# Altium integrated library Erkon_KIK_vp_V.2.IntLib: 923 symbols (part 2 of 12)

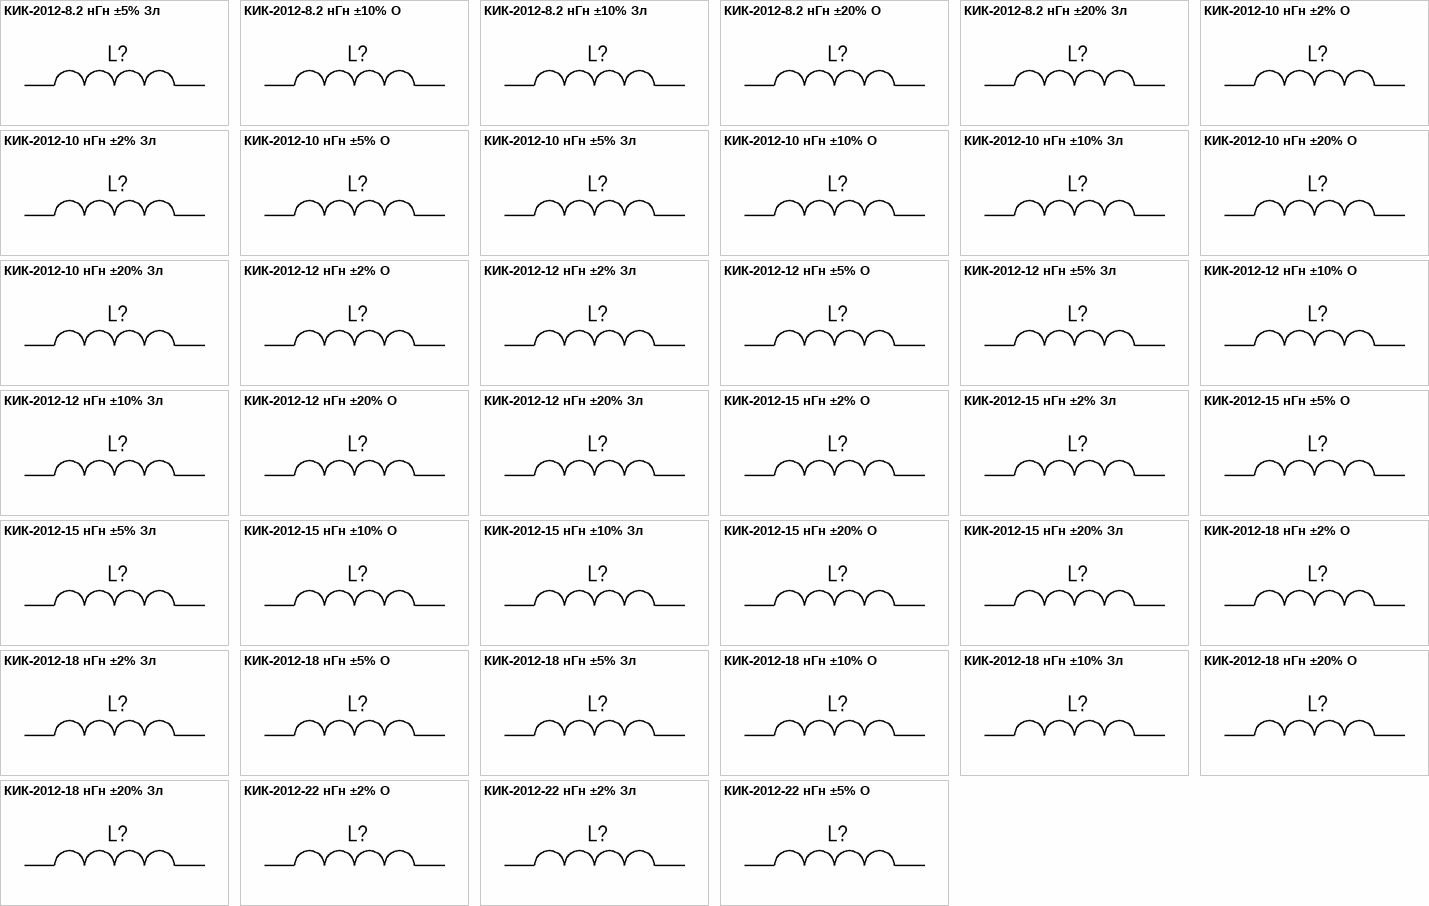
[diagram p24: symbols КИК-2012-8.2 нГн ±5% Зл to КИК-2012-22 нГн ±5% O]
## КИК-2012-22 нГн ±5% O
designator L?, comment 22 нГн ±5%  (value not drawn)
Катушка индуктивности с керамическим сердечником и  финишным покрытием контактных площадок оловом; Номиналиная индуктивность: 22 нГн; Добротность, не менее: 50; Резонансная частота, не менее: 2.60 ГГц; Сопротивление обмотки постоянноми току, не более: 0.22 Ом; Допустимый ток обмотки: 500 мА; Диапазон рабочих температур: от -60 до +125 ℃; Упаковка: Катушка и лента; Типоразмер: 2012 (0805); Технология монтажа: SMT; Изготовитель: АО "НПО "ЭРКОН"
footprint КИК-2012-O (Катушка индуктивности с керамическим сердечником типоразмер 2012(0805))
pins: 1, 2


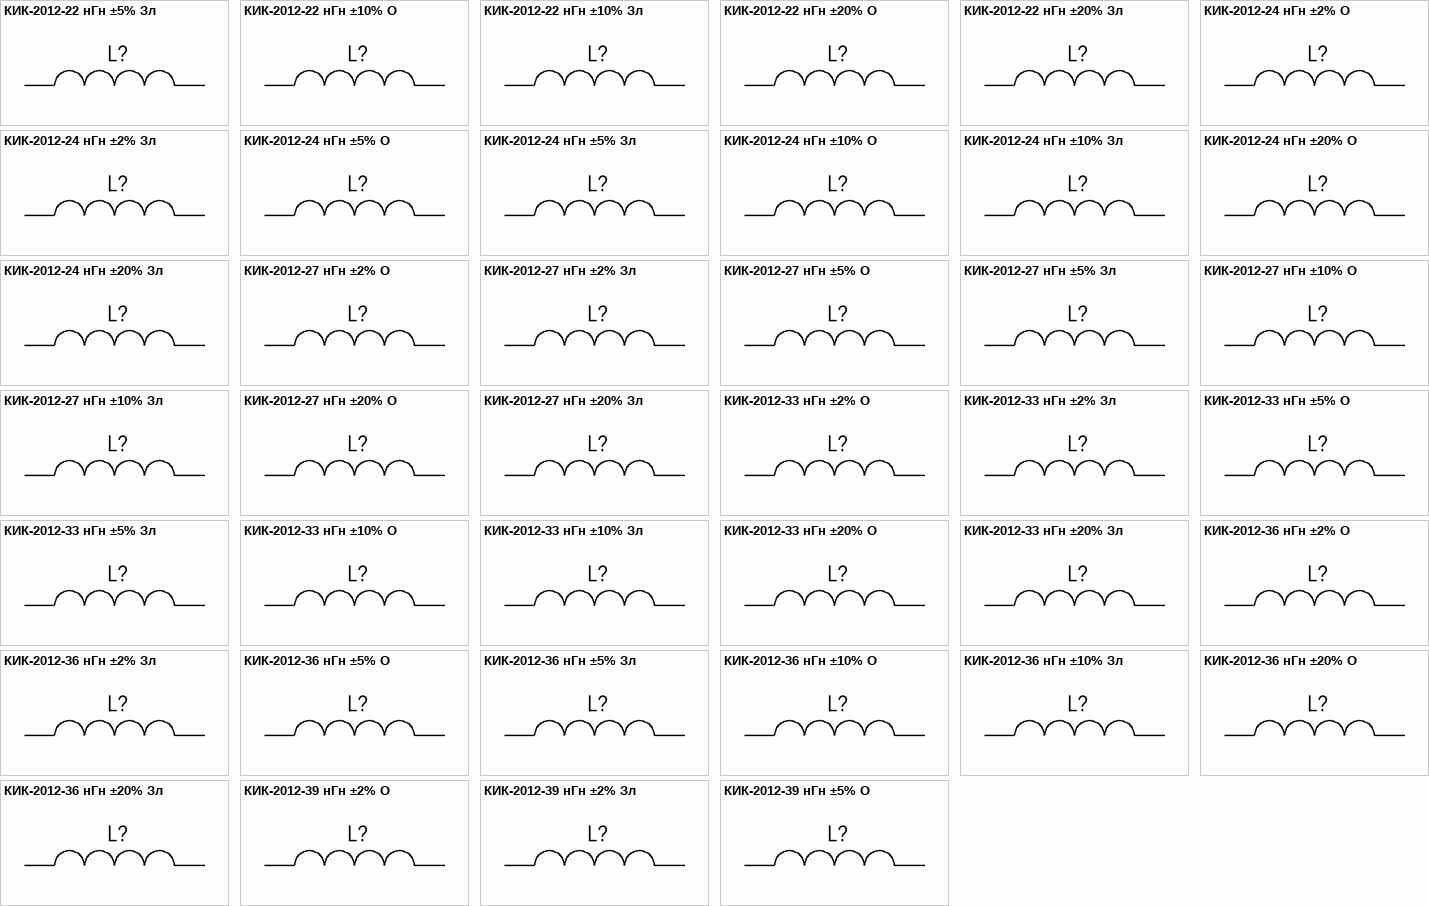
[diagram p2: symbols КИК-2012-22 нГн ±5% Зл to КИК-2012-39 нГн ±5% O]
## КИК-2012-22 нГн ±5% Зл
designator L?, comment 22 нГн ±5%  (value not drawn)
Катушка индуктивности с керамическим сердечником и золотым покрытием контактных площадок; Номиналиная индуктивность: 22 нГн; Добротность, не менее: 50; Резонансная частота, не менее: 2.60 ГГц; Сопротивление обмотки постоянноми току, не более: 0.22 Ом; Допустимый ток обмотки: 500 мА; Диапазон рабочих температур: от -60 до +125 ℃; Упаковка: Катушка и лента; Типоразмер: 2012 (0805); Технология монтажа: SMT; Изготовитель: АО "НПО "ЭРКОН"
footprint КИК-2012-Зл (Катушка индуктивности с керамическим сердечникомтипоразмер 2012(0805))
pins: 1, 2

## КИК-2012-22 нГн ±10% O
designator L?, comment 22 нГн ±10%  (value not drawn)
Катушка индуктивности с керамическим сердечником и  финишным покрытием контактных площадок оловом; Номиналиная индуктивность: 22 нГн; Добротность, не менее: 50; Резонансная частота, не менее: 2.60 ГГц; Сопротивление обмотки постоянноми току, не более: 0.22 Ом; Допустимый ток обмотки: 500 мА; Диапазон рабочих температур: от -60 до +125 ℃; Упаковка: Катушка и лента; Типоразмер: 2012 (0805); Технология монтажа: SMT; Изготовитель: АО "НПО "ЭРКОН"
footprint КИК-2012-O (Катушка индуктивности с керамическим сердечником типоразмер 2012(0805))
pins: 1, 2

## КИК-2012-22 нГн ±10% Зл
designator L?, comment 22 нГн ±10%  (value not drawn)
Катушка индуктивности с керамическим сердечником и золотым покрытием контактных площадок; Номиналиная индуктивность: 22 нГн; Добротность, не менее: 50; Резонансная частота, не менее: 2.60 ГГц; Сопротивление обмотки постоянноми току, не более: 0.22 Ом; Допустимый ток обмотки: 500 мА; Диапазон рабочих температур: от -60 до +125 ℃; Упаковка: Катушка и лента; Типоразмер: 2012 (0805); Технология монтажа: SMT; Изготовитель: АО "НПО "ЭРКОН"
footprint КИК-2012-Зл (Катушка индуктивности с керамическим сердечникомтипоразмер 2012(0805))
pins: 1, 2

## КИК-2012-22 нГн ±20% O
designator L?, comment 22 нГн ±20%  (value not drawn)
Катушка индуктивности с керамическим сердечником и  финишным покрытием контактных площадок оловом; Номиналиная индуктивность: 22 нГн; Добротность, не менее: 50; Резонансная частота, не менее: 2.60 ГГц; Сопротивление обмотки постоянноми току, не более: 0.22 Ом; Допустимый ток обмотки: 500 мА; Диапазон рабочих температур: от -60 до +125 ℃; Упаковка: Катушка и лента; Типоразмер: 2012 (0805); Технология монтажа: SMT; Изготовитель: АО "НПО "ЭРКОН"
footprint КИК-2012-O (Катушка индуктивности с керамическим сердечником типоразмер 2012(0805))
pins: 1, 2

## КИК-2012-22 нГн ±20% Зл
designator L?, comment 22 нГн ±20%  (value not drawn)
Катушка индуктивности с керамическим сердечником и золотым покрытием контактных площадок; Номиналиная индуктивность: 22 нГн; Добротность, не менее: 50; Резонансная частота, не менее: 2.60 ГГц; Сопротивление обмотки постоянноми току, не более: 0.22 Ом; Допустимый ток обмотки: 500 мА; Диапазон рабочих температур: от -60 до +125 ℃; Упаковка: Катушка и лента; Типоразмер: 2012 (0805); Технология монтажа: SMT; Изготовитель: АО "НПО "ЭРКОН"
footprint КИК-2012-Зл (Катушка индуктивности с керамическим сердечникомтипоразмер 2012(0805))
pins: 1, 2

## КИК-2012-24 нГн ±2% O
designator L?, comment 24 нГн ±2%  (value not drawn)
Катушка индуктивности с керамическим сердечником и  финишным покрытием контактных площадок оловом; Номиналиная индуктивность: 24 нГн; Добротность, не менее: 50; Резонансная частота, не менее: 2.40 ГГц; Сопротивление обмотки постоянноми току, не более: 0.22 Ом; Допустимый ток обмотки: 500 мА; Диапазон рабочих температур: от -60 до +125 ℃; Упаковка: Катушка и лента; Типоразмер: 2012 (0805); Технология монтажа: SMT; Изготовитель: АО "НПО "ЭРКОН"
footprint КИК-2012-O (Катушка индуктивности с керамическим сердечником типоразмер 2012(0805))
pins: 1, 2

## КИК-2012-24 нГн ±2% Зл
designator L?, comment 24 нГн ±2%  (value not drawn)
Катушка индуктивности с керамическим сердечником и золотым покрытием контактных площадок; Номиналиная индуктивность: 24 нГн; Добротность, не менее: 50; Резонансная частота, не менее: 2.40 ГГц; Сопротивление обмотки постоянноми току, не более: 0.22 Ом; Допустимый ток обмотки: 500 мА; Диапазон рабочих температур: от -60 до +125 ℃; Упаковка: Катушка и лента; Типоразмер: 2012 (0805); Технология монтажа: SMT; Изготовитель: АО "НПО "ЭРКОН"
footprint КИК-2012-Зл (Катушка индуктивности с керамическим сердечникомтипоразмер 2012(0805))
pins: 1, 2

## КИК-2012-24 нГн ±5% O
designator L?, comment 24 нГн ±5%  (value not drawn)
Катушка индуктивности с керамическим сердечником и  финишным покрытием контактных площадок оловом; Номиналиная индуктивность: 24 нГн; Добротность, не менее: 50; Резонансная частота, не менее: 2.40 ГГц; Сопротивление обмотки постоянноми току, не более: 0.22 Ом; Допустимый ток обмотки: 500 мА; Диапазон рабочих температур: от -60 до +125 ℃; Упаковка: Катушка и лента; Типоразмер: 2012 (0805); Технология монтажа: SMT; Изготовитель: АО "НПО "ЭРКОН"
footprint КИК-2012-O (Катушка индуктивности с керамическим сердечником типоразмер 2012(0805))
pins: 1, 2

## КИК-2012-24 нГн ±5% Зл
designator L?, comment 24 нГн ±5%  (value not drawn)
Катушка индуктивности с керамическим сердечником и золотым покрытием контактных площадок; Номиналиная индуктивность: 24 нГн; Добротность, не менее: 50; Резонансная частота, не менее: 2.40 ГГц; Сопротивление обмотки постоянноми току, не более: 0.22 Ом; Допустимый ток обмотки: 500 мА; Диапазон рабочих температур: от -60 до +125 ℃; Упаковка: Катушка и лента; Типоразмер: 2012 (0805); Технология монтажа: SMT; Изготовитель: АО "НПО "ЭРКОН"
footprint КИК-2012-Зл (Катушка индуктивности с керамическим сердечникомтипоразмер 2012(0805))
pins: 1, 2

## КИК-2012-24 нГн ±10% O
designator L?, comment 24 нГн ±10%  (value not drawn)
Катушка индуктивности с керамическим сердечником и  финишным покрытием контактных площадок оловом; Номиналиная индуктивность: 24 нГн; Добротность, не менее: 50; Резонансная частота, не менее: 2.40 ГГц; Сопротивление обмотки постоянноми току, не более: 0.22 Ом; Допустимый ток обмотки: 500 мА; Диапазон рабочих температур: от -60 до +125 ℃; Упаковка: Катушка и лента; Типоразмер: 2012 (0805); Технология монтажа: SMT; Изготовитель: АО "НПО "ЭРКОН"
footprint КИК-2012-O (Катушка индуктивности с керамическим сердечником типоразмер 2012(0805))
pins: 1, 2

## КИК-2012-24 нГн ±10% Зл
designator L?, comment 24 нГн ±10%  (value not drawn)
Катушка индуктивности с керамическим сердечником и золотым покрытием контактных площадок; Номиналиная индуктивность: 24 нГн; Добротность, не менее: 50; Резонансная частота, не менее: 2.40 ГГц; Сопротивление обмотки постоянноми току, не более: 0.22 Ом; Допустимый ток обмотки: 500 мА; Диапазон рабочих температур: от -60 до +125 ℃; Упаковка: Катушка и лента; Типоразмер: 2012 (0805); Технология монтажа: SMT; Изготовитель: АО "НПО "ЭРКОН"
footprint КИК-2012-Зл (Катушка индуктивности с керамическим сердечникомтипоразмер 2012(0805))
pins: 1, 2

## КИК-2012-24 нГн ±20% O
designator L?, comment 24 нГн ±20%  (value not drawn)
Катушка индуктивности с керамическим сердечником и  финишным покрытием контактных площадок оловом; Номиналиная индуктивность: 24 нГн; Добротность, не менее: 50; Резонансная частота, не менее: 2.40 ГГц; Сопротивление обмотки постоянноми току, не более: 0.22 Ом; Допустимый ток обмотки: 500 мА; Диапазон рабочих температур: от -60 до +125 ℃; Упаковка: Катушка и лента; Типоразмер: 2012 (0805); Технология монтажа: SMT; Изготовитель: АО "НПО "ЭРКОН"
footprint КИК-2012-O (Катушка индуктивности с керамическим сердечником типоразмер 2012(0805))
pins: 1, 2

## КИК-2012-24 нГн ±20% Зл
designator L?, comment 24 нГн ±20%  (value not drawn)
Катушка индуктивности с керамическим сердечником и золотым покрытием контактных площадок; Номиналиная индуктивность: 24 нГн; Добротность, не менее: 50; Резонансная частота, не менее: 2.40 ГГц; Сопротивление обмотки постоянноми току, не более: 0.22 Ом; Допустимый ток обмотки: 500 мА; Диапазон рабочих температур: от -60 до +125 ℃; Упаковка: Катушка и лента; Типоразмер: 2012 (0805); Технология монтажа: SMT; Изготовитель: АО "НПО "ЭРКОН"
footprint КИК-2012-Зл (Катушка индуктивности с керамическим сердечникомтипоразмер 2012(0805))
pins: 1, 2

## КИК-2012-27 нГн ±2% O
designator L?, comment 27 нГн ±2%  (value not drawn)
Катушка индуктивности с керамическим сердечником и  финишным покрытием контактных площадок оловом; Номиналиная индуктивность: 27 нГн; Добротность, не менее: 50; Резонансная частота, не менее: 2.58 ГГц; Сопротивление обмотки постоянноми току, не более: 0.25 Ом; Допустимый ток обмотки: 500 мА; Диапазон рабочих температур: от -60 до +125 ℃; Упаковка: Катушка и лента; Типоразмер: 2012 (0805); Технология монтажа: SMT; Изготовитель: АО "НПО "ЭРКОН"
footprint КИК-2012-O (Катушка индуктивности с керамическим сердечником типоразмер 2012(0805))
pins: 1, 2

## КИК-2012-27 нГн ±2% Зл
designator L?, comment 27 нГн ±2%  (value not drawn)
Катушка индуктивности с керамическим сердечником и золотым покрытием контактных площадок; Номиналиная индуктивность: 27 нГн; Добротность, не менее: 50; Резонансная частота, не менее: 2.58 ГГц; Сопротивление обмотки постоянноми току, не более: 0.25 Ом; Допустимый ток обмотки: 500 мА; Диапазон рабочих температур: от -60 до +125 ℃; Упаковка: Катушка и лента; Типоразмер: 2012 (0805); Технология монтажа: SMT; Изготовитель: АО "НПО "ЭРКОН"
footprint КИК-2012-Зл (Катушка индуктивности с керамическим сердечникомтипоразмер 2012(0805))
pins: 1, 2

## КИК-2012-27 нГн ±5% O
designator L?, comment 27 нГн ±5%  (value not drawn)
Катушка индуктивности с керамическим сердечником и  финишным покрытием контактных площадок оловом; Номиналиная индуктивность: 27 нГн; Добротность, не менее: 50; Резонансная частота, не менее: 2.58 ГГц; Сопротивление обмотки постоянноми току, не более: 0.25 Ом; Допустимый ток обмотки: 500 мА; Диапазон рабочих температур: от -60 до +125 ℃; Упаковка: Катушка и лента; Типоразмер: 2012 (0805); Технология монтажа: SMT; Изготовитель: АО "НПО "ЭРКОН"
footprint КИК-2012-O (Катушка индуктивности с керамическим сердечником типоразмер 2012(0805))
pins: 1, 2

## КИК-2012-27 нГн ±5% Зл
designator L?, comment 27 нГн ±5%  (value not drawn)
Катушка индуктивности с керамическим сердечником и золотым покрытием контактных площадок; Номиналиная индуктивность: 27 нГн; Добротность, не менее: 50; Резонансная частота, не менее: 2.58 ГГц; Сопротивление обмотки постоянноми току, не более: 0.25 Ом; Допустимый ток обмотки: 500 мА; Диапазон рабочих температур: от -60 до +125 ℃; Упаковка: Катушка и лента; Типоразмер: 2012 (0805); Технология монтажа: SMT; Изготовитель: АО "НПО "ЭРКОН"
footprint КИК-2012-Зл (Катушка индуктивности с керамическим сердечникомтипоразмер 2012(0805))
pins: 1, 2

## КИК-2012-27 нГн ±10% O
designator L?, comment 27 нГн ±10%  (value not drawn)
Катушка индуктивности с керамическим сердечником и  финишным покрытием контактных площадок оловом; Номиналиная индуктивность: 27 нГн; Добротность, не менее: 50; Резонансная частота, не менее: 2.58 ГГц; Сопротивление обмотки постоянноми току, не более: 0.25 Ом; Допустимый ток обмотки: 500 мА; Диапазон рабочих температур: от -60 до +125 ℃; Упаковка: Катушка и лента; Типоразмер: 2012 (0805); Технология монтажа: SMT; Изготовитель: АО "НПО "ЭРКОН"
footprint КИК-2012-O (Катушка индуктивности с керамическим сердечником типоразмер 2012(0805))
pins: 1, 2

## КИК-2012-27 нГн ±10% Зл
designator L?, comment 27 нГн ±10%  (value not drawn)
Катушка индуктивности с керамическим сердечником и золотым покрытием контактных площадок; Номиналиная индуктивность: 27 нГн; Добротность, не менее: 50; Резонансная частота, не менее: 2.58 ГГц; Сопротивление обмотки постоянноми току, не более: 0.25 Ом; Допустимый ток обмотки: 500 мА; Диапазон рабочих температур: от -60 до +125 ℃; Упаковка: Катушка и лента; Типоразмер: 2012 (0805); Технология монтажа: SMT; Изготовитель: АО "НПО "ЭРКОН"
footprint КИК-2012-Зл (Катушка индуктивности с керамическим сердечникомтипоразмер 2012(0805))
pins: 1, 2

## КИК-2012-27 нГн ±20% O
designator L?, comment 27 нГн ±20%  (value not drawn)
Катушка индуктивности с керамическим сердечником и  финишным покрытием контактных площадок оловом; Номиналиная индуктивность: 27 нГн; Добротность, не менее: 50; Резонансная частота, не менее: 2.58 ГГц; Сопротивление обмотки постоянноми току, не более: 0.25 Ом; Допустимый ток обмотки: 500 мА; Диапазон рабочих температур: от -60 до +125 ℃; Упаковка: Катушка и лента; Типоразмер: 2012 (0805); Технология монтажа: SMT; Изготовитель: АО "НПО "ЭРКОН"
footprint КИК-2012-O (Катушка индуктивности с керамическим сердечником типоразмер 2012(0805))
pins: 1, 2

## КИК-2012-27 нГн ±20% Зл
designator L?, comment 27 нГн ±20%  (value not drawn)
Катушка индуктивности с керамическим сердечником и золотым покрытием контактных площадок; Номиналиная индуктивность: 27 нГн; Добротность, не менее: 50; Резонансная частота, не менее: 2.58 ГГц; Сопротивление обмотки постоянноми току, не более: 0.25 Ом; Допустимый ток обмотки: 500 мА; Диапазон рабочих температур: от -60 до +125 ℃; Упаковка: Катушка и лента; Типоразмер: 2012 (0805); Технология монтажа: SMT; Изготовитель: АО "НПО "ЭРКОН"
footprint КИК-2012-Зл (Катушка индуктивности с керамическим сердечникомтипоразмер 2012(0805))
pins: 1, 2

## КИК-2012-33 нГн ±2% O
designator L?, comment 33 нГн ±2%  (value not drawn)
Катушка индуктивности с керамическим сердечником и  финишным покрытием контактных площадок оловом; Номиналиная индуктивность: 33 нГн; Добротность, не менее: 50; Резонансная частота, не менее: 2.15 ГГц; Сопротивление обмотки постоянноми току, не более: 0.27 Ом; Допустимый ток обмотки: 500 мА; Диапазон рабочих температур: от -60 до +125 ℃; Упаковка: Катушка и лента; Типоразмер: 2012 (0805); Технология монтажа: SMT; Изготовитель: АО "НПО "ЭРКОН"
footprint КИК-2012-O (Катушка индуктивности с керамическим сердечником типоразмер 2012(0805))
pins: 1, 2

## КИК-2012-33 нГн ±2% Зл
designator L?, comment 33 нГн ±2%  (value not drawn)
Катушка индуктивности с керамическим сердечником и золотым покрытием контактных площадок; Номиналиная индуктивность: 33 нГн; Допускаемое отклонение индуктивности: ±5%; Добротность, не менее: 50; Резонансная частота, не менее: 2.15 ГГц; Сопротивление обмотки постоянноми току, не более: 0.27 Ом; Допустимый ток обмотки: 500 мА; Диапазон рабочих температур: от -60 до +125 ℃; Упаковка: Катушка и лента; Типоразмер: 2012 (0805); Технология монтажа: SMT; Изготовитель: АО "НПО "ЭРКОН"
footprint КИК-2012-Зл (Катушка индуктивности с керамическим сердечникомтипоразмер 2012(0805))
pins: 1, 2

## КИК-2012-33 нГн ±5% O
designator L?, comment 33 нГн ±5%  (value not drawn)
Катушка индуктивности с керамическим сердечником и  финишным покрытием контактных площадок оловом; Номиналиная индуктивность: 33 нГн; Добротность, не менее: 50; Резонансная частота, не менее: 2.15 ГГц; Сопротивление обмотки постоянноми току, не более: 0.27 Ом; Допустимый ток обмотки: 500 мА; Диапазон рабочих температур: от -60 до +125 ℃; Упаковка: Катушка и лента; Типоразмер: 2012 (0805); Технология монтажа: SMT; Изготовитель: АО "НПО "ЭРКОН"
footprint КИК-2012-O (Катушка индуктивности с керамическим сердечником типоразмер 2012(0805))
pins: 1, 2

## КИК-2012-33 нГн ±5% Зл
designator L?, comment 33 нГн ±5%  (value not drawn)
Катушка индуктивности с керамическим сердечником и золотым покрытием контактных площадок; Номиналиная индуктивность: 33 нГн; Добротность, не менее: 50; Резонансная частота, не менее: 2.15 ГГц; Сопротивление обмотки постоянноми току, не более: 0.27 Ом; Допустимый ток обмотки: 500 мА; Диапазон рабочих температур: от -60 до +125 ℃; Упаковка: Катушка и лента; Типоразмер: 2012 (0805); Технология монтажа: SMT; Изготовитель: АО "НПО "ЭРКОН"
footprint КИК-2012-Зл (Катушка индуктивности с керамическим сердечникомтипоразмер 2012(0805))
pins: 1, 2

## КИК-2012-33 нГн ±10% O
designator L?, comment 33 нГн ±10%  (value not drawn)
Катушка индуктивности с керамическим сердечником и  финишным покрытием контактных площадок оловом; Номиналиная индуктивность: 33 нГн; Добротность, не менее: 50; Резонансная частота, не менее: 2.15 ГГц; Сопротивление обмотки постоянноми току, не более: 0.27 Ом; Допустимый ток обмотки: 500 мА; Диапазон рабочих температур: от -60 до +125 ℃; Упаковка: Катушка и лента; Типоразмер: 2012 (0805); Технология монтажа: SMT; Изготовитель: АО "НПО "ЭРКОН"
footprint КИК-2012-O (Катушка индуктивности с керамическим сердечником типоразмер 2012(0805))
pins: 1, 2

## КИК-2012-33 нГн ±10% Зл
designator L?, comment 33 нГн ±10%  (value not drawn)
Катушка индуктивности с керамическим сердечником и золотым покрытием контактных площадок; Номиналиная индуктивность: 33 нГн; Добротность, не менее: 50; Резонансная частота, не менее: 2.15 ГГц; Сопротивление обмотки постоянноми току, не более: 0.27 Ом; Допустимый ток обмотки: 500 мА; Диапазон рабочих температур: от -60 до +125 ℃; Упаковка: Катушка и лента; Типоразмер: 2012 (0805); Технология монтажа: SMT; Изготовитель: АО "НПО "ЭРКОН"
footprint КИК-2012-Зл (Катушка индуктивности с керамическим сердечникомтипоразмер 2012(0805))
pins: 1, 2

## КИК-2012-33 нГн ±20% O
designator L?, comment 33 нГн ±20%  (value not drawn)
Катушка индуктивности с керамическим сердечником и  финишным покрытием контактных площадок оловом; Номиналиная индуктивность: 33 нГн; Добротность, не менее: 50; Резонансная частота, не менее: 2.15 ГГц; Сопротивление обмотки постоянноми току, не более: 0.27 Ом; Допустимый ток обмотки: 500 мА; Диапазон рабочих температур: от -60 до +125 ℃; Упаковка: Катушка и лента; Типоразмер: 2012 (0805); Технология монтажа: SMT; Изготовитель: АО "НПО "ЭРКОН"
footprint КИК-2012-O (Катушка индуктивности с керамическим сердечником типоразмер 2012(0805))
pins: 1, 2

## КИК-2012-33 нГн ±20% Зл
designator L?, comment 33 нГн ±20%  (value not drawn)
Катушка индуктивности с керамическим сердечником и золотым покрытием контактных площадок; Номиналиная индуктивность: 33 нГн; Добротность, не менее: 50; Резонансная частота, не менее: 2.15 ГГц; Сопротивление обмотки постоянноми току, не более: 0.27 Ом; Допустимый ток обмотки: 500 мА; Диапазон рабочих температур: от -60 до +125 ℃; Упаковка: Катушка и лента; Типоразмер: 2012 (0805); Технология монтажа: SMT; Изготовитель: АО "НПО "ЭРКОН"
footprint КИК-2012-Зл (Катушка индуктивности с керамическим сердечникомтипоразмер 2012(0805))
pins: 1, 2

## КИК-2012-36 нГн ±2% O
designator L?, comment 36 нГн ±2%  (value not drawn)
Катушка индуктивности с керамическим сердечником и  финишным покрытием контактных площадок оловом; Номиналиная индуктивность: 36 нГн; Добротность, не менее: 50; Резонансная частота, не менее: 1.90 ГГц; Сопротивление обмотки постоянноми току, не более: 0.27 Ом; Допустимый ток обмотки: 500 мА; Диапазон рабочих температур: от -60 до +125 ℃; Упаковка: Катушка и лента; Типоразмер: 2012 (0805); Технология монтажа: SMT; Изготовитель: АО "НПО "ЭРКОН"
footprint КИК-2012-O (Катушка индуктивности с керамическим сердечником типоразмер 2012(0805))
pins: 1, 2

## КИК-2012-36 нГн ±2% Зл
designator L?, comment 36 нГн ±2%  (value not drawn)
Катушка индуктивности с керамическим сердечником и золотым покрытием контактных площадок; Номиналиная индуктивность: 36 нГн; Добротность, не менее: 50; Резонансная частота, не менее: 1.90 ГГц; Сопротивление обмотки постоянноми току, не более: 0.27 Ом; Допустимый ток обмотки: 500 мА; Диапазон рабочих температур: от -60 до +125 ℃; Упаковка: Катушка и лента; Типоразмер: 2012 (0805); Технология монтажа: SMT; Изготовитель: АО "НПО "ЭРКОН"
footprint КИК-2012-Зл (Катушка индуктивности с керамическим сердечникомтипоразмер 2012(0805))
pins: 1, 2

## КИК-2012-36 нГн ±5% O
designator L?, comment 36 нГн ±5%  (value not drawn)
Катушка индуктивности с керамическим сердечником и  финишным покрытием контактных площадок оловом; Номиналиная индуктивность: 36 нГн; Добротность, не менее: 50; Резонансная частота, не менее: 1.90 ГГц; Сопротивление обмотки постоянноми току, не более: 0.27 Ом; Допустимый ток обмотки: 500 мА; Диапазон рабочих температур: от -60 до +125 ℃; Упаковка: Катушка и лента; Типоразмер: 2012 (0805); Технология монтажа: SMT; Изготовитель: АО "НПО "ЭРКОН"
footprint КИК-2012-O (Катушка индуктивности с керамическим сердечником типоразмер 2012(0805))
pins: 1, 2

## КИК-2012-36 нГн ±5% Зл
designator L?, comment 36 нГн ±5%  (value not drawn)
Катушка индуктивности с керамическим сердечником и золотым покрытием контактных площадок; Номиналиная индуктивность: 36 нГн; Добротность, не менее: 50; Резонансная частота, не менее: 1.90 ГГц; Сопротивление обмотки постоянноми току, не более: 0.27 Ом; Допустимый ток обмотки: 500 мА; Диапазон рабочих температур: от -60 до +125 ℃; Упаковка: Катушка и лента; Типоразмер: 2012 (0805); Технология монтажа: SMT; Изготовитель: АО "НПО "ЭРКОН"
footprint КИК-2012-Зл (Катушка индуктивности с керамическим сердечникомтипоразмер 2012(0805))
pins: 1, 2

## КИК-2012-36 нГн ±10% O
designator L?, comment 36 нГн ±10%  (value not drawn)
Катушка индуктивности с керамическим сердечником и  финишным покрытием контактных площадок оловом; Номиналиная индуктивность: 36 нГн; Добротность, не менее: 50; Резонансная частота, не менее: 1.90 ГГц; Сопротивление обмотки постоянноми току, не более: 0.27 Ом; Допустимый ток обмотки: 500 мА; Диапазон рабочих температур: от -60 до +125 ℃; Упаковка: Катушка и лента; Типоразмер: 2012 (0805); Технология монтажа: SMT; Изготовитель: АО "НПО "ЭРКОН"
footprint КИК-2012-O (Катушка индуктивности с керамическим сердечником типоразмер 2012(0805))
pins: 1, 2

## КИК-2012-36 нГн ±10% Зл
designator L?, comment 36 нГн ±10%  (value not drawn)
Катушка индуктивности с керамическим сердечником и золотым покрытием контактных площадок; Номиналиная индуктивность: 36 нГн; Добротность, не менее: 50; Резонансная частота, не менее: 1.90 ГГц; Сопротивление обмотки постоянноми току, не более: 0.27 Ом; Допустимый ток обмотки: 500 мА; Диапазон рабочих температур: от -60 до +125 ℃; Упаковка: Катушка и лента; Типоразмер: 2012 (0805); Технология монтажа: SMT; Изготовитель: АО "НПО "ЭРКОН"
footprint КИК-2012-Зл (Катушка индуктивности с керамическим сердечникомтипоразмер 2012(0805))
pins: 1, 2

## КИК-2012-36 нГн ±20% O
designator L?, comment 36 нГн ±20%  (value not drawn)
Катушка индуктивности с керамическим сердечником и  финишным покрытием контактных площадок оловом; Номиналиная индуктивность: 36 нГн; Добротность, не менее: 50; Резонансная частота, не менее: 1.90 ГГц; Сопротивление обмотки постоянноми току, не более: 0.27 Ом; Допустимый ток обмотки: 500 мА; Диапазон рабочих температур: от -60 до +125 ℃; Упаковка: Катушка и лента; Типоразмер: 2012 (0805); Технология монтажа: SMT; Изготовитель: АО "НПО "ЭРКОН"
footprint КИК-2012-O (Катушка индуктивности с керамическим сердечником типоразмер 2012(0805))
pins: 1, 2

## КИК-2012-36 нГн ±20% Зл
designator L?, comment 36 нГн ±20%  (value not drawn)
Катушка индуктивности с керамическим сердечником и золотым покрытием контактных площадок; Номиналиная индуктивность: 36 нГн; Добротность, не менее: 50; Резонансная частота, не менее: 1.90 ГГц; Сопротивление обмотки постоянноми току, не более: 0.27 Ом; Допустимый ток обмотки: 500 мА; Диапазон рабочих температур: от -60 до +125 ℃; Упаковка: Катушка и лента; Типоразмер: 2012 (0805); Технология монтажа: SMT; Изготовитель: АО "НПО "ЭРКОН"
footprint КИК-2012-Зл (Катушка индуктивности с керамическим сердечникомтипоразмер 2012(0805))
pins: 1, 2

## КИК-2012-39 нГн ±2% O
designator L?, comment 39 нГн ±2%  (value not drawn)
Катушка индуктивности с керамическим сердечником и  финишным покрытием контактных площадок оловом; Номиналиная индуктивность: 39 нГн; Добротность, не менее: 60; Резонансная частота, не менее: 2.0 ГГц; Сопротивление обмотки постоянноми току, не более: 0.29 Ом; Допустимый ток обмотки: 500 мА; Диапазон рабочих температур: от -60 до +125 ℃; Упаковка: Катушка и лента; Типоразмер: 2012 (0805); Технология монтажа: SMT; Изготовитель: АО "НПО "ЭРКОН"
footprint КИК-2012-O (Катушка индуктивности с керамическим сердечником типоразмер 2012(0805))
pins: 1, 2

## КИК-2012-39 нГн ±2% Зл
designator L?, comment 39 нГн ±2%  (value not drawn)
Катушка индуктивности с керамическим сердечником и золотым покрытием контактных площадок; Номиналиная индуктивность: 39 нГн; Добротность, не менее: 60; Резонансная частота, не менее: 2.0 ГГц; Сопротивление обмотки постоянноми току, не более: 0.29 Ом; Допустимый ток обмотки: 500 мА; Диапазон рабочих температур: от -60 до +125 ℃; Упаковка: Катушка и лента; Типоразмер: 2012 (0805); Технология монтажа: SMT; Изготовитель: АО "НПО "ЭРКОН"
footprint КИК-2012-Зл (Катушка индуктивности с керамическим сердечникомтипоразмер 2012(0805))
pins: 1, 2

## КИК-2012-39 нГн ±5% O
designator L?, comment 39 нГн ±5%  (value not drawn)
Катушка индуктивности с керамическим сердечником и  финишным покрытием контактных площадок оловом; Номиналиная индуктивность: 39 нГн; Добротность, не менее: 60; Резонансная частота, не менее: 2.0 ГГц; Сопротивление обмотки постоянноми току, не более: 0.29 Ом; Допустимый ток обмотки: 500 мА; Диапазон рабочих температур: от -60 до +125 ℃; Упаковка: Катушка и лента; Типоразмер: 2012 (0805); Технология монтажа: SMT; Изготовитель: АО "НПО "ЭРКОН"
footprint КИК-2012-O (Катушка индуктивности с керамическим сердечником типоразмер 2012(0805))
pins: 1, 2


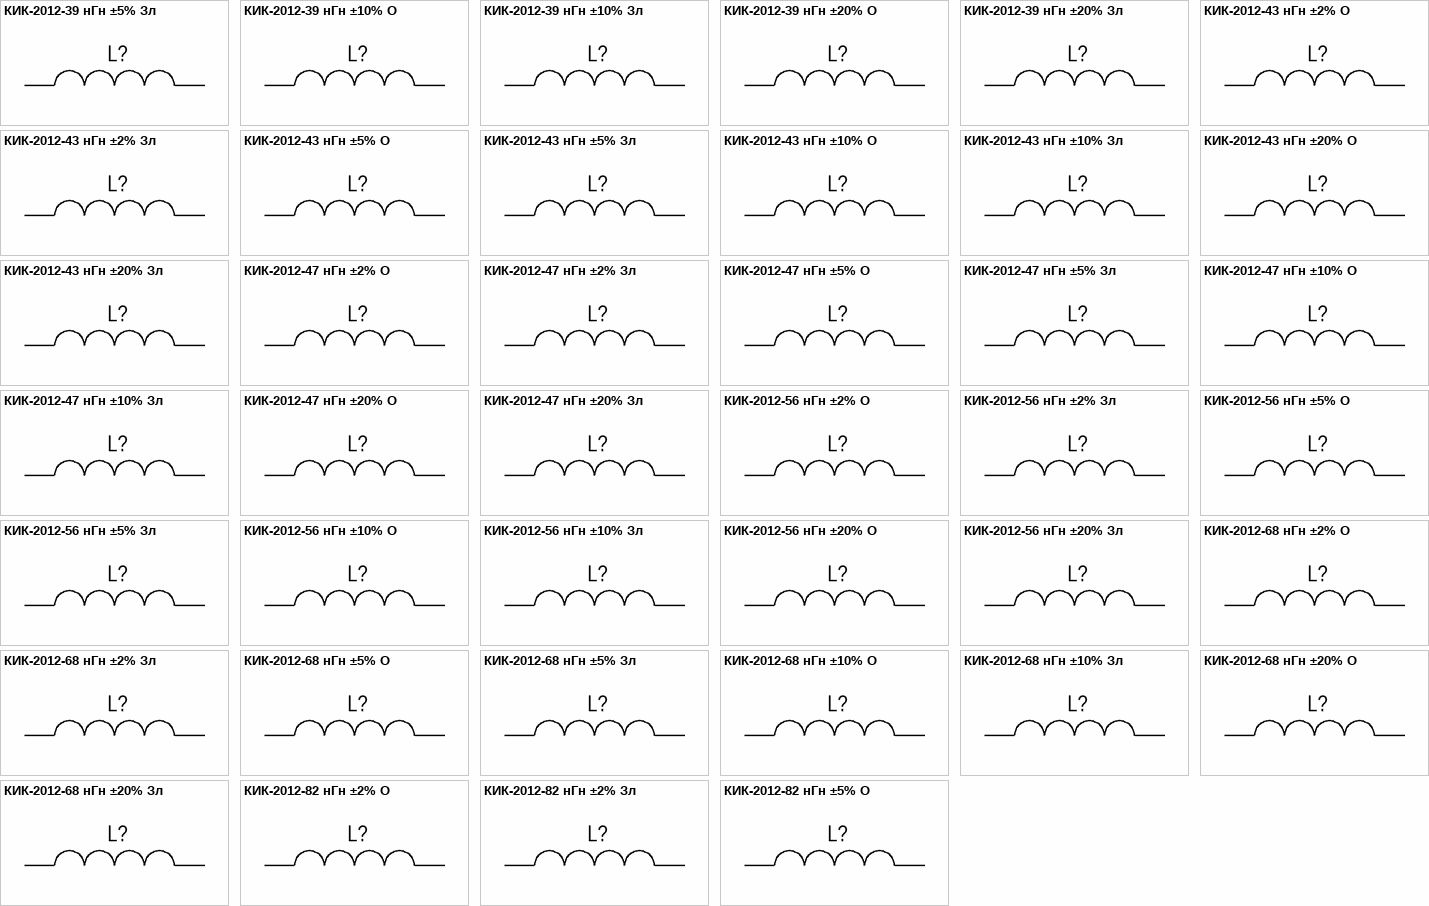
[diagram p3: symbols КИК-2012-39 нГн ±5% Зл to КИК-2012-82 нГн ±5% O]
## КИК-2012-39 нГн ±5% Зл
designator L?, comment 39 нГн ±5%  (value not drawn)
Катушка индуктивности с керамическим сердечником и золотым покрытием контактных площадок; Номиналиная индуктивность: 39 нГн; Добротность, не менее: 60; Резонансная частота, не менее: 2.0 ГГц; Сопротивление обмотки постоянноми току, не более: 0.29 Ом; Допустимый ток обмотки: 500 мА; Диапазон рабочих температур: от -60 до +125 ℃; Упаковка: Катушка и лента; Типоразмер: 2012 (0805); Технология монтажа: SMT; Изготовитель: АО "НПО "ЭРКОН"
footprint КИК-2012-Зл (Катушка индуктивности с керамическим сердечникомтипоразмер 2012(0805))
pins: 1, 2

## КИК-2012-39 нГн ±10% O
designator L?, comment 39 нГн ±10%  (value not drawn)
Катушка индуктивности с керамическим сердечником и  финишным покрытием контактных площадок оловом; Номиналиная индуктивность: 39 нГн; Добротность, не менее: 60; Резонансная частота, не менее: 2.0 ГГц; Сопротивление обмотки постоянноми току, не более: 0.29 Ом; Допустимый ток обмотки: 500 мА; Диапазон рабочих температур: от -60 до +125 ℃; Упаковка: Катушка и лента; Типоразмер: 2012 (0805); Технология монтажа: SMT; Изготовитель: АО "НПО "ЭРКОН"
footprint КИК-2012-O (Катушка индуктивности с керамическим сердечником типоразмер 2012(0805))
pins: 1, 2

## КИК-2012-39 нГн ±10% Зл
designator L?, comment 39 нГн ±10%  (value not drawn)
Катушка индуктивности с керамическим сердечником и золотым покрытием контактных площадок; Номиналиная индуктивность: 39 нГн; Добротность, не менее: 60; Резонансная частота, не менее: 2.0 ГГц; Сопротивление обмотки постоянноми току, не более: 0.29 Ом; Допустимый ток обмотки: 500 мА; Диапазон рабочих температур: от -60 до +125 ℃; Упаковка: Катушка и лента; Типоразмер: 2012 (0805); Технология монтажа: SMT; Изготовитель: АО "НПО "ЭРКОН"
footprint КИК-2012-Зл (Катушка индуктивности с керамическим сердечникомтипоразмер 2012(0805))
pins: 1, 2

## КИК-2012-39 нГн ±20% O
designator L?, comment 39 нГн ±20%  (value not drawn)
Катушка индуктивности с керамическим сердечником и  финишным покрытием контактных площадок оловом; Номиналиная индуктивность: 39 нГн; Добротность, не менее: 60; Резонансная частота, не менее: 2.0 ГГц; Сопротивление обмотки постоянноми току, не более: 0.29 Ом; Допустимый ток обмотки: 500 мА; Диапазон рабочих температур: от -60 до +125 ℃; Упаковка: Катушка и лента; Типоразмер: 2012 (0805); Технология монтажа: SMT; Изготовитель: АО "НПО "ЭРКОН"
footprint КИК-2012-O (Катушка индуктивности с керамическим сердечником типоразмер 2012(0805))
pins: 1, 2

## КИК-2012-39 нГн ±20% Зл
designator L?, comment 39 нГн ±20%  (value not drawn)
Катушка индуктивности с керамическим сердечником и золотым покрытием контактных площадок; Номиналиная индуктивность: 39 нГн; Добротность, не менее: 60; Резонансная частота, не менее: 2.0 ГГц; Сопротивление обмотки постоянноми току, не более: 0.29 Ом; Допустимый ток обмотки: 500 мА; Диапазон рабочих температур: от -60 до +125 ℃; Упаковка: Катушка и лента; Типоразмер: 2012 (0805); Технология монтажа: SMT; Изготовитель: АО "НПО "ЭРКОН"
footprint КИК-2012-Зл (Катушка индуктивности с керамическим сердечникомтипоразмер 2012(0805))
pins: 1, 2

## КИК-2012-43 нГн ±2% O
designator L?, comment 43 нГн ±2%  (value not drawn)
Катушка индуктивности с керамическим сердечником и  финишным покрытием контактных площадок оловом; Номиналиная индуктивность: 43 нГн; Добротность, не менее: 60; Резонансная частота, не менее: 1.8 ГГц; Сопротивление обмотки постоянноми току, не более: 0.34 Ом; Допустимый ток обмотки: 500 мА; Диапазон рабочих температур: от -60 до +125 ℃; Упаковка: Катушка и лента; Типоразмер: 2012 (0805); Технология монтажа: SMT; Изготовитель: АО "НПО "ЭРКОН"
footprint КИК-2012-O (Катушка индуктивности с керамическим сердечником типоразмер 2012(0805))
pins: 1, 2

## КИК-2012-43 нГн ±2% Зл
designator L?, comment 43 нГн ±2%  (value not drawn)
Катушка индуктивности с керамическим сердечником и золотым покрытием контактных площадок; Номиналиная индуктивность: 43 нГн; Добротность, не менее: 60; Резонансная частота, не менее: 1.8 ГГц; Сопротивление обмотки постоянноми току, не более: 0.34 Ом; Допустимый ток обмотки: 500 мА; Диапазон рабочих температур: от -60 до +125 ℃; Упаковка: Катушка и лента; Типоразмер: 2012 (0805); Технология монтажа: SMT; Изготовитель: АО "НПО "ЭРКОН"
footprint КИК-2012-Зл (Катушка индуктивности с керамическим сердечникомтипоразмер 2012(0805))
pins: 1, 2

## КИК-2012-43 нГн ±5% O
designator L?, comment 43 нГн ±5%  (value not drawn)
Катушка индуктивности с керамическим сердечником и  финишным покрытием контактных площадок оловом; Номиналиная индуктивность: 43 нГн; Добротность, не менее: 60; Резонансная частота, не менее: 1.8 ГГц; Сопротивление обмотки постоянноми току, не более: 0.34 Ом; Допустимый ток обмотки: 500 мА; Диапазон рабочих температур: от -60 до +125 ℃; Упаковка: Катушка и лента; Типоразмер: 2012 (0805); Технология монтажа: SMT; Изготовитель: АО "НПО "ЭРКОН"
footprint КИК-2012-O (Катушка индуктивности с керамическим сердечником типоразмер 2012(0805))
pins: 1, 2

## КИК-2012-43 нГн ±5% Зл
designator L?, comment 43 нГн ±5%  (value not drawn)
Катушка индуктивности с керамическим сердечником и золотым покрытием контактных площадок; Номиналиная индуктивность: 43 нГн; Добротность, не менее: 60; Резонансная частота, не менее: 1.8 ГГц; Сопротивление обмотки постоянноми току, не более: 0.34 Ом; Допустимый ток обмотки: 500 мА; Диапазон рабочих температур: от -60 до +125 ℃; Упаковка: Катушка и лента; Типоразмер: 2012 (0805); Технология монтажа: SMT; Изготовитель: АО "НПО "ЭРКОН"
footprint КИК-2012-Зл (Катушка индуктивности с керамическим сердечникомтипоразмер 2012(0805))
pins: 1, 2

## КИК-2012-43 нГн ±10% O
designator L?, comment 43 нГн ±10%  (value not drawn)
Катушка индуктивности с керамическим сердечником и  финишным покрытием контактных площадок оловом; Номиналиная индуктивность: 43 нГн; Добротность, не менее: 60; Резонансная частота, не менее: 1.8 ГГц; Сопротивление обмотки постоянноми току, не более: 0.34 Ом; Допустимый ток обмотки: 500 мА; Диапазон рабочих температур: от -60 до +125 ℃; Упаковка: Катушка и лента; Типоразмер: 2012 (0805); Технология монтажа: SMT; Изготовитель: АО "НПО "ЭРКОН"
footprint КИК-2012-O (Катушка индуктивности с керамическим сердечником типоразмер 2012(0805))
pins: 1, 2

## КИК-2012-43 нГн ±10% Зл
designator L?, comment 43 нГн ±10%  (value not drawn)
Катушка индуктивности с керамическим сердечником и золотым покрытием контактных площадок; Номиналиная индуктивность: 43 нГн; Добротность, не менее: 60; Резонансная частота, не менее: 1.8 ГГц; Сопротивление обмотки постоянноми току, не более: 0.34 Ом; Допустимый ток обмотки: 500 мА; Диапазон рабочих температур: от -60 до +125 ℃; Упаковка: Катушка и лента; Типоразмер: 2012 (0805); Технология монтажа: SMT; Изготовитель: АО "НПО "ЭРКОН"
footprint КИК-2012-Зл (Катушка индуктивности с керамическим сердечникомтипоразмер 2012(0805))
pins: 1, 2

## КИК-2012-43 нГн ±20% O
designator L?, comment 43 нГн ±20%  (value not drawn)
Катушка индуктивности с керамическим сердечником и  финишным покрытием контактных площадок оловом; Номиналиная индуктивность: 43 нГн; Добротность, не менее: 60; Резонансная частота, не менее: 1.8 ГГц; Сопротивление обмотки постоянноми току, не более: 0.34 Ом; Допустимый ток обмотки: 500 мА; Диапазон рабочих температур: от -60 до +125 ℃; Упаковка: Катушка и лента; Типоразмер: 2012 (0805); Технология монтажа: SMT; Изготовитель: АО "НПО "ЭРКОН"
footprint КИК-2012-O (Катушка индуктивности с керамическим сердечником типоразмер 2012(0805))
pins: 1, 2

## КИК-2012-43 нГн ±20% Зл
designator L?, comment 43 нГн ±20%  (value not drawn)
Катушка индуктивности с керамическим сердечником и золотым покрытием контактных площадок; Номиналиная индуктивность: 43 нГн; Добротность, не менее: 60; Резонансная частота, не менее: 1.8 ГГц; Сопротивление обмотки постоянноми току, не более: 0.34 Ом; Допустимый ток обмотки: 500 мА; Диапазон рабочих температур: от -60 до +125 ℃; Упаковка: Катушка и лента; Типоразмер: 2012 (0805); Технология монтажа: SMT; Изготовитель: АО "НПО "ЭРКОН"
footprint КИК-2012-Зл (Катушка индуктивности с керамическим сердечникомтипоразмер 2012(0805))
pins: 1, 2

## КИК-2012-47 нГн ±2% O
designator L?, comment 47 нГн ±2%  (value not drawn)
Катушка индуктивности с керамическим сердечником и  финишным покрытием контактных площадок оловом; Номиналиная индуктивность: 47 нГн; Допускаемое отклонение индуктивности: ±5%; Добротность, не менее: 60; Резонансная частота, не менее: 1.7 ГГц; Сопротивление обмотки постоянноми току, не более: 0.31 Ом; Допустимый ток обмотки: 500 мА; Диапазон рабочих температур: от -60 до +125 ℃; Упаковка: Катушка и лента; Типоразмер: 2012 (0805); Технология монтажа: SMT; Изготовитель: АО "НПО "ЭРКОН"
footprint КИК-2012-O (Катушка индуктивности с керамическим сердечником типоразмер 2012(0805))
pins: 1, 2

## КИК-2012-47 нГн ±2% Зл
designator L?, comment 47 нГн ±2%  (value not drawn)
Катушка индуктивности с керамическим сердечником и золотым покрытием контактных площадок; Номиналиная индуктивность: 47 нГн; Добротность, не менее: 60; Резонансная частота, не менее: 1.7 ГГц; Сопротивление обмотки постоянноми току, не более: 0.31 Ом; Допустимый ток обмотки: 500 мА; Диапазон рабочих температур: от -60 до +125 ℃; Упаковка: Катушка и лента; Типоразмер: 2012 (0805); Технология монтажа: SMT; Изготовитель: АО "НПО "ЭРКОН"
footprint КИК-2012-Зл (Катушка индуктивности с керамическим сердечникомтипоразмер 2012(0805))
pins: 1, 2

## КИК-2012-47 нГн ±5% O
designator L?, comment 47 нГн ±5%  (value not drawn)
Катушка индуктивности с керамическим сердечником и  финишным покрытием контактных площадок оловом; Номиналиная индуктивность: 47 нГн; Добротность, не менее: 60; Резонансная частота, не менее: 1.7 ГГц; Сопротивление обмотки постоянноми току, не более: 0.31 Ом; Допустимый ток обмотки: 500 мА; Диапазон рабочих температур: от -60 до +125 ℃; Упаковка: Катушка и лента; Типоразмер: 2012 (0805); Технология монтажа: SMT; Изготовитель: АО "НПО "ЭРКОН"
footprint КИК-2012-O (Катушка индуктивности с керамическим сердечником типоразмер 2012(0805))
pins: 1, 2

## КИК-2012-47 нГн ±5% Зл
designator L?, comment 47 нГн ±5%  (value not drawn)
Катушка индуктивности с керамическим сердечником и золотым покрытием контактных площадок; Номиналиная индуктивность: 47 нГн; Добротность, не менее: 60; Резонансная частота, не менее: 1.7 ГГц; Сопротивление обмотки постоянноми току, не более: 0.31 Ом; Допустимый ток обмотки: 500 мА; Диапазон рабочих температур: от -60 до +125 ℃; Упаковка: Катушка и лента; Типоразмер: 2012 (0805); Технология монтажа: SMT; Изготовитель: АО "НПО "ЭРКОН"
footprint КИК-2012-Зл (Катушка индуктивности с керамическим сердечникомтипоразмер 2012(0805))
pins: 1, 2

## КИК-2012-47 нГн ±10% O
designator L?, comment 47 нГн ±10%  (value not drawn)
Катушка индуктивности с керамическим сердечником и  финишным покрытием контактных площадок оловом; Номиналиная индуктивность: 47 нГн; Добротность, не менее: 60; Резонансная частота, не менее: 1.7 ГГц; Сопротивление обмотки постоянноми току, не более: 0.31 Ом; Допустимый ток обмотки: 500 мА; Диапазон рабочих температур: от -60 до +125 ℃; Упаковка: Катушка и лента; Типоразмер: 2012 (0805); Технология монтажа: SMT; Изготовитель: АО "НПО "ЭРКОН"
footprint КИК-2012-O (Катушка индуктивности с керамическим сердечником типоразмер 2012(0805))
pins: 1, 2

## КИК-2012-47 нГн ±10% Зл
designator L?, comment 47 нГн ±10%  (value not drawn)
Катушка индуктивности с керамическим сердечником и золотым покрытием контактных площадок; Номиналиная индуктивность: 47 нГн; Добротность, не менее: 60; Резонансная частота, не менее: 1.7 ГГц; Сопротивление обмотки постоянноми току, не более: 0.31 Ом; Допустимый ток обмотки: 500 мА; Диапазон рабочих температур: от -60 до +125 ℃; Упаковка: Катушка и лента; Типоразмер: 2012 (0805); Технология монтажа: SMT; Изготовитель: АО "НПО "ЭРКОН"
footprint КИК-2012-Зл (Катушка индуктивности с керамическим сердечникомтипоразмер 2012(0805))
pins: 1, 2

## КИК-2012-47 нГн ±20% O
designator L?, comment 47 нГн ±20%  (value not drawn)
Катушка индуктивности с керамическим сердечником и  финишным покрытием контактных площадок оловом; Номиналиная индуктивность: 47 нГн; Добротность, не менее: 60; Резонансная частота, не менее: 1.7 ГГц; Сопротивление обмотки постоянноми току, не более: 0.31 Ом; Допустимый ток обмотки: 500 мА; Диапазон рабочих температур: от -60 до +125 ℃; Упаковка: Катушка и лента; Типоразмер: 2012 (0805); Технология монтажа: SMT; Изготовитель: АО "НПО "ЭРКОН"
footprint КИК-2012-O (Катушка индуктивности с керамическим сердечником типоразмер 2012(0805))
pins: 1, 2

## КИК-2012-47 нГн ±20% Зл
designator L?, comment 47 нГн ±20%  (value not drawn)
Катушка индуктивности с керамическим сердечником и золотым покрытием контактных площадок; Номиналиная индуктивность: 47 нГн; Добротность, не менее: 60; Резонансная частота, не менее: 1.7 ГГц; Сопротивление обмотки постоянноми току, не более: 0.31 Ом; Допустимый ток обмотки: 500 мА; Диапазон рабочих температур: от -60 до +125 ℃; Упаковка: Катушка и лента; Типоразмер: 2012 (0805); Технология монтажа: SMT; Изготовитель: АО "НПО "ЭРКОН"
footprint КИК-2012-Зл (Катушка индуктивности с керамическим сердечникомтипоразмер 2012(0805))
pins: 1, 2

## КИК-2012-56 нГн ±2% O
designator L?, comment 47 нГн ±2%  (value not drawn)
Катушка индуктивности с керамическим сердечником и  финишным покрытием контактных площадок оловом; Номиналиная индуктивность: 56 нГн; Добротность, не менее: 60; Резонансная частота, не менее: 1.6 ГГц; Сопротивление обмотки постоянноми току, не более: 0.34 Ом; Допустимый ток обмотки: 500 мА; Диапазон рабочих температур: от -60 до +125 ℃; Упаковка: Катушка и лента; Типоразмер: 2012 (0805); Технология монтажа: SMT; Изготовитель: АО "НПО "ЭРКОН"
footprint КИК-2012-O (Катушка индуктивности с керамическим сердечником типоразмер 2012(0805))
pins: 1, 2

## КИК-2012-56 нГн ±2% Зл
designator L?, comment 56 нГн ±2%  (value not drawn)
Катушка индуктивности с керамическим сердечником и золотым покрытием контактных площадок; Номиналиная индуктивность: 56 нГн; Добротность, не менее: 60; Резонансная частота, не менее: 1.6 ГГц; Сопротивление обмотки постоянноми току, не более: 0.34 Ом; Допустимый ток обмотки: 500 мА; Диапазон рабочих температур: от -60 до +125 ℃; Упаковка: Катушка и лента; Типоразмер: 2012 (0805); Технология монтажа: SMT; Изготовитель: АО "НПО "ЭРКОН"
footprint КИК-2012-Зл (Катушка индуктивности с керамическим сердечникомтипоразмер 2012(0805))
pins: 1, 2

## КИК-2012-56 нГн ±5% O
designator L?, comment 47 нГн ±5%  (value not drawn)
Катушка индуктивности с керамическим сердечником и  финишным покрытием контактных площадок оловом; Номиналиная индуктивность: 56 нГн; Добротность, не менее: 60; Резонансная частота, не менее: 1.6 ГГц; Сопротивление обмотки постоянноми току, не более: 0.34 Ом; Допустимый ток обмотки: 500 мА; Диапазон рабочих температур: от -60 до +125 ℃; Упаковка: Катушка и лента; Типоразмер: 2012 (0805); Технология монтажа: SMT; Изготовитель: АО "НПО "ЭРКОН"
footprint КИК-2012-O (Катушка индуктивности с керамическим сердечником типоразмер 2012(0805))
pins: 1, 2

## КИК-2012-56 нГн ±5% Зл
designator L?, comment 56 нГн ±5%  (value not drawn)
Катушка индуктивности с керамическим сердечником и золотым покрытием контактных площадок; Номиналиная индуктивность: 56 нГн; Добротность, не менее: 60; Резонансная частота, не менее: 1.6 ГГц; Сопротивление обмотки постоянноми току, не более: 0.34 Ом; Допустимый ток обмотки: 500 мА; Диапазон рабочих температур: от -60 до +125 ℃; Упаковка: Катушка и лента; Типоразмер: 2012 (0805); Технология монтажа: SMT; Изготовитель: АО "НПО "ЭРКОН"
footprint КИК-2012-Зл (Катушка индуктивности с керамическим сердечникомтипоразмер 2012(0805))
pins: 1, 2

## КИК-2012-56 нГн ±10% O
designator L?, comment 56 нГн ±10%  (value not drawn)
Катушка индуктивности с керамическим сердечником и  финишным покрытием контактных площадок оловом; Номиналиная индуктивность: 56 нГн; Добротность, не менее: 60; Резонансная частота, не менее: 1.6 ГГц; Сопротивление обмотки постоянноми току, не более: 0.34 Ом; Допустимый ток обмотки: 500 мА; Диапазон рабочих температур: от -60 до +125 ℃; Упаковка: Катушка и лента; Типоразмер: 2012 (0805); Технология монтажа: SMT; Изготовитель: АО "НПО "ЭРКОН"
footprint КИК-2012-O (Катушка индуктивности с керамическим сердечником типоразмер 2012(0805))
pins: 1, 2

## КИК-2012-56 нГн ±10% Зл
designator L?, comment 56 нГн ±10%  (value not drawn)
Катушка индуктивности с керамическим сердечником и золотым покрытием контактных площадок; Номиналиная индуктивность: 56 нГн; Добротность, не менее: 60; Резонансная частота, не менее: 1.6 ГГц; Сопротивление обмотки постоянноми току, не более: 0.34 Ом; Допустимый ток обмотки: 500 мА; Диапазон рабочих температур: от -60 до +125 ℃; Упаковка: Катушка и лента; Типоразмер: 2012 (0805); Технология монтажа: SMT; Изготовитель: АО "НПО "ЭРКОН"
footprint КИК-2012-Зл (Катушка индуктивности с керамическим сердечникомтипоразмер 2012(0805))
pins: 1, 2

## КИК-2012-56 нГн ±20% O
designator L?, comment 56 нГн ±20%  (value not drawn)
Катушка индуктивности с керамическим сердечником и  финишным покрытием контактных площадок оловом; Номиналиная индуктивность: 56 нГн; Добротность, не менее: 60; Резонансная частота, не менее: 1.6 ГГц; Сопротивление обмотки постоянноми току, не более: 0.34 Ом; Допустимый ток обмотки: 500 мА; Диапазон рабочих температур: от -60 до +125 ℃; Упаковка: Катушка и лента; Типоразмер: 2012 (0805); Технология монтажа: SMT; Изготовитель: АО "НПО "ЭРКОН"
footprint КИК-2012-O (Катушка индуктивности с керамическим сердечником типоразмер 2012(0805))
pins: 1, 2

## КИК-2012-56 нГн ±20% Зл
designator L?, comment 56 нГн ±20%  (value not drawn)
Катушка индуктивности с керамическим сердечником и золотым покрытием контактных площадок; Номиналиная индуктивность: 56 нГн; Добротность, не менее: 60; Резонансная частота, не менее: 1.6 ГГц; Сопротивление обмотки постоянноми току, не более: 0.34 Ом; Допустимый ток обмотки: 500 мА; Диапазон рабочих температур: от -60 до +125 ℃; Упаковка: Катушка и лента; Типоразмер: 2012 (0805); Технология монтажа: SMT; Изготовитель: АО "НПО "ЭРКОН"
footprint КИК-2012-Зл (Катушка индуктивности с керамическим сердечникомтипоразмер 2012(0805))
pins: 1, 2

## КИК-2012-68 нГн ±2% O
designator L?, comment 68 нГн ±2%  (value not drawn)
Катушка индуктивности с керамическим сердечником и  финишным покрытием контактных площадок оловом; Номиналиная индуктивность: 68 нГн; Добротность, не менее: 60; Резонансная частота, не менее: 1.5 ГГц; Сопротивление обмотки постоянноми току, не более: 0.38 Ом; Допустимый ток обмотки: 500 мА; Диапазон рабочих температур: от -60 до +125 ℃; Упаковка: Катушка и лента; Типоразмер: 2012 (0805); Технология монтажа: SMT; Изготовитель: АО "НПО "ЭРКОН"
footprint КИК-2012-O (Катушка индуктивности с керамическим сердечником типоразмер 2012(0805))
pins: 1, 2

## КИК-2012-68 нГн ±2% Зл
designator L?, comment 68 нГн ±2%  (value not drawn)
Катушка индуктивности с керамическим сердечником и золотым покрытием контактных площадок; Номиналиная индуктивность: 68 нГн; Добротность, не менее: 60; Резонансная частота, не менее: 1.5 ГГц; Сопротивление обмотки постоянноми току, не более: 0.38 Ом; Допустимый ток обмотки: 500 мА; Диапазон рабочих температур: от -60 до +125 ℃; Упаковка: Катушка и лента; Типоразмер: 2012 (0805); Технология монтажа: SMT; Изготовитель: АО "НПО "ЭРКОН"
footprint КИК-2012-Зл (Катушка индуктивности с керамическим сердечникомтипоразмер 2012(0805))
pins: 1, 2

## КИК-2012-68 нГн ±5% O
designator L?, comment 68 нГн ±5%  (value not drawn)
Катушка индуктивности с керамическим сердечником и  финишным покрытием контактных площадок оловом; Номиналиная индуктивность: 68 нГн; Добротность, не менее: 60; Резонансная частота, не менее: 1.5 ГГц; Сопротивление обмотки постоянноми току, не более: 0.38 Ом; Допустимый ток обмотки: 500 мА; Диапазон рабочих температур: от -60 до +125 ℃; Упаковка: Катушка и лента; Типоразмер: 2012 (0805); Технология монтажа: SMT; Изготовитель: АО "НПО "ЭРКОН"
footprint КИК-2012-O (Катушка индуктивности с керамическим сердечником типоразмер 2012(0805))
pins: 1, 2

## КИК-2012-68 нГн ±5% Зл
designator L?, comment 68 нГн ±5%  (value not drawn)
Катушка индуктивности с керамическим сердечником и золотым покрытием контактных площадок; Номиналиная индуктивность: 68 нГн; Добротность, не менее: 60; Резонансная частота, не менее: 1.5 ГГц; Сопротивление обмотки постоянноми току, не более: 0.38 Ом; Допустимый ток обмотки: 500 мА; Диапазон рабочих температур: от -60 до +125 ℃; Упаковка: Катушка и лента; Типоразмер: 2012 (0805); Технология монтажа: SMT; Изготовитель: АО "НПО "ЭРКОН"
footprint КИК-2012-Зл (Катушка индуктивности с керамическим сердечникомтипоразмер 2012(0805))
pins: 1, 2

## КИК-2012-68 нГн ±10% O
designator L?, comment 68 нГн ±10%  (value not drawn)
Катушка индуктивности с керамическим сердечником и  финишным покрытием контактных площадок оловом; Номиналиная индуктивность: 68 нГн; Добротность, не менее: 60; Резонансная частота, не менее: 1.5 ГГц; Сопротивление обмотки постоянноми току, не более: 0.38 Ом; Допустимый ток обмотки: 500 мА; Диапазон рабочих температур: от -60 до +125 ℃; Упаковка: Катушка и лента; Типоразмер: 2012 (0805); Технология монтажа: SMT; Изготовитель: АО "НПО "ЭРКОН"
footprint КИК-2012-O (Катушка индуктивности с керамическим сердечником типоразмер 2012(0805))
pins: 1, 2

## КИК-2012-68 нГн ±10% Зл
designator L?, comment 68 нГн ±10%  (value not drawn)
Катушка индуктивности с керамическим сердечником и золотым покрытием контактных площадок; Номиналиная индуктивность: 68 нГн; Добротность, не менее: 60; Резонансная частота, не менее: 1.5 ГГц; Сопротивление обмотки постоянноми току, не более: 0.38 Ом; Допустимый ток обмотки: 500 мА; Диапазон рабочих температур: от -60 до +125 ℃; Упаковка: Катушка и лента; Типоразмер: 2012 (0805); Технология монтажа: SMT; Изготовитель: АО "НПО "ЭРКОН"
footprint КИК-2012-Зл (Катушка индуктивности с керамическим сердечникомтипоразмер 2012(0805))
pins: 1, 2

## КИК-2012-68 нГн ±20% O
designator L?, comment 68 нГн ±20%  (value not drawn)
Катушка индуктивности с керамическим сердечником и  финишным покрытием контактных площадок оловом; Номиналиная индуктивность: 68 нГн; Добротность, не менее: 60; Резонансная частота, не менее: 1.5 ГГц; Сопротивление обмотки постоянноми току, не более: 0.38 Ом; Допустимый ток обмотки: 500 мА; Диапазон рабочих температур: от -60 до +125 ℃; Упаковка: Катушка и лента; Типоразмер: 2012 (0805); Технология монтажа: SMT; Изготовитель: АО "НПО "ЭРКОН"
footprint КИК-2012-O (Катушка индуктивности с керамическим сердечником типоразмер 2012(0805))
pins: 1, 2

## КИК-2012-68 нГн ±20% Зл
designator L?, comment 68 нГн ±20%  (value not drawn)
Катушка индуктивности с керамическим сердечником и золотым покрытием контактных площадок; Номиналиная индуктивность: 68 нГн; Добротность, не менее: 60; Резонансная частота, не менее: 1.5 ГГц; Сопротивление обмотки постоянноми току, не более: 0.38 Ом; Допустимый ток обмотки: 500 мА; Диапазон рабочих температур: от -60 до +125 ℃; Упаковка: Катушка и лента; Типоразмер: 2012 (0805); Технология монтажа: SMT; Изготовитель: АО "НПО "ЭРКОН"
footprint КИК-2012-Зл (Катушка индуктивности с керамическим сердечникомтипоразмер 2012(0805))
pins: 1, 2

## КИК-2012-82 нГн ±2% O
designator L?, comment 82 нГн ±2%  (value not drawn)
Катушка индуктивности с керамическим сердечником и  финишным покрытием контактных площадок оловом; Номиналиная индуктивность: 82 нГн; Добротность, не менее: 60; Резонансная частота, не менее: 1.33 ГГц; Сопротивление обмотки постоянноми току, не более: 0.42 Ом; Допустимый ток обмотки: 400 мА; Диапазон рабочих температур: от -60 до +125 ℃; Упаковка: Катушка и лента; Типоразмер: 2012 (0805); Технология монтажа: SMT; Изготовитель: АО "НПО "ЭРКОН"
footprint КИК-2012-O (Катушка индуктивности с керамическим сердечником типоразмер 2012(0805))
pins: 1, 2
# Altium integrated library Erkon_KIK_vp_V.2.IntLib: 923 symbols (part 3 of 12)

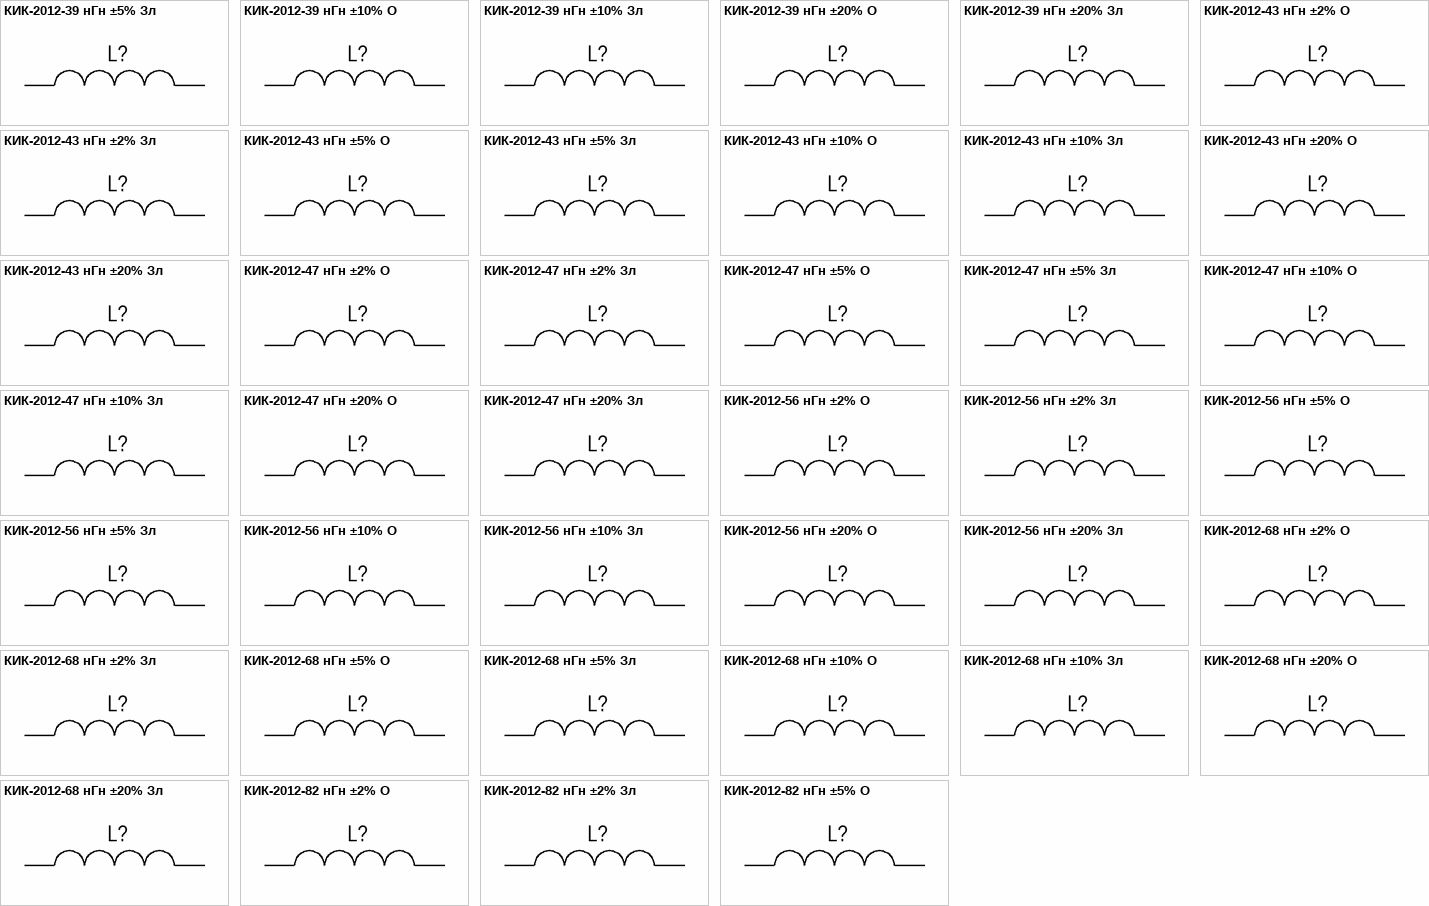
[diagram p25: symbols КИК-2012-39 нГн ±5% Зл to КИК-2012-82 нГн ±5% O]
## КИК-2012-82 нГн ±2% Зл
designator L?, comment 82 нГн ±2%  (value not drawn)
Катушка индуктивности с керамическим сердечником и золотым покрытием контактных площадок; Номиналиная индуктивность: 82 нГн; Добротность, не менее: 60; Резонансная частота, не менее: 1.33 ГГц; Сопротивление обмотки постоянноми току, не более: 0.42 Ом; Допустимый ток обмотки: 400 мА; Диапазон рабочих температур: от -60 до +125 ℃; Упаковка: Катушка и лента; Типоразмер: 2012 (0805); Технология монтажа: SMT; Изготовитель: АО "НПО "ЭРКОН"
footprint КИК-2012-Зл (Катушка индуктивности с керамическим сердечникомтипоразмер 2012(0805))
pins: 1, 2

## КИК-2012-82 нГн ±5% O
designator L?, comment 82 нГн ±5%  (value not drawn)
Катушка индуктивности с керамическим сердечником и  финишным покрытием контактных площадок оловом; Номиналиная индуктивность: 82 нГн; Добротность, не менее: 60; Резонансная частота, не менее: 1.33 ГГц; Сопротивление обмотки постоянноми току, не более: 0.42 Ом; Допустимый ток обмотки: 400 мА; Диапазон рабочих температур: от -60 до +125 ℃; Упаковка: Катушка и лента; Типоразмер: 2012 (0805); Технология монтажа: SMT; Изготовитель: АО "НПО "ЭРКОН"
footprint КИК-2012-O (Катушка индуктивности с керамическим сердечником типоразмер 2012(0805))
pins: 1, 2


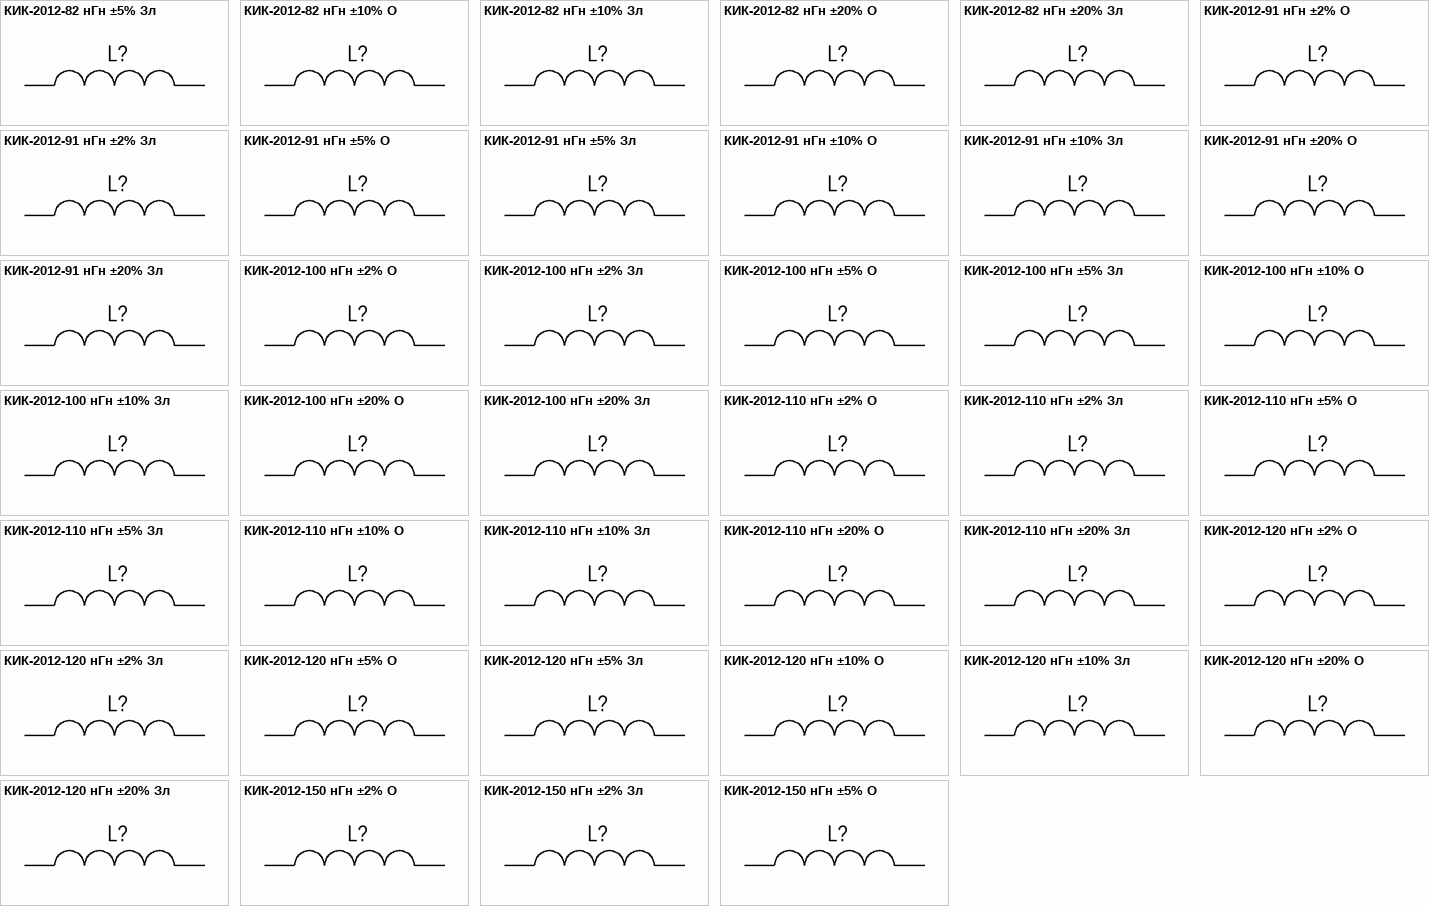
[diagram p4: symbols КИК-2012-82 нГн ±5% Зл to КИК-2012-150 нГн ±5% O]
## КИК-2012-82 нГн ±5% Зл
designator L?, comment 82 нГн ±5%  (value not drawn)
Катушка индуктивности с керамическим сердечником и золотым покрытием контактных площадок; Номиналиная индуктивность: 82 нГн; Добротность, не менее: 60; Резонансная частота, не менее: 1.33 ГГц; Сопротивление обмотки постоянноми току, не более: 0.42 Ом; Допустимый ток обмотки: 400 мА; Диапазон рабочих температур: от -60 до +125 ℃; Упаковка: Катушка и лента; Типоразмер: 2012 (0805); Технология монтажа: SMT; Изготовитель: АО "НПО "ЭРКОН"
footprint КИК-2012-Зл (Катушка индуктивности с керамическим сердечникомтипоразмер 2012(0805))
pins: 1, 2

## КИК-2012-82 нГн ±10% O
designator L?, comment 82 нГн ±10%  (value not drawn)
Катушка индуктивности с керамическим сердечником и  финишным покрытием контактных площадок оловом; Номиналиная индуктивность: 82 нГн; Добротность, не менее: 60; Резонансная частота, не менее: 1.33 ГГц; Сопротивление обмотки постоянноми току, не более: 0.42 Ом; Допустимый ток обмотки: 400 мА; Диапазон рабочих температур: от -60 до +125 ℃; Упаковка: Катушка и лента; Типоразмер: 2012 (0805); Технология монтажа: SMT; Изготовитель: АО "НПО "ЭРКОН"
footprint КИК-2012-O (Катушка индуктивности с керамическим сердечником типоразмер 2012(0805))
pins: 1, 2

## КИК-2012-82 нГн ±10% Зл
designator L?, comment 82 нГн ±10%  (value not drawn)
Катушка индуктивности с керамическим сердечником и золотым покрытием контактных площадок; Номиналиная индуктивность: 82 нГн; Добротность, не менее: 60; Резонансная частота, не менее: 1.33 ГГц; Сопротивление обмотки постоянноми току, не более: 0.42 Ом; Допустимый ток обмотки: 400 мА; Диапазон рабочих температур: от -60 до +125 ℃; Упаковка: Катушка и лента; Типоразмер: 2012 (0805); Технология монтажа: SMT; Изготовитель: АО "НПО "ЭРКОН"
footprint КИК-2012-Зл (Катушка индуктивности с керамическим сердечникомтипоразмер 2012(0805))
pins: 1, 2

## КИК-2012-82 нГн ±20% O
designator L?, comment 82 нГн ±20%  (value not drawn)
Катушка индуктивности с керамическим сердечником и  финишным покрытием контактных площадок оловом; Номиналиная индуктивность: 82 нГн; Добротность, не менее: 60; Резонансная частота, не менее: 1.33 ГГц; Сопротивление обмотки постоянноми току, не более: 0.42 Ом; Допустимый ток обмотки: 400 мА; Диапазон рабочих температур: от -60 до +125 ℃; Упаковка: Катушка и лента; Типоразмер: 2012 (0805); Технология монтажа: SMT; Изготовитель: АО "НПО "ЭРКОН"
footprint КИК-2012-O (Катушка индуктивности с керамическим сердечником типоразмер 2012(0805))
pins: 1, 2

## КИК-2012-82 нГн ±20% Зл
designator L?, comment 82 нГн ±20%  (value not drawn)
Катушка индуктивности с керамическим сердечником и золотым покрытием контактных площадок; Номиналиная индуктивность: 82 нГн; Добротность, не менее: 60; Резонансная частота, не менее: 1.33 ГГц; Сопротивление обмотки постоянноми току, не более: 0.42 Ом; Допустимый ток обмотки: 400 мА; Диапазон рабочих температур: от -60 до +125 ℃; Упаковка: Катушка и лента; Типоразмер: 2012 (0805); Технология монтажа: SMT; Изготовитель: АО "НПО "ЭРКОН"
footprint КИК-2012-Зл (Катушка индуктивности с керамическим сердечникомтипоразмер 2012(0805))
pins: 1, 2

## КИК-2012-91 нГн ±2% O
designator L?, comment 91 нГн ±2%  (value not drawn)
Катушка индуктивности с керамическим сердечником и  финишным покрытием контактных площадок оловом; Номиналиная индуктивность: 91нГн; Добротность, не менее: 60; Резонансная частота, не менее: 1.33 ГГц; Сопротивление обмотки постоянноми току, не более: 0.48 Ом; Допустимый ток обмотки: 400 мА; Диапазон рабочих температур: от -60 до +125 ℃; Упаковка: Катушка и лента; Типоразмер: 2012 (0805); Технология монтажа: SMT; Изготовитель: АО "НПО "ЭРКОН"
footprint КИК-2012-O (Катушка индуктивности с керамическим сердечником типоразмер 2012(0805))
pins: 1, 2

## КИК-2012-91 нГн ±2% Зл
designator L?, comment 91 нГн ±2%  (value not drawn)
Катушка индуктивности с керамическим сердечником и золотым покрытием контактных площадок; Номиналиная индуктивность: 91нГн; Добротность, не менее: 60; Резонансная частота, не менее: 1.33 ГГц; Сопротивление обмотки постоянноми току, не более: 0.48 Ом; Допустимый ток обмотки: 400 мА; Диапазон рабочих температур: от -60 до +125 ℃; Упаковка: Катушка и лента; Типоразмер: 2012 (0805); Технология монтажа: SMT; Изготовитель: АО "НПО "ЭРКОН"
footprint КИК-2012-Зл (Катушка индуктивности с керамическим сердечникомтипоразмер 2012(0805))
pins: 1, 2

## КИК-2012-91 нГн ±5% O
designator L?, comment 91 нГн ±5%  (value not drawn)
Катушка индуктивности с керамическим сердечником и  финишным покрытием контактных площадок оловом; Номиналиная индуктивность: 91нГн; Добротность, не менее: 60; Резонансная частота, не менее: 1.33 ГГц; Сопротивление обмотки постоянноми току, не более: 0.48 Ом; Допустимый ток обмотки: 400 мА; Диапазон рабочих температур: от -60 до +125 ℃; Упаковка: Катушка и лента; Типоразмер: 2012 (0805); Технология монтажа: SMT; Изготовитель: АО "НПО "ЭРКОН"
footprint КИК-2012-O (Катушка индуктивности с керамическим сердечником типоразмер 2012(0805))
pins: 1, 2

## КИК-2012-91 нГн ±5% Зл
designator L?, comment 91 нГн ±5%  (value not drawn)
Катушка индуктивности с керамическим сердечником и золотым покрытием контактных площадок; Номиналиная индуктивность: 91нГн; Добротность, не менее: 60; Резонансная частота, не менее: 1.33 ГГц; Сопротивление обмотки постоянноми току, не более: 0.48 Ом; Допустимый ток обмотки: 400 мА; Диапазон рабочих температур: от -60 до +125 ℃; Упаковка: Катушка и лента; Типоразмер: 2012 (0805); Технология монтажа: SMT; Изготовитель: АО "НПО "ЭРКОН"
footprint КИК-2012-Зл (Катушка индуктивности с керамическим сердечникомтипоразмер 2012(0805))
pins: 1, 2

## КИК-2012-91 нГн ±10% O
designator L?, comment 91 нГн ±10%  (value not drawn)
Катушка индуктивности с керамическим сердечником и  финишным покрытием контактных площадок оловом; Номиналиная индуктивность: 91 нГн; Добротность, не менее: 60; Резонансная частота, не менее: 1.33 ГГц; Сопротивление обмотки постоянноми току, не более: 0.48 Ом; Допустимый ток обмотки: 400 мА; Диапазон рабочих температур: от -60 до +125 ℃; Упаковка: Катушка и лента; Типоразмер: 2012 (0805); Технология монтажа: SMT; Изготовитель: АО "НПО "ЭРКОН"
footprint КИК-2012-O (Катушка индуктивности с керамическим сердечником типоразмер 2012(0805))
pins: 1, 2

## КИК-2012-91 нГн ±10% Зл
designator L?, comment 91 нГн ±10%  (value not drawn)
Катушка индуктивности с керамическим сердечником и золотым покрытием контактных площадок; Номиналиная индуктивность: 91нГн; Добротность, не менее: 60; Резонансная частота, не менее: 1.33 ГГц; Сопротивление обмотки постоянноми току, не более: 0.48 Ом; Допустимый ток обмотки: 400 мА; Диапазон рабочих температур: от -60 до +125 ℃; Упаковка: Катушка и лента; Типоразмер: 2012 (0805); Технология монтажа: SMT; Изготовитель: АО "НПО "ЭРКОН"
footprint КИК-2012-Зл (Катушка индуктивности с керамическим сердечникомтипоразмер 2012(0805))
pins: 1, 2

## КИК-2012-91 нГн ±20% O
designator L?, comment 91 нГн ±20%  (value not drawn)
Катушка индуктивности с керамическим сердечником и  финишным покрытием контактных площадок оловом; Номиналиная индуктивность: 91 нГн; Добротность, не менее: 60; Резонансная частота, не менее: 1.33 ГГц; Сопротивление обмотки постоянноми току, не более: 0.48 Ом; Допустимый ток обмотки: 400 мА; Диапазон рабочих температур: от -60 до +125 ℃; Упаковка: Катушка и лента; Типоразмер: 2012 (0805); Технология монтажа: SMT; Изготовитель: АО "НПО "ЭРКОН"
footprint КИК-2012-O (Катушка индуктивности с керамическим сердечником типоразмер 2012(0805))
pins: 1, 2

## КИК-2012-91 нГн ±20% Зл
designator L?, comment 91 нГн ±20%  (value not drawn)
Катушка индуктивности с керамическим сердечником и золотым покрытием контактных площадок; Номиналиная индуктивность: 91нГн; Добротность, не менее: 60; Резонансная частота, не менее: 1.33 ГГц; Сопротивление обмотки постоянноми току, не более: 0.48 Ом; Допустимый ток обмотки: 400 мА; Диапазон рабочих температур: от -60 до +125 ℃; Упаковка: Катушка и лента; Типоразмер: 2012 (0805); Технология монтажа: SMT; Изготовитель: АО "НПО "ЭРКОН"
footprint КИК-2012-Зл (Катушка индуктивности с керамическим сердечникомтипоразмер 2012(0805))
pins: 1, 2

## КИК-2012-100 нГн ±2% O
designator L?, comment 100 нГн ±2%  (value not drawn)
Катушка индуктивности с керамическим сердечником и  финишным покрытием контактных площадок оловом; Номиналиная индуктивность: 100 нГн; Добротность, не менее: 60; Резонансная частота, не менее: 1.25 ГГц; Сопротивление обмотки постоянноми току, не более: 0.46 Ом; Допустимый ток обмотки: 400 мА; Диапазон рабочих температур: от -60 до +125 ℃; Упаковка: Катушка и лента; Типоразмер: 2012 (0805); Технология монтажа: SMT; Изготовитель: АО "НПО "ЭРКОН"
footprint КИК-2012-O (Катушка индуктивности с керамическим сердечником типоразмер 2012(0805))
pins: 1, 2

## КИК-2012-100 нГн ±2% Зл
designator L?, comment 100 нГн ±2%  (value not drawn)
Катушка индуктивности с керамическим сердечником и золотым покрытием контактных площадок; Номиналиная индуктивность: 100 нГн; Добротность, не менее: 60; Резонансная частота, не менее: 1.25 ГГц; Сопротивление обмотки постоянноми току, не более: 0.46 Ом; Допустимый ток обмотки: 400 мА; Диапазон рабочих температур: от -60 до +125 ℃; Упаковка: Катушка и лента; Типоразмер: 2012 (0805); Технология монтажа: SMT; Изготовитель: АО "НПО "ЭРКОН"
footprint КИК-2012-Зл (Катушка индуктивности с керамическим сердечникомтипоразмер 2012(0805))
pins: 1, 2

## КИК-2012-100 нГн ±5% O
designator L?, comment 100 нГн ±5%  (value not drawn)
Катушка индуктивности с керамическим сердечником и  финишным покрытием контактных площадок оловом; Номиналиная индуктивность: 100 нГн; Добротность, не менее: 60; Резонансная частота, не менее: 1.25 ГГц; Сопротивление обмотки постоянноми току, не более: 0.46 Ом; Допустимый ток обмотки: 400 мА; Диапазон рабочих температур: от -60 до +125 ℃; Упаковка: Катушка и лента; Типоразмер: 2012 (0805); Технология монтажа: SMT; Изготовитель: АО "НПО "ЭРКОН"
footprint КИК-2012-O (Катушка индуктивности с керамическим сердечником типоразмер 2012(0805))
pins: 1, 2

## КИК-2012-100 нГн ±5% Зл
designator L?, comment 100 нГн ±5%  (value not drawn)
Катушка индуктивности с керамическим сердечником и золотым покрытием контактных площадок; Номиналиная индуктивность: 100 нГн; Добротность, не менее: 60; Резонансная частота, не менее: 1.25 ГГц; Сопротивление обмотки постоянноми току, не более: 0.46 Ом; Допустимый ток обмотки: 400 мА; Диапазон рабочих температур: от -60 до +125 ℃; Упаковка: Катушка и лента; Типоразмер: 2012 (0805); Технология монтажа: SMT; Изготовитель: АО "НПО "ЭРКОН"
footprint КИК-2012-Зл (Катушка индуктивности с керамическим сердечникомтипоразмер 2012(0805))
pins: 1, 2

## КИК-2012-100 нГн ±10% O
designator L?, comment 100 нГн ±10%  (value not drawn)
Катушка индуктивности с керамическим сердечником и  финишным покрытием контактных площадок оловом; Номиналиная индуктивность: 100 нГн; Добротность, не менее: 60; Резонансная частота, не менее: 1.25 ГГц; Сопротивление обмотки постоянноми току, не более: 0.46 Ом; Допустимый ток обмотки: 400 мА; Диапазон рабочих температур: от -60 до +125 ℃; Упаковка: Катушка и лента; Типоразмер: 2012 (0805); Технология монтажа: SMT; Изготовитель: АО "НПО "ЭРКОН"
footprint КИК-2012-O (Катушка индуктивности с керамическим сердечником типоразмер 2012(0805))
pins: 1, 2

## КИК-2012-100 нГн ±10% Зл
designator L?, comment 100 нГн ±10%  (value not drawn)
Катушка индуктивности с керамическим сердечником и золотым покрытием контактных площадок; Номиналиная индуктивность: 100 нГн; Добротность, не менее: 60; Резонансная частота, не менее: 1.25 ГГц; Сопротивление обмотки постоянноми току, не более: 0.46 Ом; Допустимый ток обмотки: 400 мА; Диапазон рабочих температур: от -60 до +125 ℃; Упаковка: Катушка и лента; Типоразмер: 2012 (0805); Технология монтажа: SMT; Изготовитель: АО "НПО "ЭРКОН"
footprint КИК-2012-Зл (Катушка индуктивности с керамическим сердечникомтипоразмер 2012(0805))
pins: 1, 2

## КИК-2012-100 нГн ±20% O
designator L?, comment 100 нГн ±20%  (value not drawn)
Катушка индуктивности с керамическим сердечником и  финишным покрытием контактных площадок оловом; Номиналиная индуктивность: 100 нГн; Добротность, не менее: 60; Резонансная частота, не менее: 1.25 ГГц; Сопротивление обмотки постоянноми току, не более: 0.46 Ом; Допустимый ток обмотки: 400 мА; Диапазон рабочих температур: от -60 до +125 ℃; Упаковка: Катушка и лента; Типоразмер: 2012 (0805); Технология монтажа: SMT; Изготовитель: АО "НПО "ЭРКОН"
footprint КИК-2012-O (Катушка индуктивности с керамическим сердечником типоразмер 2012(0805))
pins: 1, 2

## КИК-2012-100 нГн ±20% Зл
designator L?, comment 100 нГн ±20%  (value not drawn)
Катушка индуктивности с керамическим сердечником и золотым покрытием контактных площадок; Номиналиная индуктивность: 100 нГн; Добротность, не менее: 60; Резонансная частота, не менее: 1.25 ГГц; Сопротивление обмотки постоянноми току, не более: 0.46 Ом; Допустимый ток обмотки: 400 мА; Диапазон рабочих температур: от -60 до +125 ℃; Упаковка: Катушка и лента; Типоразмер: 2012 (0805); Технология монтажа: SMT; Изготовитель: АО "НПО "ЭРКОН"
footprint КИК-2012-Зл (Катушка индуктивности с керамическим сердечникомтипоразмер 2012(0805))
pins: 1, 2

## КИК-2012-110 нГн ±2% O
designator L?, comment 110 нГн ±2%  (value not drawn)
Катушка индуктивности с керамическим сердечником и  финишным покрытием контактных площадок оловом; Номиналиная индуктивность: 110 нГн; Добротность, не менее: 50; Резонансная частота, не менее: 1.10ГГц; Сопротивление обмотки постоянноми току, не более: 0.48 Ом; Допустимый ток обмотки: 400 мА; Диапазон рабочих температур: от -60 до +125 ℃; Упаковка: Катушка и лента; Типоразмер: 2012 (0805); Технология монтажа: SMT; Изготовитель: АО "НПО "ЭРКОН"
footprint КИК-2012-O (Катушка индуктивности с керамическим сердечником типоразмер 2012(0805))
pins: 1, 2

## КИК-2012-110 нГн ±2% Зл
designator L?, comment 110 нГн ±2%  (value not drawn)
Катушка индуктивности с керамическим сердечником и золотым покрытием контактных площадок; Номиналиная индуктивность: 110 нГн; Добротность, не менее: 50; Резонансная частота, не менее: 1.10ГГц; Сопротивление обмотки постоянноми току, не более: 0.48 Ом; Допустимый ток обмотки: 400 мА; Диапазон рабочих температур: от -60 до +125 ℃; Упаковка: Катушка и лента; Типоразмер: 2012 (0805); Технология монтажа: SMT; Изготовитель: АО "НПО "ЭРКОН"
footprint КИК-2012-Зл (Катушка индуктивности с керамическим сердечникомтипоразмер 2012(0805))
pins: 1, 2

## КИК-2012-110 нГн ±5% O
designator L?, comment 110 нГн ±5%  (value not drawn)
Катушка индуктивности с керамическим сердечником и  финишным покрытием контактных площадок оловом; Номиналиная индуктивность: 110 нГн; Добротность, не менее: 50; Резонансная частота, не менее: 1.10ГГц; Сопротивление обмотки постоянноми току, не более: 0.48 Ом; Допустимый ток обмотки: 400 мА; Диапазон рабочих температур: от -60 до +125 ℃; Упаковка: Катушка и лента; Типоразмер: 2012 (0805); Технология монтажа: SMT; Изготовитель: АО "НПО "ЭРКОН"
footprint КИК-2012-O (Катушка индуктивности с керамическим сердечником типоразмер 2012(0805))
pins: 1, 2

## КИК-2012-110 нГн ±5% Зл
designator L?, comment 110 нГн ±5%  (value not drawn)
Катушка индуктивности с керамическим сердечником и золотым покрытием контактных площадок; Номиналиная индуктивность: 110 нГн; Добротность, не менее: 50; Резонансная частота, не менее: 1.10ГГц; Сопротивление обмотки постоянноми току, не более: 0.48 Ом; Допустимый ток обмотки: 400 мА; Диапазон рабочих температур: от -60 до +125 ℃; Упаковка: Катушка и лента; Типоразмер: 2012 (0805); Технология монтажа: SMT; Изготовитель: АО "НПО "ЭРКОН"
footprint КИК-2012-Зл (Катушка индуктивности с керамическим сердечникомтипоразмер 2012(0805))
pins: 1, 2

## КИК-2012-110 нГн ±10% O
designator L?, comment 110 нГн ±10%  (value not drawn)
Катушка индуктивности с керамическим сердечником и  финишным покрытием контактных площадок оловом; Номиналиная индуктивность: 110 нГн; Добротность, не менее: 50; Резонансная частота, не менее: 1.10ГГц; Сопротивление обмотки постоянноми току, не более: 0.48 Ом; Допустимый ток обмотки: 400 мА; Диапазон рабочих температур: от -60 до +125 ℃; Упаковка: Катушка и лента; Типоразмер: 2012 (0805); Технология монтажа: SMT; Изготовитель: АО "НПО "ЭРКОН"
footprint КИК-2012-O (Катушка индуктивности с керамическим сердечником типоразмер 2012(0805))
pins: 1, 2

## КИК-2012-110 нГн ±10% Зл
designator L?, comment 110 нГн ±10%  (value not drawn)
Катушка индуктивности с керамическим сердечником и золотым покрытием контактных площадок; Номиналиная индуктивность: 110 нГн; Добротность, не менее: 50; Резонансная частота, не менее: 1.10ГГц; Сопротивление обмотки постоянноми току, не более: 0.48 Ом; Допустимый ток обмотки: 400 мА; Диапазон рабочих температур: от -60 до +125 ℃; Упаковка: Катушка и лента; Типоразмер: 2012 (0805); Технология монтажа: SMT; Изготовитель: АО "НПО "ЭРКОН"
footprint КИК-2012-Зл (Катушка индуктивности с керамическим сердечникомтипоразмер 2012(0805))
pins: 1, 2

## КИК-2012-110 нГн ±20% O
designator L?, comment 110 нГн ±20%  (value not drawn)
Катушка индуктивности с керамическим сердечником и  финишным покрытием контактных площадок оловом; Номиналиная индуктивность: 110 нГн; Добротность, не менее: 50; Резонансная частота, не менее: 1.10ГГц; Сопротивление обмотки постоянноми току, не более: 0.48 Ом; Допустимый ток обмотки: 400 мА; Диапазон рабочих температур: от -60 до +125 ℃; Упаковка: Катушка и лента; Типоразмер: 2012 (0805); Технология монтажа: SMT; Изготовитель: АО "НПО "ЭРКОН"
footprint КИК-2012-O (Катушка индуктивности с керамическим сердечником типоразмер 2012(0805))
pins: 1, 2

## КИК-2012-110 нГн ±20% Зл
designator L?, comment 110 нГн ±20%  (value not drawn)
Катушка индуктивности с керамическим сердечником и золотым покрытием контактных площадок; Номиналиная индуктивность: 110 нГн; Добротность, не менее: 50; Резонансная частота, не менее: 1.10ГГц; Сопротивление обмотки постоянноми току, не более: 0.48 Ом; Допустимый ток обмотки: 400 мА; Диапазон рабочих температур: от -60 до +125 ℃; Упаковка: Катушка и лента; Типоразмер: 2012 (0805); Технология монтажа: SMT; Изготовитель: АО "НПО "ЭРКОН"
footprint КИК-2012-Зл (Катушка индуктивности с керамическим сердечникомтипоразмер 2012(0805))
pins: 1, 2

## КИК-2012-120 нГн ±2% O
designator L?, comment 120 нГн ±2%  (value not drawn)
Катушка индуктивности с керамическим сердечником и  финишным покрытием контактных площадок оловом; Номиналиная индуктивность: 120 нГн; Добротность, не менее: 50; Резонансная частота, не менее: 1.10 ГГц; Сопротивление обмотки постоянноми току, не более: 0.51 Ом; Допустимый ток обмотки: 400 мА; Диапазон рабочих температур: от -60 до +125 ℃; Упаковка: Катушка и лента; Типоразмер: 2012 (0805); Технология монтажа: SMT; Изготовитель: АО "НПО "ЭРКОН"
footprint КИК-2012-O (Катушка индуктивности с керамическим сердечником типоразмер 2012(0805))
pins: 1, 2

## КИК-2012-120 нГн ±2% Зл
designator L?, comment 120 нГн ±2%  (value not drawn)
Катушка индуктивности с керамическим сердечником и золотым покрытием контактных площадок; Номиналиная индуктивность: 120 нГн; Добротность, не менее: 50; Резонансная частота, не менее: 1.10 ГГц; Сопротивление обмотки постоянноми току, не более: 0.51 Ом; Допустимый ток обмотки: 400 мА; Диапазон рабочих температур: от -60 до +125 ℃; Упаковка: Катушка и лента; Типоразмер: 2012 (0805); Технология монтажа: SMT; Изготовитель: АО "НПО "ЭРКОН"
footprint КИК-2012-Зл (Катушка индуктивности с керамическим сердечникомтипоразмер 2012(0805))
pins: 1, 2

## КИК-2012-120 нГн ±5% O
designator L?, comment 120 нГн ±5%  (value not drawn)
Катушка индуктивности с керамическим сердечником и  финишным покрытием контактных площадок оловом; Номиналиная индуктивность: 120 нГн; Добротность, не менее: 50; Резонансная частота, не менее: 1.10 ГГц; Сопротивление обмотки постоянноми току, не более: 0.51 Ом; Допустимый ток обмотки: 400 мА; Диапазон рабочих температур: от -60 до +125 ℃; Упаковка: Катушка и лента; Типоразмер: 2012 (0805); Технология монтажа: SMT; Изготовитель: АО "НПО "ЭРКОН"
footprint КИК-2012-O (Катушка индуктивности с керамическим сердечником типоразмер 2012(0805))
pins: 1, 2

## КИК-2012-120 нГн ±5% Зл
designator L?, comment 120 нГн ±5%  (value not drawn)
Катушка индуктивности с керамическим сердечником и золотым покрытием контактных площадок; Номиналиная индуктивность: 120 нГн; Добротность, не менее: 50; Резонансная частота, не менее: 1.10 ГГц; Сопротивление обмотки постоянноми току, не более: 0.51 Ом; Допустимый ток обмотки: 400 мА; Диапазон рабочих температур: от -60 до +125 ℃; Упаковка: Катушка и лента; Типоразмер: 2012 (0805); Технология монтажа: SMT; Изготовитель: АО "НПО "ЭРКОН"
footprint КИК-2012-Зл (Катушка индуктивности с керамическим сердечникомтипоразмер 2012(0805))
pins: 1, 2

## КИК-2012-120 нГн ±10% O
designator L?, comment 120 нГн ±10%  (value not drawn)
Катушка индуктивности с керамическим сердечником и  финишным покрытием контактных площадок оловом; Номиналиная индуктивность: 120 нГн; Добротность, не менее: 50; Резонансная частота, не менее: 1.10 ГГц; Сопротивление обмотки постоянноми току, не более: 0.51 Ом; Допустимый ток обмотки: 400 мА; Диапазон рабочих температур: от -60 до +125 ℃; Упаковка: Катушка и лента; Типоразмер: 2012 (0805); Технология монтажа: SMT; Изготовитель: АО "НПО "ЭРКОН"
footprint КИК-2012-O (Катушка индуктивности с керамическим сердечником типоразмер 2012(0805))
pins: 1, 2

## КИК-2012-120 нГн ±10% Зл
designator L?, comment 120 нГн ±10%  (value not drawn)
Катушка индуктивности с керамическим сердечником и золотым покрытием контактных площадок; Номиналиная индуктивность: 120 нГн; Добротность, не менее: 50; Резонансная частота, не менее: 1.10 ГГц; Сопротивление обмотки постоянноми току, не более: 0.51 Ом; Допустимый ток обмотки: 400 мА; Диапазон рабочих температур: от -60 до +125 ℃; Упаковка: Катушка и лента; Типоразмер: 2012 (0805); Технология монтажа: SMT; Изготовитель: АО "НПО "ЭРКОН"
footprint КИК-2012-Зл (Катушка индуктивности с керамическим сердечникомтипоразмер 2012(0805))
pins: 1, 2

## КИК-2012-120 нГн ±20% O
designator L?, comment 120 нГн ±20%  (value not drawn)
Катушка индуктивности с керамическим сердечником и  финишным покрытием контактных площадок оловом; Номиналиная индуктивность: 120 нГн; Добротность, не менее: 50; Резонансная частота, не менее: 1.10 ГГц; Сопротивление обмотки постоянноми току, не более: 0.51 Ом; Допустимый ток обмотки: 400 мА; Диапазон рабочих температур: от -60 до +125 ℃; Упаковка: Катушка и лента; Типоразмер: 2012 (0805); Технология монтажа: SMT; Изготовитель: АО "НПО "ЭРКОН"
footprint КИК-2012-O (Катушка индуктивности с керамическим сердечником типоразмер 2012(0805))
pins: 1, 2

## КИК-2012-120 нГн ±20% Зл
designator L?, comment 120 нГн ±20%  (value not drawn)
Катушка индуктивности с керамическим сердечником и золотым покрытием контактных площадок; Номиналиная индуктивность: 120 нГн; Добротность, не менее: 50; Резонансная частота, не менее: 1.10 ГГц; Сопротивление обмотки постоянноми току, не более: 0.51 Ом; Допустимый ток обмотки: 400 мА; Диапазон рабочих температур: от -60 до +125 ℃; Упаковка: Катушка и лента; Типоразмер: 2012 (0805); Технология монтажа: SMT; Изготовитель: АО "НПО "ЭРКОН"
footprint КИК-2012-Зл (Катушка индуктивности с керамическим сердечникомтипоразмер 2012(0805))
pins: 1, 2

## КИК-2012-150 нГн ±2% O
designator L?, comment 150 нГн ±2%  (value not drawn)
Катушка индуктивности с керамическим сердечником и  финишным покрытием контактных площадок оловом; Номиналиная индуктивность: 150 нГн; Добротность, не менее: 50; Резонансная частота, не менее: 0.92 ГГц; Сопротивление обмотки постоянноми току, не более: 0.56 Ом; Допустимый ток обмотки: 400 мА; Диапазон рабочих температур: от -60 до +125 ℃; Упаковка: Катушка и лента; Типоразмер: 2012 (0805); Технология монтажа: SMT; Изготовитель: АО "НПО "ЭРКОН"
footprint КИК-2012-O (Катушка индуктивности с керамическим сердечником типоразмер 2012(0805))
pins: 1, 2

## КИК-2012-150 нГн ±2% Зл
designator L?, comment 150 нГн ±2%  (value not drawn)
Катушка индуктивности с керамическим сердечником и золотым покрытием контактных площадок; Номиналиная индуктивность: 150 нГн; Добротность, не менее: 50; Резонансная частота, не менее: 0.92 ГГц; Сопротивление обмотки постоянноми току, не более: 0.56 Ом; Допустимый ток обмотки: 400 мА; Диапазон рабочих температур: от -60 до +125 ℃; Упаковка: Катушка и лента; Типоразмер: 2012 (0805); Технология монтажа: SMT; Изготовитель: АО "НПО "ЭРКОН"
footprint КИК-2012-Зл (Катушка индуктивности с керамическим сердечникомтипоразмер 2012(0805))
pins: 1, 2

## КИК-2012-150 нГн ±5% O
designator L?, comment 150 нГн ±5%  (value not drawn)
Катушка индуктивности с керамическим сердечником и  финишным покрытием контактных площадок оловом; Номиналиная индуктивность: 150 нГн; Добротность, не менее: 50; Резонансная частота, не менее: 0.92 ГГц; Сопротивление обмотки постоянноми току, не более: 0.56 Ом; Допустимый ток обмотки: 400 мА; Диапазон рабочих температур: от -60 до +125 ℃; Упаковка: Катушка и лента; Типоразмер: 2012 (0805); Технология монтажа: SMT; Изготовитель: АО "НПО "ЭРКОН"
footprint КИК-2012-O (Катушка индуктивности с керамическим сердечником типоразмер 2012(0805))
pins: 1, 2


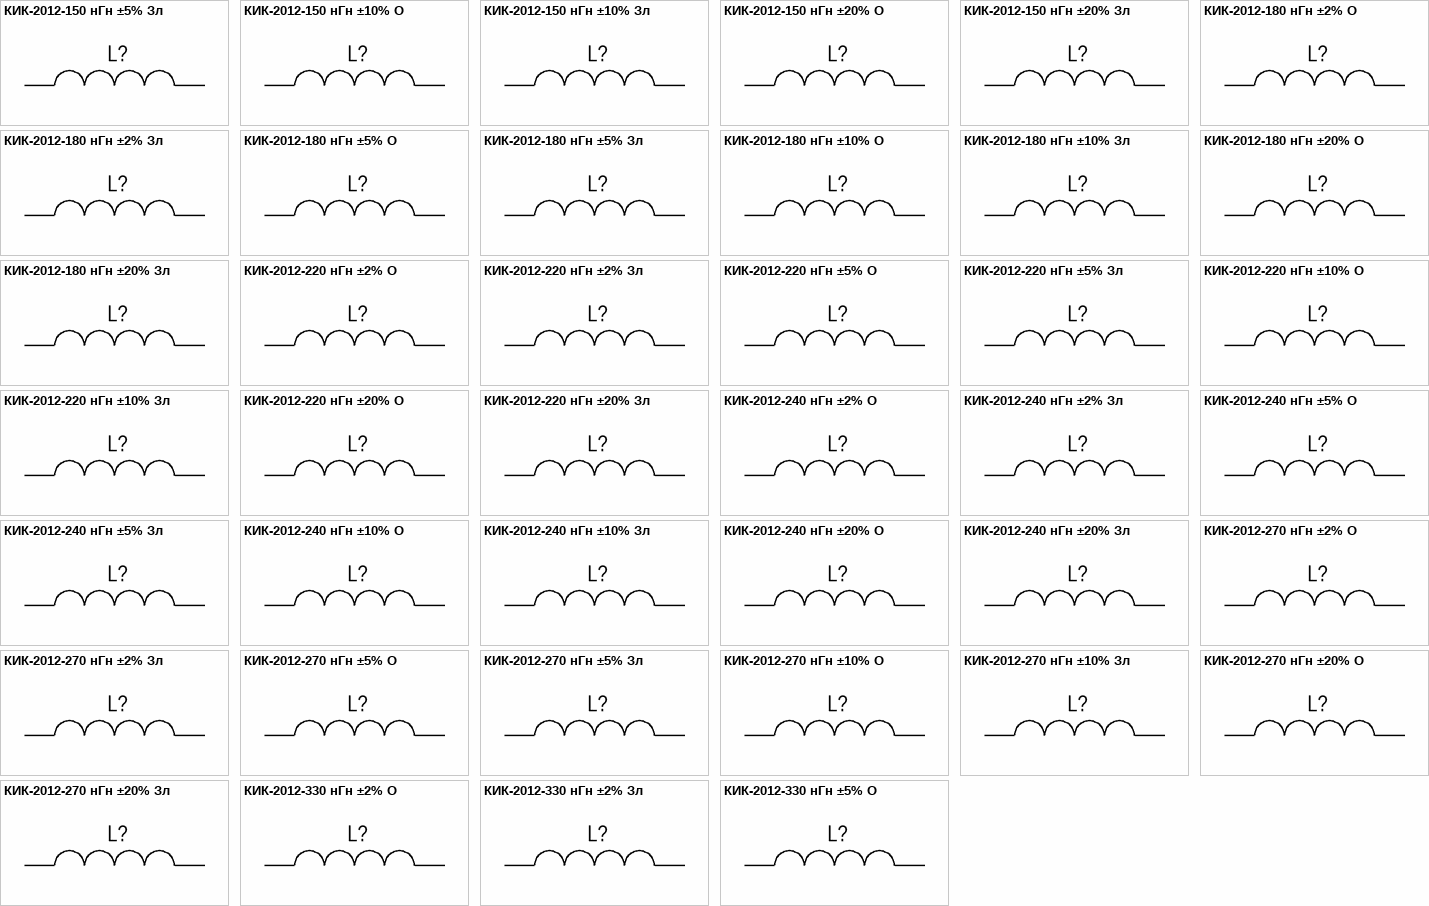
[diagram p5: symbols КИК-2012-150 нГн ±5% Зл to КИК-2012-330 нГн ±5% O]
## КИК-2012-150 нГн ±5% Зл
designator L?, comment 150 нГн ±5%  (value not drawn)
Катушка индуктивности с керамическим сердечником и золотым покрытием контактных площадок; Номиналиная индуктивность: 150 нГн; Добротность, не менее: 50; Резонансная частота, не менее: 0.92 ГГц; Сопротивление обмотки постоянноми току, не более: 0.56 Ом; Допустимый ток обмотки: 400 мА; Диапазон рабочих температур: от -60 до +125 ℃; Упаковка: Катушка и лента; Типоразмер: 2012 (0805); Технология монтажа: SMT; Изготовитель: АО "НПО "ЭРКОН"
footprint КИК-2012-Зл (Катушка индуктивности с керамическим сердечникомтипоразмер 2012(0805))
pins: 1, 2

## КИК-2012-150 нГн ±10% O
designator L?, comment 150 нГн ±10%  (value not drawn)
Катушка индуктивности с керамическим сердечником и  финишным покрытием контактных площадок оловом; Номиналиная индуктивность: 150 нГн; Добротность, не менее: 50; Резонансная частота, не менее: 0.92 ГГц; Сопротивление обмотки постоянноми току, не более: 0.56 Ом; Допустимый ток обмотки: 400 мА; Диапазон рабочих температур: от -60 до +125 ℃; Упаковка: Катушка и лента; Типоразмер: 2012 (0805); Технология монтажа: SMT; Изготовитель: АО "НПО "ЭРКОН"
footprint КИК-2012-O (Катушка индуктивности с керамическим сердечником типоразмер 2012(0805))
pins: 1, 2

## КИК-2012-150 нГн ±10% Зл
designator L?, comment 150 нГн ±10%  (value not drawn)
Катушка индуктивности с керамическим сердечником и золотым покрытием контактных площадок; Номиналиная индуктивность: 150 нГн; Добротность, не менее: 50; Резонансная частота, не менее: 0.92 ГГц; Сопротивление обмотки постоянноми току, не более: 0.56 Ом; Допустимый ток обмотки: 400 мА; Диапазон рабочих температур: от -60 до +125 ℃; Упаковка: Катушка и лента; Типоразмер: 2012 (0805); Технология монтажа: SMT; Изготовитель: АО "НПО "ЭРКОН"
footprint КИК-2012-Зл (Катушка индуктивности с керамическим сердечникомтипоразмер 2012(0805))
pins: 1, 2

## КИК-2012-150 нГн ±20% O
designator L?, comment 150 нГн ±20%  (value not drawn)
Катушка индуктивности с керамическим сердечником и  финишным покрытием контактных площадок оловом; Номиналиная индуктивность: 150 нГн; Добротность, не менее: 50; Резонансная частота, не менее: 0.92 ГГц; Сопротивление обмотки постоянноми току, не более: 0.56 Ом; Допустимый ток обмотки: 400 мА; Диапазон рабочих температур: от -60 до +125 ℃; Упаковка: Катушка и лента; Типоразмер: 2012 (0805); Технология монтажа: SMT; Изготовитель: АО "НПО "ЭРКОН"
footprint КИК-2012-O (Катушка индуктивности с керамическим сердечником типоразмер 2012(0805))
pins: 1, 2

## КИК-2012-150 нГн ±20% Зл
designator L?, comment 150 нГн ±20%  (value not drawn)
Катушка индуктивности с керамическим сердечником и золотым покрытием контактных площадок; Номиналиная индуктивность: 150 нГн; Добротность, не менее: 50; Резонансная частота, не менее: 0.92 ГГц; Сопротивление обмотки постоянноми току, не более: 0.56 Ом; Допустимый ток обмотки: 400 мА; Диапазон рабочих температур: от -60 до +125 ℃; Упаковка: Катушка и лента; Типоразмер: 2012 (0805); Технология монтажа: SMT; Изготовитель: АО "НПО "ЭРКОН"
footprint КИК-2012-Зл (Катушка индуктивности с керамическим сердечникомтипоразмер 2012(0805))
pins: 1, 2

## КИК-2012-180 нГн ±2% O
designator L?, comment 180 нГн ±2%  (value not drawn)
Катушка индуктивности с керамическим сердечником и  финишным покрытием контактных площадок оловом; Номиналиная индуктивность: 180 нГн; Добротность, не менее: 50; Резонансная частота, не менее: 0.92 ГГц; Сопротивление обмотки постоянноми току, не более: 0.64 Ом; Допустимый ток обмотки: 400 мА; Диапазон рабочих температур: от -60 до +125 ℃; Упаковка: Катушка и лента; Типоразмер: 2012 (0805); Технология монтажа: SMT; Изготовитель: АО "НПО "ЭРКОН"
footprint КИК-2012-O (Катушка индуктивности с керамическим сердечником типоразмер 2012(0805))
pins: 1, 2

## КИК-2012-180 нГн ±2% Зл
designator L?, comment 180 нГн ±2%  (value not drawn)
Катушка индуктивности с керамическим сердечником и золотым покрытием контактных площадок; Номиналиная индуктивность: 180 нГн; Добротность, не менее: 50; Резонансная частота, не менее: 0.92 ГГц; Сопротивление обмотки постоянноми току, не более: 0.64 Ом; Допустимый ток обмотки: 400 мА; Диапазон рабочих температур: от -60 до +125 ℃; Упаковка: Катушка и лента; Типоразмер: 2012 (0805); Технология монтажа: SMT; Изготовитель: АО "НПО "ЭРКОН"
footprint КИК-2012-Зл (Катушка индуктивности с керамическим сердечникомтипоразмер 2012(0805))
pins: 1, 2

## КИК-2012-180 нГн ±5% O
designator L?, comment 180 нГн ±5%  (value not drawn)
Катушка индуктивности с керамическим сердечником и  финишным покрытием контактных площадок оловом; Номиналиная индуктивность: 180 нГн; Добротность, не менее: 50; Резонансная частота, не менее: 0.92 ГГц; Сопротивление обмотки постоянноми току, не более: 0.64 Ом; Допустимый ток обмотки: 400 мА; Диапазон рабочих температур: от -60 до +125 ℃; Упаковка: Катушка и лента; Типоразмер: 2012 (0805); Технология монтажа: SMT; Изготовитель: АО "НПО "ЭРКОН"
footprint КИК-2012-O (Катушка индуктивности с керамическим сердечником типоразмер 2012(0805))
pins: 1, 2

## КИК-2012-180 нГн ±5% Зл
designator L?, comment 180 нГн ±5%  (value not drawn)
Катушка индуктивности с керамическим сердечником и золотым покрытием контактных площадок; Номиналиная индуктивность: 180 нГн; Добротность, не менее: 50; Резонансная частота, не менее: 0.92 ГГц; Сопротивление обмотки постоянноми току, не более: 0.64 Ом; Допустимый ток обмотки: 400 мА; Диапазон рабочих температур: от -60 до +125 ℃; Упаковка: Катушка и лента; Типоразмер: 2012 (0805); Технология монтажа: SMT; Изготовитель: АО "НПО "ЭРКОН"
footprint КИК-2012-Зл (Катушка индуктивности с керамическим сердечникомтипоразмер 2012(0805))
pins: 1, 2

## КИК-2012-180 нГн ±10% O
designator L?, comment 180 нГн ±10%  (value not drawn)
Катушка индуктивности с керамическим сердечником и  финишным покрытием контактных площадок оловом; Номиналиная индуктивность: 180 нГн; Добротность, не менее: 50; Резонансная частота, не менее: 0.92 ГГц; Сопротивление обмотки постоянноми току, не более: 0.64 Ом; Допустимый ток обмотки: 400 мА; Диапазон рабочих температур: от -60 до +125 ℃; Упаковка: Катушка и лента; Типоразмер: 2012 (0805); Технология монтажа: SMT; Изготовитель: АО "НПО "ЭРКОН"
footprint КИК-2012-O (Катушка индуктивности с керамическим сердечником типоразмер 2012(0805))
pins: 1, 2

## КИК-2012-180 нГн ±10% Зл
designator L?, comment 180 нГн ±10%  (value not drawn)
Катушка индуктивности с керамическим сердечником и золотым покрытием контактных площадок; Номиналиная индуктивность: 180 нГн; Добротность, не менее: 50; Резонансная частота, не менее: 0.92 ГГц; Сопротивление обмотки постоянноми току, не более: 0.64 Ом; Допустимый ток обмотки: 400 мА; Диапазон рабочих температур: от -60 до +125 ℃; Упаковка: Катушка и лента; Типоразмер: 2012 (0805); Технология монтажа: SMT; Изготовитель: АО "НПО "ЭРКОН"
footprint КИК-2012-Зл (Катушка индуктивности с керамическим сердечникомтипоразмер 2012(0805))
pins: 1, 2

## КИК-2012-180 нГн ±20% O
designator L?, comment 180 нГн ±20%  (value not drawn)
Катушка индуктивности с керамическим сердечником и  финишным покрытием контактных площадок оловом; Номиналиная индуктивность: 180 нГн; Добротность, не менее: 50; Резонансная частота, не менее: 0.92 ГГц; Сопротивление обмотки постоянноми току, не более: 0.64 Ом; Допустимый ток обмотки: 400 мА; Диапазон рабочих температур: от -60 до +125 ℃; Упаковка: Катушка и лента; Типоразмер: 2012 (0805); Технология монтажа: SMT; Изготовитель: АО "НПО "ЭРКОН"
footprint КИК-2012-O (Катушка индуктивности с керамическим сердечником типоразмер 2012(0805))
pins: 1, 2

## КИК-2012-180 нГн ±20% Зл
designator L?, comment 180 нГн ±20%  (value not drawn)
Катушка индуктивности с керамическим сердечником и золотым покрытием контактных площадок; Номиналиная индуктивность: 180 нГн; Добротность, не менее: 50; Резонансная частота, не менее: 0.92 ГГц; Сопротивление обмотки постоянноми току, не более: 0.64 Ом; Допустимый ток обмотки: 400 мА; Диапазон рабочих температур: от -60 до +125 ℃; Упаковка: Катушка и лента; Типоразмер: 2012 (0805); Технология монтажа: SMT; Изготовитель: АО "НПО "ЭРКОН"
footprint КИК-2012-Зл (Катушка индуктивности с керамическим сердечникомтипоразмер 2012(0805))
pins: 1, 2

## КИК-2012-220 нГн ±2% O
designator L?, comment 220 нГн ±2%  (value not drawn)
Катушка индуктивности с керамическим сердечником и  финишным покрытием контактных площадок оловом; Номиналиная индуктивность: 220 нГн; Добротность, не менее: 50; Резонансная частота, не менее: 0.82 ГГц; Сопротивление обмотки постоянноми току, не более: 0.70 Ом; Допустимый ток обмотки: 400 мА; Диапазон рабочих температур: от -60 до +125 ℃; Упаковка: Катушка и лента; Типоразмер: 2012 (0805); Технология монтажа: SMT; Изготовитель: АО "НПО "ЭРКОН"
footprint КИК-2012-O (Катушка индуктивности с керамическим сердечником типоразмер 2012(0805))
pins: 1, 2

## КИК-2012-220 нГн ±2% Зл
designator L?, comment 220 нГн ±2%  (value not drawn)
Катушка индуктивности с керамическим сердечником и золотым покрытием контактных площадок; Номиналиная индуктивность: 220 нГн; Добротность, не менее: 50; Резонансная частота, не менее: 0.82 ГГц; Сопротивление обмотки постоянноми току, не более: 0.70 Ом; Допустимый ток обмотки: 400 мА; Диапазон рабочих температур: от -60 до +125 ℃; Упаковка: Катушка и лента; Типоразмер: 2012 (0805); Технология монтажа: SMT; Изготовитель: АО "НПО "ЭРКОН"
footprint КИК-2012-Зл (Катушка индуктивности с керамическим сердечникомтипоразмер 2012(0805))
pins: 1, 2

## КИК-2012-220 нГн ±5% O
designator L?, comment 220 нГн ±5%  (value not drawn)
Катушка индуктивности с керамическим сердечником и  финишным покрытием контактных площадок оловом; Номиналиная индуктивность: 220 нГн; Добротность, не менее: 50; Резонансная частота, не менее: 0.82 ГГц; Сопротивление обмотки постоянноми току, не более: 0.70 Ом; Допустимый ток обмотки: 400 мА; Диапазон рабочих температур: от -60 до +125 ℃; Упаковка: Катушка и лента; Типоразмер: 2012 (0805); Технология монтажа: SMT; Изготовитель: АО "НПО "ЭРКОН"
footprint КИК-2012-O (Катушка индуктивности с керамическим сердечником типоразмер 2012(0805))
pins: 1, 2

## КИК-2012-220 нГн ±5% Зл
designator L?, comment 220 нГн ±5%  (value not drawn)
Катушка индуктивности с керамическим сердечником и золотым покрытием контактных площадок; Номиналиная индуктивность: 220 нГн; Добротность, не менее: 50; Резонансная частота, не менее: 0.82 ГГц; Сопротивление обмотки постоянноми току, не более: 0.70 Ом; Допустимый ток обмотки: 400 мА; Диапазон рабочих температур: от -60 до +125 ℃; Упаковка: Катушка и лента; Типоразмер: 2012 (0805); Технология монтажа: SMT; Изготовитель: АО "НПО "ЭРКОН"
footprint КИК-2012-Зл (Катушка индуктивности с керамическим сердечникомтипоразмер 2012(0805))
pins: 1, 2

## КИК-2012-220 нГн ±10% O
designator L?, comment 220 нГн ±10%  (value not drawn)
Катушка индуктивности с керамическим сердечником и  финишным покрытием контактных площадок оловом; Номиналиная индуктивность: 220 нГн; Добротность, не менее: 50; Резонансная частота, не менее: 0.82 ГГц; Сопротивление обмотки постоянноми току, не более: 0.70 Ом; Допустимый ток обмотки: 400 мА; Диапазон рабочих температур: от -60 до +125 ℃; Упаковка: Катушка и лента; Типоразмер: 2012 (0805); Технология монтажа: SMT; Изготовитель: АО "НПО "ЭРКОН"
footprint КИК-2012-O (Катушка индуктивности с керамическим сердечником типоразмер 2012(0805))
pins: 1, 2

## КИК-2012-220 нГн ±10% Зл
designator L?, comment 220 нГн ±10%  (value not drawn)
Катушка индуктивности с керамическим сердечником и золотым покрытием контактных площадок; Номиналиная индуктивность: 220 нГн; Добротность, не менее: 50; Резонансная частота, не менее: 0.82 ГГц; Сопротивление обмотки постоянноми току, не более: 0.70 Ом; Допустимый ток обмотки: 400 мА; Диапазон рабочих температур: от -60 до +125 ℃; Упаковка: Катушка и лента; Типоразмер: 2012 (0805); Технология монтажа: SMT; Изготовитель: АО "НПО "ЭРКОН"
footprint КИК-2012-Зл (Катушка индуктивности с керамическим сердечникомтипоразмер 2012(0805))
pins: 1, 2

## КИК-2012-220 нГн ±20% O
designator L?, comment 220 нГн ±20%  (value not drawn)
Катушка индуктивности с керамическим сердечником и  финишным покрытием контактных площадок оловом; Номиналиная индуктивность: 220 нГн; Добротность, не менее: 50; Резонансная частота, не менее: 0.82 ГГц; Сопротивление обмотки постоянноми току, не более: 0.70 Ом; Допустимый ток обмотки: 400 мА; Диапазон рабочих температур: от -60 до +125 ℃; Упаковка: Катушка и лента; Типоразмер: 2012 (0805); Технология монтажа: SMT; Изготовитель: АО "НПО "ЭРКОН"
footprint КИК-2012-O (Катушка индуктивности с керамическим сердечником типоразмер 2012(0805))
pins: 1, 2

## КИК-2012-220 нГн ±20% Зл
designator L?, comment 220 нГн ±20%  (value not drawn)
Катушка индуктивности с керамическим сердечником и золотым покрытием контактных площадок; Номиналиная индуктивность: 220 нГн; Добротность, не менее: 50; Резонансная частота, не менее: 0.82 ГГц; Сопротивление обмотки постоянноми току, не более: 0.70 Ом; Допустимый ток обмотки: 400 мА; Диапазон рабочих температур: от -60 до +125 ℃; Упаковка: Катушка и лента; Типоразмер: 2012 (0805); Технология монтажа: SMT; Изготовитель: АО "НПО "ЭРКОН"
footprint КИК-2012-Зл (Катушка индуктивности с керамическим сердечникомтипоразмер 2012(0805))
pins: 1, 2

## КИК-2012-240 нГн ±2% O
designator L?, comment 240 нГн ±2%  (value not drawn)
Катушка индуктивности с керамическим сердечником и  финишным покрытием контактных площадок оловом; Номиналиная индуктивность: 240 нГн; Добротность, не менее: 45; Резонансная частота, не менее: 0.77 ГГц; Сопротивление обмотки постоянноми току, не более: 1.0 Ом; Допустимый ток обмотки: 350 мА; Диапазон рабочих температур: от -60 до +125 ℃; Упаковка: Катушка и лента; Типоразмер: 2012 (0805); Технология монтажа: SMT; Изготовитель: АО "НПО "ЭРКОН"
footprint КИК-2012-O (Катушка индуктивности с керамическим сердечником типоразмер 2012(0805))
pins: 1, 2

## КИК-2012-240 нГн ±2% Зл
designator L?, comment 240 нГн ±2%  (value not drawn)
Катушка индуктивности с керамическим сердечником и золотым покрытием контактных площадок; Номиналиная индуктивность: 240 нГн; Добротность, не менее: 45; Резонансная частота, не менее: 0.77 ГГц; Сопротивление обмотки постоянноми току, не более: 1.0 Ом; Допустимый ток обмотки: 350 мА; Диапазон рабочих температур: от -60 до +125 ℃; Упаковка: Катушка и лента; Типоразмер: 2012 (0805); Технология монтажа: SMT; Изготовитель: АО "НПО "ЭРКОН"
footprint КИК-2012-Зл (Катушка индуктивности с керамическим сердечникомтипоразмер 2012(0805))
pins: 1, 2

## КИК-2012-240 нГн ±5% O
designator L?, comment 240 нГн ±5%  (value not drawn)
Катушка индуктивности с керамическим сердечником и  финишным покрытием контактных площадок оловом; Номиналиная индуктивность: 240 нГн; Добротность, не менее: 45; Резонансная частота, не менее: 0.77 ГГц; Сопротивление обмотки постоянноми току, не более: 1.0 Ом; Допустимый ток обмотки: 350 мА; Диапазон рабочих температур: от -60 до +125 ℃; Упаковка: Катушка и лента; Типоразмер: 2012 (0805); Технология монтажа: SMT; Изготовитель: АО "НПО "ЭРКОН"
footprint КИК-2012-O (Катушка индуктивности с керамическим сердечником типоразмер 2012(0805))
pins: 1, 2

## КИК-2012-240 нГн ±5% Зл
designator L?, comment 240 нГн ±5%  (value not drawn)
Катушка индуктивности с керамическим сердечником и золотым покрытием контактных площадок; Номиналиная индуктивность: 240 нГн; Добротность, не менее: 45; Резонансная частота, не менее: 0.77 ГГц; Сопротивление обмотки постоянноми току, не более: 1.0 Ом; Допустимый ток обмотки: 350 мА; Диапазон рабочих температур: от -60 до +125 ℃; Упаковка: Катушка и лента; Типоразмер: 2012 (0805); Технология монтажа: SMT; Изготовитель: АО "НПО "ЭРКОН"
footprint КИК-2012-Зл (Катушка индуктивности с керамическим сердечникомтипоразмер 2012(0805))
pins: 1, 2

## КИК-2012-240 нГн ±10% O
designator L?, comment 240 нГн ±10%  (value not drawn)
Катушка индуктивности с керамическим сердечником и  финишным покрытием контактных площадок оловом; Номиналиная индуктивность: 240 нГн; Добротность, не менее: 45; Резонансная частота, не менее: 0.77 ГГц; Сопротивление обмотки постоянноми току, не более: 1.0 Ом; Допустимый ток обмотки: 350 мА; Диапазон рабочих температур: от -60 до +125 ℃; Упаковка: Катушка и лента; Типоразмер: 2012 (0805); Технология монтажа: SMT; Изготовитель: АО "НПО "ЭРКОН"
footprint КИК-2012-O (Катушка индуктивности с керамическим сердечником типоразмер 2012(0805))
pins: 1, 2

## КИК-2012-240 нГн ±10% Зл
designator L?, comment 240 нГн ±10%  (value not drawn)
Катушка индуктивности с керамическим сердечником и золотым покрытием контактных площадок; Номиналиная индуктивность: 240 нГн; Добротность, не менее: 45; Резонансная частота, не менее: 0.77 ГГц; Сопротивление обмотки постоянноми току, не более: 1.0 Ом; Допустимый ток обмотки: 350 мА; Диапазон рабочих температур: от -60 до +125 ℃; Упаковка: Катушка и лента; Типоразмер: 2012 (0805); Технология монтажа: SMT; Изготовитель: АО "НПО "ЭРКОН"
footprint КИК-2012-Зл (Катушка индуктивности с керамическим сердечникомтипоразмер 2012(0805))
pins: 1, 2

## КИК-2012-240 нГн ±20% O
designator L?, comment 240 нГн ±20%  (value not drawn)
Катушка индуктивности с керамическим сердечником и  финишным покрытием контактных площадок оловом; Номиналиная индуктивность: 240 нГн; Добротность, не менее: 45; Резонансная частота, не менее: 0.77 ГГц; Сопротивление обмотки постоянноми току, не более: 1.0 Ом; Допустимый ток обмотки: 350 мА; Диапазон рабочих температур: от -60 до +125 ℃; Упаковка: Катушка и лента; Типоразмер: 2012 (0805); Технология монтажа: SMT; Изготовитель: АО "НПО "ЭРКОН"
footprint КИК-2012-O (Катушка индуктивности с керамическим сердечником типоразмер 2012(0805))
pins: 1, 2

## КИК-2012-240 нГн ±20% Зл
designator L?, comment 240 нГн ±20%  (value not drawn)
Катушка индуктивности с керамическим сердечником и золотым покрытием контактных площадок; Номиналиная индуктивность: 240 нГн; Добротность, не менее: 45; Резонансная частота, не менее: 0.77 ГГц; Сопротивление обмотки постоянноми току, не более: 1.0 Ом; Допустимый ток обмотки: 350 мА; Диапазон рабочих температур: от -60 до +125 ℃; Упаковка: Катушка и лента; Типоразмер: 2012 (0805); Технология монтажа: SMT; Изготовитель: АО "НПО "ЭРКОН"
footprint КИК-2012-Зл (Катушка индуктивности с керамическим сердечникомтипоразмер 2012(0805))
pins: 1, 2

## КИК-2012-270 нГн ±2% O
designator L?, comment 270 нГн ±2%  (value not drawn)
Катушка индуктивности с керамическим сердечником и  финишным покрытием контактных площадок оловом; Номиналиная индуктивность: 270 нГн; Добротность, не менее: 45; Резонансная частота, не менее: 0.73 ГГц; Сопротивление обмотки постоянноми току, не более: 1.0 Ом; Допустимый ток обмотки: 350 мА; Диапазон рабочих температур: от -60 до +125 ℃; Упаковка: Катушка и лента; Типоразмер: 2012 (0805); Технология монтажа: SMT; Изготовитель: АО "НПО "ЭРКОН"
footprint КИК-2012-O (Катушка индуктивности с керамическим сердечником типоразмер 2012(0805))
pins: 1, 2

## КИК-2012-270 нГн ±2% Зл
designator L?, comment 270 нГн ±2%  (value not drawn)
Катушка индуктивности с керамическим сердечником и золотым покрытием контактных площадок; Номиналиная индуктивность: 270 нГн; Добротность, не менее: 45; Резонансная частота, не менее: 0.73 ГГц; Сопротивление обмотки постоянноми току, не более: 1.0 Ом; Допустимый ток обмотки: 350 мА; Диапазон рабочих температур: от -60 до +125 ℃; Упаковка: Катушка и лента; Типоразмер: 2012 (0805); Технология монтажа: SMT; Изготовитель: АО "НПО "ЭРКОН"
footprint КИК-2012-Зл (Катушка индуктивности с керамическим сердечникомтипоразмер 2012(0805))
pins: 1, 2

## КИК-2012-270 нГн ±5% O
designator L?, comment 270 нГн ±5%  (value not drawn)
Катушка индуктивности с керамическим сердечником и  финишным покрытием контактных площадок оловом; Номиналиная индуктивность: 270 нГн; Добротность, не менее: 45; Резонансная частота, не менее: 0.73 ГГц; Сопротивление обмотки постоянноми току, не более: 1.0 Ом; Допустимый ток обмотки: 350 мА; Диапазон рабочих температур: от -60 до +125 ℃; Упаковка: Катушка и лента; Типоразмер: 2012 (0805); Технология монтажа: SMT; Изготовитель: АО "НПО "ЭРКОН"
footprint КИК-2012-O (Катушка индуктивности с керамическим сердечником типоразмер 2012(0805))
pins: 1, 2

## КИК-2012-270 нГн ±5% Зл
designator L?, comment 270 нГн ±5%  (value not drawn)
Катушка индуктивности с керамическим сердечником и золотым покрытием контактных площадок; Номиналиная индуктивность: 270 нГн; Добротность, не менее: 45; Резонансная частота, не менее: 0.73 ГГц; Сопротивление обмотки постоянноми току, не более: 1.0 Ом; Допустимый ток обмотки: 350 мА; Диапазон рабочих температур: от -60 до +125 ℃; Упаковка: Катушка и лента; Типоразмер: 2012 (0805); Технология монтажа: SMT; Изготовитель: АО "НПО "ЭРКОН"
footprint КИК-2012-Зл (Катушка индуктивности с керамическим сердечникомтипоразмер 2012(0805))
pins: 1, 2

## КИК-2012-270 нГн ±10% O
designator L?, comment 270 нГн ±10%  (value not drawn)
Катушка индуктивности с керамическим сердечником и  финишным покрытием контактных площадок оловом; Номиналиная индуктивность: 270 нГн; Добротность, не менее: 45; Резонансная частота, не менее: 0.73 ГГц; Сопротивление обмотки постоянноми току, не более: 1.0 Ом; Допустимый ток обмотки: 350 мА; Диапазон рабочих температур: от -60 до +125 ℃; Упаковка: Катушка и лента; Типоразмер: 2012 (0805); Технология монтажа: SMT; Изготовитель: АО "НПО "ЭРКОН"
footprint КИК-2012-O (Катушка индуктивности с керамическим сердечником типоразмер 2012(0805))
pins: 1, 2

## КИК-2012-270 нГн ±10% Зл
designator L?, comment 270 нГн ±10%  (value not drawn)
Катушка индуктивности с керамическим сердечником и золотым покрытием контактных площадок; Номиналиная индуктивность: 270 нГн; Добротность, не менее: 45; Резонансная частота, не менее: 0.73 ГГц; Сопротивление обмотки постоянноми току, не более: 1.0 Ом; Допустимый ток обмотки: 350 мА; Диапазон рабочих температур: от -60 до +125 ℃; Упаковка: Катушка и лента; Типоразмер: 2012 (0805); Технология монтажа: SMT; Изготовитель: АО "НПО "ЭРКОН"
footprint КИК-2012-Зл (Катушка индуктивности с керамическим сердечникомтипоразмер 2012(0805))
pins: 1, 2

## КИК-2012-270 нГн ±20% O
designator L?, comment 270 нГн ±10%  (value not drawn)
Катушка индуктивности с керамическим сердечником и  финишным покрытием контактных площадок оловом; Номиналиная индуктивность: 270 нГн; Допускаемое отклонение индуктивности: ±20%; Добротность, не менее: 45; Резонансная частота, не менее: 0.73 ГГц; Сопротивление обмотки постоянноми току, не более: 1.0 Ом; Допустимый ток обмотки: 350 мА; Диапазон рабочих температур: от -60 до +125 ℃; Упаковка: Катушка и лента; Типоразмер: 2012 (0805); Технология монтажа: SMT; Изготовитель: АО "НПО "ЭРКОН"
footprint КИК-2012-O (Катушка индуктивности с керамическим сердечником типоразмер 2012(0805))
pins: 1, 2

## КИК-2012-270 нГн ±20% Зл
designator L?, comment 270 нГн ±20%  (value not drawn)
Катушка индуктивности с керамическим сердечником и золотым покрытием контактных площадок; Номиналиная индуктивность: 270 нГн; Добротность, не менее: 45; Резонансная частота, не менее: 0.73 ГГц; Сопротивление обмотки постоянноми току, не более: 1.0 Ом; Допустимый ток обмотки: 350 мА; Диапазон рабочих температур: от -60 до +125 ℃; Упаковка: Катушка и лента; Типоразмер: 2012 (0805); Технология монтажа: SMT; Изготовитель: АО "НПО "ЭРКОН"
footprint КИК-2012-Зл (Катушка индуктивности с керамическим сердечникомтипоразмер 2012(0805))
pins: 1, 2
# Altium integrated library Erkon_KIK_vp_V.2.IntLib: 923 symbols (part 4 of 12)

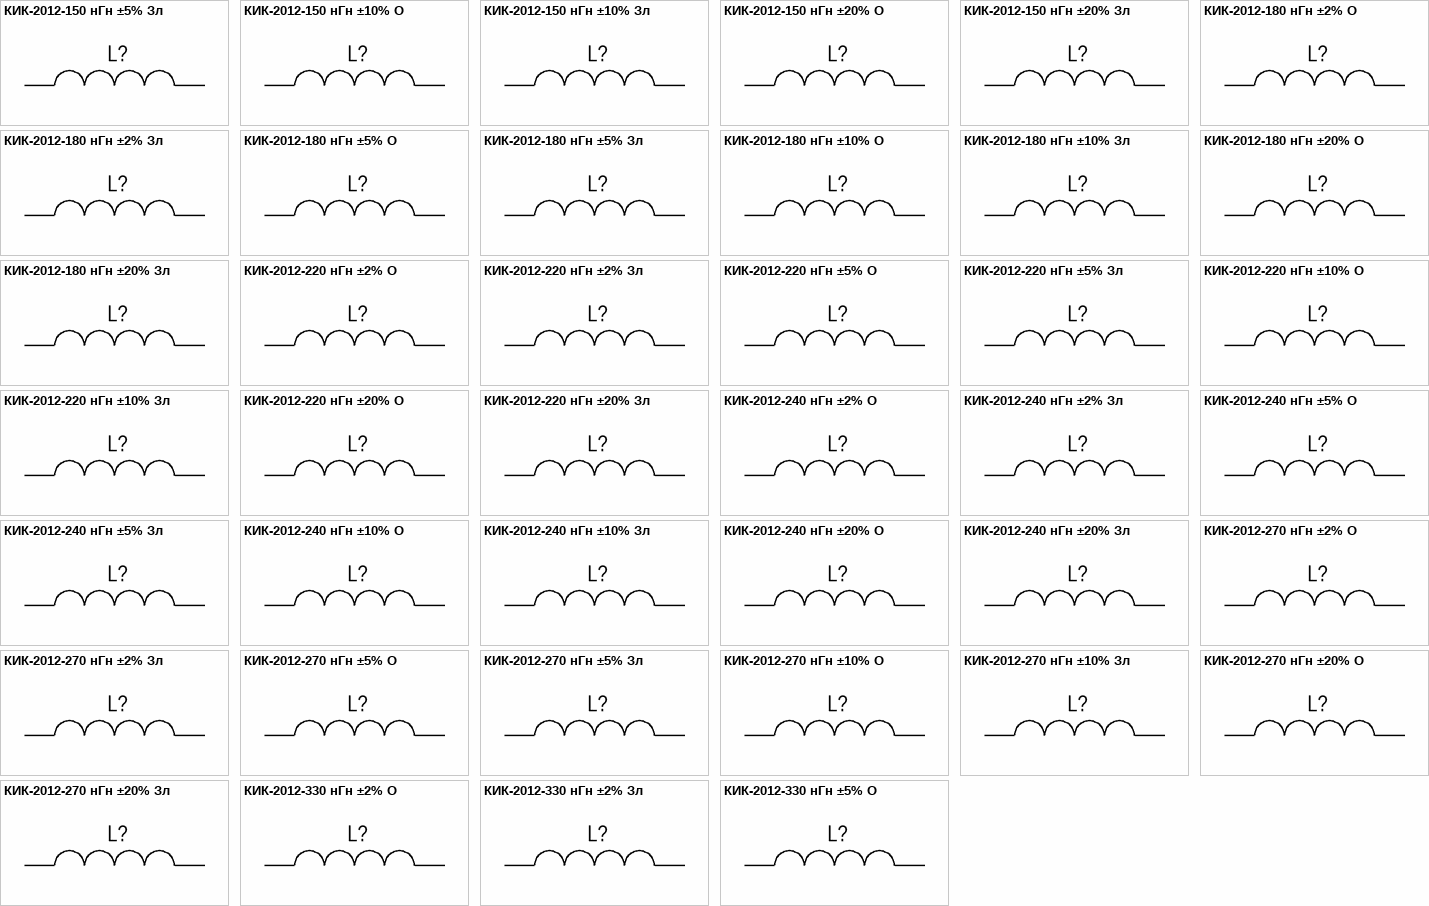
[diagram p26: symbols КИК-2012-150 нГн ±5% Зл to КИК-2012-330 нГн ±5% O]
## КИК-2012-330 нГн ±2% O
designator L?, comment 330 нГн ±2%  (value not drawn)
Катушка индуктивности с керамическим сердечником и  финишным покрытием контактных площадок оловом; Номиналиная индуктивность: 330 нГн; Добротность, не менее: 45; Резонансная частота, не менее: 0.65 ГГц; Сопротивление обмотки постоянноми току, не более: 1.4 Ом; Допустимый ток обмотки: 310 мА; Диапазон рабочих температур: от -60 до +125 ℃; Упаковка: Катушка и лента; Типоразмер: 2012 (0805); Технология монтажа: SMT; Изготовитель: АО "НПО "ЭРКОН"
footprint КИК-2012-O (Катушка индуктивности с керамическим сердечником типоразмер 2012(0805))
pins: 1, 2

## КИК-2012-330 нГн ±2% Зл
designator L?, comment 330 нГн ±2%  (value not drawn)
Катушка индуктивности с керамическим сердечником и золотым покрытием контактных площадок; Номиналиная индуктивность: 330 нГн; Добротность, не менее: 45; Резонансная частота, не менее: 0.65 ГГц; Сопротивление обмотки постоянноми току, не более: 1.4 Ом; Допустимый ток обмотки: 310 мА; Диапазон рабочих температур: от -60 до +125 ℃; Упаковка: Катушка и лента; Типоразмер: 2012 (0805); Технология монтажа: SMT; Изготовитель: АО "НПО "ЭРКОН"
footprint КИК-2012-Зл (Катушка индуктивности с керамическим сердечникомтипоразмер 2012(0805))
pins: 1, 2

## КИК-2012-330 нГн ±5% O
designator L?, comment 330 нГн ±5%  (value not drawn)
Катушка индуктивности с керамическим сердечником и  финишным покрытием контактных площадок оловом; Номиналиная индуктивность: 330 нГн; Добротность, не менее: 45; Резонансная частота, не менее: 0.65 ГГц; Сопротивление обмотки постоянноми току, не более: 1.4 Ом; Допустимый ток обмотки: 310 мА; Диапазон рабочих температур: от -60 до +125 ℃; Упаковка: Катушка и лента; Типоразмер: 2012 (0805); Технология монтажа: SMT; Изготовитель: АО "НПО "ЭРКОН"
footprint КИК-2012-O (Катушка индуктивности с керамическим сердечником типоразмер 2012(0805))
pins: 1, 2


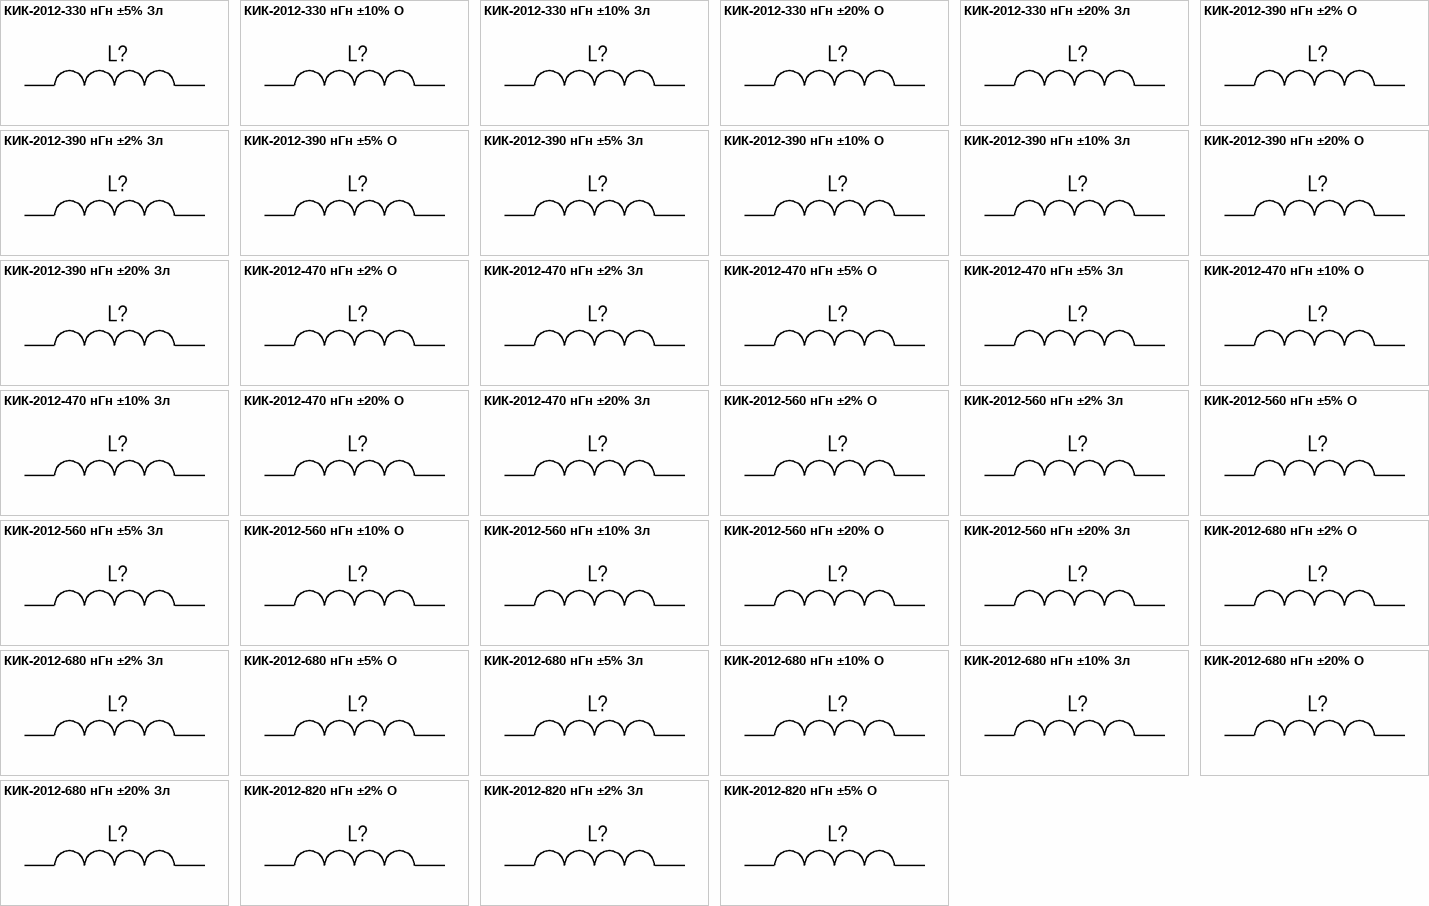
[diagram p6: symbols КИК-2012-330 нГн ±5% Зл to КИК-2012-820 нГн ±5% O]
## КИК-2012-330 нГн ±5% Зл
designator L?, comment 330 нГн ±5%  (value not drawn)
Катушка индуктивности с керамическим сердечником и золотым покрытием контактных площадок; Номиналиная индуктивность: 330 нГн; Добротность, не менее: 45; Резонансная частота, не менее: 0.65 ГГц; Сопротивление обмотки постоянноми току, не более: 1.4 Ом; Допустимый ток обмотки: 310 мА; Диапазон рабочих температур: от -60 до +125 ℃; Упаковка: Катушка и лента; Типоразмер: 2012 (0805); Технология монтажа: SMT; Изготовитель: АО "НПО "ЭРКОН"
footprint КИК-2012-Зл (Катушка индуктивности с керамическим сердечникомтипоразмер 2012(0805))
pins: 1, 2

## КИК-2012-330 нГн ±10% O
designator L?, comment 330 нГн ±10%  (value not drawn)
Катушка индуктивности с керамическим сердечником и  финишным покрытием контактных площадок оловом; Номиналиная индуктивность: 330 нГн; Добротность, не менее: 45; Резонансная частота, не менее: 0.65 ГГц; Сопротивление обмотки постоянноми току, не более: 1.4 Ом; Допустимый ток обмотки: 310 мА; Диапазон рабочих температур: от -60 до +125 ℃; Упаковка: Катушка и лента; Типоразмер: 2012 (0805); Технология монтажа: SMT; Изготовитель: АО "НПО "ЭРКОН"
footprint КИК-2012-O (Катушка индуктивности с керамическим сердечником типоразмер 2012(0805))
pins: 1, 2

## КИК-2012-330 нГн ±10% Зл
designator L?, comment 330 нГн ±10%  (value not drawn)
Катушка индуктивности с керамическим сердечником и золотым покрытием контактных площадок; Номиналиная индуктивность: 330 нГн; Добротность, не менее: 45; Резонансная частота, не менее: 0.65 ГГц; Сопротивление обмотки постоянноми току, не более: 1.4 Ом; Допустимый ток обмотки: 310 мА; Диапазон рабочих температур: от -60 до +125 ℃; Упаковка: Катушка и лента; Типоразмер: 2012 (0805); Технология монтажа: SMT; Изготовитель: АО "НПО "ЭРКОН"
footprint КИК-2012-Зл (Катушка индуктивности с керамическим сердечникомтипоразмер 2012(0805))
pins: 1, 2

## КИК-2012-330 нГн ±20% O
designator L?, comment 330 нГн ±20%  (value not drawn)
Катушка индуктивности с керамическим сердечником и  финишным покрытием контактных площадок оловом; Номиналиная индуктивность: 330 нГн; Добротность, не менее: 45; Резонансная частота, не менее: 0.65 ГГц; Сопротивление обмотки постоянноми току, не более: 1.4 Ом; Допустимый ток обмотки: 310 мА; Диапазон рабочих температур: от -60 до +125 ℃; Упаковка: Катушка и лента; Типоразмер: 2012 (0805); Технология монтажа: SMT; Изготовитель: АО "НПО "ЭРКОН"
footprint КИК-2012-O (Катушка индуктивности с керамическим сердечником типоразмер 2012(0805))
pins: 1, 2

## КИК-2012-330 нГн ±20% Зл
designator L?, comment 330 нГн ±20%  (value not drawn)
Катушка индуктивности с керамическим сердечником и золотым покрытием контактных площадок; Номиналиная индуктивность: 330 нГн; Добротность, не менее: 45; Резонансная частота, не менее: 0.65 ГГц; Сопротивление обмотки постоянноми току, не более: 1.4 Ом; Допустимый ток обмотки: 310 мА; Диапазон рабочих температур: от -60 до +125 ℃; Упаковка: Катушка и лента; Типоразмер: 2012 (0805); Технология монтажа: SMT; Изготовитель: АО "НПО "ЭРКОН"
footprint КИК-2012-Зл (Катушка индуктивности с керамическим сердечникомтипоразмер 2012(0805))
pins: 1, 2

## КИК-2012-390 нГн ±2% O
designator L?, comment 390 нГн ±2%  (value not drawn)
Катушка индуктивности с керамическим сердечником и  финишным покрытием контактных площадок оловом; Номиналиная индуктивность: 390 нГн; Добротность, не менее: 45; Резонансная частота, не менее: 0.60 ГГц; Сопротивление обмотки постоянноми току, не более: 1.5 Ом; Допустимый ток обмотки: 290 мА; Диапазон рабочих температур: от -60 до +125 ℃; Упаковка: Катушка и лента; Типоразмер: 2012 (0805); Технология монтажа: SMT; Изготовитель: АО "НПО "ЭРКОН"
footprint КИК-2012-O (Катушка индуктивности с керамическим сердечником типоразмер 2012(0805))
pins: 1, 2

## КИК-2012-390 нГн ±2% Зл
designator L?, comment 390 нГн ±2%  (value not drawn)
Катушка индуктивности с керамическим сердечником и золотым покрытием контактных площадок; Номиналиная индуктивность: 390 нГн; Добротность, не менее: 45; Резонансная частота, не менее: 0.60 ГГц; Сопротивление обмотки постоянноми току, не более: 1.5 Ом; Допустимый ток обмотки: 290 мА; Диапазон рабочих температур: от -60 до +125 ℃; Упаковка: Катушка и лента; Типоразмер: 2012 (0805); Технология монтажа: SMT; Изготовитель: АО "НПО "ЭРКОН"
footprint КИК-2012-Зл (Катушка индуктивности с керамическим сердечникомтипоразмер 2012(0805))
pins: 1, 2

## КИК-2012-390 нГн ±5% O
designator L?, comment 390 нГн ±5%  (value not drawn)
Катушка индуктивности с керамическим сердечником и  финишным покрытием контактных площадок оловом; Номиналиная индуктивность: 390 нГн; Добротность, не менее: 45; Резонансная частота, не менее: 0.60 ГГц; Сопротивление обмотки постоянноми току, не более: 1.5 Ом; Допустимый ток обмотки: 290 мА; Диапазон рабочих температур: от -60 до +125 ℃; Упаковка: Катушка и лента; Типоразмер: 2012 (0805); Технология монтажа: SMT; Изготовитель: АО "НПО "ЭРКОН"
footprint КИК-2012-O (Катушка индуктивности с керамическим сердечником типоразмер 2012(0805))
pins: 1, 2

## КИК-2012-390 нГн ±5% Зл
designator L?, comment 390 нГн ±5%  (value not drawn)
Катушка индуктивности с керамическим сердечником и золотым покрытием контактных площадок; Номиналиная индуктивность: 390 нГн; Добротность, не менее: 45; Резонансная частота, не менее: 0.60 ГГц; Сопротивление обмотки постоянноми току, не более: 1.5 Ом; Допустимый ток обмотки: 290 мА; Диапазон рабочих температур: от -60 до +125 ℃; Упаковка: Катушка и лента; Типоразмер: 2012 (0805); Технология монтажа: SMT; Изготовитель: АО "НПО "ЭРКОН"
footprint КИК-2012-Зл (Катушка индуктивности с керамическим сердечникомтипоразмер 2012(0805))
pins: 1, 2

## КИК-2012-390 нГн ±10% O
designator L?, comment 390 нГн ±10%  (value not drawn)
Катушка индуктивности с керамическим сердечником и  финишным покрытием контактных площадок оловом; Номиналиная индуктивность: 390 нГн; Добротность, не менее: 45; Резонансная частота, не менее: 0.60 ГГц; Сопротивление обмотки постоянноми току, не более: 1.5 Ом; Допустимый ток обмотки: 290 мА; Диапазон рабочих температур: от -60 до +125 ℃; Упаковка: Катушка и лента; Типоразмер: 2012 (0805); Технология монтажа: SMT; Изготовитель: АО "НПО "ЭРКОН"
footprint КИК-2012-O (Катушка индуктивности с керамическим сердечником типоразмер 2012(0805))
pins: 1, 2

## КИК-2012-390 нГн ±10% Зл
designator L?, comment 390 нГн ±10%  (value not drawn)
Катушка индуктивности с керамическим сердечником и золотым покрытием контактных площадок; Номиналиная индуктивность: 390 нГн; Добротность, не менее: 45; Резонансная частота, не менее: 0.60 ГГц; Сопротивление обмотки постоянноми току, не более: 1.5 Ом; Допустимый ток обмотки: 290 мА; Диапазон рабочих температур: от -60 до +125 ℃; Упаковка: Катушка и лента; Типоразмер: 2012 (0805); Технология монтажа: SMT; Изготовитель: АО "НПО "ЭРКОН"
footprint КИК-2012-Зл (Катушка индуктивности с керамическим сердечникомтипоразмер 2012(0805))
pins: 1, 2

## КИК-2012-390 нГн ±20% O
designator L?, comment 390 нГн ±20%  (value not drawn)
Катушка индуктивности с керамическим сердечником и  финишным покрытием контактных площадок оловом; Номиналиная индуктивность: 390 нГн; Добротность, не менее: 45; Резонансная частота, не менее: 0.60 ГГц; Сопротивление обмотки постоянноми току, не более: 1.5 Ом; Допустимый ток обмотки: 290 мА; Диапазон рабочих температур: от -60 до +125 ℃; Упаковка: Катушка и лента; Типоразмер: 2012 (0805); Технология монтажа: SMT; Изготовитель: АО "НПО "ЭРКОН"
footprint КИК-2012-O (Катушка индуктивности с керамическим сердечником типоразмер 2012(0805))
pins: 1, 2

## КИК-2012-390 нГн ±20% Зл
designator L?, comment 390 нГн ±20%  (value not drawn)
Катушка индуктивности с керамическим сердечником и золотым покрытием контактных площадок; Номиналиная индуктивность: 390 нГн; Добротность, не менее: 45; Резонансная частота, не менее: 0.60 ГГц; Сопротивление обмотки постоянноми току, не более: 1.5 Ом; Допустимый ток обмотки: 290 мА; Диапазон рабочих температур: от -60 до +125 ℃; Упаковка: Катушка и лента; Типоразмер: 2012 (0805); Технология монтажа: SMT; Изготовитель: АО "НПО "ЭРКОН"
footprint КИК-2012-Зл (Катушка индуктивности с керамическим сердечникомтипоразмер 2012(0805))
pins: 1, 2

## КИК-2012-470 нГн ±2% O
designator L?, comment 470 нГн ±2%  (value not drawn)
Катушка индуктивности с керамическим сердечником и  финишным покрытием контактных площадок оловом; Номиналиная индуктивность: 470 нГн; Добротность, не менее: 33; Резонансная частота, не менее: 0.375 ГГц; Сопротивление обмотки постоянноми току, не более: 1.76 Ом; Допустимый ток обмотки: 250 мА; Диапазон рабочих температур: от -60 до +125 ℃; Упаковка: Катушка и лента; Типоразмер: 2012 (0805); Технология монтажа: SMT; Изготовитель: АО "НПО "ЭРКОН"
footprint КИК-2012-O (Катушка индуктивности с керамическим сердечником типоразмер 2012(0805))
pins: 1, 2

## КИК-2012-470 нГн ±2% Зл
designator L?, comment 470 нГн ±2%  (value not drawn)
Катушка индуктивности с керамическим сердечником и золотым покрытием контактных площадок; Номиналиная индуктивность: 470 нГн; Добротность, не менее: 33; Резонансная частота, не менее: 0.375 ГГц; Сопротивление обмотки постоянноми току, не более: 1.76 Ом; Допустимый ток обмотки: 250 мА; Диапазон рабочих температур: от -60 до +125 ℃; Упаковка: Катушка и лента; Типоразмер: 2012 (0805); Технология монтажа: SMT; Изготовитель: АО "НПО "ЭРКОН"
footprint КИК-2012-Зл (Катушка индуктивности с керамическим сердечникомтипоразмер 2012(0805))
pins: 1, 2

## КИК-2012-470 нГн ±5% O
designator L?, comment 470 нГн ±5%  (value not drawn)
Катушка индуктивности с керамическим сердечником и  финишным покрытием контактных площадок оловом; Номиналиная индуктивность: 470 нГн; Добротность, не менее: 33; Резонансная частота, не менее: 0.375 ГГц; Сопротивление обмотки постоянноми току, не более: 1.76 Ом; Допустимый ток обмотки: 250 мА; Диапазон рабочих температур: от -60 до +125 ℃; Упаковка: Катушка и лента; Типоразмер: 2012 (0805); Технология монтажа: SMT; Изготовитель: АО "НПО "ЭРКОН"
footprint КИК-2012-O (Катушка индуктивности с керамическим сердечником типоразмер 2012(0805))
pins: 1, 2

## КИК-2012-470 нГн ±5% Зл
designator L?, comment 470 нГн ±5%  (value not drawn)
Катушка индуктивности с керамическим сердечником и золотым покрытием контактных площадок; Номиналиная индуктивность: 470 нГн; Добротность, не менее: 33; Резонансная частота, не менее: 0.375 ГГц; Сопротивление обмотки постоянноми току, не более: 1.76 Ом; Допустимый ток обмотки: 250 мА; Диапазон рабочих температур: от -60 до +125 ℃; Упаковка: Катушка и лента; Типоразмер: 2012 (0805); Технология монтажа: SMT; Изготовитель: АО "НПО "ЭРКОН"
footprint КИК-2012-Зл (Катушка индуктивности с керамическим сердечникомтипоразмер 2012(0805))
pins: 1, 2

## КИК-2012-470 нГн ±10% O
designator L?, comment 470 нГн ±10%  (value not drawn)
Катушка индуктивности с керамическим сердечником и  финишным покрытием контактных площадок оловом; Номиналиная индуктивность: 470 нГн; Добротность, не менее: 33; Резонансная частота, не менее: 0.375 ГГц; Сопротивление обмотки постоянноми току, не более: 1.76 Ом; Допустимый ток обмотки: 250 мА; Диапазон рабочих температур: от -60 до +125 ℃; Упаковка: Катушка и лента; Типоразмер: 2012 (0805); Технология монтажа: SMT; Изготовитель: АО "НПО "ЭРКОН"
footprint КИК-2012-O (Катушка индуктивности с керамическим сердечником типоразмер 2012(0805))
pins: 1, 2

## КИК-2012-470 нГн ±10% Зл
designator L?, comment 470 нГн ±10%  (value not drawn)
Катушка индуктивности с керамическим сердечником и золотым покрытием контактных площадок; Номиналиная индуктивность: 470 нГн; Добротность, не менее: 33; Резонансная частота, не менее: 0.375 ГГц; Сопротивление обмотки постоянноми току, не более: 1.76 Ом; Допустимый ток обмотки: 250 мА; Диапазон рабочих температур: от -60 до +125 ℃; Упаковка: Катушка и лента; Типоразмер: 2012 (0805); Технология монтажа: SMT; Изготовитель: АО "НПО "ЭРКОН"
footprint КИК-2012-Зл (Катушка индуктивности с керамическим сердечникомтипоразмер 2012(0805))
pins: 1, 2

## КИК-2012-470 нГн ±20% O
designator L?, comment 470 нГн ±20%  (value not drawn)
Катушка индуктивности с керамическим сердечником и  финишным покрытием контактных площадок оловом; Номиналиная индуктивность: 470 нГн; Добротность, не менее: 33; Резонансная частота, не менее: 0.375 ГГц; Сопротивление обмотки постоянноми току, не более: 1.76 Ом; Допустимый ток обмотки: 250 мА; Диапазон рабочих температур: от -60 до +125 ℃; Упаковка: Катушка и лента; Типоразмер: 2012 (0805); Технология монтажа: SMT; Изготовитель: АО "НПО "ЭРКОН"
footprint КИК-2012-O (Катушка индуктивности с керамическим сердечником типоразмер 2012(0805))
pins: 1, 2

## КИК-2012-470 нГн ±20% Зл
designator L?, comment 470 нГн ±20%  (value not drawn)
Катушка индуктивности с керамическим сердечником и золотым покрытием контактных площадок; Номиналиная индуктивность: 470 нГн; Добротность, не менее: 33; Резонансная частота, не менее: 0.375 ГГц; Сопротивление обмотки постоянноми току, не более: 1.76 Ом; Допустимый ток обмотки: 250 мА; Диапазон рабочих температур: от -60 до +125 ℃; Упаковка: Катушка и лента; Типоразмер: 2012 (0805); Технология монтажа: SMT; Изготовитель: АО "НПО "ЭРКОН"
footprint КИК-2012-Зл (Катушка индуктивности с керамическим сердечникомтипоразмер 2012(0805))
pins: 1, 2

## КИК-2012-560 нГн ±2% O
designator L?, comment 560 нГн ±2%  (value not drawn)
Катушка индуктивности с керамическим сердечником и  финишным покрытием контактных площадок оловом; Номиналиная индуктивность: 560 нГн; Добротность, не менее: 23; Резонансная частота, не менее: 0.330 ГГц; Сопротивление обмотки постоянноми току, не более: 1.9 Ом; Допустимый ток обмотки: 230 мА; Диапазон рабочих температур: от -60 до +125 ℃; Упаковка: Катушка и лента; Типоразмер: 2012 (0805); Технология монтажа: SMT; Изготовитель: АО "НПО "ЭРКОН"
footprint КИК-2012-O (Катушка индуктивности с керамическим сердечником типоразмер 2012(0805))
pins: 1, 2

## КИК-2012-560 нГн ±2% Зл
designator L?, comment 560 нГн ±5%  (value not drawn)
Катушка индуктивности с керамическим сердечником и золотым покрытием контактных площадок; Номиналиная индуктивность: 560 нГн; Допускаемое отклонение индуктивности: ±2%; Добротность, не менее: 23; Резонансная частота, не менее: 0.330 ГГц; Сопротивление обмотки постоянноми току, не более: 1.9 Ом; Допустимый ток обмотки: 230 мА; Диапазон рабочих температур: от -60 до +125 ℃; Упаковка: Катушка и лента; Типоразмер: 2012 (0805); Технология монтажа: SMT; Изготовитель: АО "НПО "ЭРКОН"
footprint КИК-2012-Зл (Катушка индуктивности с керамическим сердечникомтипоразмер 2012(0805))
pins: 1, 2

## КИК-2012-560 нГн ±5% O
designator L?, comment 560 нГн ±5%  (value not drawn)
Катушка индуктивности с керамическим сердечником и  финишным покрытием контактных площадок оловом; Номиналиная индуктивность: 560 нГн; Добротность, не менее: 23; Резонансная частота, не менее: 0.330 ГГц; Сопротивление обмотки постоянноми току, не более: 1.9 Ом; Допустимый ток обмотки: 230 мА; Диапазон рабочих температур: от -60 до +125 ℃; Упаковка: Катушка и лента; Типоразмер: 2012 (0805); Технология монтажа: SMT; Изготовитель: АО "НПО "ЭРКОН"
footprint КИК-2012-O (Катушка индуктивности с керамическим сердечником типоразмер 2012(0805))
pins: 1, 2

## КИК-2012-560 нГн ±5% Зл
designator L?, comment 560 нГн ±5%  (value not drawn)
Катушка индуктивности с керамическим сердечником и золотым покрытием контактных площадок; Номиналиная индуктивность: 560 нГн; Добротность, не менее: 23; Резонансная частота, не менее: 0.330 ГГц; Сопротивление обмотки постоянноми току, не более: 1.9 Ом; Допустимый ток обмотки: 230 мА; Диапазон рабочих температур: от -60 до +125 ℃; Упаковка: Катушка и лента; Типоразмер: 2012 (0805); Технология монтажа: SMT; Изготовитель: АО "НПО "ЭРКОН"
footprint КИК-2012-Зл (Катушка индуктивности с керамическим сердечникомтипоразмер 2012(0805))
pins: 1, 2

## КИК-2012-560 нГн ±10% O
designator L?, comment 560 нГн ±10%  (value not drawn)
Катушка индуктивности с керамическим сердечником и  финишным покрытием контактных площадок оловом; Номиналиная индуктивность: 560 нГн; Добротность, не менее: 23; Резонансная частота, не менее: 0.330 ГГц; Сопротивление обмотки постоянноми току, не более: 1.9 Ом; Допустимый ток обмотки: 230 мА; Диапазон рабочих температур: от -60 до +125 ℃; Упаковка: Катушка и лента; Типоразмер: 2012 (0805); Технология монтажа: SMT; Изготовитель: АО "НПО "ЭРКОН"
footprint КИК-2012-O (Катушка индуктивности с керамическим сердечником типоразмер 2012(0805))
pins: 1, 2

## КИК-2012-560 нГн ±10% Зл
designator L?, comment 560 нГн ±10%  (value not drawn)
Катушка индуктивности с керамическим сердечником и золотым покрытием контактных площадок; Номиналиная индуктивность: 560 нГн; Добротность, не менее: 23; Резонансная частота, не менее: 0.330 ГГц; Сопротивление обмотки постоянноми току, не более: 1.9 Ом; Допустимый ток обмотки: 230 мА; Диапазон рабочих температур: от -60 до +125 ℃; Упаковка: Катушка и лента; Типоразмер: 2012 (0805); Технология монтажа: SMT; Изготовитель: АО "НПО "ЭРКОН"
footprint КИК-2012-Зл (Катушка индуктивности с керамическим сердечникомтипоразмер 2012(0805))
pins: 1, 2

## КИК-2012-560 нГн ±20% O
designator L?, comment 560 нГн ±20%  (value not drawn)
Катушка индуктивности с керамическим сердечником и  финишным покрытием контактных площадок оловом; Номиналиная индуктивность: 560 нГн; Добротность, не менее: 23; Резонансная частота, не менее: 0.330 ГГц; Сопротивление обмотки постоянноми току, не более: 1.9 Ом; Допустимый ток обмотки: 230 мА; Диапазон рабочих температур: от -60 до +125 ℃; Упаковка: Катушка и лента; Типоразмер: 2012 (0805); Технология монтажа: SMT; Изготовитель: АО "НПО "ЭРКОН"
footprint КИК-2012-O (Катушка индуктивности с керамическим сердечником типоразмер 2012(0805))
pins: 1, 2

## КИК-2012-560 нГн ±20% Зл
designator L?, comment 560 нГн ±20%  (value not drawn)
Катушка индуктивности с керамическим сердечником и золотым покрытием контактных площадок; Номиналиная индуктивность: 560 нГн; Добротность, не менее: 23; Резонансная частота, не менее: 0.330 ГГц; Сопротивление обмотки постоянноми току, не более: 1.9 Ом; Допустимый ток обмотки: 230 мА; Диапазон рабочих температур: от -60 до +125 ℃; Упаковка: Катушка и лента; Типоразмер: 2012 (0805); Технология монтажа: SMT; Изготовитель: АО "НПО "ЭРКОН"
footprint КИК-2012-Зл (Катушка индуктивности с керамическим сердечникомтипоразмер 2012(0805))
pins: 1, 2

## КИК-2012-680 нГн ±2% O
designator L?, comment 680 нГн ±2%  (value not drawn)
Катушка индуктивности с керамическим сердечником и  финишным покрытием контактных площадок оловом; Номиналиная индуктивность: 680 нГн; Добротность, не менее: 23; Резонансная частота, не менее: 0.31 ГГц; Сопротивление обмотки постоянноми току, не более: 2.2 Ом; Допустимый ток обмотки: 190 мА; Диапазон рабочих температур: от -60 до +125 ℃; Упаковка: Катушка и лента; Типоразмер: 2012 (0805); Технология монтажа: SMT; Изготовитель: АО "НПО "ЭРКОН"
footprint КИК-2012-O (Катушка индуктивности с керамическим сердечником типоразмер 2012(0805))
pins: 1, 2

## КИК-2012-680 нГн ±2% Зл
designator L?, comment 680 нГн ±2%  (value not drawn)
Катушка индуктивности с керамическим сердечником и золотым покрытием контактных площадок; Номиналиная индуктивность: 680 нГн; Добротность, не менее: 23; Резонансная частота, не менее: 0.31 ГГц; Сопротивление обмотки постоянноми току, не более: 2.2 Ом; Допустимый ток обмотки: 190 мА; Диапазон рабочих температур: от -60 до +125 ℃; Упаковка: Катушка и лента; Типоразмер: 2012 (0805); Технология монтажа: SMT; Изготовитель: АО "НПО "ЭРКОН"
footprint КИК-2012-Зл (Катушка индуктивности с керамическим сердечникомтипоразмер 2012(0805))
pins: 1, 2

## КИК-2012-680 нГн ±5% O
designator L?, comment 680 нГн ±5%  (value not drawn)
Катушка индуктивности с керамическим сердечником и  финишным покрытием контактных площадок оловом; Номиналиная индуктивность: 680 нГн; Добротность, не менее: 23; Резонансная частота, не менее: 0.31 ГГц; Сопротивление обмотки постоянноми току, не более: 2.2 Ом; Допустимый ток обмотки: 190 мА; Диапазон рабочих температур: от -60 до +125 ℃; Упаковка: Катушка и лента; Типоразмер: 2012 (0805); Технология монтажа: SMT; Изготовитель: АО "НПО "ЭРКОН"
footprint КИК-2012-O (Катушка индуктивности с керамическим сердечником типоразмер 2012(0805))
pins: 1, 2

## КИК-2012-680 нГн ±5% Зл
designator L?, comment 680 нГн ±5%  (value not drawn)
Катушка индуктивности с керамическим сердечником и золотым покрытием контактных площадок; Номиналиная индуктивность: 680 нГн; Добротность, не менее: 23; Резонансная частота, не менее: 0.31 ГГц; Сопротивление обмотки постоянноми току, не более: 2.2 Ом; Допустимый ток обмотки: 190 мА; Диапазон рабочих температур: от -60 до +125 ℃; Упаковка: Катушка и лента; Типоразмер: 2012 (0805); Технология монтажа: SMT; Изготовитель: АО "НПО "ЭРКОН"
footprint КИК-2012-Зл (Катушка индуктивности с керамическим сердечникомтипоразмер 2012(0805))
pins: 1, 2

## КИК-2012-680 нГн ±10% O
designator L?, comment 680 нГн ±10%  (value not drawn)
Катушка индуктивности с керамическим сердечником и  финишным покрытием контактных площадок оловом; Номиналиная индуктивность: 680 нГн; Добротность, не менее: 23; Резонансная частота, не менее: 0.31 ГГц; Сопротивление обмотки постоянноми току, не более: 2.2 Ом; Допустимый ток обмотки: 190 мА; Диапазон рабочих температур: от -60 до +125 ℃; Упаковка: Катушка и лента; Типоразмер: 2012 (0805); Технология монтажа: SMT; Изготовитель: АО "НПО "ЭРКОН"
footprint КИК-2012-O (Катушка индуктивности с керамическим сердечником типоразмер 2012(0805))
pins: 1, 2

## КИК-2012-680 нГн ±10% Зл
designator L?, comment 680 нГн ±10%  (value not drawn)
Катушка индуктивности с керамическим сердечником и золотым покрытием контактных площадок; Номиналиная индуктивность: 680 нГн; Добротность, не менее: 23; Резонансная частота, не менее: 0.31 ГГц; Сопротивление обмотки постоянноми току, не более: 2.2 Ом; Допустимый ток обмотки: 190 мА; Диапазон рабочих температур: от -60 до +125 ℃; Упаковка: Катушка и лента; Типоразмер: 2012 (0805); Технология монтажа: SMT; Изготовитель: АО "НПО "ЭРКОН"
footprint КИК-2012-Зл (Катушка индуктивности с керамическим сердечникомтипоразмер 2012(0805))
pins: 1, 2

## КИК-2012-680 нГн ±20% O
designator L?, comment 680 нГн ±20%  (value not drawn)
Катушка индуктивности с керамическим сердечником и  финишным покрытием контактных площадок оловом; Номиналиная индуктивность: 680 нГн; Добротность, не менее: 23; Резонансная частота, не менее: 0.31 ГГц; Сопротивление обмотки постоянноми току, не более: 2.2 Ом; Допустимый ток обмотки: 190 мА; Диапазон рабочих температур: от -60 до +125 ℃; Упаковка: Катушка и лента; Типоразмер: 2012 (0805); Технология монтажа: SMT; Изготовитель: АО "НПО "ЭРКОН"
footprint КИК-2012-O (Катушка индуктивности с керамическим сердечником типоразмер 2012(0805))
pins: 1, 2

## КИК-2012-680 нГн ±20% Зл
designator L?, comment 680 нГн ±20%  (value not drawn)
Катушка индуктивности с керамическим сердечником и золотым покрытием контактных площадок; Номиналиная индуктивность: 680 нГн; Добротность, не менее: 23; Резонансная частота, не менее: 0.31 ГГц; Сопротивление обмотки постоянноми току, не более: 2.2 Ом; Допустимый ток обмотки: 190 мА; Диапазон рабочих температур: от -60 до +125 ℃; Упаковка: Катушка и лента; Типоразмер: 2012 (0805); Технология монтажа: SMT; Изготовитель: АО "НПО "ЭРКОН"
footprint КИК-2012-Зл (Катушка индуктивности с керамическим сердечникомтипоразмер 2012(0805))
pins: 1, 2

## КИК-2012-820 нГн ±2% O
designator L?, comment 820 нГн ±2%  (value not drawn)
Катушка индуктивности с керамическим сердечником и  финишным покрытием контактных площадок оловом; Номиналиная индуктивность: 820 нГн; Добротность, не менее: 23; Резонансная частота, не менее: 0.31 ГГц; Сопротивление обмотки постоянноми току, не более: 2.35Ом; Допустимый ток обмотки: 180 мА; Диапазон рабочих температур: от -60 до +125 ℃; Упаковка: Катушка и лента; Типоразмер: 2012 (0805); Технология монтажа: SMT; Изготовитель: АО "НПО "ЭРКОН"
footprint КИК-2012-O (Катушка индуктивности с керамическим сердечником типоразмер 2012(0805))
pins: 1, 2

## КИК-2012-820 нГн ±2% Зл
designator L?, comment 820 нГн ±2%  (value not drawn)
Катушка индуктивности с керамическим сердечником и золотым покрытием контактных площадок; Номиналиная индуктивность: 820 нГн; Добротность, не менее: 23; Резонансная частота, не менее: 0.31 ГГц; Сопротивление обмотки постоянноми току, не более: 2.35Ом; Допустимый ток обмотки: 180 мА; Диапазон рабочих температур: от -60 до +125 ℃; Упаковка: Катушка и лента; Типоразмер: 2012 (0805); Технология монтажа: SMT; Изготовитель: АО "НПО "ЭРКОН"
footprint КИК-2012-Зл (Катушка индуктивности с керамическим сердечникомтипоразмер 2012(0805))
pins: 1, 2

## КИК-2012-820 нГн ±5% O
designator L?, comment 820 нГн ±5%  (value not drawn)
Катушка индуктивности с керамическим сердечником и  финишным покрытием контактных площадок оловом; Номиналиная индуктивность: 820 нГн; Добротность, не менее: 23; Резонансная частота, не менее: 0.31 ГГц; Сопротивление обмотки постоянноми току, не более: 2.35Ом; Допустимый ток обмотки: 180 мА; Диапазон рабочих температур: от -60 до +125 ℃; Упаковка: Катушка и лента; Типоразмер: 2012 (0805); Технология монтажа: SMT; Изготовитель: АО "НПО "ЭРКОН"
footprint КИК-2012-O (Катушка индуктивности с керамическим сердечником типоразмер 2012(0805))
pins: 1, 2


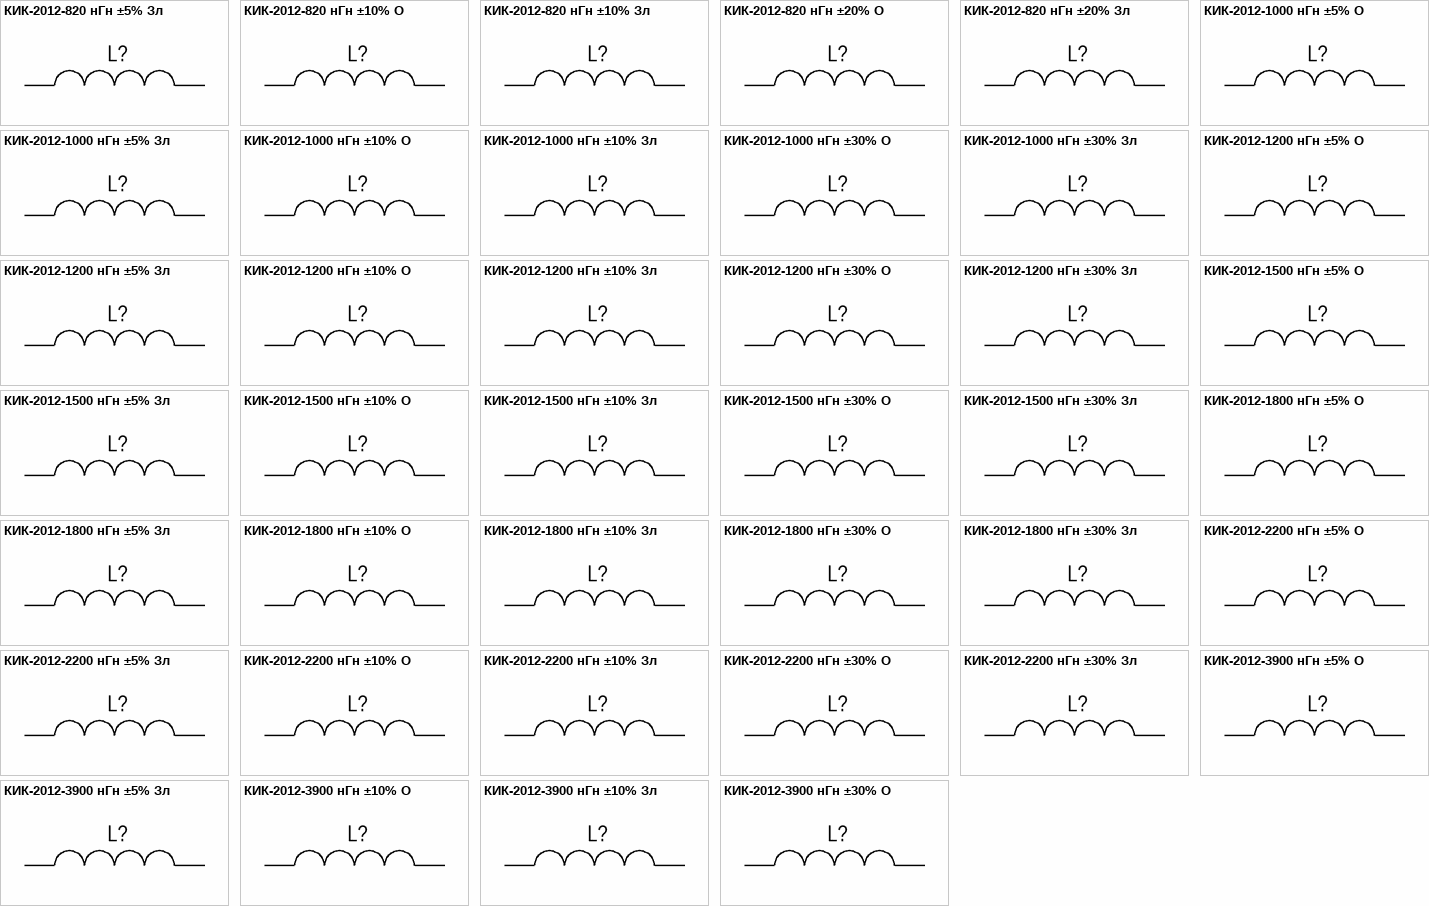
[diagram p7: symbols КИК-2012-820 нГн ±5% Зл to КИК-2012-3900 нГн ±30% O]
## КИК-2012-820 нГн ±5% Зл
designator L?, comment 820 нГн ±5%  (value not drawn)
Катушка индуктивности с керамическим сердечником и золотым покрытием контактных площадок; Номиналиная индуктивность: 820 нГн; Добротность, не менее: 23; Резонансная частота, не менее: 0.31 ГГц; Сопротивление обмотки постоянноми току, не более: 2.35Ом; Допустимый ток обмотки: 180 мА; Диапазон рабочих температур: от -60 до +125 ℃; Упаковка: Катушка и лента; Типоразмер: 2012 (0805); Технология монтажа: SMT; Изготовитель: АО "НПО "ЭРКОН"
footprint КИК-2012-Зл (Катушка индуктивности с керамическим сердечникомтипоразмер 2012(0805))
pins: 1, 2

## КИК-2012-820 нГн ±10% O
designator L?, comment 820 нГн ±10%  (value not drawn)
Катушка индуктивности с керамическим сердечником и  финишным покрытием контактных площадок оловом; Номиналиная индуктивность: 820 нГн; Добротность, не менее: 23; Резонансная частота, не менее: 0.31 ГГц; Сопротивление обмотки постоянноми току, не более: 2.35Ом; Допустимый ток обмотки: 180 мА; Диапазон рабочих температур: от -60 до +125 ℃; Упаковка: Катушка и лента; Типоразмер: 2012 (0805); Технология монтажа: SMT; Изготовитель: АО "НПО "ЭРКОН"
footprint КИК-2012-O (Катушка индуктивности с керамическим сердечником типоразмер 2012(0805))
pins: 1, 2

## КИК-2012-820 нГн ±10% Зл
designator L?, comment 820 нГн ±10%  (value not drawn)
Катушка индуктивности с керамическим сердечником и золотым покрытием контактных площадок; Номиналиная индуктивность: 820 нГн; Добротность, не менее: 23; Резонансная частота, не менее: 0.31 ГГц; Сопротивление обмотки постоянноми току, не более: 2.35Ом; Допустимый ток обмотки: 180 мА; Диапазон рабочих температур: от -60 до +125 ℃; Упаковка: Катушка и лента; Типоразмер: 2012 (0805); Технология монтажа: SMT; Изготовитель: АО "НПО "ЭРКОН"
footprint КИК-2012-Зл (Катушка индуктивности с керамическим сердечникомтипоразмер 2012(0805))
pins: 1, 2

## КИК-2012-820 нГн ±20% O
designator L?, comment 820 нГн ±20%  (value not drawn)
Катушка индуктивности с керамическим сердечником и  финишным покрытием контактных площадок оловом; Номиналиная индуктивность: 820 нГн; Добротность, не менее: 23; Резонансная частота, не менее: 0.31 ГГц; Сопротивление обмотки постоянноми току, не более: 2.35Ом; Допустимый ток обмотки: 180 мА; Диапазон рабочих температур: от -60 до +125 ℃; Упаковка: Катушка и лента; Типоразмер: 2012 (0805); Технология монтажа: SMT; Изготовитель: АО "НПО "ЭРКОН"
footprint КИК-2012-O (Катушка индуктивности с керамическим сердечником типоразмер 2012(0805))
pins: 1, 2

## КИК-2012-820 нГн ±20% Зл
designator L?, comment 820 нГн ±20%  (value not drawn)
Катушка индуктивности с керамическим сердечником и золотым покрытием контактных площадок; Номиналиная индуктивность: 820 нГн; Добротность, не менее: 23; Резонансная частота, не менее: 0.31 ГГц; Сопротивление обмотки постоянноми току, не более: 2.35Ом; Допустимый ток обмотки: 180 мА; Диапазон рабочих температур: от -60 до +125 ℃; Упаковка: Катушка и лента; Типоразмер: 2012 (0805); Технология монтажа: SMT; Изготовитель: АО "НПО "ЭРКОН"
footprint КИК-2012-Зл (Катушка индуктивности с керамическим сердечникомтипоразмер 2012(0805))
pins: 1, 2

## КИК-2012-1000 нГн ±5% O
designator L?, comment 1000 нГн ±5%  (value not drawn)
Катушка индуктивности с керамическим сердечником и  финишным покрытием контактных площадок оловом; Добротность, не менее: 25; Резонансная частота, не менее: 0.330 ГГц; Сопротивление обмотки постоянноми току, не более: 2.5 Ом; Допустимый ток обмотки: 150 мА; Диапазон рабочих температур: от -60 до +125 ℃; Упаковка: Катушка и лента; Типоразмер: 2012 (0805); Технология монтажа: SMT; Изготовитель: АО "НПО "ЭРКОН"
footprint КИК-2012-O (Катушка индуктивности с керамическим сердечником типоразмер 2012(0805))
pins: 1, 2

## КИК-2012-1000 нГн ±5% Зл
designator L?, comment 1000 нГн ±5%  (value not drawn)
Катушка индуктивности с керамическим сердечником и золотым покрытием контактных площадок; Добротность, не менее: 25; Резонансная частота, не менее: 0.330 ГГц; Сопротивление обмотки постоянноми току, не более: 2.5 Ом; Допустимый ток обмотки: 150 мА; Диапазон рабочих температур: от -60 до +125 ℃; Упаковка: Катушка и лента; Типоразмер: 2012 (0805); Технология монтажа: SMT; Изготовитель: АО "НПО "ЭРКОН"
footprint КИК-2012-Зл (Катушка индуктивности с керамическим сердечникомтипоразмер 2012(0805))
pins: 1, 2

## КИК-2012-1000 нГн ±10% O
designator L?, comment 1000 нГн ±10%  (value not drawn)
Катушка индуктивности с керамическим сердечником и  финишным покрытием контактных площадок оловом; Добротность, не менее: 25; Резонансная частота, не менее: 0.330 ГГц; Сопротивление обмотки постоянноми току, не более: 2.5 Ом; Допустимый ток обмотки: 150 мА; Диапазон рабочих температур: от -60 до +125 ℃; Упаковка: Катушка и лента; Типоразмер: 2012 (0805); Технология монтажа: SMT; Изготовитель: АО "НПО "ЭРКОН"
footprint КИК-2012-O (Катушка индуктивности с керамическим сердечником типоразмер 2012(0805))
pins: 1, 2

## КИК-2012-1000 нГн ±10% Зл
designator L?, comment 1000 нГн ±10%  (value not drawn)
Катушка индуктивности с керамическим сердечником и золотым покрытием контактных площадок; Добротность, не менее: 25; Резонансная частота, не менее: 0.330 ГГц; Сопротивление обмотки постоянноми току, не более: 2.5 Ом; Допустимый ток обмотки: 150 мА; Диапазон рабочих температур: от -60 до +125 ℃; Упаковка: Катушка и лента; Типоразмер: 2012 (0805); Технология монтажа: SMT; Изготовитель: АО "НПО "ЭРКОН"
footprint КИК-2012-Зл (Катушка индуктивности с керамическим сердечникомтипоразмер 2012(0805))
pins: 1, 2

## КИК-2012-1000 нГн ±30% O
designator L?, comment 1000 нГн ±30%  (value not drawn)
Катушка индуктивности с керамическим сердечником и  финишным покрытием контактных площадок оловом; Добротность, не менее: 25; Резонансная частота, не менее: 0.330 ГГц; Сопротивление обмотки постоянноми току, не более: 2.5 Ом; Допустимый ток обмотки: 150 мА; Диапазон рабочих температур: от -60 до +125 ℃; Упаковка: Катушка и лента; Типоразмер: 2012 (0805); Технология монтажа: SMT; Изготовитель: АО "НПО "ЭРКОН"
footprint КИК-2012-O (Катушка индуктивности с керамическим сердечником типоразмер 2012(0805))
pins: 1, 2

## КИК-2012-1000 нГн ±30% Зл
designator L?, comment 1000 нГн ±30%  (value not drawn)
Катушка индуктивности с керамическим сердечником и золотым покрытием контактных площадок; Добротность, не менее: 25; Резонансная частота, не менее: 0.330 ГГц; Сопротивление обмотки постоянноми току, не более: 2.5 Ом; Допустимый ток обмотки: 150 мА; Диапазон рабочих температур: от -60 до +125 ℃; Упаковка: Катушка и лента; Типоразмер: 2012 (0805); Технология монтажа: SMT; Изготовитель: АО "НПО "ЭРКОН"
footprint КИК-2012-Зл (Катушка индуктивности с керамическим сердечникомтипоразмер 2012(0805))
pins: 1, 2

## КИК-2012-1200 нГн ±5% O
designator L?, comment 1200 нГн ±5%  (value not drawn)
Катушка индуктивности с керамическим сердечником и  финишным покрытием контактных площадок оловом; Добротность, не менее: 17; Резонансная частота, не менее: 0.200 ГГц; Сопротивление обмотки постоянноми току, не более: 2.38 Ом; Допустимый ток обмотки: 150 мА; Диапазон рабочих температур: от -60 до +125 ℃; Упаковка: Катушка и лента; Типоразмер: 2012 (0805); Технология монтажа: SMT; Изготовитель: АО "НПО "ЭРКОН"
footprint КИК-2012-O (Катушка индуктивности с керамическим сердечником типоразмер 2012(0805))
pins: 1, 2

## КИК-2012-1200 нГн ±5% Зл
designator L?, comment 1200 нГн ±5%  (value not drawn)
Катушка индуктивности с керамическим сердечником и золотым покрытием контактных площадок; Добротность, не менее: 17; Резонансная частота, не менее: 0.200 ГГц; Сопротивление обмотки постоянноми току, не более: 2.38 Ом; Допустимый ток обмотки: 150 мА; Диапазон рабочих температур: от -60 до +125 ℃; Упаковка: Катушка и лента; Типоразмер: 2012 (0805); Технология монтажа: SMT; Изготовитель: АО "НПО "ЭРКОН"
footprint КИК-2012-Зл (Катушка индуктивности с керамическим сердечникомтипоразмер 2012(0805))
pins: 1, 2

## КИК-2012-1200 нГн ±10% O
designator L?, comment 1200 нГн ±5%  (value not drawn)
Катушка индуктивности с керамическим сердечником и  финишным покрытием контактных площадок оловом; Допускаемое отклонение индуктивности: ±10%; Добротность, не менее: 17; Резонансная частота, не менее: 0.200 ГГц; Сопротивление обмотки постоянноми току, не более: 2.38 Ом; Допустимый ток обмотки: 150 мА; Диапазон рабочих температур: от -60 до +125 ℃; Упаковка: Катушка и лента; Типоразмер: 2012 (0805); Технология монтажа: SMT; Изготовитель: АО "НПО "ЭРКОН"
footprint КИК-2012-O (Катушка индуктивности с керамическим сердечником типоразмер 2012(0805))
pins: 1, 2

## КИК-2012-1200 нГн ±10% Зл
designator L?, comment 1200 нГн ±10%  (value not drawn)
Катушка индуктивности с керамическим сердечником и золотым покрытием контактных площадок; Добротность, не менее: 17; Резонансная частота, не менее: 0.200 ГГц; Сопротивление обмотки постоянноми току, не более: 2.38 Ом; Допустимый ток обмотки: 150 мА; Диапазон рабочих температур: от -60 до +125 ℃; Упаковка: Катушка и лента; Типоразмер: 2012 (0805); Технология монтажа: SMT; Изготовитель: АО "НПО "ЭРКОН"
footprint КИК-2012-Зл (Катушка индуктивности с керамическим сердечникомтипоразмер 2012(0805))
pins: 1, 2

## КИК-2012-1200 нГн ±30% O
designator L?, comment 1200 нГн ±30%  (value not drawn)
Катушка индуктивности с керамическим сердечником и  финишным покрытием контактных площадок оловом; Добротность, не менее: 17; Резонансная частота, не менее: 0.200 ГГц; Сопротивление обмотки постоянноми току, не более: 2.38 Ом; Допустимый ток обмотки: 150 мА; Диапазон рабочих температур: от -60 до +125 ℃; Упаковка: Катушка и лента; Типоразмер: 2012 (0805); Технология монтажа: SMT; Изготовитель: АО "НПО "ЭРКОН"
footprint КИК-2012-O (Катушка индуктивности с керамическим сердечником типоразмер 2012(0805))
pins: 1, 2

## КИК-2012-1200 нГн ±30% Зл
designator L?, comment 1200 нГн ±30%  (value not drawn)
Катушка индуктивности с керамическим сердечником и золотым покрытием контактных площадок; Добротность, не менее: 17; Резонансная частота, не менее: 0.200 ГГц; Сопротивление обмотки постоянноми току, не более: 2.38 Ом; Допустимый ток обмотки: 150 мА; Диапазон рабочих температур: от -60 до +125 ℃; Упаковка: Катушка и лента; Типоразмер: 2012 (0805); Технология монтажа: SMT; Изготовитель: АО "НПО "ЭРКОН"
footprint КИК-2012-Зл (Катушка индуктивности с керамическим сердечникомтипоразмер 2012(0805))
pins: 1, 2

## КИК-2012-1500 нГн ±5% O
designator L?, comment 1500 нГн ±5%  (value not drawn)
Катушка индуктивности с керамическим сердечником и  финишным покрытием контактных площадок оловом; Добротность, не менее: 17; Резонансная частота, не менее: 0.180 ГГц; Сопротивление обмотки постоянноми току, не более: 2.9 Ом; Допустимый ток обмотки: 130 мА; Диапазон рабочих температур: от -60 до +125 ℃; Упаковка: Катушка и лента; Типоразмер: 2012 (0805); Технология монтажа: SMT; Изготовитель: АО "НПО "ЭРКОН"
footprint КИК-2012-O (Катушка индуктивности с керамическим сердечником типоразмер 2012(0805))
pins: 1, 2

## КИК-2012-1500 нГн ±5% Зл
designator L?, comment 1500 нГн ±5%  (value not drawn)
Катушка индуктивности с керамическим сердечником и золотым покрытием контактных площадок; Добротность, не менее: 17; Резонансная частота, не менее: 0.180 ГГц; Сопротивление обмотки постоянноми току, не более: 2.9 Ом; Допустимый ток обмотки: 130 мА; Диапазон рабочих температур: от -60 до +125 ℃; Упаковка: Катушка и лента; Типоразмер: 2012 (0805); Технология монтажа: SMT; Изготовитель: АО "НПО "ЭРКОН"
footprint КИК-2012-Зл (Катушка индуктивности с керамическим сердечникомтипоразмер 2012(0805))
pins: 1, 2

## КИК-2012-1500 нГн ±10% O
designator L?, comment 1500 нГн ±10%  (value not drawn)
Катушка индуктивности с керамическим сердечником и  финишным покрытием контактных площадок оловом; Добротность, не менее: 17; Резонансная частота, не менее: 0.180 ГГц; Сопротивление обмотки постоянноми току, не более: 2.9 Ом; Допустимый ток обмотки: 130 мА; Диапазон рабочих температур: от -60 до +125 ℃; Упаковка: Катушка и лента; Типоразмер: 2012 (0805); Технология монтажа: SMT; Изготовитель: АО "НПО "ЭРКОН"
footprint КИК-2012-O (Катушка индуктивности с керамическим сердечником типоразмер 2012(0805))
pins: 1, 2

## КИК-2012-1500 нГн ±10% Зл
designator L?, comment 1500 нГн ±10%  (value not drawn)
Катушка индуктивности с керамическим сердечником и золотым покрытием контактных площадок; Добротность, не менее: 17; Резонансная частота, не менее: 0.180 ГГц; Сопротивление обмотки постоянноми току, не более: 2.9 Ом; Допустимый ток обмотки: 130 мА; Диапазон рабочих температур: от -60 до +125 ℃; Упаковка: Катушка и лента; Типоразмер: 2012 (0805); Технология монтажа: SMT; Изготовитель: АО "НПО "ЭРКОН"
footprint КИК-2012-Зл (Катушка индуктивности с керамическим сердечникомтипоразмер 2012(0805))
pins: 1, 2

## КИК-2012-1500 нГн ±30% O
designator L?, comment 1500 нГн ±30%  (value not drawn)
Катушка индуктивности с керамическим сердечником и  финишным покрытием контактных площадок оловом; Добротность, не менее: 17; Резонансная частота, не менее: 0.180 ГГц; Сопротивление обмотки постоянноми току, не более: 2.9 Ом; Допустимый ток обмотки: 130 мА; Диапазон рабочих температур: от -60 до +125 ℃; Упаковка: Катушка и лента; Типоразмер: 2012 (0805); Технология монтажа: SMT; Изготовитель: АО "НПО "ЭРКОН"
footprint КИК-2012-O (Катушка индуктивности с керамическим сердечником типоразмер 2012(0805))
pins: 1, 2

## КИК-2012-1500 нГн ±30% Зл
designator L?, comment 1500 нГн ±30%  (value not drawn)
Катушка индуктивности с керамическим сердечником и золотым покрытием контактных площадок; Добротность, не менее: 17; Резонансная частота, не менее: 0.180 ГГц; Сопротивление обмотки постоянноми току, не более: 2.9 Ом; Допустимый ток обмотки: 130 мА; Диапазон рабочих температур: от -60 до +125 ℃; Упаковка: Катушка и лента; Типоразмер: 2012 (0805); Технология монтажа: SMT; Изготовитель: АО "НПО "ЭРКОН"
footprint КИК-2012-Зл (Катушка индуктивности с керамическим сердечникомтипоразмер 2012(0805))
pins: 1, 2

## КИК-2012-1800 нГн ±5% O
designator L?, comment 1800 нГн ±5%  (value not drawn)
Катушка индуктивности с керамическим сердечником и  финишным покрытием контактных площадок оловом; Добротность, не менее: 17; Резонансная частота, не менее: 0.120 ГГц; Сопротивление обмотки постоянноми току, не более: 3 Ом; Допустимый ток обмотки: 120 мА; Диапазон рабочих температур: от -60 до +125 ℃; Упаковка: Катушка и лента; Типоразмер: 2012 (0805); Технология монтажа: SMT; Изготовитель: АО "НПО "ЭРКОН"
footprint КИК-2012-O (Катушка индуктивности с керамическим сердечником типоразмер 2012(0805))
pins: 1, 2

## КИК-2012-1800 нГн ±5% Зл
designator L?, comment 1800 нГн ±5%  (value not drawn)
Катушка индуктивности с керамическим сердечником и золотым покрытием контактных площадок; Добротность, не менее: 17; Резонансная частота, не менее: 0.120 ГГц; Сопротивление обмотки постоянноми току, не более: 3 Ом; Допустимый ток обмотки: 120 мА; Диапазон рабочих температур: от -60 до +125 ℃; Упаковка: Катушка и лента; Типоразмер: 2012 (0805); Технология монтажа: SMT; Изготовитель: АО "НПО "ЭРКОН"
footprint КИК-2012-Зл (Катушка индуктивности с керамическим сердечникомтипоразмер 2012(0805))
pins: 1, 2

## КИК-2012-1800 нГн ±10% O
designator L?, comment 1800 нГн ±10%  (value not drawn)
Катушка индуктивности с керамическим сердечником и  финишным покрытием контактных площадок оловом; Добротность, не менее: 17; Резонансная частота, не менее: 0.120 ГГц; Сопротивление обмотки постоянноми току, не более: 3 Ом; Допустимый ток обмотки: 120 мА; Диапазон рабочих температур: от -60 до +125 ℃; Упаковка: Катушка и лента; Типоразмер: 2012 (0805); Технология монтажа: SMT; Изготовитель: АО "НПО "ЭРКОН"
footprint КИК-2012-O (Катушка индуктивности с керамическим сердечником типоразмер 2012(0805))
pins: 1, 2

## КИК-2012-1800 нГн ±10% Зл
designator L?, comment 1800 нГн ±10%  (value not drawn)
Катушка индуктивности с керамическим сердечником и золотым покрытием контактных площадок; Добротность, не менее: 17; Резонансная частота, не менее: 0.120 ГГц; Сопротивление обмотки постоянноми току, не более: 3 Ом; Допустимый ток обмотки: 120 мА; Диапазон рабочих температур: от -60 до +125 ℃; Упаковка: Катушка и лента; Типоразмер: 2012 (0805); Технология монтажа: SMT; Изготовитель: АО "НПО "ЭРКОН"
footprint КИК-2012-Зл (Катушка индуктивности с керамическим сердечникомтипоразмер 2012(0805))
pins: 1, 2

## КИК-2012-1800 нГн ±30% O
designator L?, comment 1800 нГн ±30%  (value not drawn)
Катушка индуктивности с керамическим сердечником и  финишным покрытием контактных площадок оловом; Добротность, не менее: 17; Резонансная частота, не менее: 0.120 ГГц; Сопротивление обмотки постоянноми току, не более: 3 Ом; Допустимый ток обмотки: 120 мА; Диапазон рабочих температур: от -60 до +125 ℃; Упаковка: Катушка и лента; Типоразмер: 2012 (0805); Технология монтажа: SMT; Изготовитель: АО "НПО "ЭРКОН"
footprint КИК-2012-O (Катушка индуктивности с керамическим сердечником типоразмер 2012(0805))
pins: 1, 2

## КИК-2012-1800 нГн ±30% Зл
designator L?, comment 1800 нГн ±30%  (value not drawn)
Катушка индуктивности с керамическим сердечником и золотым покрытием контактных площадок; Добротность, не менее: 17; Резонансная частота, не менее: 0.120 ГГц; Сопротивление обмотки постоянноми току, не более: 3 Ом; Допустимый ток обмотки: 120 мА; Диапазон рабочих температур: от -60 до +125 ℃; Упаковка: Катушка и лента; Типоразмер: 2012 (0805); Технология монтажа: SMT; Изготовитель: АО "НПО "ЭРКОН"
footprint КИК-2012-Зл (Катушка индуктивности с керамическим сердечникомтипоразмер 2012(0805))
pins: 1, 2

## КИК-2012-2200 нГн ±5% O
designator L?, comment 2200 нГн ±5%  (value not drawn)
Катушка индуктивности с керамическим сердечником и  финишным покрытием контактных площадок оловом; Добротность, не менее: 17; Резонансная частота, не менее: 0.110 ГГц; Сопротивление обмотки постоянноми току, не более: 3.1 Ом; Допустимый ток обмотки: 110 мА; Диапазон рабочих температур: от -60 до +125 ℃; Упаковка: Катушка и лента; Типоразмер: 2012 (0805); Технология монтажа: SMT; Изготовитель: АО "НПО "ЭРКОН"
footprint КИК-2012-O (Катушка индуктивности с керамическим сердечником типоразмер 2012(0805))
pins: 1, 2

## КИК-2012-2200 нГн ±5% Зл
designator L?, comment 2200 нГн ±5%  (value not drawn)
Катушка индуктивности с керамическим сердечником и золотым покрытием контактных площадок; Добротность, не менее: 17; Резонансная частота, не менее: 0.110 ГГц; Сопротивление обмотки постоянноми току, не более: 3.1 Ом; Допустимый ток обмотки: 110 мА; Диапазон рабочих температур: от -60 до +125 ℃; Упаковка: Катушка и лента; Типоразмер: 2012 (0805); Технология монтажа: SMT; Изготовитель: АО "НПО "ЭРКОН"
footprint КИК-2012-Зл (Катушка индуктивности с керамическим сердечникомтипоразмер 2012(0805))
pins: 1, 2

## КИК-2012-2200 нГн ±10% O
designator L?, comment 2200 нГн ±10%  (value not drawn)
Катушка индуктивности с керамическим сердечником и  финишным покрытием контактных площадок оловом; Добротность, не менее: 17; Резонансная частота, не менее: 0.110 ГГц; Сопротивление обмотки постоянноми току, не более: 3.1 Ом; Допустимый ток обмотки: 110 мА; Диапазон рабочих температур: от -60 до +125 ℃; Упаковка: Катушка и лента; Типоразмер: 2012 (0805); Технология монтажа: SMT; Изготовитель: АО "НПО "ЭРКОН"
footprint КИК-2012-O (Катушка индуктивности с керамическим сердечником типоразмер 2012(0805))
pins: 1, 2

## КИК-2012-2200 нГн ±10% Зл
designator L?, comment 2200 нГн ±10%  (value not drawn)
Катушка индуктивности с керамическим сердечником и золотым покрытием контактных площадок; Добротность, не менее: 17; Резонансная частота, не менее: 0.11 ГГц; Сопротивление обмотки постоянноми току, не более: 3.1 Ом; Допустимый ток обмотки: 110 мА; Диапазон рабочих температур: от -60 до +125 ℃; Упаковка: Катушка и лента; Типоразмер: 2012 (0805); Технология монтажа: SMT; Изготовитель: АО "НПО "ЭРКОН"
footprint КИК-2012-Зл (Катушка индуктивности с керамическим сердечникомтипоразмер 2012(0805))
pins: 1, 2

## КИК-2012-2200 нГн ±30% O
designator L?, comment 2200 нГн ±30%  (value not drawn)
Катушка индуктивности с керамическим сердечником и  финишным покрытием контактных площадок оловом; Добротность, не менее: 17; Резонансная частота, не менее: 0.110 ГГц; Сопротивление обмотки постоянноми току, не более: 3.1 Ом; Допустимый ток обмотки: 110 мА; Диапазон рабочих температур: от -60 до +125 ℃; Упаковка: Катушка и лента; Типоразмер: 2012 (0805); Технология монтажа: SMT; Изготовитель: АО "НПО "ЭРКОН"
footprint КИК-2012-O (Катушка индуктивности с керамическим сердечником типоразмер 2012(0805))
pins: 1, 2

## КИК-2012-2200 нГн ±30% Зл
designator L?, comment 2200 нГн ±30%  (value not drawn)
Катушка индуктивности с керамическим сердечником и золотым покрытием контактных площадок; Добротность, не менее: 17; Резонансная частота, не менее: 0.11 ГГц; Сопротивление обмотки постоянноми току, не более: 3.1 Ом; Допустимый ток обмотки: 110 мА; Диапазон рабочих температур: от -60 до +125 ℃; Упаковка: Катушка и лента; Типоразмер: 2012 (0805); Технология монтажа: SMT; Изготовитель: АО "НПО "ЭРКОН"
footprint КИК-2012-Зл (Катушка индуктивности с керамическим сердечникомтипоразмер 2012(0805))
pins: 1, 2

## КИК-2012-3900 нГн ±5% O
designator L?, comment 3900 нГн ±5%  (value not drawn)
Катушка индуктивности с керамическим сердечником и  финишным покрытием контактных площадок оловом; Добротность, не менее: 17; Резонансная частота, не менее: 0.070 ГГц; Сопротивление обмотки постоянноми току, не более: 4.5 Ом; Допустимый ток обмотки: 75 мА; Диапазон рабочих температур: от -60 до +125 ℃; Упаковка: Катушка и лента; Типоразмер: 2012 (0805); Технология монтажа: SMT; Изготовитель: АО "НПО "ЭРКОН"
footprint КИК-2012-O (Катушка индуктивности с керамическим сердечником типоразмер 2012(0805))
pins: 1, 2

## КИК-2012-3900 нГн ±5% Зл
designator L?, comment 3900 нГн ±5%  (value not drawn)
Катушка индуктивности с керамическим сердечником и золотым покрытием контактных площадок; Добротность, не менее: 17; Резонансная частота, не менее: 0.070 ГГц; Сопротивление обмотки постоянноми току, не более: 4.5 Ом; Допустимый ток обмотки: 75 мА; Диапазон рабочих температур: от -60 до +125 ℃; Упаковка: Катушка и лента; Типоразмер: 2012 (0805); Технология монтажа: SMT; Изготовитель: АО "НПО "ЭРКОН"
footprint КИК-2012-Зл (Катушка индуктивности с керамическим сердечникомтипоразмер 2012(0805))
pins: 1, 2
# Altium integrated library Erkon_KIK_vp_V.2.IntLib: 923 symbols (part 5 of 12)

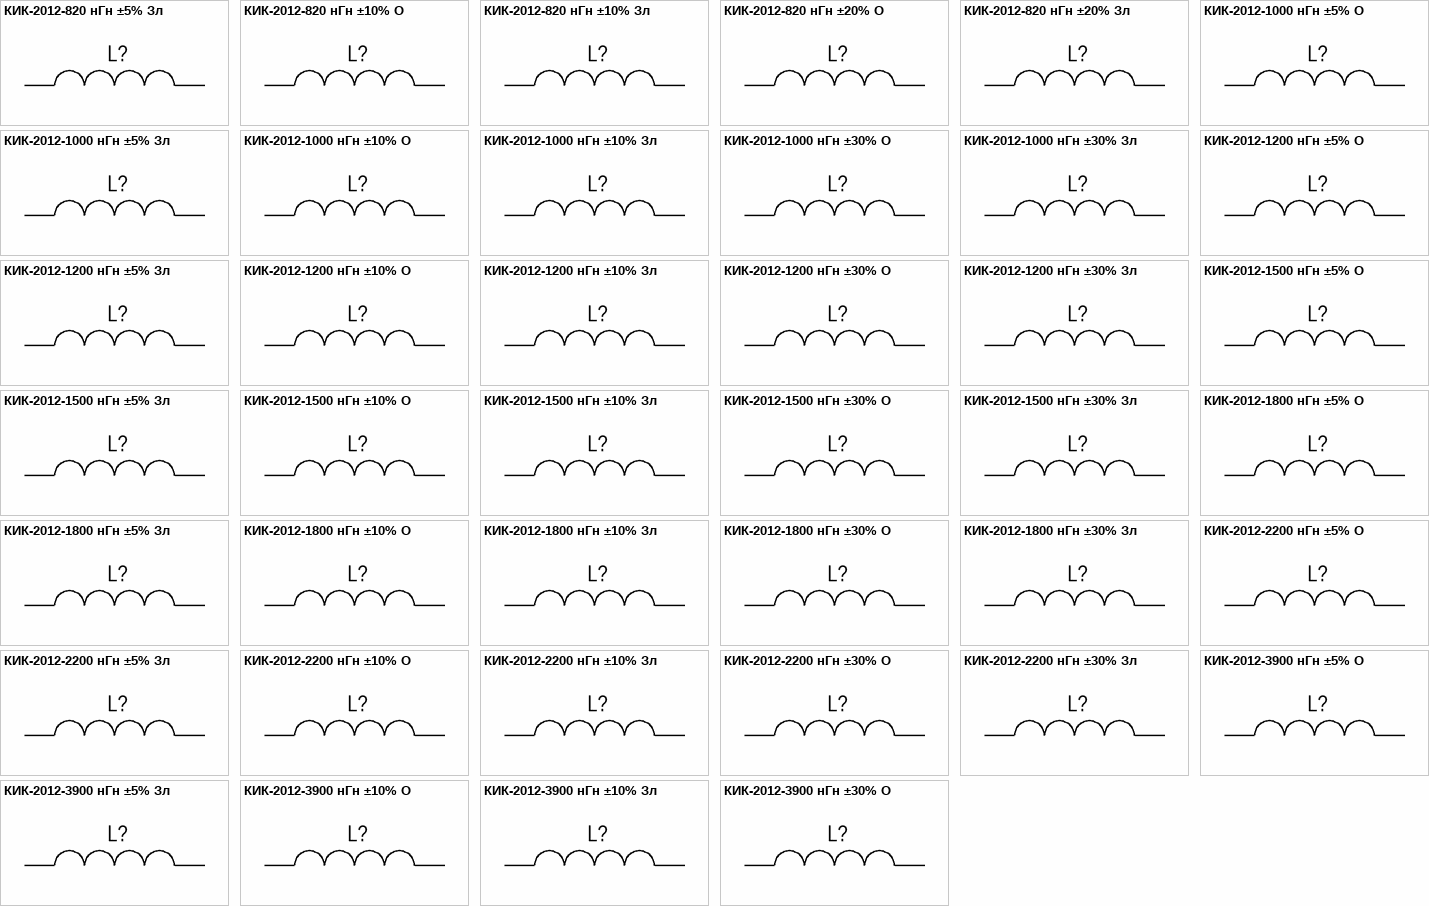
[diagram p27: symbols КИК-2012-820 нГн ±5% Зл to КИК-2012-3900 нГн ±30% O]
## КИК-2012-3900 нГн ±10% O
designator L?, comment 3900 нГн ±10%  (value not drawn)
Катушка индуктивности с керамическим сердечником и  финишным покрытием контактных площадок оловом; Добротность, не менее: 17; Резонансная частота, не менее: 0.070 ГГц; Сопротивление обмотки постоянноми току, не более: 4.5 Ом; Допустимый ток обмотки: 75 мА; Диапазон рабочих температур: от -60 до +125 ℃; Упаковка: Катушка и лента; Типоразмер: 2012 (0805); Технология монтажа: SMT; Изготовитель: АО "НПО "ЭРКОН"
footprint КИК-2012-O (Катушка индуктивности с керамическим сердечником типоразмер 2012(0805))
pins: 1, 2

## КИК-2012-3900 нГн ±10% Зл
designator L?, comment 3900 нГн ±10%  (value not drawn)
Катушка индуктивности с керамическим сердечником и золотым покрытием контактных площадок; Добротность, не менее: 17; Резонансная частота, не менее: 0.070 ГГц; Сопротивление обмотки постоянноми току, не более: 4.5 Ом; Допустимый ток обмотки: 75 мА; Диапазон рабочих температур: от -60 до +125 ℃; Упаковка: Катушка и лента; Типоразмер: 2012 (0805); Технология монтажа: SMT; Изготовитель: АО "НПО "ЭРКОН"
footprint КИК-2012-Зл (Катушка индуктивности с керамическим сердечникомтипоразмер 2012(0805))
pins: 1, 2

## КИК-2012-3900 нГн ±30% O
designator L?, comment 3900 нГн ±30%  (value not drawn)
Катушка индуктивности с керамическим сердечником и  финишным покрытием контактных площадок оловом; Добротность, не менее: 17; Резонансная частота, не менее: 0.070 ГГц; Сопротивление обмотки постоянноми току, не более: 4.5 Ом; Допустимый ток обмотки: 75 мА; Диапазон рабочих температур: от -60 до +125 ℃; Упаковка: Катушка и лента; Типоразмер: 2012 (0805); Технология монтажа: SMT; Изготовитель: АО "НПО "ЭРКОН"
footprint КИК-2012-O (Катушка индуктивности с керамическим сердечником типоразмер 2012(0805))
pins: 1, 2


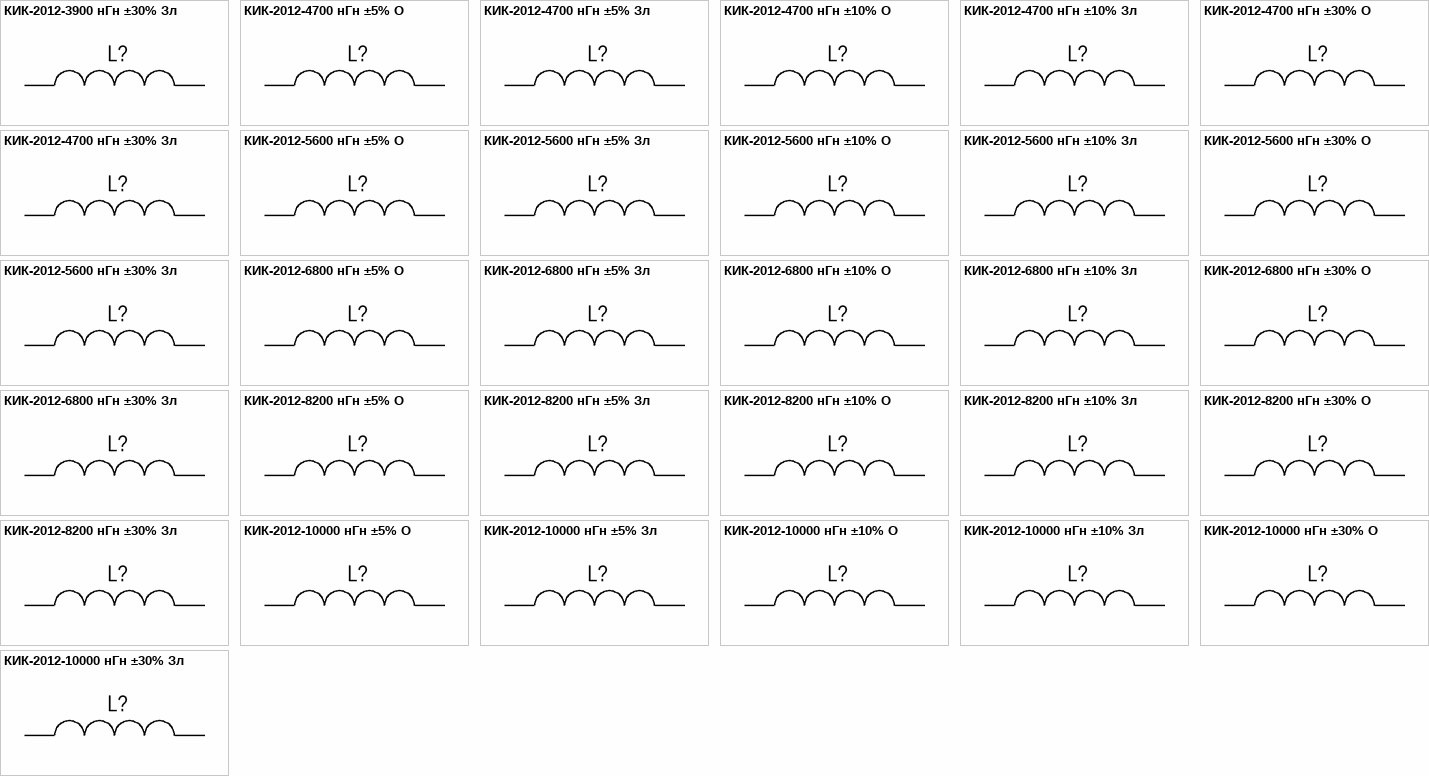
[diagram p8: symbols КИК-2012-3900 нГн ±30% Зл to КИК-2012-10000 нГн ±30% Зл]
## КИК-2012-3900 нГн ±30% Зл
designator L?, comment 3900 нГн ±30%  (value not drawn)
Катушка индуктивности с керамическим сердечником и золотым покрытием контактных площадок; Добротность, не менее: 17; Резонансная частота, не менее: 0.070 ГГц; Сопротивление обмотки постоянноми току, не более: 4.5 Ом; Допустимый ток обмотки: 75 мА; Диапазон рабочих температур: от -60 до +125 ℃; Упаковка: Катушка и лента; Типоразмер: 2012 (0805); Технология монтажа: SMT; Изготовитель: АО "НПО "ЭРКОН"
footprint КИК-2012-Зл (Катушка индуктивности с керамическим сердечникомтипоразмер 2012(0805))
pins: 1, 2

## КИК-2012-4700 нГн ±5% O
designator L?, comment 4700 нГн ±5%  (value not drawn)
Катушка индуктивности с керамическим сердечником и  финишным покрытием контактных площадок оловом; Добротность, не менее: 17; Резонансная частота, не менее: 0.065 ГГц; Сопротивление обмотки постоянноми току, не более: 5 Ом; Допустимый ток обмотки: 50 мА; Диапазон рабочих температур: от -60 до +125 ℃; Упаковка: Катушка и лента; Типоразмер: 2012 (0805); Технология монтажа: SMT; Изготовитель: АО "НПО "ЭРКОН"
footprint КИК-2012-O (Катушка индуктивности с керамическим сердечником типоразмер 2012(0805))
pins: 1, 2

## КИК-2012-4700 нГн ±5% Зл
designator L?, comment 4700 нГн ±5%  (value not drawn)
Катушка индуктивности с керамическим сердечником и золотым покрытием контактных площадок; Добротность, не менее: 17; Резонансная частота, не менее: 0.065 ГГц; Сопротивление обмотки постоянноми току, не более: 5 Ом; Допустимый ток обмотки: 50 мА; Диапазон рабочих температур: от -60 до +125 ℃; Упаковка: Катушка и лента; Типоразмер: 2012 (0805); Технология монтажа: SMT; Изготовитель: АО "НПО "ЭРКОН"
footprint КИК-2012-Зл (Катушка индуктивности с керамическим сердечникомтипоразмер 2012(0805))
pins: 1, 2

## КИК-2012-4700 нГн ±10% O
designator L?, comment 4700 нГн ±10%  (value not drawn)
Катушка индуктивности с керамическим сердечником и  финишным покрытием контактных площадок оловом; Добротность, не менее: 17; Резонансная частота, не менее: 0.065 ГГц; Сопротивление обмотки постоянноми току, не более: 5 Ом; Допустимый ток обмотки: 50 мА; Диапазон рабочих температур: от -60 до +125 ℃; Упаковка: Катушка и лента; Типоразмер: 2012 (0805); Технология монтажа: SMT; Изготовитель: АО "НПО "ЭРКОН"
footprint КИК-2012-O (Катушка индуктивности с керамическим сердечником типоразмер 2012(0805))
pins: 1, 2

## КИК-2012-4700 нГн ±10% Зл
designator L?, comment 4700 нГн ±10%  (value not drawn)
Катушка индуктивности с керамическим сердечником и золотым покрытием контактных площадок; Добротность, не менее: 17; Резонансная частота, не менее: 0.065 ГГц; Сопротивление обмотки постоянноми току, не более: 5 Ом; Допустимый ток обмотки: 50 мА; Диапазон рабочих температур: от -60 до +125 ℃; Упаковка: Катушка и лента; Типоразмер: 2012 (0805); Технология монтажа: SMT; Изготовитель: АО "НПО "ЭРКОН"
footprint КИК-2012-Зл (Катушка индуктивности с керамическим сердечникомтипоразмер 2012(0805))
pins: 1, 2

## КИК-2012-4700 нГн ±30% O
designator L?, comment 4700 нГн ±30%  (value not drawn)
Катушка индуктивности с керамическим сердечником и  финишным покрытием контактных площадок оловом; Добротность, не менее: 17; Резонансная частота, не менее: 0.065 ГГц; Сопротивление обмотки постоянноми току, не более: 5 Ом; Допустимый ток обмотки: 50 мА; Диапазон рабочих температур: от -60 до +125 ℃; Упаковка: Катушка и лента; Типоразмер: 2012 (0805); Технология монтажа: SMT; Изготовитель: АО "НПО "ЭРКОН"
footprint КИК-2012-O (Катушка индуктивности с керамическим сердечником типоразмер 2012(0805))
pins: 1, 2

## КИК-2012-4700 нГн ±30% Зл
designator L?, comment 4700 нГн ±30%  (value not drawn)
Катушка индуктивности с керамическим сердечником и золотым покрытием контактных площадок; Добротность, не менее: 17; Резонансная частота, не менее: 0.065 ГГц; Сопротивление обмотки постоянноми току, не более: 5 Ом; Допустимый ток обмотки: 50 мА; Диапазон рабочих температур: от -60 до +125 ℃; Упаковка: Катушка и лента; Типоразмер: 2012 (0805); Технология монтажа: SMT; Изготовитель: АО "НПО "ЭРКОН"
footprint КИК-2012-Зл (Катушка индуктивности с керамическим сердечникомтипоразмер 2012(0805))
pins: 1, 2

## КИК-2012-5600 нГн ±5% O
designator L?, comment 5600 нГн ±5%  (value not drawn)
Катушка индуктивности с керамическим сердечником и  финишным покрытием контактных площадок оловом; Добротность, не менее: 17; Резонансная частота, не менее: 0.065 ГГц; Сопротивление обмотки постоянноми току, не более: 7.8 Ом; Допустимый ток обмотки: 50 мА; Диапазон рабочих температур: от -60 до +125 ℃; Упаковка: Катушка и лента; Типоразмер: 2012 (0805); Технология монтажа: SMT; Изготовитель: АО "НПО "ЭРКОН"
footprint КИК-2012-O (Катушка индуктивности с керамическим сердечником типоразмер 2012(0805))
pins: 1, 2

## КИК-2012-5600 нГн ±5% Зл
designator L?, comment 5600 нГн ±5%  (value not drawn)
Катушка индуктивности с керамическим сердечником и золотым покрытием контактных площадок; Добротность, не менее: 17; Резонансная частота, не менее: 0.065 ГГц; Сопротивление обмотки постоянноми току, не более: 7.8 Ом; Допустимый ток обмотки: 50 мА; Диапазон рабочих температур: от -60 до +125 ℃; Упаковка: Катушка и лента; Типоразмер: 2012 (0805); Технология монтажа: SMT; Изготовитель: АО "НПО "ЭРКОН"
footprint КИК-2012-Зл (Катушка индуктивности с керамическим сердечникомтипоразмер 2012(0805))
pins: 1, 2

## КИК-2012-5600 нГн ±10% O
designator L?, comment 5600 нГн ±10%  (value not drawn)
Катушка индуктивности с керамическим сердечником и  финишным покрытием контактных площадок оловом; Добротность, не менее: 17; Резонансная частота, не менее: 0.065 ГГц; Сопротивление обмотки постоянноми току, не более: 7.8 Ом; Допустимый ток обмотки: 50 мА; Диапазон рабочих температур: от -60 до +125 ℃; Упаковка: Катушка и лента; Типоразмер: 2012 (0805); Технология монтажа: SMT; Изготовитель: АО "НПО "ЭРКОН"
footprint КИК-2012-O (Катушка индуктивности с керамическим сердечником типоразмер 2012(0805))
pins: 1, 2

## КИК-2012-5600 нГн ±10% Зл
designator L?, comment 5600 нГн ±10%  (value not drawn)
Катушка индуктивности с керамическим сердечником и золотым покрытием контактных площадок; Добротность, не менее: 17; Резонансная частота, не менее: 0.065 ГГц; Сопротивление обмотки постоянноми току, не более: 7.8 Ом; Допустимый ток обмотки: 50 мА; Диапазон рабочих температур: от -60 до +125 ℃; Упаковка: Катушка и лента; Типоразмер: 2012 (0805); Технология монтажа: SMT; Изготовитель: АО "НПО "ЭРКОН"
footprint КИК-2012-Зл (Катушка индуктивности с керамическим сердечникомтипоразмер 2012(0805))
pins: 1, 2

## КИК-2012-5600 нГн ±30% O
designator L?, comment 5600 нГн ±30%  (value not drawn)
Катушка индуктивности с керамическим сердечником и  финишным покрытием контактных площадок оловом; Добротность, не менее: 17; Резонансная частота, не менее: 0.065 ГГц; Сопротивление обмотки постоянноми току, не более: 7.8 Ом; Допустимый ток обмотки: 50 мА; Диапазон рабочих температур: от -60 до +125 ℃; Упаковка: Катушка и лента; Типоразмер: 2012 (0805); Технология монтажа: SMT; Изготовитель: АО "НПО "ЭРКОН"
footprint КИК-2012-O (Катушка индуктивности с керамическим сердечником типоразмер 2012(0805))
pins: 1, 2

## КИК-2012-5600 нГн ±30% Зл
designator L?, comment 5600 нГн ±30%  (value not drawn)
Катушка индуктивности с керамическим сердечником и золотым покрытием контактных площадок; Добротность, не менее: 17; Резонансная частота, не менее: 0.065 ГГц; Сопротивление обмотки постоянноми току, не более: 7.8 Ом; Допустимый ток обмотки: 50 мА; Диапазон рабочих температур: от -60 до +125 ℃; Упаковка: Катушка и лента; Типоразмер: 2012 (0805); Технология монтажа: SMT; Изготовитель: АО "НПО "ЭРКОН"
footprint КИК-2012-Зл (Катушка индуктивности с керамическим сердечникомтипоразмер 2012(0805))
pins: 1, 2

## КИК-2012-6800 нГн ±5% O
designator L?, comment 6800 нГн ±5%  (value not drawn)
Катушка индуктивности с керамическим сердечником и  финишным покрытием контактных площадок оловом; Добротность, не менее: 17; Резонансная частота, не менее: 0.05 ГГц; Сопротивление обмотки постоянноми току, не более: 8.5 Ом; Допустимый ток обмотки: 45 мА; Диапазон рабочих температур: от -60 до +125 ℃; Упаковка: Катушка и лента; Типоразмер: 2012 (0805); Технология монтажа: SMT; Изготовитель: АО "НПО "ЭРКОН"
footprint КИК-2012-O (Катушка индуктивности с керамическим сердечником типоразмер 2012(0805))
pins: 1, 2

## КИК-2012-6800 нГн ±5% Зл
designator L?, comment 6800 нГн ±5%  (value not drawn)
Катушка индуктивности с керамическим сердечником и золотым покрытием контактных площадок; Добротность, не менее: 17; Резонансная частота, не менее: 0.05 ГГц; Сопротивление обмотки постоянноми току, не более: 8.5 Ом; Допустимый ток обмотки: 45 мА; Диапазон рабочих температур: от -60 до +125 ℃; Упаковка: Катушка и лента; Типоразмер: 2012 (0805); Технология монтажа: SMT; Изготовитель: АО "НПО "ЭРКОН"
footprint КИК-2012-Зл (Катушка индуктивности с керамическим сердечникомтипоразмер 2012(0805))
pins: 1, 2

## КИК-2012-6800 нГн ±10% O
designator L?, comment 6800 нГн ±10%  (value not drawn)
Катушка индуктивности с керамическим сердечником и  финишным покрытием контактных площадок оловом; Добротность, не менее: 17; Резонансная частота, не менее: 0.05 ГГц; Сопротивление обмотки постоянноми току, не более: 8.5 Ом; Допустимый ток обмотки: 45 мА; Диапазон рабочих температур: от -60 до +125 ℃; Упаковка: Катушка и лента; Типоразмер: 2012 (0805); Технология монтажа: SMT; Изготовитель: АО "НПО "ЭРКОН"
footprint КИК-2012-O (Катушка индуктивности с керамическим сердечником типоразмер 2012(0805))
pins: 1, 2

## КИК-2012-6800 нГн ±10% Зл
designator L?, comment 6800 нГн ±10%  (value not drawn)
Катушка индуктивности с керамическим сердечником и золотым покрытием контактных площадок; Добротность, не менее: 17; Резонансная частота, не менее: 0.05 ГГц; Сопротивление обмотки постоянноми току, не более: 8.5 Ом; Допустимый ток обмотки: 45 мА; Диапазон рабочих температур: от -60 до +125 ℃; Упаковка: Катушка и лента; Типоразмер: 2012 (0805); Технология монтажа: SMT; Изготовитель: АО "НПО "ЭРКОН"
footprint КИК-2012-Зл (Катушка индуктивности с керамическим сердечникомтипоразмер 2012(0805))
pins: 1, 2

## КИК-2012-6800 нГн ±30% O
designator L?, comment 6800 нГн ±30%  (value not drawn)
Катушка индуктивности с керамическим сердечником и  финишным покрытием контактных площадок оловом; Добротность, не менее: 17; Резонансная частота, не менее: 0.05 ГГц; Сопротивление обмотки постоянноми току, не более: 8.5 Ом; Допустимый ток обмотки: 45 мА; Диапазон рабочих температур: от -60 до +125 ℃; Упаковка: Катушка и лента; Типоразмер: 2012 (0805); Технология монтажа: SMT; Изготовитель: АО "НПО "ЭРКОН"
footprint КИК-2012-O (Катушка индуктивности с керамическим сердечником типоразмер 2012(0805))
pins: 1, 2

## КИК-2012-6800 нГн ±30% Зл
designator L?, comment 6800 нГн ±30%  (value not drawn)
Катушка индуктивности с керамическим сердечником и золотым покрытием контактных площадок; Добротность, не менее: 17; Резонансная частота, не менее: 0.05 ГГц; Сопротивление обмотки постоянноми току, не более: 8.5 Ом; Допустимый ток обмотки: 45 мА; Диапазон рабочих температур: от -60 до +125 ℃; Упаковка: Катушка и лента; Типоразмер: 2012 (0805); Технология монтажа: SMT; Изготовитель: АО "НПО "ЭРКОН"
footprint КИК-2012-Зл (Катушка индуктивности с керамическим сердечникомтипоразмер 2012(0805))
pins: 1, 2

## КИК-2012-8200 нГн ±5% O
designator L?, comment 8200 нГн ±5%  (value not drawn)
Катушка индуктивности с керамическим сердечником и  финишным покрытием контактных площадок оловом; Добротность, не менее: 17; Резонансная частота, не менее: 0.055 ГГц; Сопротивление обмотки постоянноми току, не более: 10.0 Ом; Допустимый ток обмотки: 40 мА; Диапазон рабочих температур: от -60 до +125 ℃; Упаковка: Катушка и лента; Типоразмер: 2012 (0805); Технология монтажа: SMT; Изготовитель: АО "НПО "ЭРКОН"
footprint КИК-2012-O (Катушка индуктивности с керамическим сердечником типоразмер 2012(0805))
pins: 1, 2

## КИК-2012-8200 нГн ±5% Зл
designator L?, comment 8200 нГн ±5%  (value not drawn)
Катушка индуктивности с керамическим сердечником и золотым покрытием контактных площадок; Добротность, не менее: 17; Резонансная частота, не менее: 0.055 ГГц; Сопротивление обмотки постоянноми току, не более: 10.0 Ом; Допустимый ток обмотки: 40 мА; Диапазон рабочих температур: от -60 до +125 ℃; Упаковка: Катушка и лента; Типоразмер: 2012 (0805); Технология монтажа: SMT; Изготовитель: АО "НПО "ЭРКОН"
footprint КИК-2012-Зл (Катушка индуктивности с керамическим сердечникомтипоразмер 2012(0805))
pins: 1, 2

## КИК-2012-8200 нГн ±10% O
designator L?, comment 8200 нГн ±10%  (value not drawn)
Катушка индуктивности с керамическим сердечником и  финишным покрытием контактных площадок оловом; Добротность, не менее: 17; Резонансная частота, не менее: 0.055 ГГц; Сопротивление обмотки постоянноми току, не более: 10.0 Ом; Допустимый ток обмотки: 40 мА; Диапазон рабочих температур: от -60 до +125 ℃; Упаковка: Катушка и лента; Типоразмер: 2012 (0805); Технология монтажа: SMT; Изготовитель: АО "НПО "ЭРКОН"
footprint КИК-2012-O (Катушка индуктивности с керамическим сердечником типоразмер 2012(0805))
pins: 1, 2

## КИК-2012-8200 нГн ±10% Зл
designator L?, comment 8200 нГн ±10%  (value not drawn)
Катушка индуктивности с керамическим сердечником и золотым покрытием контактных площадок; Добротность, не менее: 17; Резонансная частота, не менее: 0.055 ГГц; Сопротивление обмотки постоянноми току, не более: 10.0 Ом; Допустимый ток обмотки: 40 мА; Диапазон рабочих температур: от -60 до +125 ℃; Упаковка: Катушка и лента; Типоразмер: 2012 (0805); Технология монтажа: SMT; Изготовитель: АО "НПО "ЭРКОН"
footprint КИК-2012-Зл (Катушка индуктивности с керамическим сердечникомтипоразмер 2012(0805))
pins: 1, 2

## КИК-2012-8200 нГн ±30% O
designator L?, comment 8200 нГн ±30%  (value not drawn)
Катушка индуктивности с керамическим сердечником и  финишным покрытием контактных площадок оловом; Добротность, не менее: 17; Резонансная частота, не менее: 0.055 ГГц; Сопротивление обмотки постоянноми току, не более: 10.0 Ом; Допустимый ток обмотки: 40 мА; Диапазон рабочих температур: от -60 до +125 ℃; Упаковка: Катушка и лента; Типоразмер: 2012 (0805); Технология монтажа: SMT; Изготовитель: АО "НПО "ЭРКОН"
footprint КИК-2012-O (Катушка индуктивности с керамическим сердечником типоразмер 2012(0805))
pins: 1, 2

## КИК-2012-8200 нГн ±30% Зл
designator L?, comment 8200 нГн ±30%  (value not drawn)
Катушка индуктивности с керамическим сердечником и золотым покрытием контактных площадок; Добротность, не менее: 17; Резонансная частота, не менее: 0.055 ГГц; Сопротивление обмотки постоянноми току, не более: 10.0 Ом; Допустимый ток обмотки: 40 мА; Диапазон рабочих температур: от -60 до +125 ℃; Упаковка: Катушка и лента; Типоразмер: 2012 (0805); Технология монтажа: SMT; Изготовитель: АО "НПО "ЭРКОН"
footprint КИК-2012-Зл (Катушка индуктивности с керамическим сердечникомтипоразмер 2012(0805))
pins: 1, 2

## КИК-2012-10000 нГн ±5% O
designator L?, comment 10000 нГн ±5%  (value not drawn)
Катушка индуктивности с керамическим сердечником и  финишным покрытием контактных площадок оловом; Добротность, не менее: 17; Резонансная частота, не менее: 0.05 ГГц; Сопротивление обмотки постоянноми току, не более: 17.0 Ом; Допустимый ток обмотки: 40 мА; Диапазон рабочих температур: от -60 до +125 ℃; Упаковка: Катушка и лента; Типоразмер: 2012 (0805); Технология монтажа: SMT; Изготовитель: АО "НПО "ЭРКОН"
footprint КИК-2012-O (Катушка индуктивности с керамическим сердечником типоразмер 2012(0805))
pins: 1, 2

## КИК-2012-10000 нГн ±5% Зл
designator L?, comment 10000 нГн ±5%  (value not drawn)
Катушка индуктивности с керамическим сердечником и золотым покрытием контактных площадок; Добротность, не менее: 17; Резонансная частота, не менее: 0.05 ГГц; Сопротивление обмотки постоянноми току, не более: 17.0 Ом; Допустимый ток обмотки: 40 мА; Диапазон рабочих температур: от -60 до +125 ℃; Упаковка: Катушка и лента; Типоразмер: 2012 (0805); Технология монтажа: SMT; Изготовитель: АО "НПО "ЭРКОН"
footprint КИК-2012-Зл (Катушка индуктивности с керамическим сердечникомтипоразмер 2012(0805))
pins: 1, 2

## КИК-2012-10000 нГн ±10% O
designator L?, comment 10000 нГн ±10%  (value not drawn)
Катушка индуктивности с керамическим сердечником и  финишным покрытием контактных площадок оловом; Добротность, не менее: 17; Резонансная частота, не менее: 0.05 ГГц; Сопротивление обмотки постоянноми току, не более: 17.0 Ом; Допустимый ток обмотки: 40 мА; Диапазон рабочих температур: от -60 до +125 ℃; Упаковка: Катушка и лента; Типоразмер: 2012 (0805); Технология монтажа: SMT; Изготовитель: АО "НПО "ЭРКОН"
footprint КИК-2012-O (Катушка индуктивности с керамическим сердечником типоразмер 2012(0805))
pins: 1, 2

## КИК-2012-10000 нГн ±10% Зл
designator L?, comment 10000 нГн ±10%  (value not drawn)
Катушка индуктивности с керамическим сердечником и золотым покрытием контактных площадок; Добротность, не менее: 17; Резонансная частота, не менее: 0.05 ГГц; Сопротивление обмотки постоянноми току, не более: 17.0 Ом; Допустимый ток обмотки: 40 мА; Диапазон рабочих температур: от -60 до +125 ℃; Упаковка: Катушка и лента; Типоразмер: 2012 (0805); Технология монтажа: SMT; Изготовитель: АО "НПО "ЭРКОН"
footprint КИК-2012-Зл (Катушка индуктивности с керамическим сердечникомтипоразмер 2012(0805))
pins: 1, 2

## КИК-2012-10000 нГн ±30% O
designator L?, comment 10000 нГн ±30%  (value not drawn)
Катушка индуктивности с керамическим сердечником и  финишным покрытием контактных площадок оловом; Добротность, не менее: 17; Резонансная частота, не менее: 0.05 ГГц; Сопротивление обмотки постоянноми току, не более: 17.0 Ом; Допустимый ток обмотки: 40 мА; Диапазон рабочих температур: от -60 до +125 ℃; Упаковка: Катушка и лента; Типоразмер: 2012 (0805); Технология монтажа: SMT; Изготовитель: АО "НПО "ЭРКОН"
footprint КИК-2012-O (Катушка индуктивности с керамическим сердечником типоразмер 2012(0805))
pins: 1, 2

## КИК-2012-10000 нГн ±30% Зл
designator L?, comment 10000 нГн ±30%  (value not drawn)
Катушка индуктивности с керамическим сердечником и золотым покрытием контактных площадок; Добротность, не менее: 17; Резонансная частота, не менее: 0.05 ГГц; Сопротивление обмотки постоянноми току, не более: 17.0 Ом; Допустимый ток обмотки: 40 мА; Диапазон рабочих температур: от -60 до +125 ℃; Упаковка: Катушка и лента; Типоразмер: 2012 (0805); Технология монтажа: SMT; Изготовитель: АО "НПО "ЭРКОН"
footprint КИК-2012-Зл (Катушка индуктивности с керамическим сердечникомтипоразмер 2012(0805))
pins: 1, 2



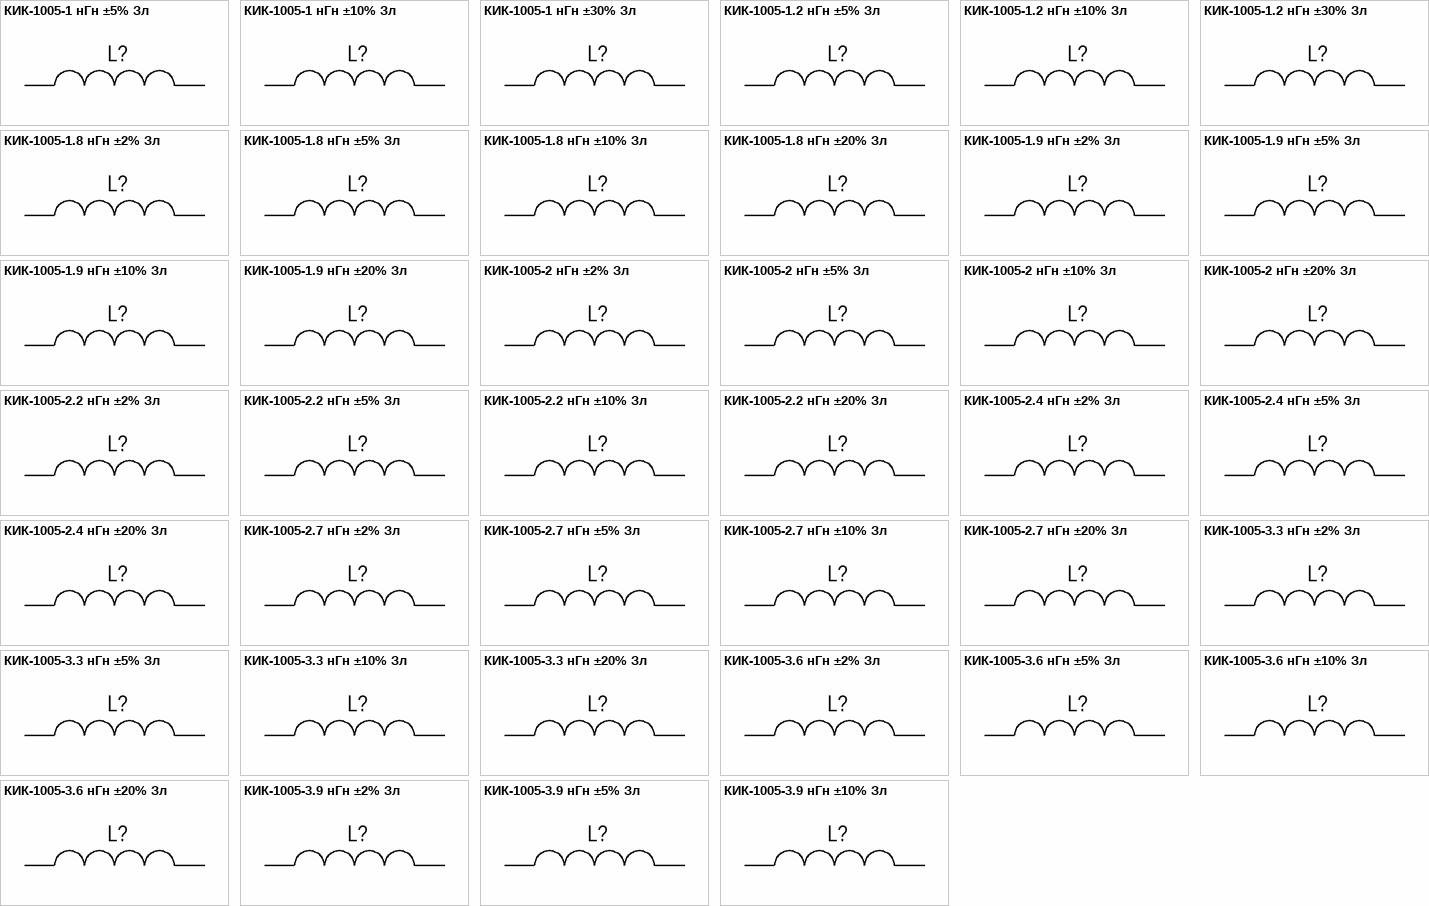
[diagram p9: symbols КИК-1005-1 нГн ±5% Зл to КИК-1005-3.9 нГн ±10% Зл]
## КИК-1005-1 нГн ±5% Зл
designator L?, comment 1 нГн ±5%  (value not drawn)
Катушка индуктивности с керамическим сердечником и золотым покрытием контактных площадок; Номиналиная индуктивность: 1 нГн; Добротность, не менее: 13; Резонансная частота, не менее: 12.70 ГГц; Сопротивление обмотки постоянноми току, не более: 0.045 Ом; Допустимый ток обмотки: 1360 мА; Диапазон рабочих температур: от -60 до +125 ℃; Упаковка: Катушка и лента; Типоразмер: 1005 (0402); Технология монтажа: SMT; Изготовитель: АО "НПО "ЭРКОН"
footprint КИК-1005_Зл (Катушка индуктивности с керамическим сердечником типоразмер 1005(0402))
pins: 1, 2

## КИК-1005-1 нГн ±10% Зл
designator L?, comment 1 нГн ±10%  (value not drawn)
Катушка индуктивности с керамическим сердечником и золотым покрытием контактных площадок; Номиналиная индуктивность: 1 нГн; Добротность, не менее: 13; Резонансная частота, не менее: 12.70 ГГц; Сопротивление обмотки постоянноми току, не более: 0.045 Ом; Допустимый ток обмотки: 1360 мА; Диапазон рабочих температур: от -60 до +125 ℃; Технология монтажа: SMT; Типоразмер: 1005 (0402); Упаковка: Катушка и лента; Изготовитель: АО "НПО "ЭРКОН"
footprint КИК-1005_Зл (Катушка индуктивности с керамическим сердечником типоразмер 1005(0402))
pins: 1, 2

## КИК-1005-1 нГн ±30% Зл
designator L?, comment 1 нГн ±30%  (value not drawn)
Катушка индуктивности с керамическим сердечником и золотым покрытием контактных площадок; Номиналиная индуктивность: 1 нГн; Добротность, не менее: 13; Резонансная частота, не менее: 12.70 ГГц; Сопротивление обмотки постоянноми току, не более: 0.045 Ом; Допустимый ток обмотки: 1360 мА; Диапазон рабочих температур: от -60 до +125 ℃; Упаковка: Катушка и лента; Типоразмер: 1005 (0402); Технология монтажа: SMT; Изготовитель: АО "НПО "ЭРКОН"
footprint КИК-1005_Зл (Катушка индуктивности с керамическим сердечником типоразмер 1005(0402))
pins: 1, 2

## КИК-1005-1.2 нГн ±5% Зл
designator L?, comment 1.2 нГн ±5%  (value not drawn)
Катушка индуктивности с керамическим сердечником и золотым покрытием контактных площадок; Номиналиная индуктивность: 1.2 нГн; Добротность, не менее: 13; Резонансная частота, не менее: 12.90 ГГц; Сопротивление обмотки постоянноми току, не более: 0.090 Ом; Допустимый ток обмотки: 740 мА; Изготовитель: *АО "НПО "ЭРКОН"; Диапазон рабочих температур: *от -60 до +125 ℃; ипоразмер: 1005 (0402); Технология монтажа: * SMT; Упаковка: Катушка и лента
footprint КИК-1005_Зл (Катушка индуктивности с керамическим сердечником типоразмер 1005(0402))
pins: 1, 2

## КИК-1005-1.2 нГн ±10% Зл
designator L?, comment 1.2 нГн ±10%  (value not drawn)
Катушка индуктивности с керамическим сердечником и золотым покрытием контактных площадок; Номиналиная индуктивность: 1.2 нГн; Добротность, не менее: 13; Резонансная частота, не менее: 12.90 ГГц; Сопротивление обмотки постоянноми току, не более: 0.090 Ом; Допустимый ток обмотки: 740 мА; Изготовитель: АО "НПО "ЭРКОН"; Диапазон рабочих температур: -60 до +125 ℃; Технология монтажа: SMT; Типоразмер: 1005 (0402); Упаковка: Катушка и лента
footprint КИК-1005_Зл (Катушка индуктивности с керамическим сердечником типоразмер 1005(0402))
pins: 1, 2

## КИК-1005-1.2 нГн ±30% Зл
designator L?, comment 1.2 нГн ±30%  (value not drawn)
Катушка индуктивности с керамическим сердечником и золотым покрытием контактных площадок; Номиналиная индуктивность: 1.2 нГн; Добротность, не менее: 13; Резонансная частота, не менее: 12.90 ГГц; Сопротивление обмотки постоянноми току, не более: 0.090 Ом; Допустимый ток обмотки: 740 мА; Изготовитель: АО "НПО "ЭРКОН"; Диапазон рабочих температур: -60 до +125 ℃; Технология монтажа: SMT; Типоразмер: 1005 (0402); Упаковка: Катушка и лента
footprint КИК-1005_Зл (Катушка индуктивности с керамическим сердечником типоразмер 1005(0402))
pins: 1, 2

## КИК-1005-1.8 нГн ±2% Зл
designator L?, comment 1.8 нГн ±2%  (value not drawn)
Катушка индуктивности с керамическим сердечником и золотым покрытием контактных площадок; Номиналиная индуктивность: 1.8 нГн; Добротность, не менее: 13; Резонансная частота, не менее: 12.00 ГГц; Сопротивление обмотки постоянноми току, не более: 0.090 Ом; Допустимый ток обмотки: 1040 мА; Изготовитель: АО "НПО "ЭРКОН"; Диапазон рабочих температур: от -60 до +125 ℃; Технология монтажа: SMT; Типоразмер: 1005 (0402); Упаковка: Катушка и лента
footprint КИК-1005_Зл (Катушка индуктивности с керамическим сердечником типоразмер 1005(0402))
pins: 1, 2

## КИК-1005-1.8 нГн ±5% Зл
designator L?, comment 1.8 нГн ±5%  (value not drawn)
Катушка индуктивности с керамическим сердечником и золотым покрытием контактных площадок; Номиналиная индуктивность: 1.8 нГн; Добротность, не менее: 13; Резонансная частота, не менее: 12.00 ГГц; Сопротивление обмотки постоянноми току, не более: 0.090 Ом; Допустимый ток обмотки: 1040 мА; Изготовитель: АО "НПО "ЭРКОН"; Диапазон рабочих температур: от -60 до +125 ℃; Технология монтажа: SMT; Типоразмер: 1005 (0402); Упаковка: Катушка и лента
footprint КИК-1005_Зл (Катушка индуктивности с керамическим сердечником типоразмер 1005(0402))
pins: 1, 2

## КИК-1005-1.8 нГн ±10% Зл
designator L?, comment 1.8 нГн ±10%  (value not drawn)
Катушка индуктивности с керамическим сердечником и золотым покрытием контактных площадок; Номиналиная индуктивность: 1.8 нГн; Добротность, не менее: 13; Резонансная частота, не менее: 12.00 ГГц; Сопротивление обмотки постоянноми току, не более: 0.090 Ом; Допустимый ток обмотки: 1040 мА; Изготовитель: АО "НПО "ЭРКОН"; Диапазон рабочих температур: от -60 до +125 ℃; Технология монтажа: SMT; Типоразмер: 1005 (0402); Упаковка: Катушка и лента
footprint КИК-1005_Зл (Катушка индуктивности с керамическим сердечником типоразмер 1005(0402))
pins: 1, 2

## КИК-1005-1.8 нГн ±20% Зл
designator L?, comment 1.8 нГн ±20%  (value not drawn)
Катушка индуктивности с керамическим сердечником и золотым покрытием контактных площадок; Номиналиная индуктивность: 1.8 нГн; Добротность, не менее: 13; Резонансная частота, не менее: 12.00 ГГц; Сопротивление обмотки постоянноми току, не более: 0.090 Ом; Допустимый ток обмотки: 1040 мА; Изготовитель: АО "НПО "ЭРКОН"; Диапазон рабочих температур: от -60 до +125 ℃; Технология монтажа: SMT; Типоразмер: 1005 (0402); Упаковка: Катушка и лента
footprint КИК-1005_Зл (Катушка индуктивности с керамическим сердечником типоразмер 1005(0402))
pins: 1, 2

## КИК-1005-1.9 нГн ±2% Зл
designator L?, comment 1.9 нГн ±2%  (value not drawn)
Катушка индуктивности с керамическим сердечником и золотым покрытием контактных площадок; Номиналиная индуктивность: 1.9 нГн; Добротность, не менее: 13; Резонансная частота, не менее: 11.30 ГГц; Сопротивление обмотки постоянноми току, не более: 0.090 Ом; Допустимый ток обмотки: 1040 мА; Диапазон рабочих температур: от -60 до +125 ℃; Технология монтажа: SMT; Типоразмер: 1005 (0402; Упаковка: Катушка и лента
footprint КИК-1005_Зл (Катушка индуктивности с керамическим сердечником типоразмер 1005(0402))
pins: 1, 2

## КИК-1005-1.9 нГн ±5% Зл
designator L?, comment 1.9 нГн ±5%  (value not drawn)
Катушка индуктивности с керамическим сердечником и золотым покрытием контактных площадок; Номиналиная индуктивность: 1.9 нГн; Добротность, не менее: 13; Резонансная частота, не менее: 11.30 ГГц; Сопротивление обмотки постоянноми току, не более: 0.090 Ом; Допустимый ток обмотки: 1040 мА; Диапазон рабочих температур: от -60 до +125 ℃; Технология монтажа: SMT; Типоразмер: 1005 (0402; Упаковка: Катушка и лента
footprint КИК-1005_Зл (Катушка индуктивности с керамическим сердечником типоразмер 1005(0402))
pins: 1, 2

## КИК-1005-1.9 нГн ±10% Зл
designator L?, comment 1.9 нГн ±10%  (value not drawn)
Катушка индуктивности с керамическим сердечником и золотым покрытием контактных площадок; Номиналиная индуктивность: 1.9 нГн; Добротность, не менее: 13; Резонансная частота, не менее: 11.30 ГГц; Сопротивление обмотки постоянноми току, не более: 0.090 Ом; Допустимый ток обмотки: 1040 мА; Изготовитель: АО "НПО "ЭРКОН"; Диапазон рабочих температур: от -60 до +125 ℃; Технология монтажа: SMT; Типоразмер: 1005 (0402); Упаковка: Катушка и лента
footprint КИК-1005_Зл (Катушка индуктивности с керамическим сердечником типоразмер 1005(0402))
pins: 1, 2

## КИК-1005-1.9 нГн ±20% Зл
designator L?, comment 1.9 нГн ±20%  (value not drawn)
Катушка индуктивности с керамическим сердечником и золотым покрытием контактных площадок; Номиналиная индуктивность: 1.9 нГн; Добротность, не менее: 13; Резонансная частота, не менее: 11.30 ГГц; Сопротивление обмотки постоянноми току, не более: 0.090 Ом; Допустимый ток обмотки: 1040 мА; Изготовитель: АО "НПО "ЭРКОН"; Диапазон рабочих температур: от -60 до +125 ℃; Технология монтажа: SMT; Типоразмер: 1005 (0402); Упаковка: Катушка и лента
footprint КИК-1005_Зл (Катушка индуктивности с керамическим сердечником типоразмер 1005(0402))
pins: 1, 2

## КИК-1005-2 нГн ±2% Зл
designator L?, comment 2 нГн ±2%  (value not drawn)
Катушка индуктивности с керамическим сердечником и золотым покрытием контактных площадок; Номиналиная индуктивность: 2 нГн; Допускаемое отклонение индуктивности: ±5%; Добротность, не менее: 13; Резонансная частота, не менее: 11.10 ГГц; Сопротивление обмотки постоянноми току, не более: 0.090 Ом; Допустимый ток обмотки: 1040 мА; Диапазон рабочих температур: от -60 до +125 ℃; Изготовитель: АО "НПО "ЭРКОН"; Технология монтажа: SMT; Типоразмер: 1005 (0402); Упаковка: Катушка и лента
footprint КИК-1005_Зл (Катушка индуктивности с керамическим сердечником типоразмер 1005(0402))
pins: 1, 2

## КИК-1005-2 нГн ±5% Зл
designator L?, comment 2 нГн ±5%  (value not drawn)
Катушка индуктивности с керамическим сердечником и золотым покрытием контактных площадок; Номиналиная индуктивность: 2 нГн; Добротность, не менее: 13; Резонансная частота, не менее: 11.10 ГГц; Сопротивление обмотки постоянноми току, не более: 0.090 Ом; Допустимый ток обмотки: 1040 мА; Диапазон рабочих температур: от -60 до +125 ℃; Изготовитель: АО "НПО "ЭРКОН"; Технология монтажа: SMT; Типоразмер: 1005 (0402); Упаковка: Катушка и лента
footprint КИК-1005_Зл (Катушка индуктивности с керамическим сердечником типоразмер 1005(0402))
pins: 1, 2

## КИК-1005-2 нГн ±10% Зл
designator L?, comment 2 нГн ±10%  (value not drawn)
Катушка индуктивности с керамическим сердечником и золотым покрытием контактных площадок; Номиналиная индуктивность: 2 нГн; Добротность, не менее: 13; Резонансная частота, не менее: 11.10 ГГц; Сопротивление обмотки постоянноми току, не более: 0.090 Ом; Допустимый ток обмотки: 1040 мА; Изготовитель: АО "НПО "ЭРКОН"; Диапазон рабочих температур: от -60 до +125 ℃; Технология монтажа: SMT; Типоразмер: 1005 (0402); Упаковка: Катушка и лента
footprint КИК-1005_Зл (Катушка индуктивности с керамическим сердечником типоразмер 1005(0402))
pins: 1, 2

## КИК-1005-2 нГн ±20% Зл
designator L?, comment 2 нГн ±20%  (value not drawn)
Катушка индуктивности с керамическим сердечником и золотым покрытием контактных площадок; Номиналиная индуктивность: 2 нГн; Добротность, не менее: 13; Резонансная частота, не менее: 11.10 ГГц; Сопротивление обмотки постоянноми току, не более: 0.090 Ом; Допустимый ток обмотки: 1040 мА; Изготовитель: АО "НПО "ЭРКОН"; Диапазон рабочих температур: от -60 до +125 ℃; Технология монтажа: SMT; Типоразмер: 1005 (0402); Упаковка: Катушка и лента
footprint КИК-1005_Зл (Катушка индуктивности с керамическим сердечником типоразмер 1005(0402))
pins: 1, 2

## КИК-1005-2.2 нГн ±2% Зл
designator L?, comment 2.2 нГн ±2%  (value not drawn)
Катушка индуктивности с керамическим сердечником и золотым покрытием контактных площадок; Номиналиная индуктивность: 2.2 нГн; Добротность, не менее: 18; Резонансная частота, не менее: 10.80 ГГц; Сопротивление обмотки постоянноми току, не более: 0.090 Ом; Допустимый ток обмотки: 960 мА; Изготовитель: АО "НПО "ЭРКОН"; Диапазон рабочих температур: от -60 до +125 ℃; Технология монтажа: SMT; Типоразмер: 1005 (0402); Упаковка: Катушка и лента
footprint КИК-1005_Зл (Катушка индуктивности с керамическим сердечником типоразмер 1005(0402))
pins: 1, 2

## КИК-1005-2.2 нГн ±5% Зл
designator L?, comment 2.2 нГн ±5%  (value not drawn)
Катушка индуктивности с керамическим сердечником и золотым покрытием контактных площадок; Номиналиная индуктивность: 2.2 нГн; Добротность, не менее: 18; Резонансная частота, не менее: 10.80 ГГц; Сопротивление обмотки постоянноми току, не более: 0.090 Ом; Допустимый ток обмотки: 960 мА; Изготовитель: АО "НПО "ЭРКОН"; Диапазон рабочих температур: от -60 до +125 ℃; Технология монтажа: SMT; Типоразмер: 1005 (0402); Упаковка: Катушка и лента
footprint КИК-1005_Зл (Катушка индуктивности с керамическим сердечником типоразмер 1005(0402))
pins: 1, 2

## КИК-1005-2.2 нГн ±10% Зл
designator L?, comment 2.2 нГн ±10%  (value not drawn)
Катушка индуктивности с керамическим сердечником и золотым покрытием контактных площадок; Номиналиная индуктивность: 2.2 нГн; Добротность, не менее: 18; Резонансная частота, не менее: 10.80 ГГц; Сопротивление обмотки постоянноми току, не более: 0.090 Ом; Допустимый ток обмотки: 960 мА; Диапазон рабочих температур: от -60 до +125 ℃; Технология монтажа: SMT; Типоразмер: 1005 (0402); Упаковка: Катушка и лента
footprint КИК-1005_Зл (Катушка индуктивности с керамическим сердечником типоразмер 1005(0402))
pins: 1, 2

## КИК-1005-2.2 нГн ±20% Зл
designator L?, comment 2.2 нГн ±20%  (value not drawn)
Катушка индуктивности с керамическим сердечником и золотым покрытием контактных площадок; Номиналиная индуктивность: 2.2 нГн; Добротность, не менее: 18; Резонансная частота, не менее: 10.80 ГГц; Сопротивление обмотки постоянноми току, не более: 0.090 Ом; Допустимый ток обмотки: 960 мА; Диапазон рабочих температур: от -60 до +125 ℃; Технология монтажа: SMT; Типоразмер: 1005 (0402); Упаковка: Катушка и лента
footprint КИК-1005_Зл (Катушка индуктивности с керамическим сердечником типоразмер 1005(0402))
pins: 1, 2

## КИК-1005-2.4 нГн ±2% Зл
designator L?, comment 2.4нГн ±2%  (value not drawn)
Катушка индуктивности с керамическим сердечником и золотым покрытием контактных площадок; Добротность, не менее: 18; Резонансная частота, не менее: 10.50 ГГц; Сопротивление обмотки постоянноми току, не более: 0.090 Ом; Допустимый ток обмотки: 790 мА; Изготовитель: АО "НПО "ЭРКОН"; Диапазон рабочих температур: от -60 до +125 ℃; Технология монтажа: SMT; Типоразмер: 1005 (0402); Упаковка: Катушка и лента
footprint КИК-1005_Зл (Катушка индуктивности с керамическим сердечником типоразмер 1005(0402))
pins: 1, 2

## КИК-1005-2.4 нГн ±5% Зл
designator L?, comment 2.4нГн ±5%  (value not drawn)
Катушка индуктивности с керамическим сердечником и золотым покрытием контактных площадок; Добротность, не менее: 18; Резонансная частота, не менее: 10.50 ГГц; Сопротивление обмотки постоянноми току, не более: 0.090 Ом; Допустимый ток обмотки: 790 мА; Изготовитель: АО "НПО "ЭРКОН"; Диапазон рабочих температур: от -60 до +125 ℃; Технология монтажа: SMT; Типоразмер: 1005 (0402); Упаковка: Катушка и лента
footprint КИК-1005_Зл (Катушка индуктивности с керамическим сердечником типоразмер 1005(0402))
pins: 1, 2

## КИК-1005-2.4 нГн ±20% Зл
designator L?, comment 2.4нГн ±20%  (value not drawn)
Катушка индуктивности с керамическим сердечником и золотым покрытием контактных площадок; Добротность, не менее: 18; Резонансная частота, не менее: 10.50 ГГц; Сопротивление обмотки постоянноми току, не более: 0.090 Ом; Допустимый ток обмотки: 790 мА; Изготовитель: АО "НПО "ЭРКОН"; Диапазон рабочих температур: от -60 до +125 ℃; Технология монтажа: SMT; Типоразмер: 1005 (0402); Упаковка: Катушка и лента
footprint КИК-1005_Зл (Катушка индуктивности с керамическим сердечником типоразмер 1005(0402))
pins: 1, 2

## КИК-1005-2.7 нГн ±2% Зл
designator L?, comment 2.7 нГн ±2%  (value not drawn)
Катушка индуктивности с керамическим сердечником и золотым покрытием контактных площадок; Номиналиная индуктивность: 2.4 нГн; Добротность, не менее: 18; Резонансная частота, не менее: 10.40 ГГц; Сопротивление обмотки постоянноми току, не более: 0.120 Ом; Допустимый ток обмотки: 640 мА; Изготовитель: АО "НПО "ЭРКОН"; Диапазон рабочих температур: от -60 до +125 ℃; Технология монтажа: SMT; Типоразмер: 1005 (0402); Упаковка: Катушка и лента
footprint КИК-1005_Зл (Катушка индуктивности с керамическим сердечником типоразмер 1005(0402))
pins: 1, 2

## КИК-1005-2.7 нГн ±5% Зл
designator L?, comment 2.7 нГн ±5%  (value not drawn)
Катушка индуктивности с керамическим сердечником и золотым покрытием контактных площадок; Номиналиная индуктивность: 2.4 нГн; Добротность, не менее: 18; Резонансная частота, не менее: 10.40 ГГц; Сопротивление обмотки постоянноми току, не более: 0.120 Ом; Допустимый ток обмотки: 640 мА; Изготовитель: АО "НПО "ЭРКОН"; Диапазон рабочих температур: от -60 до +125 ℃; Технология монтажа: SMT; Типоразмер: 1005 (0402); Упаковка: Катушка и лента
footprint КИК-1005_Зл (Катушка индуктивности с керамическим сердечником типоразмер 1005(0402))
pins: 1, 2

## КИК-1005-2.7 нГн ±10% Зл
designator L?, comment 2.7 нГн ±10%  (value not drawn)
Катушка индуктивности с керамическим сердечником и золотым покрытием контактных площадок; Номиналиная индуктивность: 2.4 нГн; Добротность, не менее: 18; Резонансная частота, не менее: 10.40 ГГц; Сопротивление обмотки постоянноми току, не более: 0.120 Ом; Допустимый ток обмотки: 640 мА; Изготовитель: АО "НПО "ЭРКОН"; Диапазон рабочих температур: от -60 до +125 ℃; Технология монтажа: SMT; Типоразмер: 1005 (0402); Упаковка: Катушка и лента
footprint КИК-1005_Зл (Катушка индуктивности с керамическим сердечником типоразмер 1005(0402))
pins: 1, 2

## КИК-1005-2.7 нГн ±20% Зл
designator L?, comment 2.7 нГн ±20%  (value not drawn)
Катушка индуктивности с керамическим сердечником и золотым покрытием контактных площадок; Номиналиная индуктивность: 2.4 нГн; Добротность, не менее: 18; Резонансная частота, не менее: 10.40 ГГц; Сопротивление обмотки постоянноми току, не более: 0.120 Ом; Допустимый ток обмотки: 640 мА; Изготовитель: АО "НПО "ЭРКОН"; Диапазон рабочих температур: от -60 до +125 ℃; Технология монтажа: SMT; Типоразмер: 1005 (0402); Упаковка: Катушка и лента
footprint КИК-1005_Зл (Катушка индуктивности с керамическим сердечником типоразмер 1005(0402))
pins: 1, 2

## КИК-1005-3.3 нГн ±2% Зл
designator L?, comment 3.3 нГн ±2%  (value not drawn)
Катушка индуктивности с керамическим сердечником и золотым покрытием контактных площадок; Номиналиная индуктивность: 3.3нГн; Добротность, не менее: 20; Резонансная частота, не менее: 7.00 ГГц; Сопротивление обмотки постоянноми току, не более: 0.066 Ом; Допустимый ток обмотки: 840 мА; Изготовитель: АО "НПО "ЭРКОН"; Диапазон рабочих температур: от -60 до +125 ℃; Технология монтажа: SMT; Типоразмер: 1005 (0402); Упаковка: Катушка и лента
footprint КИК-1005_Зл (Катушка индуктивности с керамическим сердечником типоразмер 1005(0402))
pins: 1, 2

## КИК-1005-3.3 нГн ±5% Зл
designator L?, comment 3.3 нГн ±5%  (value not drawn)
Катушка индуктивности с керамическим сердечником и золотым покрытием контактных площадок; Номиналиная индуктивность: 3.3нГн; Добротность, не менее: 20; Резонансная частота, не менее: 7.00 ГГц; Сопротивление обмотки постоянноми току, не более: 0.066 Ом; Допустимый ток обмотки: 840 мА; Изготовитель: АО "НПО "ЭРКОН"; Диапазон рабочих температур: от -60 до +125 ℃; Технология монтажа: SMT; Типоразмер: 1005 (0402); Упаковка: Катушка и лента
footprint КИК-1005_Зл (Катушка индуктивности с керамическим сердечником типоразмер 1005(0402))
pins: 1, 2

## КИК-1005-3.3 нГн ±10% Зл
designator L?, comment 3.3 нГн ±10%  (value not drawn)
Катушка индуктивности с керамическим сердечником и золотым покрытием контактных площадок; Номиналиная индуктивность: 3.3нГн; Добротность, не менее: 20; Резонансная частота, не менее: 7.00 ГГц; Сопротивление обмотки постоянноми току, не более: 0.066 Ом; Допустимый ток обмотки: 840 мА; Изготовитель: АО "НПО "ЭРКОН"; Диапазон рабочих температур: от -60 до +125 ℃; Технология монтажа: SMT; Типоразмер: 1005 (0402); Упаковка: Катушка и лента
footprint КИК-1005_Зл (Катушка индуктивности с керамическим сердечником типоразмер 1005(0402))
pins: 1, 2

## КИК-1005-3.3 нГн ±20% Зл
designator L?, comment 3.3 нГн ±20%  (value not drawn)
Катушка индуктивности с керамическим сердечником и золотым покрытием контактных площадок; Номиналиная индуктивность: 3.3нГн; Добротность, не менее: 20; Резонансная частота, не менее: 7.00 ГГц; Сопротивление обмотки постоянноми току, не более: 0.066 Ом; Допустимый ток обмотки: 840 мА; Изготовитель: АО "НПО "ЭРКОН"; Диапазон рабочих температур: от -60 до +125 ℃; Технология монтажа: SMT; Типоразмер: 1005 (0402); Упаковка: Катушка и лента
footprint КИК-1005_Зл (Катушка индуктивности с керамическим сердечником типоразмер 1005(0402))
pins: 1, 2

## КИК-1005-3.6 нГн ±2% Зл
designator L?, comment 3.6 нГн ±2%  (value not drawn)
Катушка индуктивности с керамическим сердечником и золотым покрытием контактных площадок; Номиналиная индуктивность: 3.6нГн; Добротность, не менее: 20; Резонансная частота, не менее: 6.80 ГГц; Сопротивление обмотки постоянноми току, не более: 0.066 Ом; Допустимый ток обмотки: 840 мА; Изготовитель: АО "НПО "ЭРКОН"; Диапазон рабочих температур: от -60 до +125 ℃; Технология монтажа: SMT; Типоразмер: 1005 (0402); Упаковка: Катушка и лента
footprint КИК-1005_Зл (Катушка индуктивности с керамическим сердечником типоразмер 1005(0402))
pins: 1, 2

## КИК-1005-3.6 нГн ±5% Зл
designator L?, comment 3.6 нГн ±5%  (value not drawn)
Катушка индуктивности с керамическим сердечником и золотым покрытием контактных площадок; Номиналиная индуктивность: 3.6нГн; Добротность, не менее: 20; Резонансная частота, не менее: 6.80 ГГц; Сопротивление обмотки постоянноми току, не более: 0.066 Ом; Допустимый ток обмотки: 840 мА; Изготовитель: АО "НПО "ЭРКОН"; Диапазон рабочих температур: от -60 до +125 ℃; Технология монтажа: SMT; Типоразмер: 1005 (0402); Упаковка: Катушка и лента
footprint КИК-1005_Зл (Катушка индуктивности с керамическим сердечником типоразмер 1005(0402))
pins: 1, 2

## КИК-1005-3.6 нГн ±10% Зл
designator L?, comment 3.6 нГн ±10%  (value not drawn)
Катушка индуктивности с керамическим сердечником и золотым покрытием контактных площадок; Номиналиная индуктивность: 3.6нГн; Добротность, не менее: 20; Резонансная частота, не менее: 6.80 ГГц; Сопротивление обмотки постоянноми току, не более: 0.066 Ом; Допустимый ток обмотки: 840 мА; Изготовитель: АО "НПО "ЭРКОН"; Диапазон рабочих температур: от -60 до +125 ℃; Технология монтажа: SMT; Типоразмер: 1005 (0402); Упаковка: Катушка и лента
footprint КИК-1005_Зл (Катушка индуктивности с керамическим сердечником типоразмер 1005(0402))
pins: 1, 2

## КИК-1005-3.6 нГн ±20% Зл
designator L?, comment 3.6 нГн ±20%  (value not drawn)
Катушка индуктивности с керамическим сердечником и золотым покрытием контактных площадок; Номиналиная индуктивность: 3.6нГн; Добротность, не менее: 20; Резонансная частота, не менее: 6.80 ГГц; Сопротивление обмотки постоянноми току, не более: 0.066 Ом; Допустимый ток обмотки: 840 мА; Изготовитель: АО "НПО "ЭРКОН"; Диапазон рабочих температур: от -60 до +125 ℃; Технология монтажа: SMT; Типоразмер: 1005 (0402); Упаковка: Катушка и лента
footprint КИК-1005_Зл (Катушка индуктивности с керамическим сердечником типоразмер 1005(0402))
pins: 1, 2

## КИК-1005-3.9 нГн ±2% Зл
designator L?, comment 3.9 нГн ±2%  (value not drawn)
Катушка индуктивности с керамическим сердечником и золотым покрытием контактных площадок; Номиналиная индуктивность: 3.9нГн; Добротность, не менее: 20; Резонансная частота, не менее: 6.00 ГГц; Сопротивление обмотки постоянноми току, не более: 0.066 Ом; Допустимый ток обмотки: 840 мА; Изготовитель: АО "НПО "ЭРКОН"; Диапазон рабочих температур: от -60 до +125 ℃; Технология монтажа: SMT; Типоразмер: 1005 (0402); Упаковка: Катушка и лента
footprint КИК-1005_Зл (Катушка индуктивности с керамическим сердечником типоразмер 1005(0402))
pins: 1, 2

## КИК-1005-3.9 нГн ±5% Зл
designator L?, comment 3.9 нГн ±5%  (value not drawn)
Катушка индуктивности с керамическим сердечником и золотым покрытием контактных площадок; Номиналиная индуктивность: 3.9нГн; Добротность, не менее: 20; Резонансная частота, не менее: 6.00 ГГц; Сопротивление обмотки постоянноми току, не более: 0.066 Ом; Допустимый ток обмотки: 840 мА; Изготовитель: АО "НПО "ЭРКОН"; Диапазон рабочих температур: от -60 до +125 ℃; Технология монтажа: SMT; Типоразмер: 1005 (0402); Упаковка: Катушка и лента
footprint КИК-1005_Зл (Катушка индуктивности с керамическим сердечником типоразмер 1005(0402))
pins: 1, 2

## КИК-1005-3.9 нГн ±10% Зл
designator L?, comment 3.9 нГн ±10%  (value not drawn)
Катушка индуктивности с керамическим сердечником и золотым покрытием контактных площадок; Номиналиная индуктивность: 3.9нГн; Добротность, не менее: 20; Резонансная частота, не менее: 6.00 ГГц; Сопротивление обмотки постоянноми току, не более: 0.066 Ом; Допустимый ток обмотки: 840 мА; Изготовитель: АО "НПО "ЭРКОН"; Диапазон рабочих температур: от -60 до +125 ℃; Технология монтажа: SMT; Типоразмер: 1005 (0402); Упаковка: Катушка и лента
footprint КИК-1005_Зл (Катушка индуктивности с керамическим сердечником типоразмер 1005(0402))
pins: 1, 2


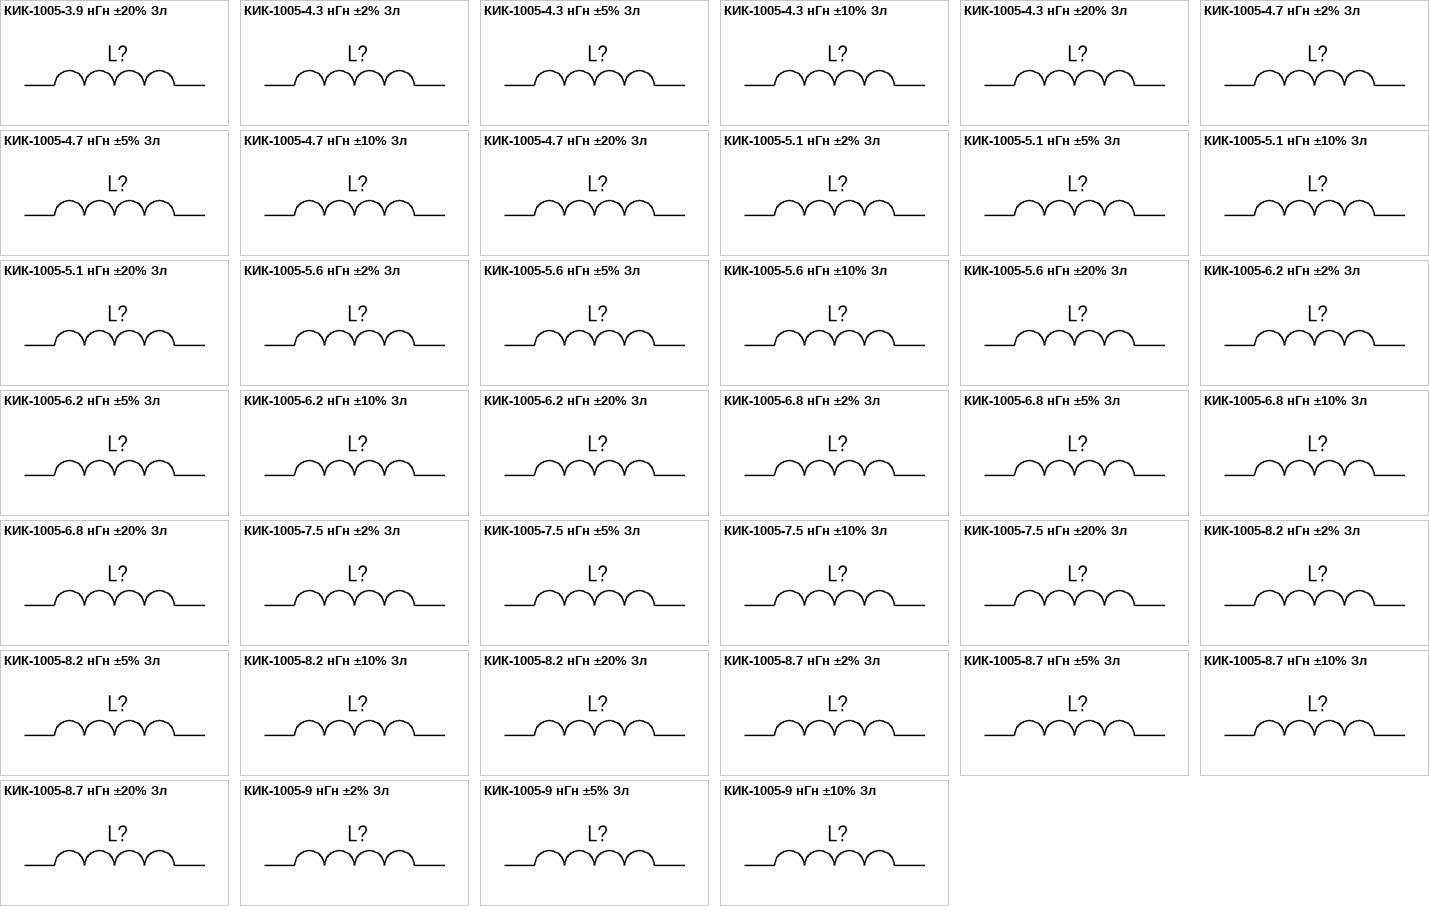
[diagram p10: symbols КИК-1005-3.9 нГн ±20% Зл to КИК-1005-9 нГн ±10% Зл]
## КИК-1005-3.9 нГн ±20% Зл
designator L?, comment 3.9 нГн ±20%  (value not drawn)
Катушка индуктивности с керамическим сердечником и золотым покрытием контактных площадок; Номиналиная индуктивность: 3.9нГн; Добротность, не менее: 20; Резонансная частота, не менее: 6.00 ГГц; Сопротивление обмотки постоянноми току, не более: 0.066 Ом; Допустимый ток обмотки: 840 мА; Изготовитель: АО "НПО "ЭРКОН"; Диапазон рабочих температур: от -60 до +125 ℃; Технология монтажа: SMT; Типоразмер: 1005 (0402); Упаковка: Катушка и лента
footprint КИК-1005_Зл (Катушка индуктивности с керамическим сердечником типоразмер 1005(0402))
pins: 1, 2

## КИК-1005-4.3 нГн ±2% Зл
designator L?, comment 4.3 нГн ±2%  (value not drawn)
Катушка индуктивности с керамическим сердечником и золотым покрытием контактных площадок; Номиналиная индуктивность: 4.3 нГн; Добротность, не менее: 20; Резонансная частота, не менее: 6.00 ГГц; Сопротивление обмотки постоянноми току, не более: 0.091 Ом; Допустимый ток обмотки: 700 мА; Изготовитель: АО "НПО "ЭРКОН"; Диапазон рабочих температур: SMT; Типоразмер: 1005 (0402); Упаковка: Катушка и лента
footprint КИК-1005_Зл (Катушка индуктивности с керамическим сердечником типоразмер 1005(0402))
pins: 1, 2

## КИК-1005-4.3 нГн ±5% Зл
designator L?, comment 4.3 нГн ±5%  (value not drawn)
Катушка индуктивности с керамическим сердечником и золотым покрытием контактных площадок; Номиналиная индуктивность: 4.3 нГн; Добротность, не менее: 20; Резонансная частота, не менее: 6.00 ГГц; Сопротивление обмотки постоянноми току, не более: 0.091 Ом; Допустимый ток обмотки: 700 мА; Изготовитель: АО "НПО "ЭРКОН"; Диапазон рабочих температур: SMT; Типоразмер: 1005 (0402); Упаковка: Катушка и лента
footprint КИК-1005_Зл (Катушка индуктивности с керамическим сердечником типоразмер 1005(0402))
pins: 1, 2

## КИК-1005-4.3 нГн ±10% Зл
designator L?, comment 4.3 нГн ±10%  (value not drawn)
Катушка индуктивности с керамическим сердечником и золотым покрытием контактных площадок; Номиналиная индуктивность: 4.3нГн; Добротность, не менее: 20; Резонансная частота, не менее: 6.00 ГГц; Сопротивление обмотки постоянноми току, не более: 0.091 Ом; Допустимый ток обмотки: 700 мА; Изготовитель: АО "НПО "ЭРКОН"; Диапазон рабочих температур: от -60 до +125 ℃; Технология монтажа: SMT; Типоразмер: 1005 (0402); Упаковка: Катушка и лента
footprint КИК-1005_Зл (Катушка индуктивности с керамическим сердечником типоразмер 1005(0402))
pins: 1, 2

## КИК-1005-4.3 нГн ±20% Зл
designator L?, comment 4.3 нГн ±20%  (value not drawn)
Катушка индуктивности с керамическим сердечником и золотым покрытием контактных площадок; Номиналиная индуктивность: 4.3нГн; Добротность, не менее: 20; Резонансная частота, не менее: 6.00 ГГц; Сопротивление обмотки постоянноми току, не более: 0.091 Ом; Допустимый ток обмотки: 700 мА; Изготовитель: АО "НПО "ЭРКОН"; Диапазон рабочих температур: от -60 до +125 ℃; Технология монтажа: SMT; Типоразмер: 1005 (0402); Упаковка: Катушка и лента
footprint КИК-1005_Зл (Катушка индуктивности с керамическим сердечником типоразмер 1005(0402))
pins: 1, 2

## КИК-1005-4.7 нГн ±2% Зл
designator L?, comment 4.7 нГн ±2%  (value not drawn)
Катушка индуктивности с керамическим сердечником и золотым покрытием контактных площадок; Номиналиная индуктивность: 4.7 нГн; Добротность, не менее: 18; Резонансная частота, не менее: 4.77 ГГц; Сопротивление обмотки постоянноми току, не более: 0.130 Ом; Допустимый ток обмотки: 640 мА; Изготовитель: АО "НПО "ЭРКОН"; Диапазон рабочих температур: от -60 до +125 ℃; Технология монтажа: SMT; Типоразмер: 1005 (0402); Упаковка: Катушка и лента
footprint КИК-1005_Зл (Катушка индуктивности с керамическим сердечником типоразмер 1005(0402))
pins: 1, 2

## КИК-1005-4.7 нГн ±5% Зл
designator L?, comment 4.7 нГн ±5%  (value not drawn)
Катушка индуктивности с керамическим сердечником и золотым покрытием контактных площадок; Номиналиная индуктивность: 4.7 нГн; Добротность, не менее: 18; Резонансная частота, не менее: 4.77 ГГц; Сопротивление обмотки постоянноми току, не более: 0.130 Ом; Допустимый ток обмотки: 640 мА; Изготовитель: АО "НПО "ЭРКОН"; Диапазон рабочих температур: от -60 до +125 ℃; Технология монтажа: SMT; Типоразмер: 1005 (0402); Упаковка: Катушка и лента
footprint КИК-1005_Зл (Катушка индуктивности с керамическим сердечником типоразмер 1005(0402))
pins: 1, 2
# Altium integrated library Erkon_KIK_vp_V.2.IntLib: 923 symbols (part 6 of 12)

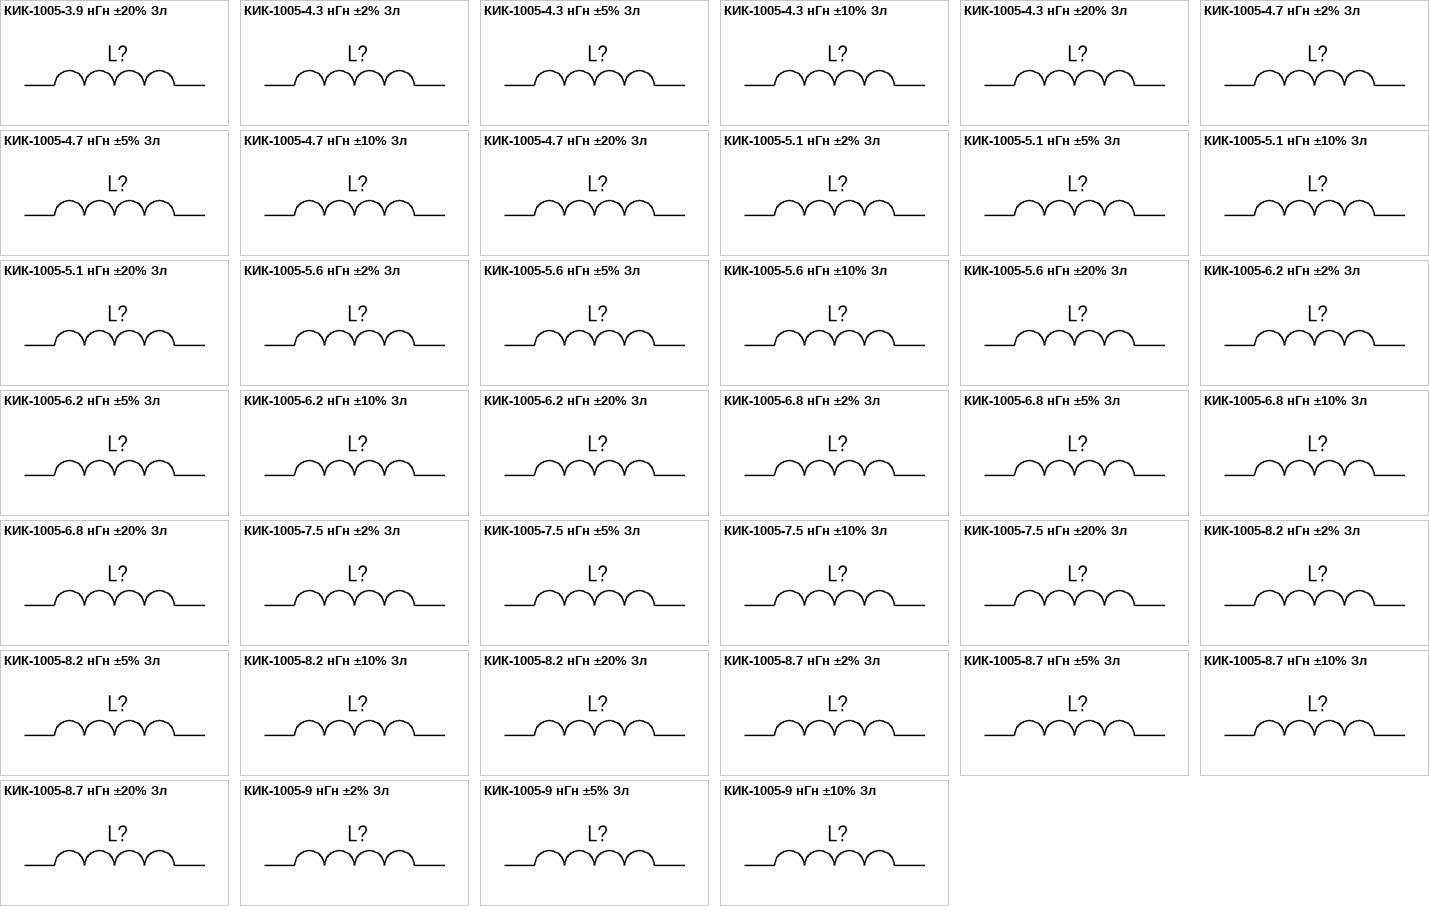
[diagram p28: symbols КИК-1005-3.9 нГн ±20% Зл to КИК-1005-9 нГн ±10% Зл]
## КИК-1005-4.7 нГн ±10% Зл
designator L?, comment 4.7 нГн ±10%  (value not drawn)
Катушка индуктивности с керамическим сердечником и золотым покрытием контактных площадок; Номиналиная индуктивность: 4.7 нГн; Добротность, не менее: 18; Резонансная частота, не менее: 4.77 ГГц; Сопротивление обмотки постоянноми току, не более: 0.130 Ом; Допустимый ток обмотки: 640 мА; Изготовитель: АО "НПО "ЭРКОН"; Диапазон рабочих температур: от -60 до +125 ℃; Технология монтажа: SMT; Типоразмер: 1005 (0402); Упаковка: Катушка и лента
footprint КИК-1005_Зл (Катушка индуктивности с керамическим сердечником типоразмер 1005(0402))
pins: 1, 2

## КИК-1005-4.7 нГн ±20% Зл
designator L?, comment 4.7 нГн ±20%  (value not drawn)
Катушка индуктивности с керамическим сердечником и золотым покрытием контактных площадок; Номиналиная индуктивность: 4.7 нГн; Добротность, не менее: 18; Резонансная частота, не менее: 4.77 ГГц; Сопротивление обмотки постоянноми току, не более: 0.130 Ом; Допустимый ток обмотки: 640 мА; Изготовитель: АО "НПО "ЭРКОН"; Диапазон рабочих температур: от -60 до +125 ℃; Технология монтажа: SMT; Типоразмер: 1005 (0402); Упаковка: Катушка и лента
footprint КИК-1005_Зл (Катушка индуктивности с керамическим сердечником типоразмер 1005(0402))
pins: 1, 2

## КИК-1005-5.1 нГн ±2% Зл
designator L?, comment 5.1нГн ±2%  (value not drawn)
Катушка индуктивности с керамическим сердечником и золотым покрытием контактных площадок; Добротность, не менее: 20; Резонансная частота, не менее: 4.80 ГГц; Сопротивление обмотки постоянноми току, не более: 0.083 Ом; Допустимый ток обмотки: 800 мА; Изготовитель: АО "НПО "ЭРКОН"; Диапазон рабочих температур: от -60 до +125 ℃; Технология монтажа: SMT; Типоразмер: 1005 (0402); Упаковка: Катушка и лента
footprint КИК-1005_Зл (Катушка индуктивности с керамическим сердечником типоразмер 1005(0402))
pins: 1, 2

## КИК-1005-5.1 нГн ±5% Зл
designator L?, comment 5.1нГн ±5%  (value not drawn)
Катушка индуктивности с керамическим сердечником и золотым покрытием контактных площадок; Добротность, не менее: 20; Резонансная частота, не менее: 4.80 ГГц; Сопротивление обмотки постоянноми току, не более: 0.083 Ом; Допустимый ток обмотки: 800 мА; Изготовитель: АО "НПО "ЭРКОН"; Диапазон рабочих температур: от -60 до +125 ℃; Технология монтажа: SMT; Типоразмер: 1005 (0402); Упаковка: Катушка и лента
footprint КИК-1005_Зл (Катушка индуктивности с керамическим сердечником типоразмер 1005(0402))
pins: 1, 2

## КИК-1005-5.1 нГн ±10% Зл
designator L?, comment 5.1нГн ±10%  (value not drawn)
Катушка индуктивности с керамическим сердечником и золотым покрытием контактных площадок; Добротность, не менее: 20; Резонансная частота, не менее: 4.80 ГГц; Сопротивление обмотки постоянноми току, не более: 0.083 Ом; Допустимый ток обмотки: 800 мА; Изготовитель: АО "НПО "ЭРКОН"; Диапазон рабочих температур: от -60 до +125 ℃; Технология монтажа: SMT; Типоразмер: 1005 (0402); Упаковка: Катушка и лента
footprint КИК-1005_Зл (Катушка индуктивности с керамическим сердечником типоразмер 1005(0402))
pins: 1, 2

## КИК-1005-5.1 нГн ±20% Зл
designator L?, comment 5.1нГн ±20%  (value not drawn)
Катушка индуктивности с керамическим сердечником и золотым покрытием контактных площадок; Добротность, не менее: 20; Резонансная частота, не менее: 4.80 ГГц; Сопротивление обмотки постоянноми току, не более: 0.083 Ом; Допустимый ток обмотки: 800 мА; Изготовитель: АО "НПО "ЭРКОН"; Диапазон рабочих температур: от -60 до +125 ℃; Технология монтажа: SMT; Типоразмер: 1005 (0402); Упаковка: Катушка и лента
footprint КИК-1005_Зл (Катушка индуктивности с керамическим сердечником типоразмер 1005(0402))
pins: 1, 2

## КИК-1005-5.6 нГн ±2% Зл
designator L?, comment 5.6нГн ±2%  (value not drawn)
Катушка индуктивности с керамическим сердечником и золотым покрытием контактных площадок; Добротность, не менее: 20; Резонансная частота, не менее: 4.80 ГГц; Сопротивление обмотки постоянноми току, не более: 0.083 Ом; Допустимый ток обмотки: 760 мА; Изготовитель: АО "НПО "ЭРКОН"; Диапазон рабочих температур: от -60 до +125 ℃; Технология монтажа: SMT; Типоразмер: 1005 (0402); Упаковка: Катушка и лента
footprint КИК-1005_Зл (Катушка индуктивности с керамическим сердечником типоразмер 1005(0402))
pins: 1, 2

## КИК-1005-5.6 нГн ±5% Зл
designator L?, comment 5.6нГн ±5%  (value not drawn)
Катушка индуктивности с керамическим сердечником и золотым покрытием контактных площадок; Добротность, не менее: 20; Резонансная частота, не менее: 4.80 ГГц; Сопротивление обмотки постоянноми току, не более: 0.083 Ом; Допустимый ток обмотки: 760 мА; Изготовитель: АО "НПО "ЭРКОН"; Диапазон рабочих температур: от -60 до +125 ℃; Технология монтажа: SMT; Типоразмер: 1005 (0402); Упаковка: Катушка и лента
footprint КИК-1005_Зл (Катушка индуктивности с керамическим сердечником типоразмер 1005(0402))
pins: 1, 2

## КИК-1005-5.6 нГн ±10% Зл
designator L?, comment 5.6 нГн ±10%  (value not drawn)
Катушка индуктивности с керамическим сердечником и золотым покрытием контактных площадок; Номиналиная индуктивность: 5.6нГн; Добротность, не менее: 20; Резонансная частота, не менее: 4.80 ГГц; Сопротивление обмотки постоянноми току, не более: 0.083 Ом; Допустимый ток обмотки: 760 мА; Изготовитель: АО "НПО "ЭРКОН"; Диапазон рабочих температур: от -60 до +125 ℃; Технология монтажа: SMT; Типоразмер: 1005 (0402); Упаковка: Катушка и лента
footprint КИК-1005_Зл (Катушка индуктивности с керамическим сердечником типоразмер 1005(0402))
pins: 1, 2

## КИК-1005-5.6 нГн ±20% Зл
designator L?, comment 5.6 нГн ±20%  (value not drawn)
Катушка индуктивности с керамическим сердечником и золотым покрытием контактных площадок; Номиналиная индуктивность: 5.6нГн; Добротность, не менее: 20; Резонансная частота, не менее: 4.80 ГГц; Сопротивление обмотки постоянноми току, не более: 0.083 Ом; Допустимый ток обмотки: 760 мА; Изготовитель: АО "НПО "ЭРКОН"; Диапазон рабочих температур: от -60 до +125 ℃; Технология монтажа: SMT; Типоразмер: 1005 (0402); Упаковка: Катушка и лента
footprint КИК-1005_Зл (Катушка индуктивности с керамическим сердечником типоразмер 1005(0402))
pins: 1, 2

## КИК-1005-6.2 нГн ±2% Зл
designator L?, comment 6.2 нГн ±2%  (value not drawn)
Катушка индуктивности с керамическим сердечником и золотым покрытием контактных площадок; Номиналиная индуктивность: 5.6нГн; Допускаемое отклонение индуктивности: ±5%; Добротность, не менее: 20; Резонансная частота, не менее: 4.80 ГГц; Сопротивление обмотки постоянноми току, не более: 0.083 Ом; Допустимый ток обмотки: 760 мА; Изготовитель: АО "НПО "ЭРКОН"; Диапазон рабочих температур: от -60 до +125 ℃; Технология монтажа: SMT; Типоразмер: 1005 (0402); Упаковка: Катушка и лента
footprint КИК-1005_Зл (Катушка индуктивности с керамическим сердечником типоразмер 1005(0402))
pins: 1, 2

## КИК-1005-6.2 нГн ±5% Зл
designator L?, comment 6.2 нГн ±5%  (value not drawn)
Катушка индуктивности с керамическим сердечником и золотым покрытием контактных площадок; Номиналиная индуктивность: 5.6нГн; Добротность, не менее: 20; Резонансная частота, не менее: 4.80 ГГц; Сопротивление обмотки постоянноми току, не более: 0.083 Ом; Допустимый ток обмотки: 760 мА; Изготовитель: АО "НПО "ЭРКОН"; Диапазон рабочих температур: от -60 до +125 ℃; Технология монтажа: SMT; Типоразмер: 1005 (0402); Упаковка: Катушка и лента
footprint КИК-1005_Зл (Катушка индуктивности с керамическим сердечником типоразмер 1005(0402))
pins: 1, 2

## КИК-1005-6.2 нГн ±10% Зл
designator L?, comment 6.2 нГн ±10%  (value not drawn)
Катушка индуктивности с керамическим сердечником и золотым покрытием контактных площадок; Номиналиная индуктивность: 5.6нГн; Добротность, не менее: 20; Резонансная частота, не менее: 4.80 ГГц; Сопротивление обмотки постоянноми току, не более: 0.083 Ом; Допустимый ток обмотки: 760 мА; Изготовитель: АО "НПО "ЭРКОН"; Диапазон рабочих температур: от -60 до +125 ℃; Технология монтажа: SMT; Типоразмер: 1005 (0402); Упаковка: Катушка и лента
footprint КИК-1005_Зл (Катушка индуктивности с керамическим сердечником типоразмер 1005(0402))
pins: 1, 2

## КИК-1005-6.2 нГн ±20% Зл
designator L?, comment 6.2 нГн ±20%  (value not drawn)
Катушка индуктивности с керамическим сердечником и золотым покрытием контактных площадок; Номиналиная индуктивность: 5.6нГн; Добротность, не менее: 20; Резонансная частота, не менее: 4.80 ГГц; Сопротивление обмотки постоянноми току, не более: 0.083 Ом; Допустимый ток обмотки: 760 мА; Изготовитель: АО "НПО "ЭРКОН"; Диапазон рабочих температур: от -60 до +125 ℃; Технология монтажа: SMT; Типоразмер: 1005 (0402); Упаковка: Катушка и лента
footprint КИК-1005_Зл (Катушка индуктивности с керамическим сердечником типоразмер 1005(0402))
pins: 1, 2

## КИК-1005-6.8 нГн ±2% Зл
designator L?, comment 6.8 нГн ±2%  (value not drawn)
Катушка индуктивности с керамическим сердечником и золотым покрытием контактных площадок; Номиналиная индуктивность: 5.6нГн; Допускаемое отклонение индуктивности: ±5%; Добротность, не менее: 20; Резонансная частота, не менее: 4.80 ГГц; Сопротивление обмотки постоянноми току, не более: 0.083 Ом; Допустимый ток обмотки: 680 мА; Изготовитель: АО "НПО "ЭРКОН"; Диапазон рабочих температур: от -60 до +125 ℃; Технология монтажа: SMT; Типоразмер: 1005 (0402); Упаковка: Катушка и лента
footprint КИК-1005_Зл (Катушка индуктивности с керамическим сердечником типоразмер 1005(0402))
pins: 1, 2

## КИК-1005-6.8 нГн ±5% Зл
designator L?, comment 6.8 нГн ±5%  (value not drawn)
Катушка индуктивности с керамическим сердечником и золотым покрытием контактных площадок; Номиналиная индуктивность: 5.6нГн; Добротность, не менее: 20; Резонансная частота, не менее: 4.80 ГГц; Сопротивление обмотки постоянноми току, не более: 0.083 Ом; Допустимый ток обмотки: 680 мА; Изготовитель: АО "НПО "ЭРКОН"; Диапазон рабочих температур: от -60 до +125 ℃; Технология монтажа: SMT; Типоразмер: 1005 (0402); Упаковка: Катушка и лента
footprint КИК-1005_Зл (Катушка индуктивности с керамическим сердечником типоразмер 1005(0402))
pins: 1, 2

## КИК-1005-6.8 нГн ±10% Зл
designator L?, comment 10 нГн ±10%  (value not drawn)
Катушка индуктивности с керамическим сердечником и золотым покрытием контактных площадок; Номиналиная индуктивность: 5.6нГн; Добротность, не менее: 20; Резонансная частота, не менее: 4.80 ГГц; Сопротивление обмотки постоянноми току, не более: 0.083 Ом; Допустимый ток обмотки: 680 мА; Изготовитель: АО "НПО "ЭРКОН"; Диапазон рабочих температур: от -60 до +125 ℃; Технология монтажа: SMT; Типоразмер: 1005 (0402); Упаковка: Катушка и лента
footprint КИК-1005_Зл (Катушка индуктивности с керамическим сердечником типоразмер 1005(0402))
pins: 1, 2

## КИК-1005-6.8 нГн ±20% Зл
designator L?, comment 10 нГн ±20%  (value not drawn)
Катушка индуктивности с керамическим сердечником и золотым покрытием контактных площадок; Номиналиная индуктивность: 5.6нГн; Добротность, не менее: 20; Резонансная частота, не менее: 4.80 ГГц; Сопротивление обмотки постоянноми току, не более: 0.083 Ом; Допустимый ток обмотки: 680 мА; Изготовитель: АО "НПО "ЭРКОН"; Диапазон рабочих температур: от -60 до +125 ℃; Технология монтажа: SMT; Типоразмер: 1005 (0402); Упаковка: Катушка и лента
footprint КИК-1005_Зл (Катушка индуктивности с керамическим сердечником типоразмер 1005(0402))
pins: 1, 2

## КИК-1005-7.5 нГн ±2% Зл
designator L?, comment 7.5 нГн ±2%  (value not drawn)
Катушка индуктивности с керамическим сердечником и золотым покрытием контактных площадок; Номиналиная индуктивность: 7.5нГн; Добротность, не менее: 20; Резонансная частота, не менее: 4.80 ГГц; Сопротивление обмотки постоянноми току, не более: 0.10 Ом; Допустимый ток обмотки: 680 мА; Изготовитель: АО "НПО "ЭРКОН"; Диапазон рабочих температур: от -60 до +125 ℃; Технология монтажа: SMT; Типоразмер: 1005 (0402); Упаковка: Катушка и лента
footprint КИК-1005_Зл (Катушка индуктивности с керамическим сердечником типоразмер 1005(0402))
pins: 1, 2

## КИК-1005-7.5 нГн ±5% Зл
designator L?, comment 7.5 нГн ±5%  (value not drawn)
Катушка индуктивности с керамическим сердечником и золотым покрытием контактных площадок; Номиналиная индуктивность: 7.5нГн; Добротность, не менее: 20; Резонансная частота, не менее: 4.80 ГГц; Сопротивление обмотки постоянноми току, не более: 0.10 Ом; Допустимый ток обмотки: 680 мА; Изготовитель: АО "НПО "ЭРКОН"; Диапазон рабочих температур: от -60 до +125 ℃; Технология монтажа: SMT; Типоразмер: 1005 (0402); Упаковка: Катушка и лента
footprint КИК-1005_Зл (Катушка индуктивности с керамическим сердечником типоразмер 1005(0402))
pins: 1, 2

## КИК-1005-7.5 нГн ±10% Зл
designator L?, comment 7.5 нГн ±10%  (value not drawn)
Катушка индуктивности с керамическим сердечником и золотым покрытием контактных площадок; Номиналиная индуктивность: 7.5нГн; Добротность, не менее: 20; Резонансная частота, не менее: 4.80 ГГц; Сопротивление обмотки постоянноми току, не более: 0.10 Ом; Допустимый ток обмотки: 680 мА; Изготовитель: АО "НПО "ЭРКОН"; Диапазон рабочих температур: от -60 до +125 ℃; Технология монтажа: SMT; Типоразмер: 1005 (0402); Упаковка: Катушка и лента
footprint КИК-1005_Зл (Катушка индуктивности с керамическим сердечником типоразмер 1005(0402))
pins: 1, 2

## КИК-1005-7.5 нГн ±20% Зл
designator L?, comment 7.5 нГн ±20%  (value not drawn)
Катушка индуктивности с керамическим сердечником и золотым покрытием контактных площадок; Номиналиная индуктивность: 7.5нГн; Добротность, не менее: 20; Резонансная частота, не менее: 4.80 ГГц; Сопротивление обмотки постоянноми току, не более: 0.10 Ом; Допустимый ток обмотки: 680 мА; Изготовитель: АО "НПО "ЭРКОН"; Диапазон рабочих температур: от -60 до +125 ℃; Технология монтажа: SMT; Типоразмер: 1005 (0402); Упаковка: Катушка и лента
footprint КИК-1005_Зл (Катушка индуктивности с керамическим сердечником типоразмер 1005(0402))
pins: 1, 2

## КИК-1005-8.2 нГн ±2% Зл
designator L?, comment 8.2 нГн ±2%  (value not drawn)
Катушка индуктивности с керамическим сердечником и золотым покрытием контактных площадок; Номиналиная индуктивность: 8.2 нГн; Добротность, не менее: 20; Резонансная частота, не менее: 4.40 ГГц; Сопротивление обмотки постоянноми току, не более: 0.10 Ом; Допустимый ток обмотки: 680 мА; Изготовитель: АО "НПО "ЭРКОН"; Диапазон рабочих температур: SMT; Типоразмер: 1005 (0402); Упаковка: Катушка и лента
footprint КИК-1005_Зл (Катушка индуктивности с керамическим сердечником типоразмер 1005(0402))
pins: 1, 2

## КИК-1005-8.2 нГн ±5% Зл
designator L?, comment 8.2 нГн ±5%  (value not drawn)
Катушка индуктивности с керамическим сердечником и золотым покрытием контактных площадок; Номиналиная индуктивность: 8.2 нГн; Добротность, не менее: 20; Резонансная частота, не менее: 4.40 ГГц; Сопротивление обмотки постоянноми току, не более: 0.10 Ом; Допустимый ток обмотки: 680 мА; Изготовитель: АО "НПО "ЭРКОН"; Диапазон рабочих температур: SMT; Типоразмер: 1005 (0402); Упаковка: Катушка и лента
footprint КИК-1005_Зл (Катушка индуктивности с керамическим сердечником типоразмер 1005(0402))
pins: 1, 2

## КИК-1005-8.2 нГн ±10% Зл
designator L?, comment 8.2 нГн ±10%  (value not drawn)
Катушка индуктивности с керамическим сердечником и золотым покрытием контактных площадок; Номиналиная индуктивность: 8.2 нГн; Добротность, не менее: 20; Резонансная частота, не менее: 4.40 ГГц; Сопротивление обмотки постоянноми току, не более: 0.10 Ом; Допустимый ток обмотки: 680 мА; Изготовитель: АО "НПО "ЭРКОН"; Диапазон рабочих температур: от -60 до +125 ℃; Технология монтажа: SMT; Типоразмер: 1005 (0402); Упаковка: Катушка и лента
footprint КИК-1005_Зл (Катушка индуктивности с керамическим сердечником типоразмер 1005(0402))
pins: 1, 2

## КИК-1005-8.2 нГн ±20% Зл
designator L?, comment 8.2 нГн ±20%  (value not drawn)
Катушка индуктивности с керамическим сердечником и золотым покрытием контактных площадок; Номиналиная индуктивность: 8.2 нГн; Добротность, не менее: 20; Резонансная частота, не менее: 4.40 ГГц; Сопротивление обмотки постоянноми току, не более: 0.10 Ом; Допустимый ток обмотки: 680 мА; Изготовитель: АО "НПО "ЭРКОН"; Диапазон рабочих температур: от -60 до +125 ℃; Технология монтажа: SMT; Типоразмер: 1005 (0402); Упаковка: Катушка и лента
footprint КИК-1005_Зл (Катушка индуктивности с керамическим сердечником типоразмер 1005(0402))
pins: 1, 2

## КИК-1005-8.7 нГн ±2% Зл
designator L?, comment 8.7 нГн ±2%  (value not drawn)
Катушка индуктивности с керамическим сердечником и золотым покрытием контактных площадок; Номиналиная индуктивность: 8.7 нГн; Добротность, не менее: 20; Резонансная частота, не менее: 4.10 ГГц; Сопротивление обмотки постоянноми току, не более: 0.20 Ом; Допустимый ток обмотки: 480 мА; Изготовитель: АО "НПО "ЭРКОН"; Диапазон рабочих температур: от -60 до +125 ℃; Технология монтажа: SMT; Типоразмер: 1005 (0402); Упаковка: Катушка и лента
footprint КИК-1005_Зл (Катушка индуктивности с керамическим сердечником типоразмер 1005(0402))
pins: 1, 2

## КИК-1005-8.7 нГн ±5% Зл
designator L?, comment 8.7 нГн ±5%  (value not drawn)
Катушка индуктивности с керамическим сердечником и золотым покрытием контактных площадок; Номиналиная индуктивность: 8.7 нГн; Добротность, не менее: 20; Резонансная частота, не менее: 4.10 ГГц; Сопротивление обмотки постоянноми току, не более: 0.20 Ом; Допустимый ток обмотки: 480 мА; Изготовитель: АО "НПО "ЭРКОН"; Диапазон рабочих температур: от -60 до +125 ℃; Технология монтажа: SMT; Типоразмер: 1005 (0402); Упаковка: Катушка и лента
footprint КИК-1005_Зл (Катушка индуктивности с керамическим сердечником типоразмер 1005(0402))
pins: 1, 2

## КИК-1005-8.7 нГн ±10% Зл
designator L?, comment 8.7 нГн ±10%  (value not drawn)
Катушка индуктивности с керамическим сердечником и золотым покрытием контактных площадок; Номиналиная индуктивность: 8.7 нГн; Добротность, не менее: 20; Резонансная частота, не менее: 4.10 ГГц; Сопротивление обмотки постоянноми току, не более: 0.20 Ом; Допустимый ток обмотки: 480 мА; Изготовитель: АО "НПО "ЭРКОН"; Диапазон рабочих температур: от -60 до +125 ℃; Технология монтажа: SMT; Типоразмер: 1005 (0402); Упаковка: Катушка и лента
footprint КИК-1005_Зл (Катушка индуктивности с керамическим сердечником типоразмер 1005(0402))
pins: 1, 2

## КИК-1005-8.7 нГн ±20% Зл
designator L?, comment 8.7 нГн ±20%  (value not drawn)
Катушка индуктивности с керамическим сердечником и золотым покрытием контактных площадок; Номиналиная индуктивность: 8.7 нГн; Добротность, не менее: 20; Резонансная частота, не менее: 4.10 ГГц; Сопротивление обмотки постоянноми току, не более: 0.20 Ом; Допустимый ток обмотки: 480 мА; Изготовитель: АО "НПО "ЭРКОН"; Диапазон рабочих температур: от -60 до +125 ℃; Технология монтажа: SMT; Типоразмер: 1005 (0402); Упаковка: Катушка и лента
footprint КИК-1005_Зл (Катушка индуктивности с керамическим сердечником типоразмер 1005(0402))
pins: 1, 2

## КИК-1005-9 нГн ±2% Зл
designator L?, comment 9 нГн ±2%  (value not drawn)
Катушка индуктивности с керамическим сердечником и золотым покрытием контактных площадок; Номиналиная индуктивность: 9.0нГн; Добротность, не менее: 20; Резонансная частота, не менее: 4.16 ГГц; Сопротивление обмотки постоянноми току, не более: 0.20 Ом; Допустимый ток обмотки: 680 мА; Изготовитель: АО "НПО "ЭРКОН"; Диапазон рабочих температур: от -60 до +125 ℃; Технология монтажа: SMT; Типоразмер: 1005 (0402); Упаковка: Катушка и лента
footprint КИК-1005_Зл (Катушка индуктивности с керамическим сердечником типоразмер 1005(0402))
pins: 1, 2

## КИК-1005-9 нГн ±5% Зл
designator L?, comment 9 нГн ±5%  (value not drawn)
Катушка индуктивности с керамическим сердечником и золотым покрытием контактных площадок; Номиналиная индуктивность: 9.0нГн; Добротность, не менее: 20; Резонансная частота, не менее: 4.16 ГГц; Сопротивление обмотки постоянноми току, не более: 0.20 Ом; Допустимый ток обмотки: 680 мА; Изготовитель: АО "НПО "ЭРКОН"; Диапазон рабочих температур: от -60 до +125 ℃; Технология монтажа: SMT; Типоразмер: 1005 (0402); Упаковка: Катушка и лента
footprint КИК-1005_Зл (Катушка индуктивности с керамическим сердечником типоразмер 1005(0402))
pins: 1, 2

## КИК-1005-9 нГн ±10% Зл
designator L?, comment 9 нГн ±10%  (value not drawn)
Катушка индуктивности с керамическим сердечником и золотым покрытием контактных площадок; Номиналиная индуктивность: 9.0нГн; Добротность, не менее: 20; Резонансная частота, не менее: 4.16 ГГц; Сопротивление обмотки постоянноми току, не более: 0.20 Ом; Допустимый ток обмотки: 680 мА; Изготовитель: АО "НПО "ЭРКОН"; Диапазон рабочих температур: от -60 до +125 ℃; Технология монтажа: SMT; Типоразмер: 1005 (0402); Упаковка: Катушка и лента
footprint КИК-1005_Зл (Катушка индуктивности с керамическим сердечником типоразмер 1005(0402))
pins: 1, 2


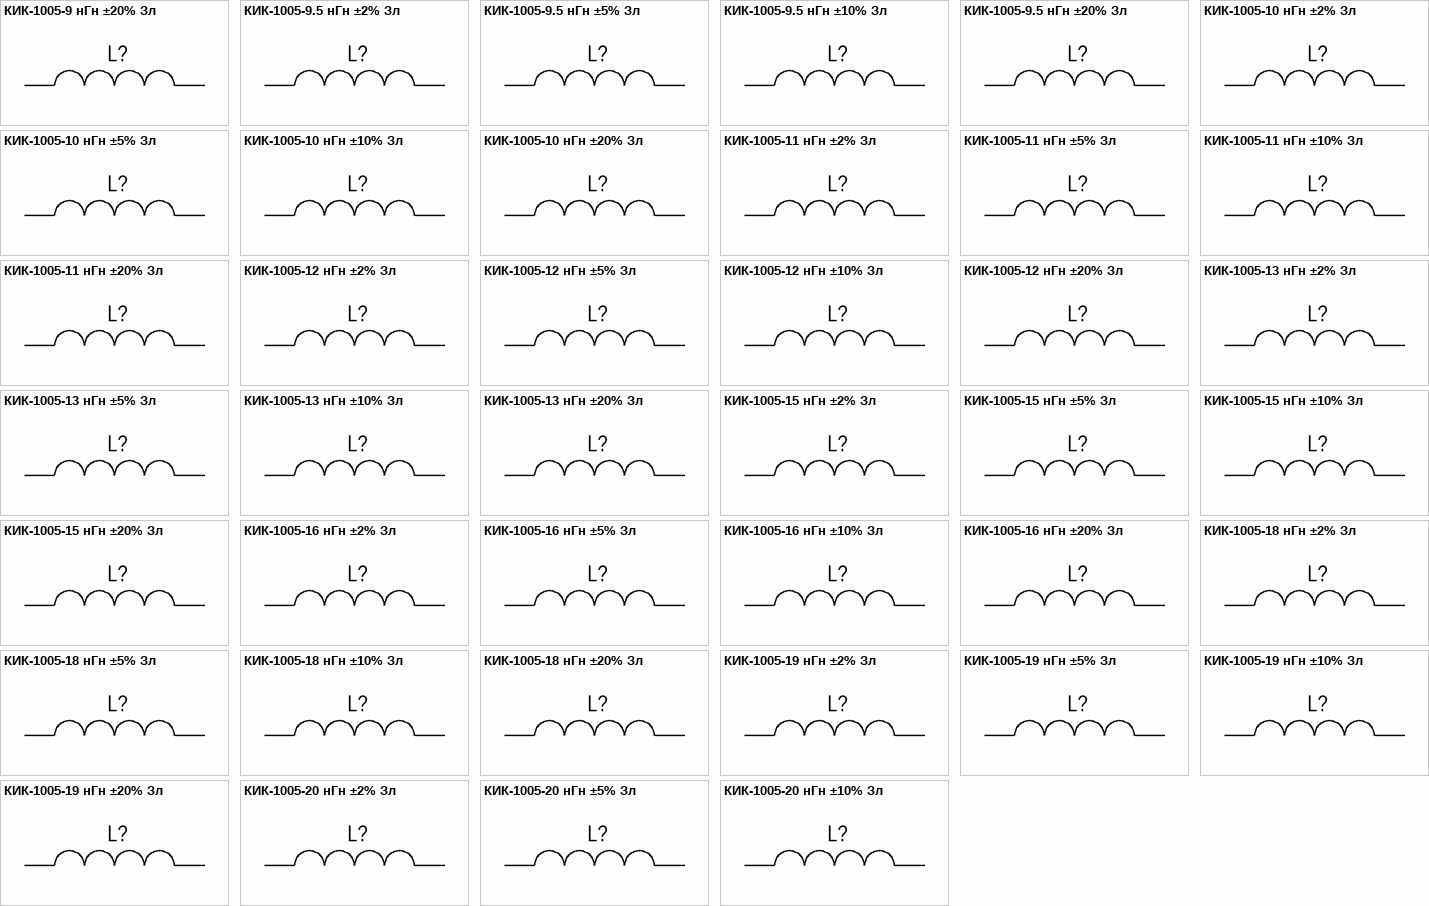
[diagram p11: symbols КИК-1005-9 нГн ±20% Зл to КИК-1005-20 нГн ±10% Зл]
## КИК-1005-9 нГн ±20% Зл
designator L?, comment 9 нГн ±20%  (value not drawn)
Катушка индуктивности с керамическим сердечником и золотым покрытием контактных площадок; Номиналиная индуктивность: 9.0нГн; Добротность, не менее: 20; Резонансная частота, не менее: 4.16 ГГц; Сопротивление обмотки постоянноми току, не более: 0.20 Ом; Допустимый ток обмотки: 680 мА; Изготовитель: АО "НПО "ЭРКОН"; Диапазон рабочих температур: от -60 до +125 ℃; Технология монтажа: SMT; Типоразмер: 1005 (0402); Упаковка: Катушка и лента
footprint КИК-1005_Зл (Катушка индуктивности с керамическим сердечником типоразмер 1005(0402))
pins: 1, 2

## КИК-1005-9.5 нГн ±2% Зл
designator L?, comment 9.5 нГн ±2%  (value not drawn)
Катушка индуктивности с керамическим сердечником и золотым покрытием контактных площадок; Номиналиная индуктивность: 9.5 нГн; Добротность, не менее: 20; Резонансная частота, не менее: 4.00 ГГц; Сопротивление обмотки постоянноми току, не более: 0.20 Ом; Допустимый ток обмотки: 480 мА; Изготовитель: АО "НПО "ЭРКОН"; Диапазон рабочих температур: от -60 до +125 ℃; Технология монтажа: SMT; Типоразмер: 1005 (0402); Упаковка: Катушка и лента
footprint КИК-1005_Зл (Катушка индуктивности с керамическим сердечником типоразмер 1005(0402))
pins: 1, 2

## КИК-1005-9.5 нГн ±5% Зл
designator L?, comment 9.5 нГн ±5%  (value not drawn)
Катушка индуктивности с керамическим сердечником и золотым покрытием контактных площадок; Номиналиная индуктивность: 9.5 нГн; Добротность, не менее: 20; Резонансная частота, не менее: 4.00 ГГц; Сопротивление обмотки постоянноми току, не более: 0.20 Ом; Допустимый ток обмотки: 480 мА; Изготовитель: АО "НПО "ЭРКОН"; Диапазон рабочих температур: от -60 до +125 ℃; Технология монтажа: SMT; Типоразмер: 1005 (0402); Упаковка: Катушка и лента
footprint КИК-1005_Зл (Катушка индуктивности с керамическим сердечником типоразмер 1005(0402))
pins: 1, 2

## КИК-1005-9.5 нГн ±10% Зл
designator L?, comment 9.5 нГн ±10%  (value not drawn)
Катушка индуктивности с керамическим сердечником и золотым покрытием контактных площадок; Номиналиная индуктивность: 9.5 нГн; Добротность, не менее: 20; Резонансная частота, не менее: 4.00 ГГц; Сопротивление обмотки постоянноми току, не более: 0.20 Ом; Допустимый ток обмотки: 480 мА; Изготовитель: АО "НПО "ЭРКОН"; Диапазон рабочих температур: от -60 до +125 ℃; Технология монтажа: SMT; Типоразмер: 1005 (0402); Упаковка: Катушка и лента
footprint КИК-1005_Зл (Катушка индуктивности с керамическим сердечником типоразмер 1005(0402))
pins: 1, 2

## КИК-1005-9.5 нГн ±20% Зл
designator L?, comment 9.5 нГн ±20%  (value not drawn)
Катушка индуктивности с керамическим сердечником и золотым покрытием контактных площадок; Номиналиная индуктивность: 9.5 нГн; Добротность, не менее: 20; Резонансная частота, не менее: 4.00 ГГц; Сопротивление обмотки постоянноми току, не более: 0.20 Ом; Допустимый ток обмотки: 480 мА; Изготовитель: АО "НПО "ЭРКОН"; Диапазон рабочих температур: от -60 до +125 ℃; Технология монтажа: SMT; Типоразмер: 1005 (0402); Упаковка: Катушка и лента
footprint КИК-1005_Зл (Катушка индуктивности с керамическим сердечником типоразмер 1005(0402))
pins: 1, 2

## КИК-1005-10 нГн ±2% Зл
designator L?, comment 10 нГн ±2%  (value not drawn)
Катушка индуктивности с керамическим сердечником и золотым покрытием контактных площадок; Номиналиная индуктивность: 10 нГн; Добротность, не менее: 20; Резонансная частота, не менее: 3.90 ГГц; Сопротивление обмотки постоянноми току, не более: 0.20 Ом; Допустимый ток обмотки: 480 мА; Изготовитель: АО "НПО "ЭРКОН"; Диапазон рабочих температур: от -60 до +125 ℃; Технология монтажа: SMT; Типоразмер: 1005 (0402); Упаковка: Катушка и лента
footprint КИК-1005_Зл (Катушка индуктивности с керамическим сердечником типоразмер 1005(0402))
pins: 1, 2

## КИК-1005-10 нГн ±5% Зл
designator L?, comment 10 нГн ±5%  (value not drawn)
Катушка индуктивности с керамическим сердечником и золотым покрытием контактных площадок; Номиналиная индуктивность: 10 нГн; Добротность, не менее: 20; Резонансная частота, не менее: 3.90 ГГц; Сопротивление обмотки постоянноми току, не более: 0.20 Ом; Допустимый ток обмотки: 480 мА; Изготовитель: АО "НПО "ЭРКОН"; Диапазон рабочих температур: от -60 до +125 ℃; Технология монтажа: SMT; Типоразмер: 1005 (0402); Упаковка: Катушка и лента
footprint КИК-1005_Зл (Катушка индуктивности с керамическим сердечником типоразмер 1005(0402))
pins: 1, 2

## КИК-1005-10 нГн ±10% Зл
designator L?, comment 10 нГн ±10%  (value not drawn)
Катушка индуктивности с керамическим сердечником и золотым покрытием контактных площадок; Номиналиная индуктивность: 10 нГн; Добротность, не менее: 20; Резонансная частота, не менее: 3.90 ГГц; Сопротивление обмотки постоянноми току, не более: 0.20 Ом; Допустимый ток обмотки: 480 мА; Изготовитель: АО "НПО "ЭРКОН"; Диапазон рабочих температур: от -60 до +125 ℃; Технология монтажа: SMT; Типоразмер: 1005 (0402); Упаковка: Катушка и лента
footprint КИК-1005_Зл (Катушка индуктивности с керамическим сердечником типоразмер 1005(0402))
pins: 1, 2

## КИК-1005-10 нГн ±20% Зл
designator L?, comment 10 нГн ±20%  (value not drawn)
Катушка индуктивности с керамическим сердечником и золотым покрытием контактных площадок; Номиналиная индуктивность: 10 нГн; Добротность, не менее: 20; Резонансная частота, не менее: 3.90 ГГц; Сопротивление обмотки постоянноми току, не более: 0.20 Ом; Допустимый ток обмотки: 480 мА; Изготовитель: АО "НПО "ЭРКОН"; Диапазон рабочих температур: от -60 до +125 ℃; Технология монтажа: SMT; Типоразмер: 1005 (0402); Упаковка: Катушка и лента
footprint КИК-1005_Зл (Катушка индуктивности с керамическим сердечником типоразмер 1005(0402))
pins: 1, 2

## КИК-1005-11 нГн ±2% Зл
designator L?, comment 11 нГн ±2%  (value not drawn)
Катушка индуктивности с керамическим сердечником и золотым покрытием контактных площадок; Номиналиная индуктивность: 11 нГн; Добротность, не менее: 25; Резонансная частота, не менее: 3.68 ГГц; Сопротивление обмотки постоянноми току, не более: 0.12 Ом; Допустимый ток обмотки: 640 мА; Изготовитель: АО "НПО "ЭРКОН"; Диапазон рабочих температур: от -60 до +125 ℃; Технология монтажа: SMT; Типоразмер: 1005 (0402); Упаковка: Катушка и лента
footprint КИК-1005_Зл (Катушка индуктивности с керамическим сердечником типоразмер 1005(0402))
pins: 1, 2

## КИК-1005-11 нГн ±5% Зл
designator L?, comment 11 нГн ±5%  (value not drawn)
Катушка индуктивности с керамическим сердечником и золотым покрытием контактных площадок; Номиналиная индуктивность: 11 нГн; Добротность, не менее: 25; Резонансная частота, не менее: 3.68 ГГц; Сопротивление обмотки постоянноми току, не более: 0.12 Ом; Допустимый ток обмотки: 640 мА; Изготовитель: АО "НПО "ЭРКОН"; Диапазон рабочих температур: от -60 до +125 ℃; Технология монтажа: SMT; Типоразмер: 1005 (0402); Упаковка: Катушка и лента
footprint КИК-1005_Зл (Катушка индуктивности с керамическим сердечником типоразмер 1005(0402))
pins: 1, 2

## КИК-1005-11 нГн ±10% Зл
designator L?, comment 11 нГн ±10%  (value not drawn)
Катушка индуктивности с керамическим сердечником и золотым покрытием контактных площадок; Номиналиная индуктивность: 11 нГн; Добротность, не менее: 25; Резонансная частота, не менее: 3.68 ГГц; Сопротивление обмотки постоянноми току, не более: 0.12 Ом; Допустимый ток обмотки: 640 мА; Изготовитель: АО "НПО "ЭРКОН"; Диапазон рабочих температур: от -60 до +125 ℃; Технология монтажа: SMT; Типоразмер: 1005 (0402); Упаковка: Катушка и лента
footprint КИК-1005_Зл (Катушка индуктивности с керамическим сердечником типоразмер 1005(0402))
pins: 1, 2

## КИК-1005-11 нГн ±20% Зл
designator L?, comment 11 нГн ±20%  (value not drawn)
Катушка индуктивности с керамическим сердечником и золотым покрытием контактных площадок; Номиналиная индуктивность: 11 нГн; Добротность, не менее: 25; Резонансная частота, не менее: 3.68 ГГц; Сопротивление обмотки постоянноми току, не более: 0.12 Ом; Допустимый ток обмотки: 640 мА; Изготовитель: АО "НПО "ЭРКОН"; Диапазон рабочих температур: от -60 до +125 ℃; Технология монтажа: SMT; Типоразмер: 1005 (0402); Упаковка: Катушка и лента
footprint КИК-1005_Зл (Катушка индуктивности с керамическим сердечником типоразмер 1005(0402))
pins: 1, 2

## КИК-1005-12 нГн ±2% Зл
designator L?, comment 12 нГн ±2%  (value not drawn)
Катушка индуктивности с керамическим сердечником и золотым покрытием контактных площадок; Номиналиная индуктивность: 12 нГн; Добротность, не менее: 25; Резонансная частота, не менее: 3.60 ГГц; Сопротивление обмотки постоянноми току, не более: 0.12 Ом; Допустимый ток обмотки: 640 мА; Изготовитель: АО "НПО "ЭРКОН"; Диапазон рабочих температур: от -60 до +125 ℃; Технология монтажа: SMT; Типоразмер: 1005 (0402); Упаковка: Катушка и лента
footprint КИК-1005_Зл (Катушка индуктивности с керамическим сердечником типоразмер 1005(0402))
pins: 1, 2

## КИК-1005-12 нГн ±5% Зл
designator L?, comment 12 нГн ±5%  (value not drawn)
Катушка индуктивности с керамическим сердечником и золотым покрытием контактных площадок; Номиналиная индуктивность: 12 нГн; Добротность, не менее: 25; Резонансная частота, не менее: 3.60 ГГц; Сопротивление обмотки постоянноми току, не более: 0.12 Ом; Допустимый ток обмотки: 640 мА; Изготовитель: АО "НПО "ЭРКОН"; Диапазон рабочих температур: от -60 до +125 ℃; Технология монтажа: SMT; Типоразмер: 1005 (0402); Упаковка: Катушка и лента
footprint КИК-1005_Зл (Катушка индуктивности с керамическим сердечником типоразмер 1005(0402))
pins: 1, 2

## КИК-1005-12 нГн ±10% Зл
designator L?, comment 12 нГн ±10%  (value not drawn)
Катушка индуктивности с керамическим сердечником и золотым покрытием контактных площадок; Номиналиная индуктивность: 12 нГн; Добротность, не менее: 25; Резонансная частота, не менее: 3.60 ГГц; Сопротивление обмотки постоянноми току, не более: 0.12 Ом; Допустимый ток обмотки: 640 мА; Изготовитель: АО "НПО "ЭРКОН"; Диапазон рабочих температур: от -60 до +125 ℃; Технология монтажа: SMT; Типоразмер: 1005 (0402); Упаковка: Катушка и лента
footprint КИК-1005_Зл (Катушка индуктивности с керамическим сердечником типоразмер 1005(0402))
pins: 1, 2

## КИК-1005-12 нГн ±20% Зл
designator L?, comment 12 нГн ±20%  (value not drawn)
Катушка индуктивности с керамическим сердечником и золотым покрытием контактных площадок; Номиналиная индуктивность: 12 нГн; Добротность, не менее: 25; Резонансная частота, не менее: 3.60 ГГц; Сопротивление обмотки постоянноми току, не более: 0.12 Ом; Допустимый ток обмотки: 640 мА; Изготовитель: АО "НПО "ЭРКОН"; Диапазон рабочих температур: от -60 до +125 ℃; Технология монтажа: SMT; Типоразмер: 1005 (0402); Упаковка: Катушка и лента
footprint КИК-1005_Зл (Катушка индуктивности с керамическим сердечником типоразмер 1005(0402))
pins: 1, 2

## КИК-1005-13 нГн ±2% Зл
designator L?, comment 13 нГн ±2%  (value not drawn)
Катушка индуктивности с керамическим сердечником и золотым покрытием контактных площадок; Номиналиная индуктивность: 13 нГн; Добротность, не менее: 25; Резонансная частота, не менее: 3.45 ГГц; Сопротивление обмотки постоянноми току, не более: 0.21 Ом; Допустимый ток обмотки: 440 мА; Изготовитель: АО "НПО "ЭРКОН"; Диапазон рабочих температур: от -60 до +125 ℃; Технология монтажа: SMT; Типоразмер: 1005 (0402); Упаковка: Катушка и лента
footprint КИК-1005_Зл (Катушка индуктивности с керамическим сердечником типоразмер 1005(0402))
pins: 1, 2

## КИК-1005-13 нГн ±5% Зл
designator L?, comment 13 нГн ±5%  (value not drawn)
Катушка индуктивности с керамическим сердечником и золотым покрытием контактных площадок; Номиналиная индуктивность: 13 нГн; Добротность, не менее: 25; Резонансная частота, не менее: 3.45 ГГц; Сопротивление обмотки постоянноми току, не более: 0.21 Ом; Допустимый ток обмотки: 440 мА; Изготовитель: АО "НПО "ЭРКОН"; Диапазон рабочих температур: от -60 до +125 ℃; Технология монтажа: SMT; Типоразмер: 1005 (0402); Упаковка: Катушка и лента
footprint КИК-1005_Зл (Катушка индуктивности с керамическим сердечником типоразмер 1005(0402))
pins: 1, 2

## КИК-1005-13 нГн ±10% Зл
designator L?, comment 13 нГн ±10%  (value not drawn)
Катушка индуктивности с керамическим сердечником и золотым покрытием контактных площадок; Номиналиная индуктивность: 13 нГн; Добротность, не менее: 25; Резонансная частота, не менее: 3.45 ГГц; Сопротивление обмотки постоянноми току, не более: 0.21 Ом; Допустимый ток обмотки: 440 мА; Изготовитель: АО "НПО "ЭРКОН"; Диапазон рабочих температур: от -60 до +125 ℃; Технология монтажа: SMT; Типоразмер: 1005 (0402); Упаковка: Катушка и лента
footprint КИК-1005_Зл (Катушка индуктивности с керамическим сердечником типоразмер 1005(0402))
pins: 1, 2

## КИК-1005-13 нГн ±20% Зл
designator L?, comment 13 нГн ±20%  (value not drawn)
Катушка индуктивности с керамическим сердечником и золотым покрытием контактных площадок; Номиналиная индуктивность: 13 нГн; Добротность, не менее: 25; Резонансная частота, не менее: 3.45 ГГц; Сопротивление обмотки постоянноми току, не более: 0.21 Ом; Допустимый ток обмотки: 440 мА; Изготовитель: АО "НПО "ЭРКОН"; Диапазон рабочих температур: от -60 до +125 ℃; Технология монтажа: SMT; Типоразмер: 1005 (0402); Упаковка: Катушка и лента
footprint КИК-1005_Зл (Катушка индуктивности с керамическим сердечником типоразмер 1005(0402))
pins: 1, 2

## КИК-1005-15 нГн ±2% Зл
designator L?, comment 15 нГн ±2%  (value not drawn)
Катушка индуктивности с керамическим сердечником и золотым покрытием контактных площадок; Номиналиная индуктивность: 15 нГн; Добротность, не менее: 25; Резонансная частота, не менее: 3.28 ГГц; Сопротивление обмотки постоянноми току, не более: 0.21 Ом; Допустимый ток обмотки: 560 мА; Изготовитель: АО "НПО "ЭРКОН"; Диапазон рабочих температур: от -60 до +125 ℃; Технология монтажа: SMT; Типоразмер: 1005 (0402); Упаковка: Катушка и лента
footprint КИК-1005_Зл (Катушка индуктивности с керамическим сердечником типоразмер 1005(0402))
pins: 1, 2

## КИК-1005-15 нГн ±5% Зл
designator L?, comment 15 нГн ±5%  (value not drawn)
Катушка индуктивности с керамическим сердечником и золотым покрытием контактных площадок; Номиналиная индуктивность: 15 нГн; Добротность, не менее: 25; Резонансная частота, не менее: 3.28 ГГц; Сопротивление обмотки постоянноми току, не более: 0.21 Ом; Допустимый ток обмотки: 560 мА; Изготовитель: АО "НПО "ЭРКОН"; Диапазон рабочих температур: от -60 до +125 ℃; Технология монтажа: SMT; Типоразмер: 1005 (0402); Упаковка: Катушка и лента
footprint КИК-1005_Зл (Катушка индуктивности с керамическим сердечником типоразмер 1005(0402))
pins: 1, 2

## КИК-1005-15 нГн ±10% Зл
designator L?, comment 15 нГн ±10%  (value not drawn)
Катушка индуктивности с керамическим сердечником и золотым покрытием контактных площадок; Номиналиная индуктивность: 15 нГн; Добротность, не менее: 25; Резонансная частота, не менее: 3.28 ГГц; Сопротивление обмотки постоянноми току, не более: 0.21 Ом; Допустимый ток обмотки: 560 мА; Изготовитель: АО "НПО "ЭРКОН"; Диапазон рабочих температур: от -60 до +125 ℃; Технология монтажа: SMT; Типоразмер: 1005 (0402); Упаковка: Катушка и лента
footprint КИК-1005_Зл (Катушка индуктивности с керамическим сердечником типоразмер 1005(0402))
pins: 1, 2

## КИК-1005-15 нГн ±20% Зл
designator L?, comment 15 нГн ±20%  (value not drawn)
Катушка индуктивности с керамическим сердечником и золотым покрытием контактных площадок; Номиналиная индуктивность: 15 нГн; Добротность, не менее: 25; Резонансная частота, не менее: 3.28 ГГц; Сопротивление обмотки постоянноми току, не более: 0.21 Ом; Допустимый ток обмотки: 560 мА; Изготовитель: АО "НПО "ЭРКОН"; Диапазон рабочих температур: от -60 до +125 ℃; Технология монтажа: SMT; Типоразмер: 1005 (0402); Упаковка: Катушка и лента
footprint КИК-1005_Зл (Катушка индуктивности с керамическим сердечником типоразмер 1005(0402))
pins: 1, 2

## КИК-1005-16 нГн ±2% Зл
designator L?, comment 16 нГн ±2%  (value not drawn)
Катушка индуктивности с керамическим сердечником и золотым покрытием контактных площадок; Номиналиная индуктивность: 16 нГн; Добротность, не менее: 25; Резонансная частота, не менее: 3.10 ГГц; Сопротивление обмотки постоянноми току, не более: 0.22 Ом; Допустимый ток обмотки: 560 мА; Изготовитель: АО "НПО "ЭРКОН"; Диапазон рабочих температур: от -60 до +125 ℃; Технология монтажа: SMT; Типоразмер: 1005 (0402); Упаковка: Катушка и лента
footprint КИК-1005_Зл (Катушка индуктивности с керамическим сердечником типоразмер 1005(0402))
pins: 1, 2

## КИК-1005-16 нГн ±5% Зл
designator L?, comment 16 нГн ±5%  (value not drawn)
Катушка индуктивности с керамическим сердечником и золотым покрытием контактных площадок; Номиналиная индуктивность: 16 нГн; Добротность, не менее: 25; Резонансная частота, не менее: 3.10 ГГц; Сопротивление обмотки постоянноми току, не более: 0.22 Ом; Допустимый ток обмотки: 560 мА; Изготовитель: АО "НПО "ЭРКОН"; Диапазон рабочих температур: от -60 до +125 ℃; Технология монтажа: SMT; Типоразмер: 1005 (0402); Упаковка: Катушка и лента
footprint КИК-1005_Зл (Катушка индуктивности с керамическим сердечником типоразмер 1005(0402))
pins: 1, 2

## КИК-1005-16 нГн ±10% Зл
designator L?, comment 16 нГн ±10%  (value not drawn)
Катушка индуктивности с керамическим сердечником и золотым покрытием контактных площадок; Номиналиная индуктивность: 16 нГн; Добротность, не менее: 25; Резонансная частота, не менее: 3.10 ГГц; Сопротивление обмотки постоянноми току, не более: 0.22 Ом; Допустимый ток обмотки: 560 мА; Изготовитель: АО "НПО "ЭРКОН"; Диапазон рабочих температур: от -60 до +125 ℃; Технология монтажа: SMT; Типоразмер: 1005 (0402); Упаковка: Катушка и лента
footprint КИК-1005_Зл (Катушка индуктивности с керамическим сердечником типоразмер 1005(0402))
pins: 1, 2

## КИК-1005-16 нГн ±20% Зл
designator L?, comment 16 нГн ±20%  (value not drawn)
Катушка индуктивности с керамическим сердечником и золотым покрытием контактных площадок; Номиналиная индуктивность: 16 нГн; Добротность, не менее: 25; Резонансная частота, не менее: 3.10 ГГц; Сопротивление обмотки постоянноми току, не более: 0.22 Ом; Допустимый ток обмотки: 560 мА; Изготовитель: АО "НПО "ЭРКОН"; Диапазон рабочих температур: от -60 до +125 ℃; Технология монтажа: SMT; Типоразмер: 1005 (0402); Упаковка: Катушка и лента
footprint КИК-1005_Зл (Катушка индуктивности с керамическим сердечником типоразмер 1005(0402))
pins: 1, 2

## КИК-1005-18 нГн ±2% Зл
designator L?, comment 18 нГн ±2%  (value not drawn)
Катушка индуктивности с керамическим сердечником и золотым покрытием контактных площадок; Номиналиная индуктивность: 18 нГн; Добротность, не менее: 25; Резонансная частота, не менее: 3.10 ГГц; Сопротивление обмотки постоянноми току, не более: 0.23 Ом; Допустимый ток обмотки: 420 мА; Изготовитель: АО "НПО "ЭРКОН"; Диапазон рабочих температур: от -60 до +125 ℃; Технология монтажа: SMT; Типоразмер: 1005 (0402); Упаковка: Катушка и лента
footprint КИК-1005_Зл (Катушка индуктивности с керамическим сердечником типоразмер 1005(0402))
pins: 1, 2

## КИК-1005-18 нГн ±5% Зл
designator L?, comment 18 нГн ±5%  (value not drawn)
Катушка индуктивности с керамическим сердечником и золотым покрытием контактных площадок; Номиналиная индуктивность: 18 нГн; Добротность, не менее: 25; Резонансная частота, не менее: 3.10 ГГц; Сопротивление обмотки постоянноми току, не более: 0.23 Ом; Допустимый ток обмотки: 420 мА; Изготовитель: АО "НПО "ЭРКОН"; Диапазон рабочих температур: от -60 до +125 ℃; Технология монтажа: SMT; Типоразмер: 1005 (0402); Упаковка: Катушка и лента
footprint КИК-1005_Зл (Катушка индуктивности с керамическим сердечником типоразмер 1005(0402))
pins: 1, 2

## КИК-1005-18 нГн ±10% Зл
designator L?, comment 18 нГн ±10%  (value not drawn)
Катушка индуктивности с керамическим сердечником и золотым покрытием контактных площадок; Номиналиная индуктивность: 18 нГн; Добротность, не менее: 25; Резонансная частота, не менее: 3.10 ГГц; Сопротивление обмотки постоянноми току, не более: 0.23 Ом; Допустимый ток обмотки: 420 мА; Изготовитель: АО "НПО "ЭРКОН"; Диапазон рабочих температур: от -60 до +125 ℃; Технология монтажа: SMT; Типоразмер: 1005 (0402); Упаковка: Катушка и лента
footprint КИК-1005_Зл (Катушка индуктивности с керамическим сердечником типоразмер 1005(0402))
pins: 1, 2

## КИК-1005-18 нГн ±20% Зл
designator L?, comment 18 нГн ±20%  (value not drawn)
Катушка индуктивности с керамическим сердечником и золотым покрытием контактных площадок; Номиналиная индуктивность: 18 нГн; Добротность, не менее: 25; Резонансная частота, не менее: 3.10 ГГц; Сопротивление обмотки постоянноми току, не более: 0.23 Ом; Допустимый ток обмотки: 420 мА; Изготовитель: АО "НПО "ЭРКОН"; Диапазон рабочих температур: от -60 до +125 ℃; Технология монтажа: SMT; Типоразмер: 1005 (0402); Упаковка: Катушка и лента
footprint КИК-1005_Зл (Катушка индуктивности с керамическим сердечником типоразмер 1005(0402))
pins: 1, 2

## КИК-1005-19 нГн ±2% Зл
designator L?, comment 19 нГн ±2%  (value not drawn)
Катушка индуктивности с керамическим сердечником и золотым покрытием контактных площадок; Номиналиная индуктивность: 19 нГн; Добротность, не менее: 25; Резонансная частота, не менее: 3.04 ГГц; Сопротивление обмотки постоянноми току, не более: 0.23 Ом; Допустимый ток обмотки: 480 мА; Изготовитель: АО "НПО "ЭРКОН"; Диапазон рабочих температур: от -60 до +125 ℃; Технология монтажа: SMT; Типоразмер: 1005 (0402); Упаковка: Катушка и лента
footprint КИК-1005_Зл (Катушка индуктивности с керамическим сердечником типоразмер 1005(0402))
pins: 1, 2

## КИК-1005-19 нГн ±5% Зл
designator L?, comment 19 нГн ±5%  (value not drawn)
Катушка индуктивности с керамическим сердечником и золотым покрытием контактных площадок; Номиналиная индуктивность: 19 нГн; Добротность, не менее: 25; Резонансная частота, не менее: 3.04 ГГц; Сопротивление обмотки постоянноми току, не более: 0.23 Ом; Допустимый ток обмотки: 480 мА; Изготовитель: АО "НПО "ЭРКОН"; Диапазон рабочих температур: от -60 до +125 ℃; Технология монтажа: SMT; Типоразмер: 1005 (0402); Упаковка: Катушка и лента
footprint КИК-1005_Зл (Катушка индуктивности с керамическим сердечником типоразмер 1005(0402))
pins: 1, 2

## КИК-1005-19 нГн ±10% Зл
designator L?, comment 19 нГн ±10%  (value not drawn)
Катушка индуктивности с керамическим сердечником и золотым покрытием контактных площадок; Номиналиная индуктивность: 19 нГн; Добротность, не менее: 25; Резонансная частота, не менее: 3.04 ГГц; Сопротивление обмотки постоянноми току, не более: 0.23 Ом; Допустимый ток обмотки: 480 мА; Изготовитель: АО "НПО "ЭРКОН"; Диапазон рабочих температур: от -60 до +125 ℃; Технология монтажа: SMT; Типоразмер: 1005 (0402); Упаковка: Катушка и лента
footprint КИК-1005_Зл (Катушка индуктивности с керамическим сердечником типоразмер 1005(0402))
pins: 1, 2

## КИК-1005-19 нГн ±20% Зл
designator L?, comment 19 нГн ±20%  (value not drawn)
Катушка индуктивности с керамическим сердечником и золотым покрытием контактных площадок; Номиналиная индуктивность: 19 нГн; Добротность, не менее: 25; Резонансная частота, не менее: 3.04 ГГц; Сопротивление обмотки постоянноми току, не более: 0.23 Ом; Допустимый ток обмотки: 480 мА; Изготовитель: АО "НПО "ЭРКОН"; Диапазон рабочих температур: от -60 до +125 ℃; Технология монтажа: SMT; Типоразмер: 1005 (0402); Упаковка: Катушка и лента
footprint КИК-1005_Зл (Катушка индуктивности с керамическим сердечником типоразмер 1005(0402))
pins: 1, 2

## КИК-1005-20 нГн ±2% Зл
designator L?, comment 20 нГн ±2%  (value not drawn)
Катушка индуктивности с керамическим сердечником и золотым покрытием контактных площадок; Номиналиная индуктивность: 20 нГн; Добротность, не менее: 25; Резонансная частота, не менее: 3.00 ГГц; Сопротивление обмотки постоянноми току, не более: 0.25 Ом; Допустимый ток обмотки: 420 мА; Изготовитель: АО "НПО "ЭРКОН"; Диапазон рабочих температур: от -60 до +125 ℃; Технология монтажа: SMT; Типоразмер: 1005 (0402); Упаковка: Катушка и лента
footprint КИК-1005_Зл (Катушка индуктивности с керамическим сердечником типоразмер 1005(0402))
pins: 1, 2

## КИК-1005-20 нГн ±5% Зл
designator L?, comment 20 нГн ±5%  (value not drawn)
Катушка индуктивности с керамическим сердечником и золотым покрытием контактных площадок; Номиналиная индуктивность: 20 нГн; Добротность, не менее: 25; Резонансная частота, не менее: 3.00 ГГц; Сопротивление обмотки постоянноми току, не более: 0.25 Ом; Допустимый ток обмотки: 420 мА; Изготовитель: АО "НПО "ЭРКОН"; Диапазон рабочих температур: от -60 до +125 ℃; Технология монтажа: SMT; Типоразмер: 1005 (0402); Упаковка: Катушка и лента
footprint КИК-1005_Зл (Катушка индуктивности с керамическим сердечником типоразмер 1005(0402))
pins: 1, 2

## КИК-1005-20 нГн ±10% Зл
designator L?, comment 20 нГн ±10%  (value not drawn)
Катушка индуктивности с керамическим сердечником и золотым покрытием контактных площадок; Номиналиная индуктивность: 20 нГн; Добротность, не менее: 25; Резонансная частота, не менее: 3.00 ГГц; Сопротивление обмотки постоянноми току, не более: 0.25 Ом; Допустимый ток обмотки: 420 мА; Изготовитель: АО "НПО "ЭРКОН"; Диапазон рабочих температур: от -60 до +125 ℃; Технология монтажа: SMT; Типоразмер: 1005 (0402); Упаковка: Катушка и лента
footprint КИК-1005_Зл (Катушка индуктивности с керамическим сердечником типоразмер 1005(0402))
pins: 1, 2


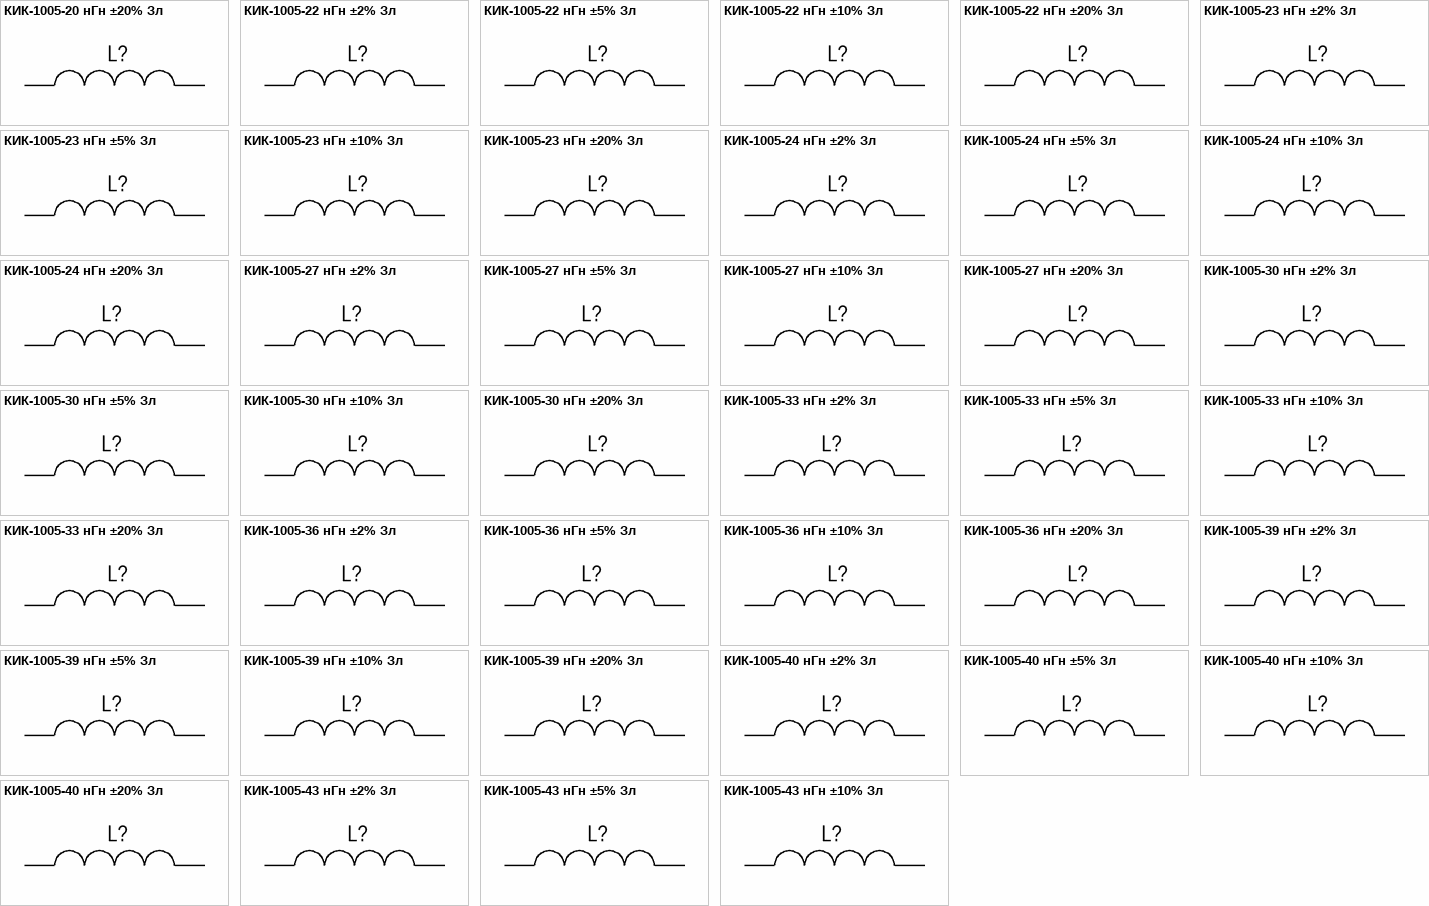
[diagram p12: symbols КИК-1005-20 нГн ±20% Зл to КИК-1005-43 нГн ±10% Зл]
## КИК-1005-20 нГн ±20% Зл
designator L?, comment 20 нГн ±20%  (value not drawn)
Катушка индуктивности с керамическим сердечником и золотым покрытием контактных площадок; Номиналиная индуктивность: 20 нГн; Добротность, не менее: 25; Резонансная частота, не менее: 3.00 ГГц; Сопротивление обмотки постоянноми току, не более: 0.25 Ом; Допустимый ток обмотки: 420 мА; Изготовитель: АО "НПО "ЭРКОН"; Диапазон рабочих температур: от -60 до +125 ℃; Технология монтажа: SMT; Типоразмер: 1005 (0402); Упаковка: Катушка и лента
footprint КИК-1005_Зл (Катушка индуктивности с керамическим сердечником типоразмер 1005(0402))
pins: 1, 2

## КИК-1005-22 нГн ±2% Зл
designator L?, comment 22 нГн ±2%  (value not drawn)
Катушка индуктивности с керамическим сердечником и золотым покрытием контактных площадок; Номиналиная индуктивность: 22 нГн; Добротность, не менее: 25; Резонансная частота, не менее: 2.80 ГГц; Сопротивление обмотки постоянноми току, не более: 0.30 Ом; Допустимый ток обмотки: 400 мА; Изготовитель: АО "НПО "ЭРКОН"; Диапазон рабочих температур: от -60 до +125 ℃; Технология монтажа: SMT; Типоразмер: 1005 (0402); Упаковка: Катушка и лента
footprint КИК-1005_Зл (Катушка индуктивности с керамическим сердечником типоразмер 1005(0402))
pins: 1, 2

## КИК-1005-22 нГн ±5% Зл
designator L?, comment 22 нГн ±5%  (value not drawn)
Катушка индуктивности с керамическим сердечником и золотым покрытием контактных площадок; Номиналиная индуктивность: 22 нГн; Добротность, не менее: 25; Резонансная частота, не менее: 2.80 ГГц; Сопротивление обмотки постоянноми току, не более: 0.30 Ом; Допустимый ток обмотки: 400 мА; Изготовитель: АО "НПО "ЭРКОН"; Диапазон рабочих температур: от -60 до +125 ℃; Технология монтажа: SMT; Типоразмер: 1005 (0402); Упаковка: Катушка и лента
footprint КИК-1005_Зл (Катушка индуктивности с керамическим сердечником типоразмер 1005(0402))
pins: 1, 2

## КИК-1005-22 нГн ±10% Зл
designator L?, comment 22 нГн ±10%  (value not drawn)
Катушка индуктивности с керамическим сердечником и золотым покрытием контактных площадок; Номиналиная индуктивность: 22 нГн; Добротность, не менее: 25; Резонансная частота, не менее: 2.80 ГГц; Сопротивление обмотки постоянноми току, не более: 0.30 Ом; Допустимый ток обмотки: 400 мА; Изготовитель: АО "НПО "ЭРКОН"; Диапазон рабочих температур: от -60 до +125 ℃; Технология монтажа: SMT; Типоразмер: 1005 (0402); Упаковка: Катушка и лента
footprint КИК-1005_Зл (Катушка индуктивности с керамическим сердечником типоразмер 1005(0402))
pins: 1, 2

## КИК-1005-22 нГн ±20% Зл
designator L?, comment 22 нГн ±20%  (value not drawn)
Катушка индуктивности с керамическим сердечником и золотым покрытием контактных площадок; Номиналиная индуктивность: 22 нГн; Добротность, не менее: 25; Резонансная частота, не менее: 2.80 ГГц; Сопротивление обмотки постоянноми току, не более: 0.30 Ом; Допустимый ток обмотки: 400 мА; Изготовитель: АО "НПО "ЭРКОН"; Диапазон рабочих температур: от -60 до +125 ℃; Технология монтажа: SMT; Типоразмер: 1005 (0402); Упаковка: Катушка и лента
footprint КИК-1005_Зл (Катушка индуктивности с керамическим сердечником типоразмер 1005(0402))
pins: 1, 2

## КИК-1005-23 нГн ±2% Зл
designator L?, comment 23 нГн ±2%  (value not drawn)
Катушка индуктивности с керамическим сердечником и золотым покрытием контактных площадок; Номиналиная индуктивность: 23 нГн; Добротность, не менее: 25; Резонансная частота, не менее: 2.72ГГц; Сопротивление обмотки постоянноми току, не более: 0.30 Ом; Допустимый ток обмотки: 400 мА; Изготовитель: АО "НПО "ЭРКОН"; Диапазон рабочих температур: от -60 до +125 ℃; Технология монтажа: SMT; Типоразмер: 1005 (0402); Упаковка: Катушка и лента
footprint КИК-1005_Зл (Катушка индуктивности с керамическим сердечником типоразмер 1005(0402))
pins: 1, 2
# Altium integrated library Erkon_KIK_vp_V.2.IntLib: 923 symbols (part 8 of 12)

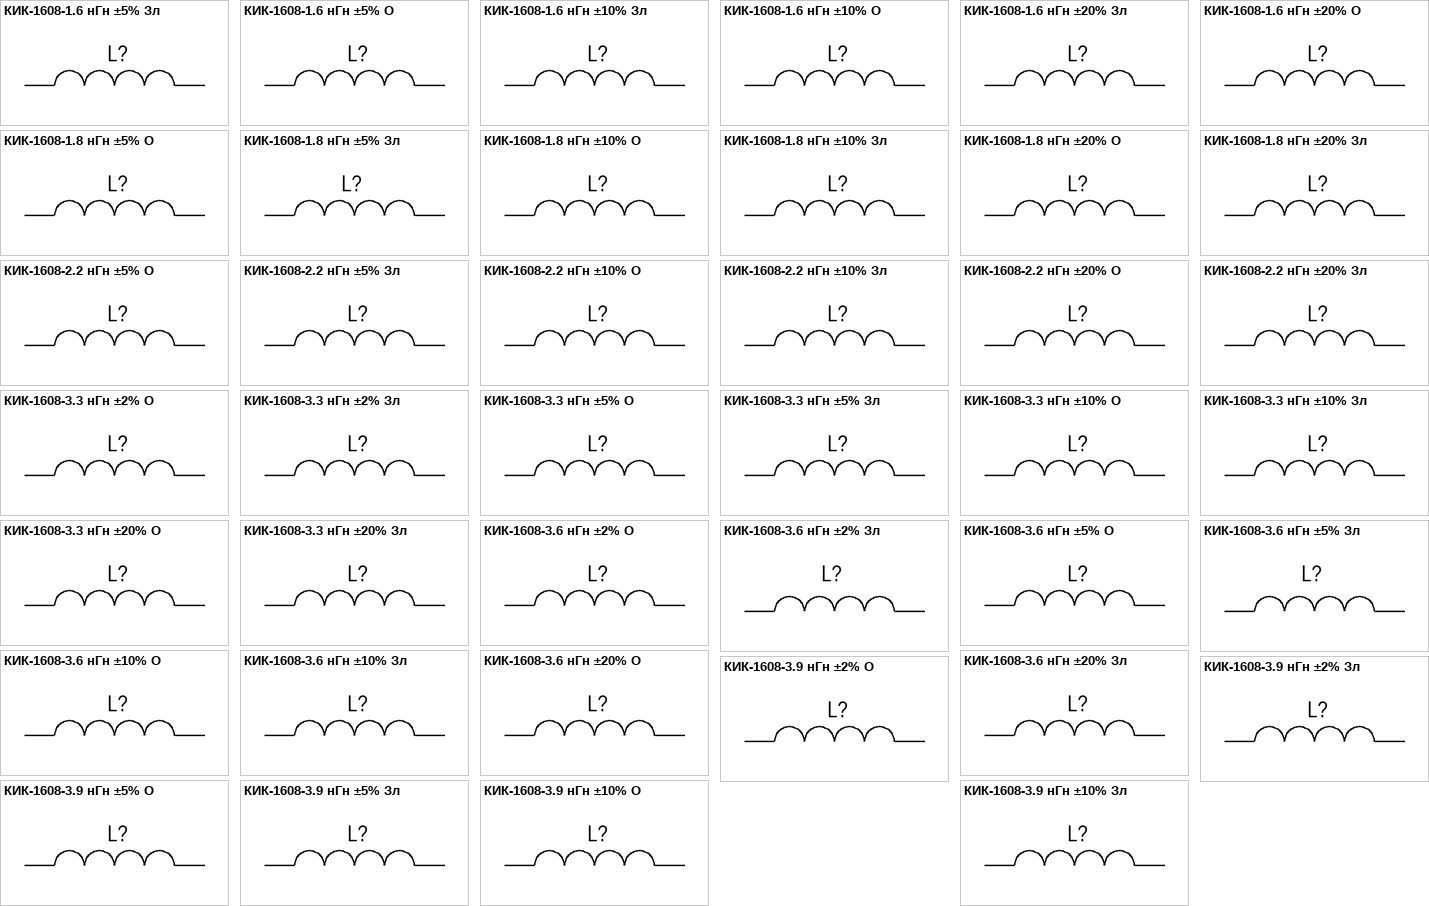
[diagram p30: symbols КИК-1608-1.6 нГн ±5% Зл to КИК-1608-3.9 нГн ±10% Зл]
## КИК-1608-2.2 нГн ±20% O
designator L?, comment 2.2 нГн ±20%  (value not drawn)
Катушка индуктивности с керамическим сердечником и  финишным покрытием контактных площадок оловом; Номиналиная индуктивность: 2.2 нГн; Добротность, не менее: 16; Резонансная частота, не менее: 12.5 ГГц; Сопротивление обмотки постоянноми току, не более: 0.250 Ом; Допустимый ток обмотки: 100 мА; Диапазон рабочих температур: от -60 до +125 ℃; Упаковка: Катушка и лента; Типоразмер: 1608 (0603); Технология монтажа: SMT; Изготовитель: АО "НПО "ЭРКОН"
footprint КИК-1608_О (Катушка индуктивности с керамическим сердечником  типоразмер 1005(0402))
pins: 1, 2

## КИК-1608-2.2 нГн ±20% Зл
designator L?, comment 2.2 нГн ±20%  (value not drawn)
Катушка индуктивности с керамическим сердечником и золотым покрытием контактных площадок; Номиналиная индуктивность: 2.2 нГн; Добротность, не менее: 16; Резонансная частота, не менее: 12.5 ГГц; Сопротивление обмотки постоянноми току, не более: 0.250 Ом; Допустимый ток обмотки: 100 мА; Диапазон рабочих температур: от -60 до +125 ℃; Упаковка: Катушка и лента; Типоразмер: 1608 (0603); Технология монтажа: SMT; Изготовитель: АО "НПО "ЭРКОН"
footprint КИК-1608_Зл (Катушка индуктивности с керамическим сердечником  типоразмер 1005(0402))
pins: 1, 2

## КИК-1608-3.3 нГн ±2% O
designator L?, comment 3.3 нГн ±2%  (value not drawn)
Катушка индуктивности с керамическим сердечником и  финишным покрытием контактных площадок оловом; Номиналиная индуктивность: 3.3 нГн; Добротность, не менее: 16; Резонансная частота, не менее: 5.90 ГГц; Сопротивление обмотки постоянноми току, не более: 0.045 Ом; Допустимый ток обмотки: 700 мА; Диапазон рабочих температур: от -60 до +125 ℃; Упаковка: Катушка и лента; Типоразмер: 1608 (0603); Технология монтажа: SMT; Изготовитель: АО "НПО "ЭРКОН"
footprint КИК-1608_О (Катушка индуктивности с керамическим сердечником  типоразмер 1005(0402))
pins: 1, 2

## КИК-1608-3.3 нГн ±2% Зл
designator L?, comment 3.3 нГн ±2%  (value not drawn)
Катушка индуктивности с керамическим сердечником и золотым покрытием контактных площадок; Номиналиная индуктивность: 3.3 нГн; Добротность, не менее: 16; Резонансная частота, не менее: 5.90 ГГц; Сопротивление обмотки постоянноми току, не более: 0.045 Ом; Допустимый ток обмотки: 700 мА; Диапазон рабочих температур: от -60 до +125 ℃; Упаковка: Катушка и лента; Типоразмер: 1608 (0603); Технология монтажа: SMT; Изготовитель: АО "НПО "ЭРКОН"
footprint КИК-1608_Зл (Катушка индуктивности с керамическим сердечником  типоразмер 1005(0402))
pins: 1, 2

## КИК-1608-3.3 нГн ±5% O
designator L?, comment 3.3 нГн ±5%  (value not drawn)
Катушка индуктивности с керамическим сердечником и  финишным покрытием контактных площадок оловом; Номиналиная индуктивность: 3.3 нГн; Добротность, не менее: 16; Резонансная частота, не менее: 5.90 ГГц; Сопротивление обмотки постоянноми току, не более: 0.045 Ом; Допустимый ток обмотки: 700 мА; Диапазон рабочих температур: от -60 до +125 ℃; Упаковка: Катушка и лента; Типоразмер: 1608 (0603); Технология монтажа: SMT; Изготовитель: АО "НПО "ЭРКОН"
footprint КИК-1608_О (Катушка индуктивности с керамическим сердечником  типоразмер 1005(0402))
pins: 1, 2

## КИК-1608-3.3 нГн ±5% Зл
designator L?, comment 3.3 нГн ±5%  (value not drawn)
Катушка индуктивности с керамическим сердечником и золотым покрытием контактных площадок; Номиналиная индуктивность: 3.3 нГн; Добротность, не менее: 16; Резонансная частота, не менее: 5.90 ГГц; Сопротивление обмотки постоянноми току, не более: 0.045 Ом; Допустимый ток обмотки: 700 мА; Диапазон рабочих температур: от -60 до +125 ℃; Упаковка: Катушка и лента; Типоразмер: 1608 (0603); Технология монтажа: SMT; Изготовитель: АО "НПО "ЭРКОН"
footprint КИК-1608_Зл (Катушка индуктивности с керамическим сердечником  типоразмер 1005(0402))
pins: 1, 2

## КИК-1608-3.3 нГн ±10% O
designator L?, comment 3.3 нГн ±10%  (value not drawn)
Катушка индуктивности с керамическим сердечником и  финишным покрытием контактных площадок оловом; Номиналиная индуктивность: 3.3 нГн; Добротность, не менее: 16; Резонансная частота, не менее: 5.90 ГГц; Сопротивление обмотки постоянноми току, не более: 0.045 Ом; Допустимый ток обмотки: 700 мА; Диапазон рабочих температур: от -60 до +125 ℃; Упаковка: Катушка и лента; Типоразмер: 1608 (0603); Технология монтажа: SMT; Изготовитель: АО "НПО "ЭРКОН"
footprint КИК-1608_О (Катушка индуктивности с керамическим сердечником  типоразмер 1005(0402))
pins: 1, 2

## КИК-1608-3.3 нГн ±10% Зл
designator L?, comment 3.3 нГн ±10%  (value not drawn)
Катушка индуктивности с керамическим сердечником и золотым покрытием контактных площадок; Номиналиная индуктивность: 3.3 нГн; Добротность, не менее: 16; Резонансная частота, не менее: 5.90 ГГц; Сопротивление обмотки постоянноми току, не более: 0.045 Ом; Допустимый ток обмотки: 700 мА; Диапазон рабочих температур: от -60 до +125 ℃; Упаковка: Катушка и лента; Типоразмер: 1608 (0603); Технология монтажа: SMT; Изготовитель: АО "НПО "ЭРКОН"
footprint КИК-1608_Зл (Катушка индуктивности с керамическим сердечником  типоразмер 1005(0402))
pins: 1, 2

## КИК-1608-3.3 нГн ±20% O
designator L?, comment 3.3 нГн ±20%  (value not drawn)
Катушка индуктивности с керамическим сердечником и  финишным покрытием контактных площадок оловом; Номиналиная индуктивность: 3.3 нГн; Допускаемое отклонение индуктивности: ±10%; Добротность, не менее: 16; Резонансная частота, не менее: 5.90 ГГц; Сопротивление обмотки постоянноми току, не более: 0.045 Ом; Допустимый ток обмотки: 700 мА; Диапазон рабочих температур: от -60 до +125 ℃; Упаковка: Катушка и лента; Типоразмер: 1608 (0603); Технология монтажа: SMT; Изготовитель: АО "НПО "ЭРКОН"
footprint КИК-1608_О (Катушка индуктивности с керамическим сердечником  типоразмер 1005(0402))
pins: 1, 2

## КИК-1608-3.3 нГн ±20% Зл
designator L?, comment 3.3 нГн ±20%  (value not drawn)
Катушка индуктивности с керамическим сердечником и золотым покрытием контактных площадок; Номиналиная индуктивность: 3.3 нГн; Добротность, не менее: 16; Резонансная частота, не менее: 5.90 ГГц; Сопротивление обмотки постоянноми току, не более: 0.045 Ом; Допустимый ток обмотки: 700 мА; Диапазон рабочих температур: от -60 до +125 ℃; Упаковка: Катушка и лента; Типоразмер: 1608 (0603); Технология монтажа: SMT; Изготовитель: АО "НПО "ЭРКОН"
footprint КИК-1608_Зл (Катушка индуктивности с керамическим сердечником  типоразмер 1005(0402))
pins: 1, 2

## КИК-1608-3.6 нГн ±2% O
designator L?, comment 3.6 нГн ±2%  (value not drawn)
Катушка индуктивности с керамическим сердечником и  финишным покрытием контактных площадок оловом; Номиналиная индуктивность: 3.6 нГн; Добротность, не менее: 16; Резонансная частота, не менее: 5.90 ГГц; Сопротивление обмотки постоянноми току, не более: 0.063 Ом; Допустимый ток обмотки: 700 мА; Диапазон рабочих температур: от -60 до +125 ℃; Упаковка: Катушка и лента; Типоразмер: 1608 (0603); Технология монтажа: SMT; Изготовитель: АО "НПО "ЭРКОН"
footprint КИК-1608_О (Катушка индуктивности с керамическим сердечником  типоразмер 1005(0402))
pins: 1, 2

## КИК-1608-3.6 нГн ±2% Зл
designator L?, comment 3.6 нГн ±2%  (value not drawn)
Катушка индуктивности с керамическим сердечником и золотым покрытием контактных площадок; Номиналиная индуктивность: 3.6 нГн; Добротность, не менее: 16; Резонансная частота, не менее: 5.90 ГГц; Сопротивление обмотки постоянноми току, не более: 0.063 Ом; Допустимый ток обмотки: 700 мА; Диапазон рабочих температур: от -60 до +125 ℃; Упаковка: Катушка и лента; Типоразмер: 1608 (0603); Технология монтажа: SMT; Изготовитель: АО "НПО "ЭРКОН"
footprint КИК-1608_Зл (Катушка индуктивности с керамическим сердечником  типоразмер 1005(0402))
pins: 1, 2

## КИК-1608-3.6 нГн ±5% O
designator L?, comment 3.6 нГн ±5%  (value not drawn)
Катушка индуктивности с керамическим сердечником и  финишным покрытием контактных площадок оловом; Номиналиная индуктивность: 3.6 нГн; Добротность, не менее: 16; Резонансная частота, не менее: 5.90 ГГц; Сопротивление обмотки постоянноми току, не более: 0.063 Ом; Допустимый ток обмотки: 700 мА; Диапазон рабочих температур: от -60 до +125 ℃; Упаковка: Катушка и лента; Типоразмер: 1608 (0603); Технология монтажа: SMT; Изготовитель: АО "НПО "ЭРКОН"
footprint КИК-1608_О (Катушка индуктивности с керамическим сердечником  типоразмер 1005(0402))
pins: 1, 2

## КИК-1608-3.6 нГн ±5% Зл
designator L?, comment 3.6 нГн ±5%  (value not drawn)
Катушка индуктивности с керамическим сердечником и золотым покрытием контактных площадок; Номиналиная индуктивность: 3.6 нГн; Добротность, не менее: 16; Резонансная частота, не менее: 5.90 ГГц; Сопротивление обмотки постоянноми току, не более: 0.063 Ом; Допустимый ток обмотки: 700 мА; Диапазон рабочих температур: от -60 до +125 ℃; Упаковка: Катушка и лента; Типоразмер: 1608 (0603); Технология монтажа: SMT; Изготовитель: АО "НПО "ЭРКОН"
footprint КИК-1608_Зл (Катушка индуктивности с керамическим сердечником  типоразмер 1005(0402))
pins: 1, 2

## КИК-1608-3.6 нГн ±10% O
designator L?, comment 3.6 нГн ±10%  (value not drawn)
Катушка индуктивности с керамическим сердечником и  финишным покрытием контактных площадок оловом; Номиналиная индуктивность: 3.6 нГн; Добротность, не менее: 16; Резонансная частота, не менее: 5.90 ГГц; Сопротивление обмотки постоянноми току, не более: 0.063 Ом; Допустимый ток обмотки: 700 мА; Диапазон рабочих температур: от -60 до +125 ℃; Упаковка: Катушка и лента; Типоразмер: 1608 (0603); Технология монтажа: SMT; Изготовитель: АО "НПО "ЭРКОН"
footprint КИК-1608_О (Катушка индуктивности с керамическим сердечником  типоразмер 1005(0402))
pins: 1, 2

## КИК-1608-3.6 нГн ±10% Зл
designator L?, comment 3.6 нГн ±10%  (value not drawn)
Катушка индуктивности с керамическим сердечником и золотым покрытием контактных площадок; Номиналиная индуктивность: 3.6 нГн; Добротность, не менее: 16; Резонансная частота, не менее: 5.90 ГГц; Сопротивление обмотки постоянноми току, не более: 0.063 Ом; Допустимый ток обмотки: 700 мА; Диапазон рабочих температур: от -60 до +125 ℃; Упаковка: Катушка и лента; Типоразмер: 1608 (0603); Технология монтажа: SMT; Изготовитель: АО "НПО "ЭРКОН"
footprint КИК-1608_Зл (Катушка индуктивности с керамическим сердечником  типоразмер 1005(0402))
pins: 1, 2

## КИК-1608-3.6 нГн ±20% O
designator L?, comment 3.6 нГн ±20%  (value not drawn)
Катушка индуктивности с керамическим сердечником и  финишным покрытием контактных площадок оловом; Номиналиная индуктивность: 3.6 нГн; Добротность, не менее: 16; Резонансная частота, не менее: 5.90 ГГц; Сопротивление обмотки постоянноми току, не более: 0.063 Ом; Допустимый ток обмотки: 700 мА; Диапазон рабочих температур: от -60 до +125 ℃; Упаковка: Катушка и лента; Типоразмер: 1608 (0603); Технология монтажа: SMT; Изготовитель: АО "НПО "ЭРКОН"
footprint КИК-1608_О (Катушка индуктивности с керамическим сердечником  типоразмер 1005(0402))
pins: 1, 2

## КИК-1608-3.6 нГн ±20% Зл
designator L?, comment 3.6 нГн ±20%  (value not drawn)
Катушка индуктивности с керамическим сердечником и золотым покрытием контактных площадок; Номиналиная индуктивность: 3.6 нГн; Добротность, не менее: 16; Резонансная частота, не менее: 5.90 ГГц; Сопротивление обмотки постоянноми току, не более: 0.063 Ом; Допустимый ток обмотки: 700 мА; Диапазон рабочих температур: от -60 до +125 ℃; Упаковка: Катушка и лента; Типоразмер: 1608 (0603); Технология монтажа: SMT; Изготовитель: АО "НПО "ЭРКОН"
footprint КИК-1608_Зл (Катушка индуктивности с керамическим сердечником  типоразмер 1005(0402))
pins: 1, 2

## КИК-1608-3.9 нГн ±2% O
designator L?, comment 3.9 нГн ±2%  (value not drawn)
Катушка индуктивности с керамическим сердечником и  финишным покрытием контактных площадок оловом; Номиналиная индуктивность: 3.9 нГн; Добротность, не менее: 16; Резонансная частота, не менее: 6.90 ГГц; Сопротивление обмотки постоянноми току, не более: 0.080 Ом; Допустимый ток обмотки: 700 мА; Диапазон рабочих температур: от -60 до +125 ℃; Упаковка: Катушка и лента; Типоразмер: 1608 (0603); Технология монтажа: SMT; Изготовитель: АО "НПО "ЭРКОН"
footprint КИК-1608_О (Катушка индуктивности с керамическим сердечником  типоразмер 1005(0402))
pins: 1, 2

## КИК-1608-3.9 нГн ±2% Зл
designator L?, comment 3.9 нГн ±2%  (value not drawn)
Катушка индуктивности с керамическим сердечником и золотым покрытием контактных площадок; Номиналиная индуктивность: 3.9 нГн; Добротность, не менее: 16; Резонансная частота, не менее: 6.90 ГГц; Сопротивление обмотки постоянноми току, не более: 0.080 Ом; Допустимый ток обмотки: 700 мА; Диапазон рабочих температур: от -60 до +125 ℃; Упаковка: Катушка и лента; Типоразмер: 1608 (0603); Технология монтажа: SMT; Изготовитель: АО "НПО "ЭРКОН"
footprint КИК-1608_Зл (Катушка индуктивности с керамическим сердечником  типоразмер 1005(0402))
pins: 1, 2

## КИК-1608-3.9 нГн ±5% O
designator L?, comment 3.9 нГн ±5%  (value not drawn)
Катушка индуктивности с керамическим сердечником и  финишным покрытием контактных площадок оловом; Номиналиная индуктивность: 3.9 нГн; Добротность, не менее: 16; Резонансная частота, не менее: 6.90 ГГц; Сопротивление обмотки постоянноми току, не более: 0.080 Ом; Допустимый ток обмотки: 700 мА; Диапазон рабочих температур: от -60 до +125 ℃; Упаковка: Катушка и лента; Типоразмер: 1608 (0603); Технология монтажа: SMT; Изготовитель: АО "НПО "ЭРКОН"
footprint КИК-1608_О (Катушка индуктивности с керамическим сердечником  типоразмер 1005(0402))
pins: 1, 2

## КИК-1608-3.9 нГн ±5% Зл
designator L?, comment 3.9 нГн ±5%  (value not drawn)
Катушка индуктивности с керамическим сердечником и золотым покрытием контактных площадок; Номиналиная индуктивность: 3.9 нГн; Добротность, не менее: 16; Резонансная частота, не менее: 6.90 ГГц; Сопротивление обмотки постоянноми току, не более: 0.080 Ом; Допустимый ток обмотки: 700 мА; Диапазон рабочих температур: от -60 до +125 ℃; Упаковка: Катушка и лента; Типоразмер: 1608 (0603); Технология монтажа: SMT; Изготовитель: АО "НПО "ЭРКОН"
footprint КИК-1608_Зл (Катушка индуктивности с керамическим сердечником  типоразмер 1005(0402))
pins: 1, 2

## КИК-1608-3.9 нГн ±10% O
designator L?, comment 3.9 нГн ±10%  (value not drawn)
Катушка индуктивности с керамическим сердечником и  финишным покрытием контактных площадок оловом; Номиналиная индуктивность: 3.9 нГн; Добротность, не менее: 16; Резонансная частота, не менее: 6.90 ГГц; Сопротивление обмотки постоянноми току, не более: 0.080 Ом; Допустимый ток обмотки: 700 мА; Диапазон рабочих температур: от -60 до +125 ℃; Упаковка: Катушка и лента; Типоразмер: 1608 (0603); Технология монтажа: SMT; Изготовитель: АО "НПО "ЭРКОН"
footprint КИК-1608_О (Катушка индуктивности с керамическим сердечником  типоразмер 1005(0402))
pins: 1, 2

## КИК-1608-3.9 нГн ±10% Зл
designator L?, comment 3.9 нГн ±10%  (value not drawn)
Катушка индуктивности с керамическим сердечником и золотым покрытием контактных площадок; Номиналиная индуктивность: 3.9 нГн; Добротность, не менее: 16; Резонансная частота, не менее: 6.90 ГГц; Сопротивление обмотки постоянноми току, не более: 0.080 Ом; Допустимый ток обмотки: 700 мА; Диапазон рабочих температур: от -60 до +125 ℃; Упаковка: Катушка и лента; Типоразмер: 1608 (0603); Технология монтажа: SMT; Изготовитель: АО "НПО "ЭРКОН"
footprint КИК-1608_Зл (Катушка индуктивности с керамическим сердечником  типоразмер 1005(0402))
pins: 1, 2


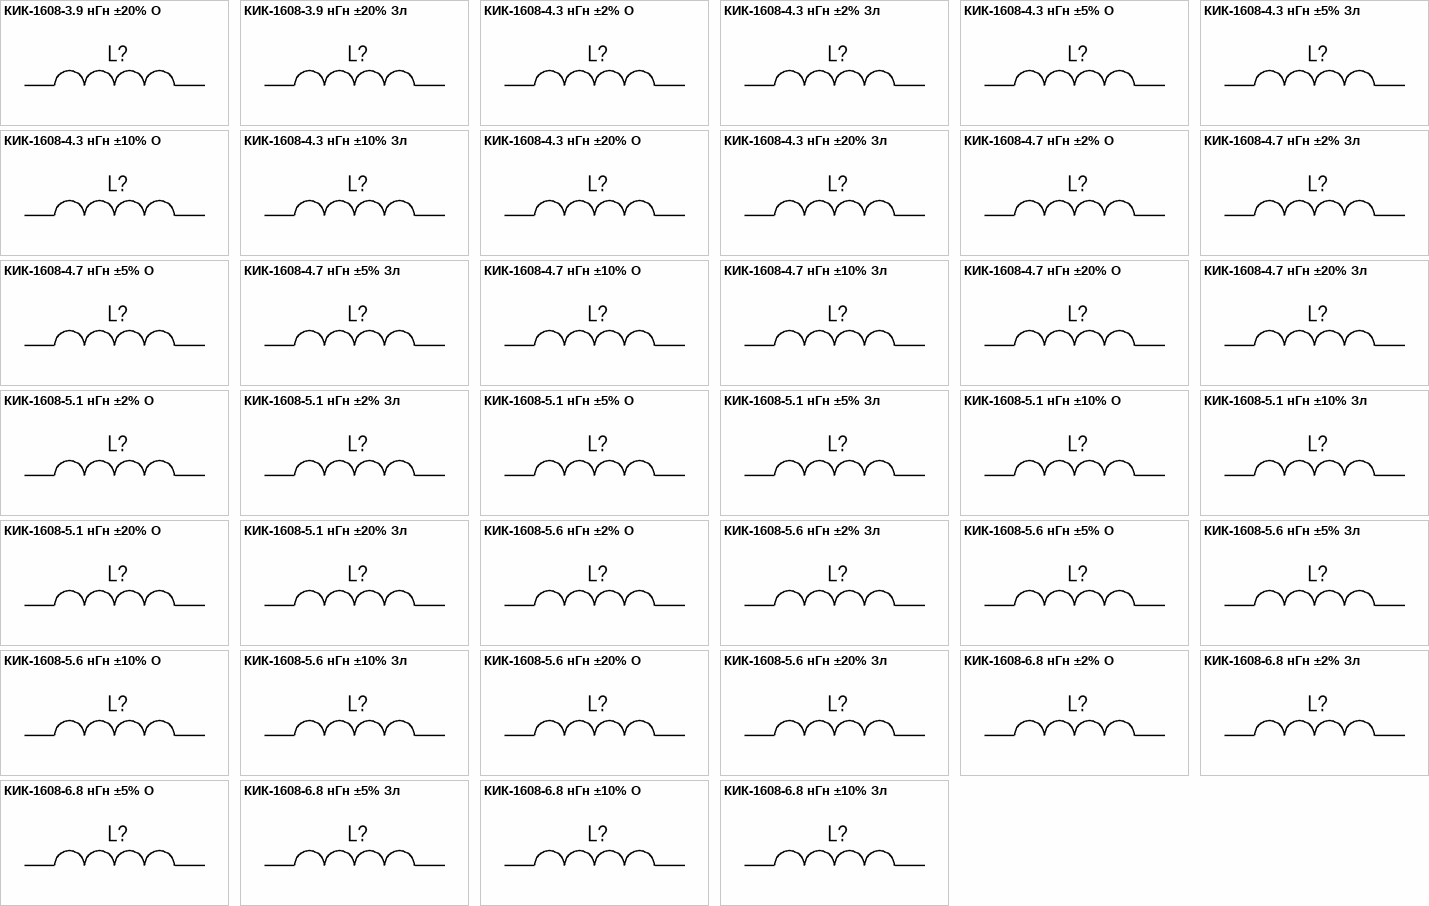
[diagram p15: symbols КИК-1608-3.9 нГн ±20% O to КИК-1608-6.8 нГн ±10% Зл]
## КИК-1608-3.9 нГн ±20% O
designator L?, comment 3.9 нГн ±20%  (value not drawn)
Катушка индуктивности с керамическим сердечником и  финишным покрытием контактных площадок оловом; Номиналиная индуктивность: 3.9 нГн; Добротность, не менее: 16; Резонансная частота, не менее: 6.90 ГГц; Сопротивление обмотки постоянноми току, не более: 0.080 Ом; Допустимый ток обмотки: 700 мА; Диапазон рабочих температур: от -60 до +125 ℃; Упаковка: Катушка и лента; Типоразмер: 1608 (0603); Технология монтажа: SMT; Изготовитель: АО "НПО "ЭРКОН"
footprint КИК-1608_О (Катушка индуктивности с керамическим сердечником  типоразмер 1005(0402))
pins: 1, 2

## КИК-1608-3.9 нГн ±20% Зл
designator L?, comment 3.9 нГн ±20%  (value not drawn)
Катушка индуктивности с керамическим сердечником и золотым покрытием контактных площадок; Номиналиная индуктивность: 3.9 нГн; Добротность, не менее: 16; Резонансная частота, не менее: 6.90 ГГц; Сопротивление обмотки постоянноми току, не более: 0.080 Ом; Допустимый ток обмотки: 700 мА; Диапазон рабочих температур: от -60 до +125 ℃; Упаковка: Катушка и лента; Типоразмер: 1608 (0603); Технология монтажа: SMT; Изготовитель: АО "НПО "ЭРКОН"
footprint КИК-1608_Зл (Катушка индуктивности с керамическим сердечником  типоразмер 1005(0402))
pins: 1, 2

## КИК-1608-4.3 нГн ±2% O
designator L?, comment 4.3 нГн ±2%  (value not drawn)
Катушка индуктивности с керамическим сердечником и  финишным покрытием контактных площадок оловом; Номиналиная индуктивность: 4.3 нГн; Допускаемое отклонение индуктивности: ±5%; Добротность, не менее: 16; Резонансная частота, не менее: 5.90 ГГц; Сопротивление обмотки постоянноми току, не более: 0.080 Ом; Допустимый ток обмотки: 700 мА; Диапазон рабочих температур: от -60 до +125 ℃; Упаковка: Катушка и лента; Типоразмер: 1608 (0603); Технология монтажа: SMT; Изготовитель: АО "НПО "ЭРКОН"
footprint КИК-1608_О (Катушка индуктивности с керамическим сердечником  типоразмер 1005(0402))
pins: 1, 2

## КИК-1608-4.3 нГн ±2% Зл
designator L?, comment 4.3 нГн ±2%  (value not drawn)
Катушка индуктивности с керамическим сердечником и золотым покрытием контактных площадок; Номиналиная индуктивность: 4.3 нГн; Допускаемое отклонение индуктивности: ±5%; Добротность, не менее: 16; Резонансная частота, не менее: 5.90 ГГц; Сопротивление обмотки постоянноми току, не более: 0.080 Ом; Допустимый ток обмотки: 700 мА; Диапазон рабочих температур: от -60 до +125 ℃; Упаковка: Катушка и лента; Типоразмер: 1608 (0603); Технология монтажа: SMT; Изготовитель: АО "НПО "ЭРКОН"
footprint КИК-1608_Зл (Катушка индуктивности с керамическим сердечником  типоразмер 1005(0402))
pins: 1, 2

## КИК-1608-4.3 нГн ±5% O
designator L?, comment 4.3 нГн ±5%  (value not drawn)
Катушка индуктивности с керамическим сердечником и  финишным покрытием контактных площадок оловом; Номиналиная индуктивность: 4.3 нГн; Добротность, не менее: 16; Резонансная частота, не менее: 5.90 ГГц; Сопротивление обмотки постоянноми току, не более: 0.080 Ом; Допустимый ток обмотки: 700 мА; Диапазон рабочих температур: от -60 до +125 ℃; Упаковка: Катушка и лента; Типоразмер: 1608 (0603); Технология монтажа: SMT; Изготовитель: АО "НПО "ЭРКОН"
footprint КИК-1608_О (Катушка индуктивности с керамическим сердечником  типоразмер 1005(0402))
pins: 1, 2

## КИК-1608-4.3 нГн ±5% Зл
designator L?, comment 4.3 нГн ±5%  (value not drawn)
Катушка индуктивности с керамическим сердечником и золотым покрытием контактных площадок; Номиналиная индуктивность: 4.3 нГн; Добротность, не менее: 16; Резонансная частота, не менее: 5.90 ГГц; Сопротивление обмотки постоянноми току, не более: 0.080 Ом; Допустимый ток обмотки: 700 мА; Диапазон рабочих температур: от -60 до +125 ℃; Упаковка: Катушка и лента; Типоразмер: 1608 (0603); Технология монтажа: SMT; Изготовитель: АО "НПО "ЭРКОН"
footprint КИК-1608_Зл (Катушка индуктивности с керамическим сердечником  типоразмер 1005(0402))
pins: 1, 2

## КИК-1608-4.3 нГн ±10% O
designator L?, comment 4.3 нГн ±10%  (value not drawn)
Катушка индуктивности с керамическим сердечником и  финишным покрытием контактных площадок оловом; Номиналиная индуктивность: 4.3 нГн; Добротность, не менее: 16; Резонансная частота, не менее: 5.90 ГГц; Сопротивление обмотки постоянноми току, не более: 0.080 Ом; Допустимый ток обмотки: 700 мА; Диапазон рабочих температур: от -60 до +125 ℃; Упаковка: Катушка и лента; Типоразмер: 1608 (0603); Технология монтажа: SMT; Изготовитель: АО "НПО "ЭРКОН"
footprint КИК-1608_О (Катушка индуктивности с керамическим сердечником  типоразмер 1005(0402))
pins: 1, 2

## КИК-1608-4.3 нГн ±10% Зл
designator L?, comment 4.3 нГн ±10%  (value not drawn)
Катушка индуктивности с керамическим сердечником и золотым покрытием контактных площадок; Номиналиная индуктивность: 4.3 нГн; Добротность, не менее: 16; Резонансная частота, не менее: 5.90 ГГц; Сопротивление обмотки постоянноми току, не более: 0.080 Ом; Допустимый ток обмотки: 700 мА; Диапазон рабочих температур: от -60 до +125 ℃; Упаковка: Катушка и лента; Типоразмер: 1608 (0603); Технология монтажа: SMT; Изготовитель: АО "НПО "ЭРКОН"
footprint КИК-1608_Зл (Катушка индуктивности с керамическим сердечником  типоразмер 1005(0402))
pins: 1, 2

## КИК-1608-4.3 нГн ±20% O
designator L?, comment 4.3 нГн ±20%  (value not drawn)
Катушка индуктивности с керамическим сердечником и  финишным покрытием контактных площадок оловом; Номиналиная индуктивность: 4.3 нГн; Добротность, не менее: 16; Резонансная частота, не менее: 5.90 ГГц; Сопротивление обмотки постоянноми току, не более: 0.080 Ом; Допустимый ток обмотки: 700 мА; Диапазон рабочих температур: от -60 до +125 ℃; Упаковка: Катушка и лента; Типоразмер: 1608 (0603); Технология монтажа: SMT; Изготовитель: АО "НПО "ЭРКОН"
footprint КИК-1608_О (Катушка индуктивности с керамическим сердечником  типоразмер 1005(0402))
pins: 1, 2

## КИК-1608-4.3 нГн ±20% Зл
designator L?, comment 4.3 нГн ±20%  (value not drawn)
Катушка индуктивности с керамическим сердечником и золотым покрытием контактных площадок; Номиналиная индуктивность: 4.3 нГн; Добротность, не менее: 16; Резонансная частота, не менее: 5.90 ГГц; Сопротивление обмотки постоянноми току, не более: 0.080 Ом; Допустимый ток обмотки: 700 мА; Диапазон рабочих температур: от -60 до +125 ℃; Упаковка: Катушка и лента; Типоразмер: 1608 (0603); Технология монтажа: SMT; Изготовитель: АО "НПО "ЭРКОН"
footprint КИК-1608_Зл (Катушка индуктивности с керамическим сердечником  типоразмер 1005(0402))
pins: 1, 2

## КИК-1608-4.7 нГн ±2% O
designator L?, comment 4.7 нГн ±2%  (value not drawn)
Катушка индуктивности с керамическим сердечником и  финишным покрытием контактных площадок оловом; Номиналиная индуктивность: 4.7 нГн; Добротность, не менее: 16; Резонансная частота, не менее: 5.80 ГГц; Сопротивление обмотки постоянноми току, не более: 0.116 Ом; Допустимый ток обмотки: 700 мА; Диапазон рабочих температур: от -60 до +125 ℃; Упаковка: Катушка и лента; Типоразмер: 1608 (0603); Технология монтажа: SMT; Изготовитель: АО "НПО "ЭРКОН"
footprint КИК-1608_О (Катушка индуктивности с керамическим сердечником  типоразмер 1005(0402))
pins: 1, 2

## КИК-1608-4.7 нГн ±2% Зл
designator L?, comment 4.7 нГн ±2%  (value not drawn)
Катушка индуктивности с керамическим сердечником и золотым покрытием контактных площадок; Номиналиная индуктивность: 4.7 нГн; Добротность, не менее: 16; Резонансная частота, не менее: 5.80 ГГц; Сопротивление обмотки постоянноми току, не более: 0.116 Ом; Допустимый ток обмотки: 700 мА; Диапазон рабочих температур: от -60 до +125 ℃; Упаковка: Катушка и лента; Типоразмер: 1608 (0603); Технология монтажа: SMT; Изготовитель: АО "НПО "ЭРКОН"
footprint КИК-1608_Зл (Катушка индуктивности с керамическим сердечником  типоразмер 1005(0402))
pins: 1, 2

## КИК-1608-4.7 нГн ±5% O
designator L?, comment 4.7 нГн ±5%  (value not drawn)
Катушка индуктивности с керамическим сердечником и  финишным покрытием контактных площадок оловом; Номиналиная индуктивность: 4.7 нГн; Добротность, не менее: 16; Резонансная частота, не менее: 5.80 ГГц; Сопротивление обмотки постоянноми току, не более: 0.116 Ом; Допустимый ток обмотки: 700 мА; Диапазон рабочих температур: от -60 до +125 ℃; Упаковка: Катушка и лента; Типоразмер: 1608 (0603); Технология монтажа: SMT; Изготовитель: АО "НПО "ЭРКОН"
footprint КИК-1608_О (Катушка индуктивности с керамическим сердечником  типоразмер 1005(0402))
pins: 1, 2

## КИК-1608-4.7 нГн ±5% Зл
designator L?, comment 4.7 нГн ±5%  (value not drawn)
Катушка индуктивности с керамическим сердечником и золотым покрытием контактных площадок; Номиналиная индуктивность: 4.7 нГн; Добротность, не менее: 16; Резонансная частота, не менее: 5.80 ГГц; Сопротивление обмотки постоянноми току, не более: 0.116 Ом; Допустимый ток обмотки: 700 мА; Диапазон рабочих температур: от -60 до +125 ℃; Упаковка: Катушка и лента; Типоразмер: 1608 (0603); Технология монтажа: SMT; Изготовитель: АО "НПО "ЭРКОН"
footprint КИК-1608_Зл (Катушка индуктивности с керамическим сердечником  типоразмер 1005(0402))
pins: 1, 2

## КИК-1608-4.7 нГн ±10% O
designator L?, comment 4.7 нГн ±10%  (value not drawn)
Катушка индуктивности с керамическим сердечником и  финишным покрытием контактных площадок оловом; Номиналиная индуктивность: 4.7 нГн; Добротность, не менее: 16; Резонансная частота, не менее: 5.80 ГГц; Сопротивление обмотки постоянноми току, не более: 0.116 Ом; Допустимый ток обмотки: 700 мА; Диапазон рабочих температур: от -60 до +125 ℃; Упаковка: Катушка и лента; Типоразмер: 1608 (0603); Технология монтажа: SMT; Изготовитель: АО "НПО "ЭРКОН"
footprint КИК-1608_О (Катушка индуктивности с керамическим сердечником  типоразмер 1005(0402))
pins: 1, 2

## КИК-1608-4.7 нГн ±10% Зл
designator L?, comment 4.7 нГн ±10%  (value not drawn)
Катушка индуктивности с керамическим сердечником и золотым покрытием контактных площадок; Номиналиная индуктивность: 4.7 нГн; Добротность, не менее: 16; Резонансная частота, не менее: 5.80 ГГц; Сопротивление обмотки постоянноми току, не более: 0.116 Ом; Допустимый ток обмотки: 700 мА; Диапазон рабочих температур: от -60 до +125 ℃; Упаковка: Катушка и лента; Типоразмер: 1608 (0603); Технология монтажа: SMT; Изготовитель: АО "НПО "ЭРКОН"
footprint КИК-1608_Зл (Катушка индуктивности с керамическим сердечником  типоразмер 1005(0402))
pins: 1, 2

## КИК-1608-4.7 нГн ±20% O
designator L?, comment 4.7 нГн ±20%  (value not drawn)
Катушка индуктивности с керамическим сердечником и  финишным покрытием контактных площадок оловом; Номиналиная индуктивность: 4.7 нГн; Добротность, не менее: 16; Резонансная частота, не менее: 5.80 ГГц; Сопротивление обмотки постоянноми току, не более: 0.116 Ом; Допустимый ток обмотки: 700 мА; Диапазон рабочих температур: от -60 до +125 ℃; Упаковка: Катушка и лента; Типоразмер: 1608 (0603); Технология монтажа: SMT; Изготовитель: АО "НПО "ЭРКОН"
footprint КИК-1608_О (Катушка индуктивности с керамическим сердечником  типоразмер 1005(0402))
pins: 1, 2

## КИК-1608-4.7 нГн ±20% Зл
designator L?, comment 4.7 нГн ±20%  (value not drawn)
Катушка индуктивности с керамическим сердечником и золотым покрытием контактных площадок; Номиналиная индуктивность: 4.7 нГн; Добротность, не менее: 16; Резонансная частота, не менее: 5.80 ГГц; Сопротивление обмотки постоянноми току, не более: 0.116 Ом; Допустимый ток обмотки: 700 мА; Диапазон рабочих температур: от -60 до +125 ℃; Упаковка: Катушка и лента; Типоразмер: 1608 (0603); Технология монтажа: SMT; Изготовитель: АО "НПО "ЭРКОН"
footprint КИК-1608_Зл (Катушка индуктивности с керамическим сердечником  типоразмер 1005(0402))
pins: 1, 2

## КИК-1608-5.1 нГн ±2% O
designator L?, comment 5.1 нГн ±2%  (value not drawn)
Катушка индуктивности с керамическим сердечником и  финишным покрытием контактных площадок оловом; Номиналиная индуктивность: 5.1 нГн; Добротность, не менее: 16; Резонансная частота, не менее: 5.70 ГГц; Сопротивление обмотки постоянноми току, не более: 0.140 Ом; Допустимый ток обмотки: 700 мА; Диапазон рабочих температур: от -60 до +125 ℃; Упаковка: Катушка и лента; Типоразмер: 1608 (0603); Технология монтажа: SMT; Изготовитель: АО "НПО "ЭРКОН"
footprint КИК-1608_О (Катушка индуктивности с керамическим сердечником  типоразмер 1005(0402))
pins: 1, 2

## КИК-1608-5.1 нГн ±2% Зл
designator L?, comment 5.1 нГн ±2%  (value not drawn)
Катушка индуктивности с керамическим сердечником и золотым покрытием контактных площадок; Номиналиная индуктивность: 5.1 нГн; Добротность, не менее: 16; Резонансная частота, не менее: 5.70 ГГц; Сопротивление обмотки постоянноми току, не более: 0.140 Ом; Допустимый ток обмотки: 700 мА; Диапазон рабочих температур: от -60 до +125 ℃; Упаковка: Катушка и лента; Типоразмер: 1608 (0603); Технология монтажа: SMT; Изготовитель: АО "НПО "ЭРКОН"
footprint КИК-1608_Зл (Катушка индуктивности с керамическим сердечником  типоразмер 1005(0402))
pins: 1, 2

## КИК-1608-5.1 нГн ±5% O
designator L?, comment 5.1 нГн ±5%  (value not drawn)
Катушка индуктивности с керамическим сердечником и  финишным покрытием контактных площадок оловом; Номиналиная индуктивность: 5.1 нГн; Добротность, не менее: 16; Резонансная частота, не менее: 5.70 ГГц; Сопротивление обмотки постоянноми току, не более: 0.140 Ом; Допустимый ток обмотки: 700 мА; Диапазон рабочих температур: от -60 до +125 ℃; Упаковка: Катушка и лента; Типоразмер: 1608 (0603); Технология монтажа: SMT; Изготовитель: АО "НПО "ЭРКОН"
footprint КИК-1608_О (Катушка индуктивности с керамическим сердечником  типоразмер 1005(0402))
pins: 1, 2

## КИК-1608-5.1 нГн ±5% Зл
designator L?, comment 5.1 нГн ±5%  (value not drawn)
Катушка индуктивности с керамическим сердечником и золотым покрытием контактных площадок; Номиналиная индуктивность: 5.1 нГн; Добротность, не менее: 16; Резонансная частота, не менее: 5.70 ГГц; Сопротивление обмотки постоянноми току, не более: 0.140 Ом; Допустимый ток обмотки: 700 мА; Диапазон рабочих температур: от -60 до +125 ℃; Упаковка: Катушка и лента; Типоразмер: 1608 (0603); Технология монтажа: SMT; Изготовитель: АО "НПО "ЭРКОН"
footprint КИК-1608_Зл (Катушка индуктивности с керамическим сердечником  типоразмер 1005(0402))
pins: 1, 2

## КИК-1608-5.1 нГн ±10% O
designator L?, comment 5.1 нГн ±10%  (value not drawn)
Катушка индуктивности с керамическим сердечником и  финишным покрытием контактных площадок оловом; Номиналиная индуктивность: 5.1 нГн; Добротность, не менее: 16; Резонансная частота, не менее: 5.70 ГГц; Сопротивление обмотки постоянноми току, не более: 0.140 Ом; Допустимый ток обмотки: 700 мА; Диапазон рабочих температур: от -60 до +125 ℃; Упаковка: Катушка и лента; Типоразмер: 1608 (0603); Технология монтажа: SMT; Изготовитель: АО "НПО "ЭРКОН"
footprint КИК-1608_О (Катушка индуктивности с керамическим сердечником  типоразмер 1005(0402))
pins: 1, 2

## КИК-1608-5.1 нГн ±10% Зл
designator L?, comment 5.1 нГн ±10%  (value not drawn)
Катушка индуктивности с керамическим сердечником и золотым покрытием контактных площадок; Номиналиная индуктивность: 5.1 нГн; Добротность, не менее: 16; Резонансная частота, не менее: 5.70 ГГц; Сопротивление обмотки постоянноми току, не более: 0.140 Ом; Допустимый ток обмотки: 700 мА; Диапазон рабочих температур: от -60 до +125 ℃; Упаковка: Катушка и лента; Типоразмер: 1608 (0603); Технология монтажа: SMT; Изготовитель: АО "НПО "ЭРКОН"
footprint КИК-1608_Зл (Катушка индуктивности с керамическим сердечником  типоразмер 1005(0402))
pins: 1, 2

## КИК-1608-5.1 нГн ±20% O
designator L?, comment 5.1 нГн ±20%  (value not drawn)
Катушка индуктивности с керамическим сердечником и  финишным покрытием контактных площадок оловом; Номиналиная индуктивность: 5.1 нГн; Добротность, не менее: 16; Резонансная частота, не менее: 5.70 ГГц; Сопротивление обмотки постоянноми току, не более: 0.140 Ом; Допустимый ток обмотки: 700 мА; Диапазон рабочих температур: от -60 до +125 ℃; Упаковка: Катушка и лента; Типоразмер: 1608 (0603); Технология монтажа: SMT; Изготовитель: АО "НПО "ЭРКОН"
footprint КИК-1608_О (Катушка индуктивности с керамическим сердечником  типоразмер 1005(0402))
pins: 1, 2

## КИК-1608-5.1 нГн ±20% Зл
designator L?, comment 5.1 нГн ±20%  (value not drawn)
Катушка индуктивности с керамическим сердечником и золотым покрытием контактных площадок; Номиналиная индуктивность: 5.1 нГн; Добротность, не менее: 16; Резонансная частота, не менее: 5.70 ГГц; Сопротивление обмотки постоянноми току, не более: 0.140 Ом; Допустимый ток обмотки: 700 мА; Диапазон рабочих температур: от -60 до +125 ℃; Упаковка: Катушка и лента; Типоразмер: 1608 (0603); Технология монтажа: SMT; Изготовитель: АО "НПО "ЭРКОН"
footprint КИК-1608_Зл (Катушка индуктивности с керамическим сердечником  типоразмер 1005(0402))
pins: 1, 2

## КИК-1608-5.6 нГн ±2% O
designator L?, comment 5.6 нГн ±2%  (value not drawn)
Катушка индуктивности с керамическим сердечником и  финишным покрытием контактных площадок оловом; Номиналиная индуктивность: 5.6 нГн; Добротность, не менее: 25; Резонансная частота, не менее: 4.76 ГГц; Сопротивление обмотки постоянноми току, не более: 0.145 Ом; Допустимый ток обмотки: 700 мА; Диапазон рабочих температур: от -60 до +125 ℃; Упаковка: Катушка и лента; Типоразмер: 1608 (0603); Технология монтажа: SMT; Изготовитель: АО "НПО "ЭРКОН"
footprint КИК-1608_О (Катушка индуктивности с керамическим сердечником  типоразмер 1005(0402))
pins: 1, 2

## КИК-1608-5.6 нГн ±2% Зл
designator L?, comment 5.6 нГн ±2%  (value not drawn)
Катушка индуктивности с керамическим сердечником и золотым покрытием контактных площадок; Номиналиная индуктивность: 5.6 нГн; Добротность, не менее: 25; Резонансная частота, не менее: 4.76 ГГц; Сопротивление обмотки постоянноми току, не более: 0.145 Ом; Допустимый ток обмотки: 700 мА; Диапазон рабочих температур: от -60 до +125 ℃; Упаковка: Катушка и лента; Типоразмер: 1608 (0603); Технология монтажа: SMT; Изготовитель: АО "НПО "ЭРКОН"
footprint КИК-1608_Зл (Катушка индуктивности с керамическим сердечником  типоразмер 1005(0402))
pins: 1, 2

## КИК-1608-5.6 нГн ±5% O
designator L?, comment 5.6 нГн ±5%  (value not drawn)
Катушка индуктивности с керамическим сердечником и  финишным покрытием контактных площадок оловом; Номиналиная индуктивность: 5.6 нГн; Добротность, не менее: 25; Резонансная частота, не менее: 4.76 ГГц; Сопротивление обмотки постоянноми току, не более: 0.145 Ом; Допустимый ток обмотки: 700 мА; Диапазон рабочих температур: от -60 до +125 ℃; Упаковка: Катушка и лента; Типоразмер: 1608 (0603); Технология монтажа: SMT; Изготовитель: АО "НПО "ЭРКОН"
footprint КИК-1608_О (Катушка индуктивности с керамическим сердечником  типоразмер 1005(0402))
pins: 1, 2

## КИК-1608-5.6 нГн ±5% Зл
designator L?, comment 5.6 нГн ±5%  (value not drawn)
Катушка индуктивности с керамическим сердечником и золотым покрытием контактных площадок; Номиналиная индуктивность: 5.6 нГн; Добротность, не менее: 25; Резонансная частота, не менее: 4.76 ГГц; Сопротивление обмотки постоянноми току, не более: 0.145 Ом; Допустимый ток обмотки: 700 мА; Диапазон рабочих температур: от -60 до +125 ℃; Упаковка: Катушка и лента; Типоразмер: 1608 (0603); Технология монтажа: SMT; Изготовитель: АО "НПО "ЭРКОН"
footprint КИК-1608_Зл (Катушка индуктивности с керамическим сердечником  типоразмер 1005(0402))
pins: 1, 2

## КИК-1608-5.6 нГн ±10% O
designator L?, comment 5.6 нГн ±10%  (value not drawn)
Катушка индуктивности с керамическим сердечником и  финишным покрытием контактных площадок оловом; Номиналиная индуктивность: 5.6 нГн; Добротность, не менее: 25; Резонансная частота, не менее: 4.76 ГГц; Сопротивление обмотки постоянноми току, не более: 0.145 Ом; Допустимый ток обмотки: 700 мА; Диапазон рабочих температур: от -60 до +125 ℃; Упаковка: Катушка и лента; Типоразмер: 1608 (0603); Технология монтажа: SMT; Изготовитель: АО "НПО "ЭРКОН"
footprint КИК-1608_О (Катушка индуктивности с керамическим сердечником  типоразмер 1005(0402))
pins: 1, 2

## КИК-1608-5.6 нГн ±10% Зл
designator L?, comment 5.6 нГн ±10%  (value not drawn)
Катушка индуктивности с керамическим сердечником и золотым покрытием контактных площадок; Номиналиная индуктивность: 5.6 нГн; Добротность, не менее: 25; Резонансная частота, не менее: 4.76 ГГц; Сопротивление обмотки постоянноми току, не более: 0.145 Ом; Допустимый ток обмотки: 700 мА; Диапазон рабочих температур: от -60 до +125 ℃; Упаковка: Катушка и лента; Типоразмер: 1608 (0603); Технология монтажа: SMT; Изготовитель: АО "НПО "ЭРКОН"
footprint КИК-1608_Зл (Катушка индуктивности с керамическим сердечником  типоразмер 1005(0402))
pins: 1, 2

## КИК-1608-5.6 нГн ±20% O
designator L?, comment 5.6 нГн ±20%  (value not drawn)
Катушка индуктивности с керамическим сердечником и  финишным покрытием контактных площадок оловом; Номиналиная индуктивность: 5.6 нГн; Добротность, не менее: 25; Резонансная частота, не менее: 4.76 ГГц; Сопротивление обмотки постоянноми току, не более: 0.145 Ом; Допустимый ток обмотки: 700 мА; Диапазон рабочих температур: от -60 до +125 ℃; Упаковка: Катушка и лента; Типоразмер: 1608 (0603); Технология монтажа: SMT; Изготовитель: АО "НПО "ЭРКОН"
footprint КИК-1608_О (Катушка индуктивности с керамическим сердечником  типоразмер 1005(0402))
pins: 1, 2

## КИК-1608-5.6 нГн ±20% Зл
designator L?, comment 5.6 нГн ±20%  (value not drawn)
Катушка индуктивности с керамическим сердечником и золотым покрытием контактных площадок; Номиналиная индуктивность: 5.6 нГн; Добротность, не менее: 25; Резонансная частота, не менее: 4.76 ГГц; Сопротивление обмотки постоянноми току, не более: 0.145 Ом; Допустимый ток обмотки: 700 мА; Диапазон рабочих температур: от -60 до +125 ℃; Упаковка: Катушка и лента; Типоразмер: 1608 (0603); Технология монтажа: SMT; Изготовитель: АО "НПО "ЭРКОН"
footprint КИК-1608_Зл (Катушка индуктивности с керамическим сердечником  типоразмер 1005(0402))
pins: 1, 2

## КИК-1608-6.8 нГн ±2% O
designator L?, comment 6.8 нГн ±2%  (value not drawn)
Катушка индуктивности с керамическим сердечником и  финишным покрытием контактных площадок оловом; Номиналиная индуктивность: 6.8 нГн; Добротность, не менее: 25; Резонансная частота, не менее: 5.80 ГГц; Сопротивление обмотки постоянноми току, не более: 0.110 Ом; Допустимый ток обмотки: 700 мА; Диапазон рабочих температур: от -60 до +125 ℃; Упаковка: Катушка и лента; Типоразмер: 1608 (0603); Технология монтажа: SMT; Изготовитель: АО "НПО "ЭРКОН"
footprint КИК-1608_О (Катушка индуктивности с керамическим сердечником  типоразмер 1005(0402))
pins: 1, 2

## КИК-1608-6.8 нГн ±2% Зл
designator L?, comment 6.8 нГн ±2%  (value not drawn)
Катушка индуктивности с керамическим сердечником и золотым покрытием контактных площадок; Номиналиная индуктивность: 6.8 нГн; Добротность, не менее: 25; Резонансная частота, не менее: 5.80 ГГц; Сопротивление обмотки постоянноми току, не более: 0.110 Ом; Допустимый ток обмотки: 700 мА; Диапазон рабочих температур: от -60 до +125 ℃; Упаковка: Катушка и лента; Типоразмер: 1608 (0603); Технология монтажа: SMT; Изготовитель: АО "НПО "ЭРКОН"
footprint КИК-1608_Зл (Катушка индуктивности с керамическим сердечником  типоразмер 1005(0402))
pins: 1, 2

## КИК-1608-6.8 нГн ±5% O
designator L?, comment 6.8 нГн ±5%  (value not drawn)
Катушка индуктивности с керамическим сердечником и  финишным покрытием контактных площадок оловом; Номиналиная индуктивность: 6.8 нГн; Добротность, не менее: 25; Резонансная частота, не менее: 5.80 ГГц; Сопротивление обмотки постоянноми току, не более: 0.110 Ом; Допустимый ток обмотки: 700 мА; Диапазон рабочих температур: от -60 до +125 ℃; Упаковка: Катушка и лента; Типоразмер: 1608 (0603); Технология монтажа: SMT; Изготовитель: АО "НПО "ЭРКОН"
footprint КИК-1608_О (Катушка индуктивности с керамическим сердечником  типоразмер 1005(0402))
pins: 1, 2

## КИК-1608-6.8 нГн ±5% Зл
designator L?, comment 6.8 нГн ±5%  (value not drawn)
Катушка индуктивности с керамическим сердечником и золотым покрытием контактных площадок; Номиналиная индуктивность: 6.8 нГн; Добротность, не менее: 25; Резонансная частота, не менее: 5.80 ГГц; Сопротивление обмотки постоянноми току, не более: 0.110 Ом; Допустимый ток обмотки: 700 мА; Диапазон рабочих температур: от -60 до +125 ℃; Упаковка: Катушка и лента; Типоразмер: 1608 (0603); Технология монтажа: SMT; Изготовитель: АО "НПО "ЭРКОН"
footprint КИК-1608_Зл (Катушка индуктивности с керамическим сердечником  типоразмер 1005(0402))
pins: 1, 2

## КИК-1608-6.8 нГн ±10% O
designator L?, comment 6.8 нГн ±10%  (value not drawn)
Катушка индуктивности с керамическим сердечником и  финишным покрытием контактных площадок оловом; Номиналиная индуктивность: 6.8 нГн; Добротность, не менее: 25; Резонансная частота, не менее: 5.80 ГГц; Сопротивление обмотки постоянноми току, не более: 0.110 Ом; Допустимый ток обмотки: 700 мА; Диапазон рабочих температур: от -60 до +125 ℃; Упаковка: Катушка и лента; Типоразмер: 1608 (0603); Технология монтажа: SMT; Изготовитель: АО "НПО "ЭРКОН"
footprint КИК-1608_О (Катушка индуктивности с керамическим сердечником  типоразмер 1005(0402))
pins: 1, 2

## КИК-1608-6.8 нГн ±10% Зл
designator L?, comment 6.8 нГн ±10%  (value not drawn)
Катушка индуктивности с керамическим сердечником и золотым покрытием контактных площадок; Номиналиная индуктивность: 6.8 нГн; Добротность, не менее: 25; Резонансная частота, не менее: 5.80 ГГц; Сопротивление обмотки постоянноми току, не более: 0.110 Ом; Допустимый ток обмотки: 700 мА; Диапазон рабочих температур: от -60 до +125 ℃; Упаковка: Катушка и лента; Типоразмер: 1608 (0603); Технология монтажа: SMT; Изготовитель: АО "НПО "ЭРКОН"
footprint КИК-1608_Зл (Катушка индуктивности с керамическим сердечником  типоразмер 1005(0402))
pins: 1, 2


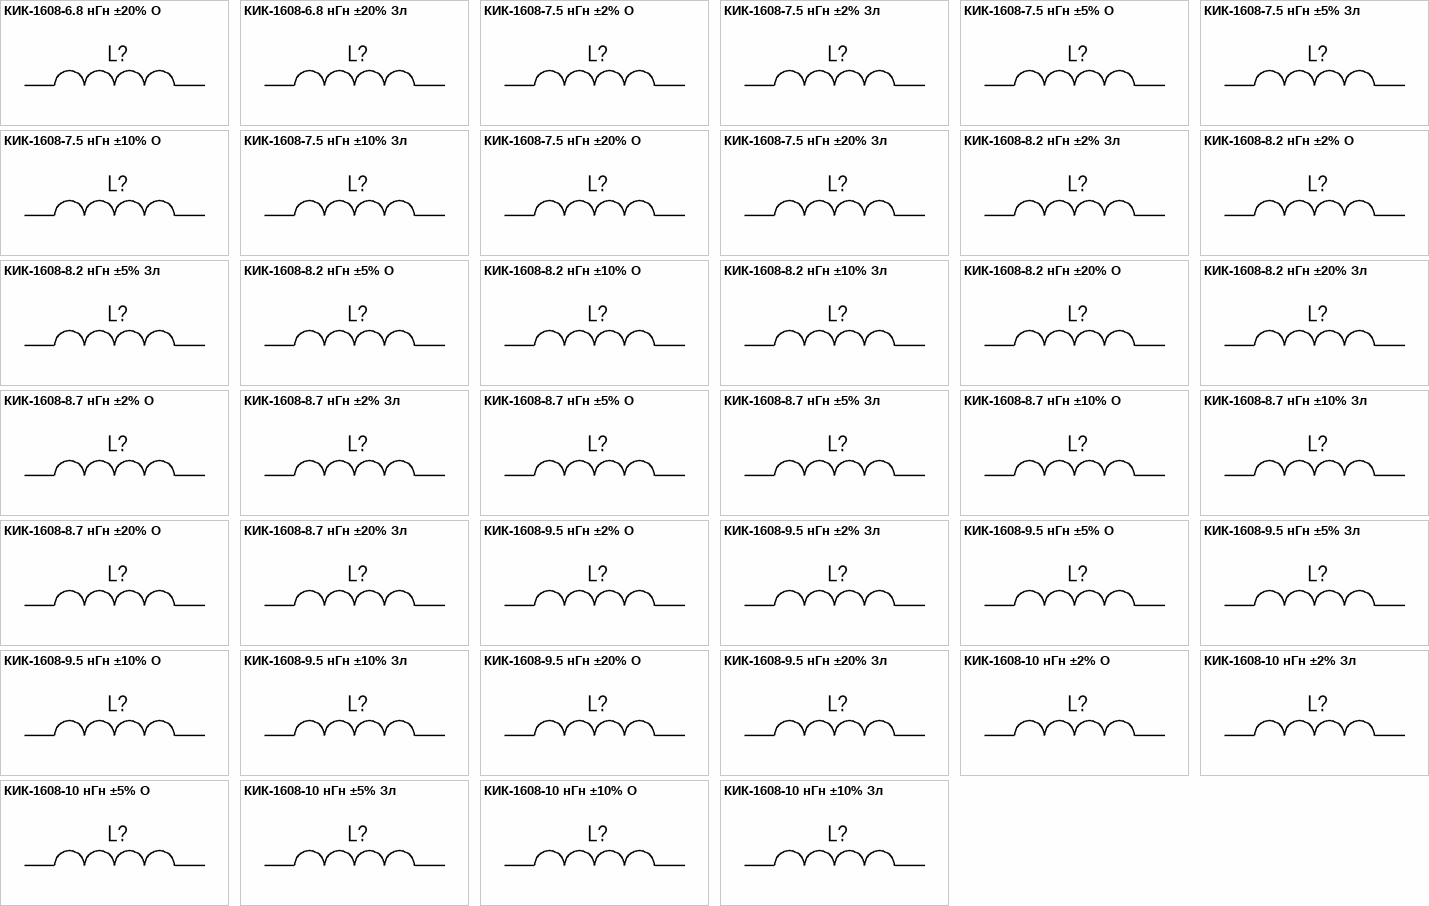
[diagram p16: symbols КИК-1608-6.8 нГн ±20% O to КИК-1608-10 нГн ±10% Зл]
## КИК-1608-6.8 нГн ±20% O
designator L?, comment 6.8 нГн ±20%  (value not drawn)
Катушка индуктивности с керамическим сердечником и  финишным покрытием контактных площадок оловом; Номиналиная индуктивность: 6.8 нГн; Добротность, не менее: 25; Резонансная частота, не менее: 5.80 ГГц; Сопротивление обмотки постоянноми току, не более: 0.110 Ом; Допустимый ток обмотки: 700 мА; Диапазон рабочих температур: от -60 до +125 ℃; Упаковка: Катушка и лента; Типоразмер: 1608 (0603); Технология монтажа: SMT; Изготовитель: АО "НПО "ЭРКОН"
footprint КИК-1608_О (Катушка индуктивности с керамическим сердечником  типоразмер 1005(0402))
pins: 1, 2

## КИК-1608-6.8 нГн ±20% Зл
designator L?, comment 6.8 нГн ±20%  (value not drawn)
Катушка индуктивности с керамическим сердечником и золотым покрытием контактных площадок; Номиналиная индуктивность: 6.8 нГн; Добротность, не менее: 25; Резонансная частота, не менее: 5.80 ГГц; Сопротивление обмотки постоянноми току, не более: 0.110 Ом; Допустимый ток обмотки: 700 мА; Диапазон рабочих температур: от -60 до +125 ℃; Упаковка: Катушка и лента; Типоразмер: 1608 (0603); Технология монтажа: SMT; Изготовитель: АО "НПО "ЭРКОН"
footprint КИК-1608_Зл (Катушка индуктивности с керамическим сердечником  типоразмер 1005(0402))
pins: 1, 2

## КИК-1608-7.5 нГн ±2% O
designator L?, comment 7.5 нГн ±2%  (value not drawn)
Катушка индуктивности с керамическим сердечником и  финишным покрытием контактных площадок оловом; Номиналиная индуктивность: 7.5 нГн; Добротность, не менее: 25; Резонансная частота, не менее: 4.80 ГГц; Сопротивление обмотки постоянноми току, не более: 0.110 Ом; Допустимый ток обмотки: 700 мА; Диапазон рабочих температур: от -60 до +125 ℃; Упаковка: Катушка и лента; Типоразмер: 1608 (0603); Технология монтажа: SMT; Изготовитель: АО "НПО "ЭРКОН"
footprint КИК-1608_О (Катушка индуктивности с керамическим сердечником  типоразмер 1005(0402))
pins: 1, 2

## КИК-1608-7.5 нГн ±2% Зл
designator L?, comment 7.5 нГн ±2%  (value not drawn)
Катушка индуктивности с керамическим сердечником и  золотым покрытием контактных площадок; Номиналиная индуктивность: 7.5 нГн; Добротность, не менее: 25; Резонансная частота, не менее: 4.80 ГГц; Сопротивление обмотки постоянноми току, не более: 0.110 Ом; Допустимый ток обмотки: 700 мА; Диапазон рабочих температур: от -60 до +125 ℃; Упаковка: Катушка и лента; Типоразмер: 1608 (0603); Технология монтажа: SMT; Изготовитель: АО "НПО "ЭРКОН"
footprint КИК-1608_О (Катушка индуктивности с керамическим сердечником  типоразмер 1005(0402))
pins: 1, 2

## КИК-1608-7.5 нГн ±5% O
designator L?, comment 7.5 нГн ±5%  (value not drawn)
Катушка индуктивности с керамическим сердечником и  финишным покрытием контактных площадок оловом; Номиналиная индуктивность: 7.5 нГн; Добротность, не менее: 25; Резонансная частота, не менее: 4.80 ГГц; Сопротивление обмотки постоянноми току, не более: 0.110 Ом; Допустимый ток обмотки: 700 мА; Диапазон рабочих температур: от -60 до +125 ℃; Упаковка: Катушка и лента; Типоразмер: 1608 (0603); Технология монтажа: SMT; Изготовитель: АО "НПО "ЭРКОН"
footprint КИК-1608_О (Катушка индуктивности с керамическим сердечником  типоразмер 1005(0402))
pins: 1, 2

## КИК-1608-7.5 нГн ±5% Зл
designator L?, comment 7.5 нГн ±5%  (value not drawn)
Катушка индуктивности с керамическим сердечником и  золотым покрытием контактных площадок; Номиналиная индуктивность: 7.5 нГн; Добротность, не менее: 25; Резонансная частота, не менее: 4.80 ГГц; Сопротивление обмотки постоянноми току, не более: 0.110 Ом; Допустимый ток обмотки: 700 мА; Диапазон рабочих температур: от -60 до +125 ℃; Упаковка: Катушка и лента; Типоразмер: 1608 (0603); Технология монтажа: SMT; Изготовитель: АО "НПО "ЭРКОН"
footprint КИК-1608_О (Катушка индуктивности с керамическим сердечником  типоразмер 1005(0402))
pins: 1, 2

## КИК-1608-7.5 нГн ±10% O
designator L?, comment 7.5 нГн ±10%  (value not drawn)
Катушка индуктивности с керамическим сердечником и  финишным покрытием контактных площадок оловом; Номиналиная индуктивность: 7.5 нГн; Добротность, не менее: 25; Резонансная частота, не менее: 4.80 ГГц; Сопротивление обмотки постоянноми току, не более: 0.110 Ом; Допустимый ток обмотки: 700 мА; Диапазон рабочих температур: от -60 до +125 ℃; Упаковка: Катушка и лента; Типоразмер: 1608 (0603); Технология монтажа: SMT; Изготовитель: АО "НПО "ЭРКОН"
footprint КИК-1608_О (Катушка индуктивности с керамическим сердечником  типоразмер 1005(0402))
pins: 1, 2

## КИК-1608-7.5 нГн ±10% Зл
designator L?, comment 7.5 нГн ±10%  (value not drawn)
Катушка индуктивности с керамическим сердечником и золотым покрытием контактных площадок; Номиналиная индуктивность: 7.5 нГн; Добротность, не менее: 25; Резонансная частота, не менее: 4.80 ГГц; Сопротивление обмотки постоянноми току, не более: 0.110 Ом; Допустимый ток обмотки: 700 мА; Диапазон рабочих температур: от -60 до +125 ℃; Упаковка: Катушка и лента; Типоразмер: 1608 (0603); Технология монтажа: SMT; Изготовитель: АО "НПО "ЭРКОН"
footprint КИК-1608_Зл (Катушка индуктивности с керамическим сердечником  типоразмер 1005(0402))
pins: 1, 2

## КИК-1608-7.5 нГн ±20% O
designator L?, comment 7.5 нГн ±20%  (value not drawn)
Катушка индуктивности с керамическим сердечником и  финишным покрытием контактных площадок оловом; Номиналиная индуктивность: 7.5 нГн; Добротность, не менее: 25; Резонансная частота, не менее: 4.80 ГГц; Сопротивление обмотки постоянноми току, не более: 0.110 Ом; Допустимый ток обмотки: 700 мА; Диапазон рабочих температур: от -60 до +125 ℃; Упаковка: Катушка и лента; Типоразмер: 1608 (0603); Технология монтажа: SMT; Изготовитель: АО "НПО "ЭРКОН"
footprint КИК-1608_О (Катушка индуктивности с керамическим сердечником  типоразмер 1005(0402))
pins: 1, 2

## КИК-1608-7.5 нГн ±20% Зл
designator L?, comment 7.5 нГн ±20%  (value not drawn)
Катушка индуктивности с керамическим сердечником и золотым покрытием контактных площадок; Номиналиная индуктивность: 7.5 нГн; Добротность, не менее: 25; Резонансная частота, не менее: 4.80 ГГц; Сопротивление обмотки постоянноми току, не более: 0.110 Ом; Допустимый ток обмотки: 700 мА; Диапазон рабочих температур: от -60 до +125 ℃; Упаковка: Катушка и лента; Типоразмер: 1608 (0603); Технология монтажа: SMT; Изготовитель: АО "НПО "ЭРКОН"
footprint КИК-1608_Зл (Катушка индуктивности с керамическим сердечником  типоразмер 1005(0402))
pins: 1, 2

## КИК-1608-8.2 нГн ±2% Зл
designator L?, comment 8.2 нГн ±2%  (value not drawn)
Катушка индуктивности с керамическим сердечником и золотым покрытием контактных площадок; Номиналиная индуктивность: 8.2 нГн; Добротность, не менее: 30; Резонансная частота, не менее: 4.20 ГГц; Сопротивление обмотки постоянноми току, не более: 0.115 Ом; Допустимый ток обмотки: 700 мА; Диапазон рабочих температур: от -60 до +125 ℃; Упаковка: Катушка и лента; Типоразмер: 1608 (0603); Технология монтажа: SMT; Изготовитель: АО "НПО "ЭРКОН"
footprint КИК-1608_Зл (Катушка индуктивности с керамическим сердечником  типоразмер 1005(0402))
pins: 1, 2

## КИК-1608-8.2 нГн ±2% О
designator L?, comment 8.2 нГн ±2%  (value not drawn)
Катушка индуктивности с керамическим сердечником и  финишным покрытием контактных площадок оловом; Номиналиная индуктивность: 8.2 нГн; Добротность, не менее: 30; Резонансная частота, не менее: 4.20 ГГц; Сопротивление обмотки постоянноми току, не более: 0.115 Ом; Допустимый ток обмотки: 700 мА; Диапазон рабочих температур: от -60 до +125 ℃; Упаковка: Катушка и лента; Типоразмер: 1608 (0603); Технология монтажа: SMT; Изготовитель: АО "НПО "ЭРКОН"
footprint КИК-1608_О (Катушка индуктивности с керамическим сердечником  типоразмер 1005(0402))
pins: 1, 2

## КИК-1608-8.2 нГн ±5% Зл
designator L?, comment 8.2 нГн ±5%  (value not drawn)
Катушка индуктивности с керамическим сердечником и золотым покрытием контактных площадок; Номиналиная индуктивность: 8.2 нГн; Добротность, не менее: 30; Резонансная частота, не менее: 4.20 ГГц; Сопротивление обмотки постоянноми току, не более: 0.115 Ом; Допустимый ток обмотки: 700 мА; Диапазон рабочих температур: от -60 до +125 ℃; Упаковка: Катушка и лента; Типоразмер: 1608 (0603); Технология монтажа: SMT; Изготовитель: АО "НПО "ЭРКОН"
footprint КИК-1608_Зл (Катушка индуктивности с керамическим сердечником  типоразмер 1005(0402))
pins: 1, 2

## КИК-1608-8.2 нГн ±5% О
designator L?, comment 8.2 нГн ±5%  (value not drawn)
Катушка индуктивности с керамическим сердечником и  финишным покрытием контактных площадок оловом; Номиналиная индуктивность: 8.2 нГн; Добротность, не менее: 30; Резонансная частота, не менее: 4.20 ГГц; Сопротивление обмотки постоянноми току, не более: 0.115 Ом; Допустимый ток обмотки: 700 мА; Диапазон рабочих температур: от -60 до +125 ℃; Упаковка: Катушка и лента; Типоразмер: 1608 (0603); Технология монтажа: SMT; Изготовитель: АО "НПО "ЭРКОН"
footprint КИК-1608_О (Катушка индуктивности с керамическим сердечником  типоразмер 1005(0402))
pins: 1, 2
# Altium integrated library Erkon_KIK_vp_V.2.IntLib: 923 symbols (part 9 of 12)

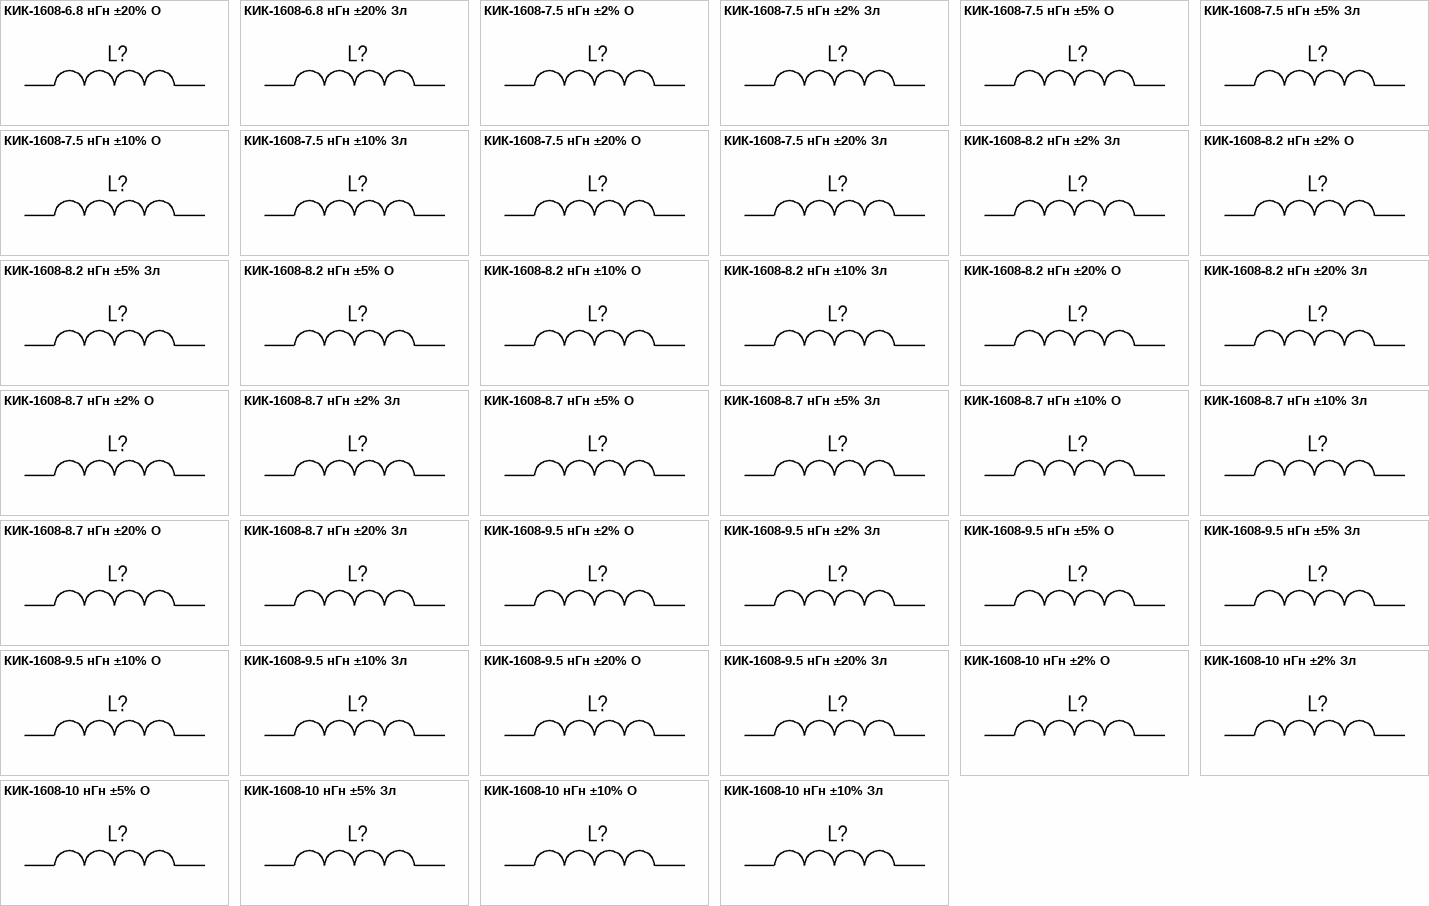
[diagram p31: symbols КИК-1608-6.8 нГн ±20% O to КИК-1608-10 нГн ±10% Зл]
## КИК-1608-8.2 нГн ±10% O
designator L?, comment 8.2 нГн ±10%  (value not drawn)
Катушка индуктивности с керамическим сердечником и  финишным покрытием контактных площадок оловом; Номиналиная индуктивность: 8.2 нГн; Добротность, не менее: 30; Резонансная частота, не менее: 4.20 ГГц; Сопротивление обмотки постоянноми току, не более: 0.115 Ом; Допустимый ток обмотки: 700 мА; Диапазон рабочих температур: от -60 до +125 ℃; Упаковка: Катушка и лента; Типоразмер: 1608 (0603); Технология монтажа: SMT; Изготовитель: АО "НПО "ЭРКОН"
footprint КИК-1608_О (Катушка индуктивности с керамическим сердечником  типоразмер 1005(0402))
pins: 1, 2

## КИК-1608-8.2 нГн ±10% Зл
designator L?, comment 8.2 нГн ±10%  (value not drawn)
Катушка индуктивности с керамическим сердечником и золотым покрытием контактных площадок; Номиналиная индуктивность: 8.2 нГн; Добротность, не менее: 30; Резонансная частота, не менее: 4.20 ГГц; Сопротивление обмотки постоянноми току, не более: 0.115 Ом; Допустимый ток обмотки: 700 мА; Диапазон рабочих температур: от -60 до +125 ℃; Упаковка: Катушка и лента; Типоразмер: 1608 (0603); Технология монтажа: SMT; Изготовитель: АО "НПО "ЭРКОН"
footprint КИК-1608_Зл (Катушка индуктивности с керамическим сердечником  типоразмер 1005(0402))
pins: 1, 2

## КИК-1608-8.2 нГн ±20% O
designator L?, comment 8.2 нГн ±20%  (value not drawn)
Катушка индуктивности с керамическим сердечником и  финишным покрытием контактных площадок оловом; Номиналиная индуктивность: 8.2 нГн; Добротность, не менее: 30; Резонансная частота, не менее: 4.20 ГГц; Сопротивление обмотки постоянноми току, не более: 0.115 Ом; Допустимый ток обмотки: 700 мА; Диапазон рабочих температур: от -60 до +125 ℃; Упаковка: Катушка и лента; Типоразмер: 1608 (0603); Технология монтажа: SMT; Изготовитель: АО "НПО "ЭРКОН"
footprint КИК-1608_О (Катушка индуктивности с керамическим сердечником  типоразмер 1005(0402))
pins: 1, 2

## КИК-1608-8.2 нГн ±20% Зл
designator L?, comment 8.2 нГн ±20%  (value not drawn)
Катушка индуктивности с керамическим сердечником и золотым покрытием контактных площадок; Номиналиная индуктивность: 8.2 нГн; Добротность, не менее: 30; Резонансная частота, не менее: 4.20 ГГц; Сопротивление обмотки постоянноми току, не более: 0.115 Ом; Допустимый ток обмотки: 700 мА; Диапазон рабочих температур: от -60 до +125 ℃; Упаковка: Катушка и лента; Типоразмер: 1608 (0603); Технология монтажа: SMT; Изготовитель: АО "НПО "ЭРКОН"
footprint КИК-1608_Зл (Катушка индуктивности с керамическим сердечником  типоразмер 1005(0402))
pins: 1, 2

## КИК-1608-8.7 нГн ±2% O
designator L?, comment 8.7 нГн ±2%  (value not drawn)
Катушка индуктивности с керамическим сердечником и  финишным покрытием контактных площадок оловом; Номиналиная индуктивность: 8.7 нГн; Добротность, не менее: 30; Резонансная частота, не менее: 4.60 ГГц; Сопротивление обмотки постоянноми току, не более: 0.110 Ом; Допустимый ток обмотки: 700 мА; Диапазон рабочих температур: от -60 до +125 ℃; Упаковка: Катушка и лента; Типоразмер: 1608 (0603); Технология монтажа: SMT; Изготовитель: АО "НПО "ЭРКОН"
footprint КИК-1608_О (Катушка индуктивности с керамическим сердечником  типоразмер 1005(0402))
pins: 1, 2

## КИК-1608-8.7 нГн ±2% Зл
designator L?, comment 8.7 нГн ±2%  (value not drawn)
Катушка индуктивности с керамическим сердечником и золотым покрытием контактных площадок; Номиналиная индуктивность: 8.7 нГн; Добротность, не менее: 30; Резонансная частота, не менее: 4.60 ГГц; Сопротивление обмотки постоянноми току, не более: 0.110 Ом; Допустимый ток обмотки: 700 мА; Диапазон рабочих температур: от -60 до +125 ℃; Упаковка: Катушка и лента; Типоразмер: 1608 (0603); Технология монтажа: SMT; Изготовитель: АО "НПО "ЭРКОН"
footprint КИК-1608_Зл (Катушка индуктивности с керамическим сердечником  типоразмер 1005(0402))
pins: 1, 2

## КИК-1608-8.7 нГн ±5% O
designator L?, comment 8.7 нГн ±5%  (value not drawn)
Катушка индуктивности с керамическим сердечником и  финишным покрытием контактных площадок оловом; Номиналиная индуктивность: 8.7 нГн; Добротность, не менее: 30; Резонансная частота, не менее: 4.60 ГГц; Сопротивление обмотки постоянноми току, не более: 0.110 Ом; Допустимый ток обмотки: 700 мА; Диапазон рабочих температур: от -60 до +125 ℃; Упаковка: Катушка и лента; Типоразмер: 1608 (0603); Технология монтажа: SMT; Изготовитель: АО "НПО "ЭРКОН"
footprint КИК-1608_О (Катушка индуктивности с керамическим сердечником  типоразмер 1005(0402))
pins: 1, 2

## КИК-1608-8.7 нГн ±5% Зл
designator L?, comment 8.7 нГн ±5%  (value not drawn)
Катушка индуктивности с керамическим сердечником и золотым покрытием контактных площадок; Номиналиная индуктивность: 8.7 нГн; Добротность, не менее: 30; Резонансная частота, не менее: 4.60 ГГц; Сопротивление обмотки постоянноми току, не более: 0.110 Ом; Допустимый ток обмотки: 700 мА; Диапазон рабочих температур: от -60 до +125 ℃; Упаковка: Катушка и лента; Типоразмер: 1608 (0603); Технология монтажа: SMT; Изготовитель: АО "НПО "ЭРКОН"
footprint КИК-1608_Зл (Катушка индуктивности с керамическим сердечником  типоразмер 1005(0402))
pins: 1, 2

## КИК-1608-8.7 нГн ±10% O
designator L?, comment 8.7 нГн ±10%  (value not drawn)
Катушка индуктивности с керамическим сердечником и  финишным покрытием контактных площадок оловом; Номиналиная индуктивность: 8.7 нГн; Добротность, не менее: 30; Резонансная частота, не менее: 4.60 ГГц; Сопротивление обмотки постоянноми току, не более: 0.110 Ом; Допустимый ток обмотки: 700 мА; Диапазон рабочих температур: от -60 до +125 ℃; Упаковка: Катушка и лента; Типоразмер: 1608 (0603); Технология монтажа: SMT; Изготовитель: АО "НПО "ЭРКОН"
footprint КИК-1608_О (Катушка индуктивности с керамическим сердечником  типоразмер 1005(0402))
pins: 1, 2

## КИК-1608-8.7 нГн ±10% Зл
designator L?, comment 8.7 нГн ±10%  (value not drawn)
Катушка индуктивности с керамическим сердечником и золотым покрытием контактных площадок; Номиналиная индуктивность: 8.7 нГн; Добротность, не менее: 30; Резонансная частота, не менее: 4.60 ГГц; Сопротивление обмотки постоянноми току, не более: 0.110 Ом; Допустимый ток обмотки: 700 мА; Диапазон рабочих температур: от -60 до +125 ℃; Упаковка: Катушка и лента; Типоразмер: 1608 (0603); Технология монтажа: SMT; Изготовитель: АО "НПО "ЭРКОН"
footprint КИК-1608_Зл (Катушка индуктивности с керамическим сердечником  типоразмер 1005(0402))
pins: 1, 2

## КИК-1608-8.7 нГн ±20% O
designator L?, comment 8.7 нГн ±20%  (value not drawn)
Катушка индуктивности с керамическим сердечником и  финишным покрытием контактных площадок оловом; Номиналиная индуктивность: 8.7 нГн; Добротность, не менее: 30; Резонансная частота, не менее: 4.60 ГГц; Сопротивление обмотки постоянноми току, не более: 0.110 Ом; Допустимый ток обмотки: 700 мА; Диапазон рабочих температур: от -60 до +125 ℃; Упаковка: Катушка и лента; Типоразмер: 1608 (0603); Технология монтажа: SMT; Изготовитель: АО "НПО "ЭРКОН"
footprint КИК-1608_О (Катушка индуктивности с керамическим сердечником  типоразмер 1005(0402))
pins: 1, 2

## КИК-1608-8.7 нГн ±20% Зл
designator L?, comment 8.7 нГн ±20%  (value not drawn)
Катушка индуктивности с керамическим сердечником и золотым покрытием контактных площадок; Номиналиная индуктивность: 8.7 нГн; Добротность, не менее: 30; Резонансная частота, не менее: 4.60 ГГц; Сопротивление обмотки постоянноми току, не более: 0.110 Ом; Допустимый ток обмотки: 700 мА; Диапазон рабочих температур: от -60 до +125 ℃; Упаковка: Катушка и лента; Типоразмер: 1608 (0603); Технология монтажа: SMT; Изготовитель: АО "НПО "ЭРКОН"
footprint КИК-1608_Зл (Катушка индуктивности с керамическим сердечником  типоразмер 1005(0402))
pins: 1, 2

## КИК-1608-9.5 нГн ±2% O
designator L?, comment 9.5 нГн ±2%  (value not drawn)
Катушка индуктивности с керамическим сердечником и  финишным покрытием контактных площадок оловом; Номиналиная индуктивность: 9.5 нГн; Добротность, не менее: 30; Резонансная частота, не менее: 5.40 ГГц; Сопротивление обмотки постоянноми току, не более: 0.135 Ом; Допустимый ток обмотки: 700 мА; Диапазон рабочих температур: от -60 до +125 ℃; Упаковка: Катушка и лента; Типоразмер: 1608 (0603); Технология монтажа: SMT; Изготовитель: АО "НПО "ЭРКОН"
footprint КИК-1608_О (Катушка индуктивности с керамическим сердечником  типоразмер 1005(0402))
pins: 1, 2

## КИК-1608-9.5 нГн ±2% Зл
designator L?, comment 9.5 нГн ±2%  (value not drawn)
Катушка индуктивности с керамическим сердечником и золотым покрытием контактных площадок; Номиналиная индуктивность: 9.5 нГн; Добротность, не менее: 30; Резонансная частота, не менее: 5.40 ГГц; Сопротивление обмотки постоянноми току, не более: 0.135 Ом; Допустимый ток обмотки: 700 мА; Диапазон рабочих температур: от -60 до +125 ℃; Упаковка: Катушка и лента; Типоразмер: 1608 (0603); Технология монтажа: SMT; Изготовитель: АО "НПО "ЭРКОН"
footprint КИК-1608_Зл (Катушка индуктивности с керамическим сердечником  типоразмер 1005(0402))
pins: 1, 2

## КИК-1608-9.5 нГн ±5% O
designator L?, comment 9.5 нГн ±5%  (value not drawn)
Катушка индуктивности с керамическим сердечником и  финишным покрытием контактных площадок оловом; Номиналиная индуктивность: 9.5 нГн; Добротность, не менее: 30; Резонансная частота, не менее: 5.40 ГГц; Сопротивление обмотки постоянноми току, не более: 0.135 Ом; Допустимый ток обмотки: 700 мА; Диапазон рабочих температур: от -60 до +125 ℃; Упаковка: Катушка и лента; Типоразмер: 1608 (0603); Технология монтажа: SMT; Изготовитель: АО "НПО "ЭРКОН"
footprint КИК-1608_О (Катушка индуктивности с керамическим сердечником  типоразмер 1005(0402))
pins: 1, 2

## КИК-1608-9.5 нГн ±5% Зл
designator L?, comment 9.5 нГн ±5%  (value not drawn)
Катушка индуктивности с керамическим сердечником и золотым покрытием контактных площадок; Номиналиная индуктивность: 9.5 нГн; Добротность, не менее: 30; Резонансная частота, не менее: 5.40 ГГц; Сопротивление обмотки постоянноми току, не более: 0.135 Ом; Допустимый ток обмотки: 700 мА; Диапазон рабочих температур: от -60 до +125 ℃; Упаковка: Катушка и лента; Типоразмер: 1608 (0603); Технология монтажа: SMT; Изготовитель: АО "НПО "ЭРКОН"
footprint КИК-1608_Зл (Катушка индуктивности с керамическим сердечником  типоразмер 1005(0402))
pins: 1, 2

## КИК-1608-9.5 нГн ±10% O
designator L?, comment 9.5 нГн ±10%  (value not drawn)
Катушка индуктивности с керамическим сердечником и  финишным покрытием контактных площадок оловом; Номиналиная индуктивность: 9.5 нГн; Добротность, не менее: 30; Резонансная частота, не менее: 5.40 ГГц; Сопротивление обмотки постоянноми току, не более: 0.135 Ом; Допустимый ток обмотки: 700 мА; Диапазон рабочих температур: от -60 до +125 ℃; Упаковка: Катушка и лента; Типоразмер: 1608 (0603); Технология монтажа: SMT; Изготовитель: АО "НПО "ЭРКОН"
footprint КИК-1608_О (Катушка индуктивности с керамическим сердечником  типоразмер 1005(0402))
pins: 1, 2

## КИК-1608-9.5 нГн ±10% Зл
designator L?, comment 9.5 нГн ±10%  (value not drawn)
Катушка индуктивности с керамическим сердечником и золотым покрытием контактных площадок; Номиналиная индуктивность: 9.5 нГн; Добротность, не менее: 30; Резонансная частота, не менее: 5.40 ГГц; Сопротивление обмотки постоянноми току, не более: 0.135 Ом; Допустимый ток обмотки: 700 мА; Диапазон рабочих температур: от -60 до +125 ℃; Упаковка: Катушка и лента; Типоразмер: 1608 (0603); Технология монтажа: SMT; Изготовитель: АО "НПО "ЭРКОН"
footprint КИК-1608_Зл (Катушка индуктивности с керамическим сердечником  типоразмер 1005(0402))
pins: 1, 2

## КИК-1608-9.5 нГн ±20% O
designator L?, comment 9.5 нГн ±20%  (value not drawn)
Катушка индуктивности с керамическим сердечником и  финишным покрытием контактных площадок оловом; Номиналиная индуктивность: 9.5 нГн; Добротность, не менее: 30; Резонансная частота, не менее: 5.40 ГГц; Сопротивление обмотки постоянноми току, не более: 0.135 Ом; Допустимый ток обмотки: 700 мА; Диапазон рабочих температур: от -60 до +125 ℃; Упаковка: Катушка и лента; Типоразмер: 1608 (0603); Технология монтажа: SMT; Изготовитель: АО "НПО "ЭРКОН"
footprint КИК-1608_О (Катушка индуктивности с керамическим сердечником  типоразмер 1005(0402))
pins: 1, 2

## КИК-1608-9.5 нГн ±20% Зл
designator L?, comment 9.5 нГн ±20%  (value not drawn)
Катушка индуктивности с керамическим сердечником и золотым покрытием контактных площадок; Номиналиная индуктивность: 9.5 нГн; Добротность, не менее: 30; Резонансная частота, не менее: 5.40 ГГц; Сопротивление обмотки постоянноми току, не более: 0.135 Ом; Допустимый ток обмотки: 700 мА; Диапазон рабочих температур: от -60 до +125 ℃; Упаковка: Катушка и лента; Типоразмер: 1608 (0603); Технология монтажа: SMT; Изготовитель: АО "НПО "ЭРКОН"
footprint КИК-1608_Зл (Катушка индуктивности с керамическим сердечником  типоразмер 1005(0402))
pins: 1, 2

## КИК-1608-10 нГн ±2% O
designator L?, comment 10 нГн ±2%  (value not drawn)
Катушка индуктивности с керамическим сердечником и  финишным покрытием контактных площадок оловом; Номиналиная индуктивность: 10 нГн; Добротность, не менее: 30; Резонансная частота, не менее: 4.80 ГГц; Сопротивление обмотки постоянноми току, не более: 0.130 Ом; Допустимый ток обмотки: 700 мА; Диапазон рабочих температур: от -60 до +125 ℃; Упаковка: Катушка и лента; Типоразмер: 1608 (0603); Технология монтажа: SMT; Изготовитель: АО "НПО "ЭРКОН"
footprint КИК-1608_О (Катушка индуктивности с керамическим сердечником  типоразмер 1005(0402))
pins: 1, 2

## КИК-1608-10 нГн ±2% Зл
designator L?, comment 10 нГн ±2%  (value not drawn)
Катушка индуктивности с керамическим сердечником и золотым покрытием контактных площадок; Номиналиная индуктивность: 10 нГн; Добротность, не менее: 30; Резонансная частота, не менее: 4.80 ГГц; Сопротивление обмотки постоянноми току, не более: 0.130 Ом; Допустимый ток обмотки: 700 мА; Диапазон рабочих температур: от -60 до +125 ℃; Упаковка: Катушка и лента; Типоразмер: 1608 (0603); Технология монтажа: SMT; Изготовитель: АО "НПО "ЭРКОН"
footprint КИК-1608_Зл (Катушка индуктивности с керамическим сердечником  типоразмер 1005(0402))
pins: 1, 2

## КИК-1608-10 нГн ±5% O
designator L?, comment 10 нГн ±5%  (value not drawn)
Катушка индуктивности с керамическим сердечником и  финишным покрытием контактных площадок оловом; Номиналиная индуктивность: 10 нГн; Добротность, не менее: 30; Резонансная частота, не менее: 4.80 ГГц; Сопротивление обмотки постоянноми току, не более: 0.130 Ом; Допустимый ток обмотки: 700 мА; Диапазон рабочих температур: от -60 до +125 ℃; Упаковка: Катушка и лента; Типоразмер: 1608 (0603); Технология монтажа: SMT; Изготовитель: АО "НПО "ЭРКОН"
footprint КИК-1608_О (Катушка индуктивности с керамическим сердечником  типоразмер 1005(0402))
pins: 1, 2

## КИК-1608-10 нГн ±5% Зл
designator L?, comment 10 нГн ±5%  (value not drawn)
Катушка индуктивности с керамическим сердечником и золотым покрытием контактных площадок; Номиналиная индуктивность: 10 нГн; Добротность, не менее: 30; Резонансная частота, не менее: 4.80 ГГц; Сопротивление обмотки постоянноми току, не более: 0.130 Ом; Допустимый ток обмотки: 700 мА; Диапазон рабочих температур: от -60 до +125 ℃; Упаковка: Катушка и лента; Типоразмер: 1608 (0603); Технология монтажа: SMT; Изготовитель: АО "НПО "ЭРКОН"
footprint КИК-1608_Зл (Катушка индуктивности с керамическим сердечником  типоразмер 1005(0402))
pins: 1, 2

## КИК-1608-10 нГн ±10% O
designator L?, comment 10 нГн ±10%  (value not drawn)
Катушка индуктивности с керамическим сердечником и  финишным покрытием контактных площадок оловом; Номиналиная индуктивность: 10 нГн; Добротность, не менее: 30; Резонансная частота, не менее: 4.80 ГГц; Сопротивление обмотки постоянноми току, не более: 0.130 Ом; Допустимый ток обмотки: 700 мА; Диапазон рабочих температур: от -60 до +125 ℃; Упаковка: Катушка и лента; Типоразмер: 1608 (0603); Технология монтажа: SMT; Изготовитель: АО "НПО "ЭРКОН"
footprint КИК-1608_О (Катушка индуктивности с керамическим сердечником  типоразмер 1005(0402))
pins: 1, 2

## КИК-1608-10 нГн ±10% Зл
designator L?, comment 10 нГн ±10%  (value not drawn)
Катушка индуктивности с керамическим сердечником и золотым покрытием контактных площадок; Номиналиная индуктивность: 10 нГн; Добротность, не менее: 30; Резонансная частота, не менее: 4.80 ГГц; Сопротивление обмотки постоянноми току, не более: 0.130 Ом; Допустимый ток обмотки: 700 мА; Диапазон рабочих температур: от -60 до +125 ℃; Упаковка: Катушка и лента; Типоразмер: 1608 (0603); Технология монтажа: SMT; Изготовитель: АО "НПО "ЭРКОН"
footprint КИК-1608_Зл (Катушка индуктивности с керамическим сердечником  типоразмер 1005(0402))
pins: 1, 2


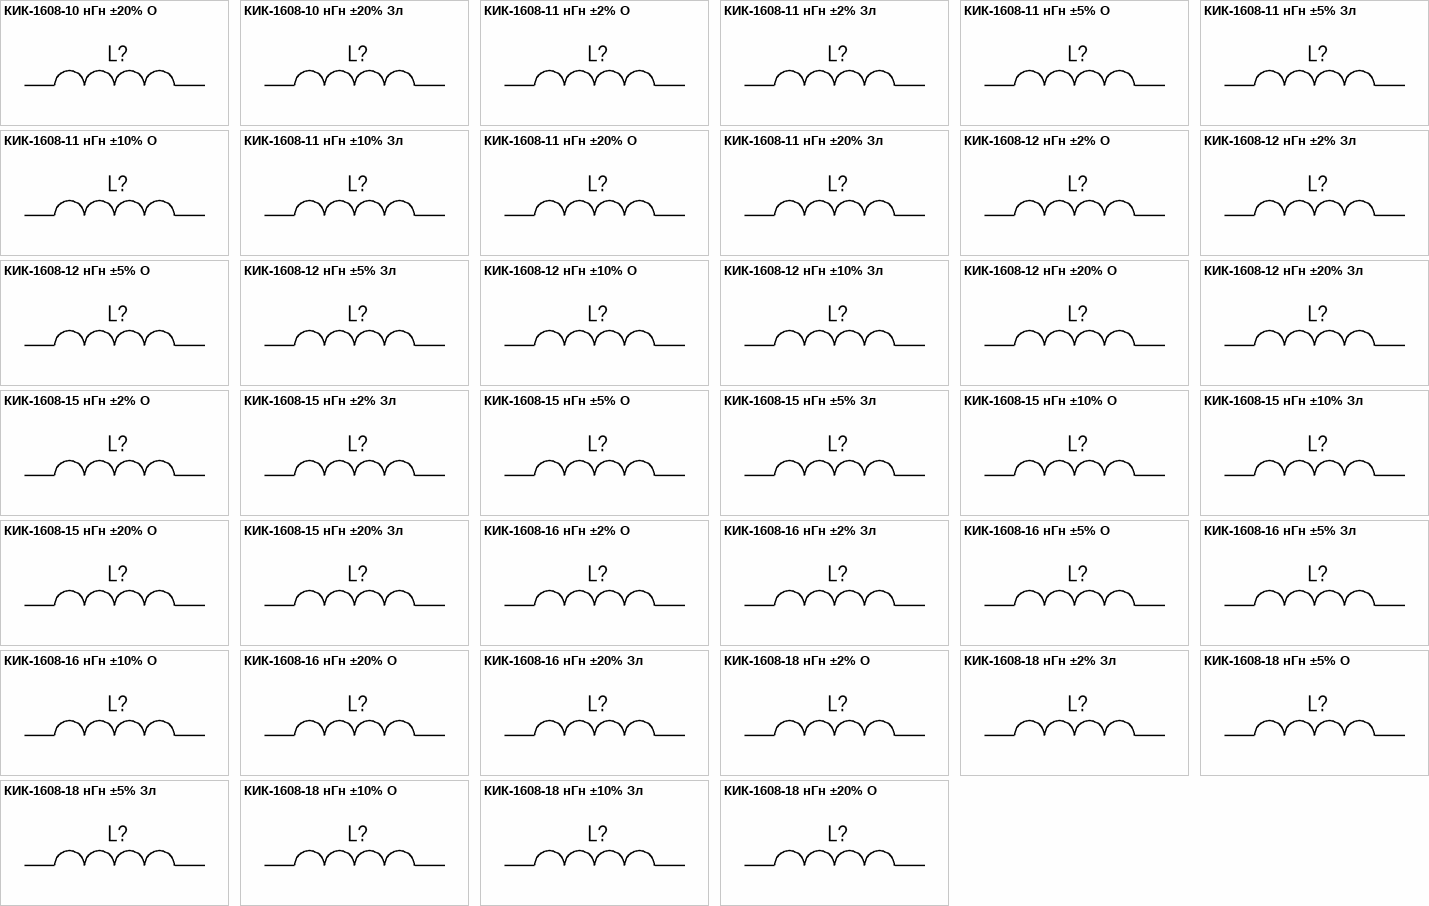
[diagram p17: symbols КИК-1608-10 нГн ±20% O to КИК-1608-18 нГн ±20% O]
## КИК-1608-10 нГн ±20% O
designator L?, comment 10 нГн ±20%  (value not drawn)
Катушка индуктивности с керамическим сердечником и  финишным покрытием контактных площадок оловом; Номиналиная индуктивность: 10 нГн; Добротность, не менее: 30; Резонансная частота, не менее: 4.80 ГГц; Сопротивление обмотки постоянноми току, не более: 0.130 Ом; Допустимый ток обмотки: 700 мА; Диапазон рабочих температур: от -60 до +125 ℃; Упаковка: Катушка и лента; Типоразмер: 1608 (0603); Технология монтажа: SMT; Изготовитель: АО "НПО "ЭРКОН"
footprint КИК-1608_О (Катушка индуктивности с керамическим сердечником  типоразмер 1005(0402))
pins: 1, 2

## КИК-1608-10 нГн ±20% Зл
designator L?, comment 10 нГн ±20%  (value not drawn)
Катушка индуктивности с керамическим сердечником и золотым покрытием контактных площадок; Номиналиная индуктивность: 10 нГн; Добротность, не менее: 30; Резонансная частота, не менее: 4.80 ГГц; Сопротивление обмотки постоянноми току, не более: 0.130 Ом; Допустимый ток обмотки: 700 мА; Диапазон рабочих температур: от -60 до +125 ℃; Упаковка: Катушка и лента; Типоразмер: 1608 (0603); Технология монтажа: SMT; Изготовитель: АО "НПО "ЭРКОН"
footprint КИК-1608_Зл (Катушка индуктивности с керамическим сердечником  типоразмер 1005(0402))
pins: 1, 2

## КИК-1608-11 нГн ±2% O
designator L?, comment 11 нГн ±2%  (value not drawn)
Катушка индуктивности с керамическим сердечником и  финишным покрытием контактных площадок оловом; Номиналиная индуктивность: 11 нГн; Добротность, не менее: 30; Резонансная частота, не менее: 4.00 ГГц; Сопротивление обмотки постоянноми току, не более: 0.130 Ом; Допустимый ток обмотки: 700 мА; Диапазон рабочих температур: от -60 до +125 ℃; Упаковка: Катушка и лента; Типоразмер: 1608 (0603); Технология монтажа: SMT; Изготовитель: АО "НПО "ЭРКОН"
footprint КИК-1608_О (Катушка индуктивности с керамическим сердечником  типоразмер 1005(0402))
pins: 1, 2

## КИК-1608-11 нГн ±2% Зл
designator L?, comment 11 нГн ±2%  (value not drawn)
Катушка индуктивности с керамическим сердечником и золотым покрытием контактных площадок; Номиналиная индуктивность: 11 нГн; Добротность, не менее: 30; Резонансная частота, не менее: 4.00 ГГц; Сопротивление обмотки постоянноми току, не более: 0.130 Ом; Допустимый ток обмотки: 700 мА; Диапазон рабочих температур: от -60 до +125 ℃; Упаковка: Катушка и лента; Типоразмер: 1608 (0603); Технология монтажа: SMT; Изготовитель: АО "НПО "ЭРКОН"
footprint КИК-1608_Зл (Катушка индуктивности с керамическим сердечником  типоразмер 1005(0402))
pins: 1, 2

## КИК-1608-11 нГн ±5% O
designator L?, comment 11 нГн ±5%  (value not drawn)
Катушка индуктивности с керамическим сердечником и  финишным покрытием контактных площадок оловом; Номиналиная индуктивность: 11 нГн; Добротность, не менее: 30; Резонансная частота, не менее: 4.00 ГГц; Сопротивление обмотки постоянноми току, не более: 0.130 Ом; Допустимый ток обмотки: 700 мА; Диапазон рабочих температур: от -60 до +125 ℃; Упаковка: Катушка и лента; Типоразмер: 1608 (0603); Технология монтажа: SMT; Изготовитель: АО "НПО "ЭРКОН"
footprint КИК-1608_О (Катушка индуктивности с керамическим сердечником  типоразмер 1005(0402))
pins: 1, 2

## КИК-1608-11 нГн ±5% Зл
designator L?, comment 11 нГн ±5%  (value not drawn)
Катушка индуктивности с керамическим сердечником и золотым покрытием контактных площадок; Номиналиная индуктивность: 11 нГн; Добротность, не менее: 30; Резонансная частота, не менее: 4.00 ГГц; Сопротивление обмотки постоянноми току, не более: 0.130 Ом; Допустимый ток обмотки: 700 мА; Диапазон рабочих температур: от -60 до +125 ℃; Упаковка: Катушка и лента; Типоразмер: 1608 (0603); Технология монтажа: SMT; Изготовитель: АО "НПО "ЭРКОН"
footprint КИК-1608_Зл (Катушка индуктивности с керамическим сердечником  типоразмер 1005(0402))
pins: 1, 2

## КИК-1608-11 нГн ±10% O
designator L?, comment 11 нГн ±10%  (value not drawn)
Катушка индуктивности с керамическим сердечником и  финишным покрытием контактных площадок оловом; Номиналиная индуктивность: 11 нГн; Добротность, не менее: 30; Резонансная частота, не менее: 4.00 ГГц; Сопротивление обмотки постоянноми току, не более: 0.130 Ом; Допустимый ток обмотки: 700 мА; Диапазон рабочих температур: от -60 до +125 ℃; Упаковка: Катушка и лента; Типоразмер: 1608 (0603); Технология монтажа: SMT; Изготовитель: АО "НПО "ЭРКОН"
footprint КИК-1608_О (Катушка индуктивности с керамическим сердечником  типоразмер 1005(0402))
pins: 1, 2

## КИК-1608-11 нГн ±10% Зл
designator L?, comment 11 нГн ±10%  (value not drawn)
Катушка индуктивности с керамическим сердечником и золотым покрытием контактных площадок; Номиналиная индуктивность: 11 нГн; Добротность, не менее: 30; Резонансная частота, не менее: 4.00 ГГц; Сопротивление обмотки постоянноми току, не более: 0.130 Ом; Допустимый ток обмотки: 700 мА; Диапазон рабочих температур: от -60 до +125 ℃; Упаковка: Катушка и лента; Типоразмер: 1608 (0603); Технология монтажа: SMT; Изготовитель: АО "НПО "ЭРКОН"
footprint КИК-1608_Зл (Катушка индуктивности с керамическим сердечником  типоразмер 1005(0402))
pins: 1, 2

## КИК-1608-11 нГн ±20% O
designator L?, comment 11 нГн ±20%  (value not drawn)
Катушка индуктивности с керамическим сердечником и  финишным покрытием контактных площадок оловом; Номиналиная индуктивность: 11 нГн; Добротность, не менее: 30; Резонансная частота, не менее: 4.00 ГГц; Сопротивление обмотки постоянноми току, не более: 0.130 Ом; Допустимый ток обмотки: 700 мА; Диапазон рабочих температур: от -60 до +125 ℃; Упаковка: Катушка и лента; Типоразмер: 1608 (0603); Технология монтажа: SMT; Изготовитель: АО "НПО "ЭРКОН"
footprint КИК-1608_О (Катушка индуктивности с керамическим сердечником  типоразмер 1005(0402))
pins: 1, 2

## КИК-1608-11 нГн ±20% Зл
designator L?, comment 11 нГн ±20%  (value not drawn)
Катушка индуктивности с керамическим сердечником и золотым покрытием контактных площадок; Номиналиная индуктивность: 11 нГн; Добротность, не менее: 30; Резонансная частота, не менее: 4.00 ГГц; Сопротивление обмотки постоянноми току, не более: 0.130 Ом; Допустимый ток обмотки: 700 мА; Диапазон рабочих температур: от -60 до +125 ℃; Упаковка: Катушка и лента; Типоразмер: 1608 (0603); Технология монтажа: SMT; Изготовитель: АО "НПО "ЭРКОН"
footprint КИК-1608_Зл (Катушка индуктивности с керамическим сердечником  типоразмер 1005(0402))
pins: 1, 2

## КИК-1608-12 нГн ±2% O
designator L?, comment 12 нГн ±2%  (value not drawn)
Катушка индуктивности с керамическим сердечником и  финишным покрытием контактных площадок оловом; Номиналиная индуктивность: 12 нГн; Добротность, не менее: 30; Резонансная частота, не менее: 4.00 ГГц; Сопротивление обмотки постоянноми току, не более: 0.130 Ом; Допустимый ток обмотки: 700 мА; Диапазон рабочих температур: от -60 до +125 ℃; Упаковка: Катушка и лента; Типоразмер: 1608 (0603); Технология монтажа: SMT; Изготовитель: АО "НПО "ЭРКОН"
footprint КИК-1608_О (Катушка индуктивности с керамическим сердечником  типоразмер 1005(0402))
pins: 1, 2

## КИК-1608-12 нГн ±2% Зл
designator L?, comment 12 нГн ±2%  (value not drawn)
Катушка индуктивности с керамическим сердечником и золотым покрытием контактных площадок; Номиналиная индуктивность: 12 нГн; Добротность, не менее: 30; Резонансная частота, не менее: 4.00 ГГц; Сопротивление обмотки постоянноми току, не более: 0.130 Ом; Допустимый ток обмотки: 700 мА; Диапазон рабочих температур: от -60 до +125 ℃; Упаковка: Катушка и лента; Типоразмер: 1608 (0603); Технология монтажа: SMT; Изготовитель: АО "НПО "ЭРКОН"
footprint КИК-1608_Зл (Катушка индуктивности с керамическим сердечником  типоразмер 1005(0402))
pins: 1, 2

## КИК-1608-12 нГн ±5% O
designator L?, comment 12 нГн ±5%  (value not drawn)
Катушка индуктивности с керамическим сердечником и  финишным покрытием контактных площадок оловом; Номиналиная индуктивность: 12 нГн; Добротность, не менее: 30; Резонансная частота, не менее: 4.00 ГГц; Сопротивление обмотки постоянноми току, не более: 0.130 Ом; Допустимый ток обмотки: 700 мА; Диапазон рабочих температур: от -60 до +125 ℃; Упаковка: Катушка и лента; Типоразмер: 1608 (0603); Технология монтажа: SMT; Изготовитель: АО "НПО "ЭРКОН"
footprint КИК-1608_О (Катушка индуктивности с керамическим сердечником  типоразмер 1005(0402))
pins: 1, 2

## КИК-1608-12 нГн ±5% Зл
designator L?, comment 12 нГн ±5%  (value not drawn)
Катушка индуктивности с керамическим сердечником и золотым покрытием контактных площадок; Номиналиная индуктивность: 12 нГн; Добротность, не менее: 30; Резонансная частота, не менее: 4.00 ГГц; Сопротивление обмотки постоянноми току, не более: 0.130 Ом; Допустимый ток обмотки: 700 мА; Диапазон рабочих температур: от -60 до +125 ℃; Упаковка: Катушка и лента; Типоразмер: 1608 (0603); Технология монтажа: SMT; Изготовитель: АО "НПО "ЭРКОН"
footprint КИК-1608_Зл (Катушка индуктивности с керамическим сердечником  типоразмер 1005(0402))
pins: 1, 2

## КИК-1608-12 нГн ±10% O
designator L?, comment 12 нГн ±10%  (value not drawn)
Катушка индуктивности с керамическим сердечником и  финишным покрытием контактных площадок оловом; Номиналиная индуктивность: 12 нГн; Добротность, не менее: 30; Резонансная частота, не менее: 4.00 ГГц; Сопротивление обмотки постоянноми току, не более: 0.130 Ом; Допустимый ток обмотки: 700 мА; Диапазон рабочих температур: от -60 до +125 ℃; Упаковка: Катушка и лента; Типоразмер: 1608 (0603); Технология монтажа: SMT; Изготовитель: АО "НПО "ЭРКОН"
footprint КИК-1608_О (Катушка индуктивности с керамическим сердечником  типоразмер 1005(0402))
pins: 1, 2

## КИК-1608-12 нГн ±10% Зл
designator L?, comment 12 нГн ±10%  (value not drawn)
Катушка индуктивности с керамическим сердечником и золотым покрытием контактных площадок; Номиналиная индуктивность: 12 нГн; Добротность, не менее: 30; Резонансная частота, не менее: 4.00 ГГц; Сопротивление обмотки постоянноми току, не более: 0.130 Ом; Допустимый ток обмотки: 700 мА; Диапазон рабочих температур: от -60 до +125 ℃; Упаковка: Катушка и лента; Типоразмер: 1608 (0603); Технология монтажа: SMT; Изготовитель: АО "НПО "ЭРКОН"
footprint КИК-1608_Зл (Катушка индуктивности с керамическим сердечником  типоразмер 1005(0402))
pins: 1, 2

## КИК-1608-12 нГн ±20% O
designator L?, comment 12 нГн ±20%  (value not drawn)
Катушка индуктивности с керамическим сердечником и  финишным покрытием контактных площадок оловом; Номиналиная индуктивность: 12 нГн; Добротность, не менее: 30; Резонансная частота, не менее: 4.00 ГГц; Сопротивление обмотки постоянноми току, не более: 0.130 Ом; Допустимый ток обмотки: 700 мА; Диапазон рабочих температур: от -60 до +125 ℃; Упаковка: Катушка и лента; Типоразмер: 1608 (0603); Технология монтажа: SMT; Изготовитель: АО "НПО "ЭРКОН"
footprint КИК-1608_О (Катушка индуктивности с керамическим сердечником  типоразмер 1005(0402))
pins: 1, 2

## КИК-1608-12 нГн ±20% Зл
designator L?, comment 12 нГн ±20%  (value not drawn)
Катушка индуктивности с керамическим сердечником и золотым покрытием контактных площадок; Номиналиная индуктивность: 12 нГн; Добротность, не менее: 30; Резонансная частота, не менее: 4.00 ГГц; Сопротивление обмотки постоянноми току, не более: 0.130 Ом; Допустимый ток обмотки: 700 мА; Диапазон рабочих температур: от -60 до +125 ℃; Упаковка: Катушка и лента; Типоразмер: 1608 (0603); Технология монтажа: SMT; Изготовитель: АО "НПО "ЭРКОН"
footprint КИК-1608_Зл (Катушка индуктивности с керамическим сердечником  типоразмер 1005(0402))
pins: 1, 2

## КИК-1608-15 нГн ±2% O
designator L?, comment 15 нГн ±2%  (value not drawn)
Катушка индуктивности с керамическим сердечником и  финишным покрытием контактных площадок оловом; Номиналиная индуктивность: 12 нГн; Добротность, не менее: 30; Резонансная частота, не менее: 4.00 ГГц; Сопротивление обмотки постоянноми току, не более: 0.170 Ом; Допустимый ток обмотки: 700 мА; Диапазон рабочих температур: от -60 до +125 ℃; Упаковка: Катушка и лента; Типоразмер: 1608 (0603); Технология монтажа: SMT; Изготовитель: АО "НПО "ЭРКОН"
footprint КИК-1608_О (Катушка индуктивности с керамическим сердечником  типоразмер 1005(0402))
pins: 1, 2

## КИК-1608-15 нГн ±2% Зл
designator L?, comment 15 нГн ±2%  (value not drawn)
Катушка индуктивности с керамическим сердечником и золотым покрытием контактных площадок; Номиналиная индуктивность: 15 нГн; Добротность, не менее: 30; Резонансная частота, не менее: 4.00 ГГц; Сопротивление обмотки постоянноми току, не более: 0.170 Ом; Допустимый ток обмотки: 700 мА; Диапазон рабочих температур: от -60 до +125 ℃; Упаковка: Катушка и лента; Типоразмер: 1608 (0603); Технология монтажа: SMT; Изготовитель: АО "НПО "ЭРКОН"
footprint КИК-1608_Зл (Катушка индуктивности с керамическим сердечником  типоразмер 1005(0402))
pins: 1, 2

## КИК-1608-15 нГн ±5% O
designator L?, comment 15 нГн ±5%  (value not drawn)
Катушка индуктивности с керамическим сердечником и  финишным покрытием контактных площадок оловом; Номиналиная индуктивность: 12 нГн; Добротность, не менее: 30; Резонансная частота, не менее: 4.00 ГГц; Сопротивление обмотки постоянноми току, не более: 0.170 Ом; Допустимый ток обмотки: 700 мА; Диапазон рабочих температур: от -60 до +125 ℃; Упаковка: Катушка и лента; Типоразмер: 1608 (0603); Технология монтажа: SMT; Изготовитель: АО "НПО "ЭРКОН"
footprint КИК-1608_О (Катушка индуктивности с керамическим сердечником  типоразмер 1005(0402))
pins: 1, 2

## КИК-1608-15 нГн ±5% Зл
designator L?, comment 15 нГн ±5%  (value not drawn)
Катушка индуктивности с керамическим сердечником и золотым покрытием контактных площадок; Номиналиная индуктивность: 15 нГн; Добротность, не менее: 30; Резонансная частота, не менее: 4.00 ГГц; Сопротивление обмотки постоянноми току, не более: 0.170 Ом; Допустимый ток обмотки: 700 мА; Диапазон рабочих температур: от -60 до +125 ℃; Упаковка: Катушка и лента; Типоразмер: 1608 (0603); Технология монтажа: SMT; Изготовитель: АО "НПО "ЭРКОН"
footprint КИК-1608_Зл (Катушка индуктивности с керамическим сердечником  типоразмер 1005(0402))
pins: 1, 2

## КИК-1608-15 нГн ±10% O
designator L?, comment 15 нГн ±10%  (value not drawn)
Катушка индуктивности с керамическим сердечником и  финишным покрытием контактных площадок оловом; Номиналиная индуктивность: 15 нГн; Добротность, не менее: 30; Резонансная частота, не менее: 4.00 ГГц; Сопротивление обмотки постоянноми току, не более: 0.170 Ом; Допустимый ток обмотки: 700 мА; Диапазон рабочих температур: от -60 до +125 ℃; Упаковка: Катушка и лента; Типоразмер: 1608 (0603); Технология монтажа: SMT; Изготовитель: АО "НПО "ЭРКОН"
footprint КИК-1608_О (Катушка индуктивности с керамическим сердечником  типоразмер 1005(0402))
pins: 1, 2

## КИК-1608-15 нГн ±10% Зл
designator L?, comment 15 нГн ±10%  (value not drawn)
Катушка индуктивности с керамическим сердечником и золотым покрытием контактных площадок; Номиналиная индуктивность: 15 нГн; Добротность, не менее: 30; Резонансная частота, не менее: 4.00 ГГц; Сопротивление обмотки постоянноми току, не более: 0.170 Ом; Допустимый ток обмотки: 700 мА; Диапазон рабочих температур: от -60 до +125 ℃; Упаковка: Катушка и лента; Типоразмер: 1608 (0603); Технология монтажа: SMT; Изготовитель: АО "НПО "ЭРКОН"
footprint КИК-1608_Зл (Катушка индуктивности с керамическим сердечником  типоразмер 1005(0402))
pins: 1, 2

## КИК-1608-15 нГн ±20% O
designator L?, comment 15 нГн ±20%  (value not drawn)
Катушка индуктивности с керамическим сердечником и  финишным покрытием контактных площадок оловом; Номиналиная индуктивность: 15 нГн; Добротность, не менее: 30; Резонансная частота, не менее: 4.00 ГГц; Сопротивление обмотки постоянноми току, не более: 0.170 Ом; Допустимый ток обмотки: 700 мА; Диапазон рабочих температур: от -60 до +125 ℃; Упаковка: Катушка и лента; Типоразмер: 1608 (0603); Технология монтажа: SMT; Изготовитель: АО "НПО "ЭРКОН"
footprint КИК-1608_О (Катушка индуктивности с керамическим сердечником  типоразмер 1005(0402))
pins: 1, 2

## КИК-1608-15 нГн ±20% Зл
designator L?, comment 15 нГн ±20%  (value not drawn)
Катушка индуктивности с керамическим сердечником и золотым покрытием контактных площадок; Номиналиная индуктивность: 15 нГн; Допускаемое отклонение индуктивности: ±10%; Добротность, не менее: 30; Резонансная частота, не менее: 4.00 ГГц; Сопротивление обмотки постоянноми току, не более: 0.170 Ом; Допустимый ток обмотки: 700 мА; Диапазон рабочих температур: от -60 до +125 ℃; Упаковка: Катушка и лента; Типоразмер: 1608 (0603); Технология монтажа: SMT; Изготовитель: АО "НПО "ЭРКОН"
footprint КИК-1608_Зл (Катушка индуктивности с керамическим сердечником  типоразмер 1005(0402))
pins: 1, 2

## КИК-1608-16 нГн ±2% O
designator L?, comment 16 нГн ±2%  (value not drawn)
Катушка индуктивности с керамическим сердечником и  финишным покрытием контактных площадок оловом; Номиналиная индуктивность: 16 нГн; Добротность, не менее: 30; Резонансная частота, не менее: 3.30 ГГц; Сопротивление обмотки постоянноми току, не более: 0.170 Ом; Допустимый ток обмотки: 700 мА; Диапазон рабочих температур: от -60 до +125 ℃; Упаковка: Катушка и лента; Типоразмер: 1608 (0603); Технология монтажа: SMT; Изготовитель: АО "НПО "ЭРКОН"
footprint КИК-1608_О (Катушка индуктивности с керамическим сердечником  типоразмер 1005(0402))
pins: 1, 2

## КИК-1608-16 нГн ±2% Зл
designator L?, comment 16 нГн ±2%  (value not drawn)
Катушка индуктивности с керамическим сердечником и золотым покрытием контактных площадок; Номиналиная индуктивность: 16 нГн; Добротность, не менее: 30; Резонансная частота, не менее: 3.30 ГГц; Сопротивление обмотки постоянноми току, не более: 0.170 Ом; Допустимый ток обмотки: 700 мА; Диапазон рабочих температур: от -60 до +125 ℃; Упаковка: Катушка и лента; Типоразмер: 1608 (0603); Технология монтажа: SMT; Изготовитель: АО "НПО "ЭРКОН"
footprint КИК-1608_Зл (Катушка индуктивности с керамическим сердечником  типоразмер 1005(0402))
pins: 1, 2

## КИК-1608-16 нГн ±5% O
designator L?, comment 16 нГн ±5%  (value not drawn)
Катушка индуктивности с керамическим сердечником и  финишным покрытием контактных площадок оловом; Номиналиная индуктивность: 16 нГн; Добротность, не менее: 30; Резонансная частота, не менее: 3.30 ГГц; Сопротивление обмотки постоянноми току, не более: 0.170 Ом; Допустимый ток обмотки: 700 мА; Диапазон рабочих температур: от -60 до +125 ℃; Упаковка: Катушка и лента; Типоразмер: 1608 (0603); Технология монтажа: SMT; Изготовитель: АО "НПО "ЭРКОН"
footprint КИК-1608_О (Катушка индуктивности с керамическим сердечником  типоразмер 1005(0402))
pins: 1, 2

## КИК-1608-16 нГн ±5% Зл
designator L?, comment 16 нГн ±5%  (value not drawn)
Катушка индуктивности с керамическим сердечником и золотым покрытием контактных площадок; Номиналиная индуктивность: 16 нГн; Добротность, не менее: 30; Резонансная частота, не менее: 3.30 ГГц; Сопротивление обмотки постоянноми току, не более: 0.170 Ом; Допустимый ток обмотки: 700 мА; Диапазон рабочих температур: от -60 до +125 ℃; Упаковка: Катушка и лента; Типоразмер: 1608 (0603); Технология монтажа: SMT; Изготовитель: АО "НПО "ЭРКОН"
footprint КИК-1608_Зл (Катушка индуктивности с керамическим сердечником  типоразмер 1005(0402))
pins: 1, 2

## КИК-1608-16 нГн ±10% O
designator L?, comment 16 нГн ±10%  (value not drawn)
Катушка индуктивности с керамическим сердечником и  финишным покрытием контактных площадок оловом; Номиналиная индуктивность: 16 нГн; Добротность, не менее: 30; Резонансная частота, не менее: 3.30 ГГц; Сопротивление обмотки постоянноми току, не более: 0.170 Ом; Допустимый ток обмотки: 700 мА; Диапазон рабочих температур: от -60 до +125 ℃; Упаковка: Катушка и лента; Типоразмер: 1608 (0603); Технология монтажа: SMT; Изготовитель: АО "НПО "ЭРКОН"
footprint КИК-1608_О (Катушка индуктивности с керамическим сердечником  типоразмер 1005(0402))
pins: 1, 2

## КИК-1608-16 нГн ±20% O
designator L?, comment 16 нГн ±20%  (value not drawn)
Катушка индуктивности с керамическим сердечником и  финишным покрытием контактных площадок оловом; Номиналиная индуктивность: 16 нГн; Добротность, не менее: 30; Резонансная частота, не менее: 3.30 ГГц; Сопротивление обмотки постоянноми току, не более: 0.170 Ом; Допустимый ток обмотки: 700 мА; Диапазон рабочих температур: от -60 до +125 ℃; Упаковка: Катушка и лента; Типоразмер: 1608 (0603); Технология монтажа: SMT; Изготовитель: АО "НПО "ЭРКОН"
footprint КИК-1608_О (Катушка индуктивности с керамическим сердечником  типоразмер 1005(0402))
pins: 1, 2

## КИК-1608-16 нГн ±20% Зл
designator L?, comment 16 нГн ±20%  (value not drawn)
Катушка индуктивности с керамическим сердечником и золотым покрытием контактных площадок; Номиналиная индуктивность: 16 нГн; Добротность, не менее: 30; Резонансная частота, не менее: 3.30 ГГц; Сопротивление обмотки постоянноми току, не более: 0.170 Ом; Допустимый ток обмотки: 700 мА; Диапазон рабочих температур: от -60 до +125 ℃; Упаковка: Катушка и лента; Типоразмер: 1608 (0603); Технология монтажа: SMT; Изготовитель: АО "НПО "ЭРКОН"
footprint КИК-1608_Зл (Катушка индуктивности с керамическим сердечником  типоразмер 1005(0402))
pins: 1, 2

## КИК-1608-18 нГн ±2% O
designator L?, comment 18 нГн ±2%  (value not drawn)
Катушка индуктивности с керамическим сердечником и  финишным покрытием контактных площадок оловом; Номиналиная индуктивность: 18 нГн; Добротность, не менее: 30; Резонансная частота, не менее: 3.10 ГГц; Сопротивление обмотки постоянноми току, не более: 0.170 Ом; Допустимый ток обмотки: 700 мА; Диапазон рабочих температур: от -60 до +125 ℃; Упаковка: Катушка и лента; Типоразмер: 1608 (0603); Технология монтажа: SMT; Изготовитель: АО "НПО "ЭРКОН"
footprint КИК-1608_О (Катушка индуктивности с керамическим сердечником  типоразмер 1005(0402))
pins: 1, 2

## КИК-1608-18 нГн ±2% Зл
designator L?, comment 18 нГн ±2%  (value not drawn)
Катушка индуктивности с керамическим сердечником и золотым покрытием контактных площадок; Номиналиная индуктивность: 18 нГн; Добротность, не менее: 30; Резонансная частота, не менее: 3.10 ГГц; Сопротивление обмотки постоянноми току, не более: 0.170 Ом; Допустимый ток обмотки: 700 мА; Диапазон рабочих температур: от -60 до +125 ℃; Упаковка: Катушка и лента; Типоразмер: 1608 (0603); Технология монтажа: SMT; Изготовитель: АО "НПО "ЭРКОН"
footprint КИК-1608_Зл (Катушка индуктивности с керамическим сердечником  типоразмер 1005(0402))
pins: 1, 2

## КИК-1608-18 нГн ±5% O
designator L?, comment 18 нГн ±5%  (value not drawn)
Катушка индуктивности с керамическим сердечником и  финишным покрытием контактных площадок оловом; Номиналиная индуктивность: 18 нГн; Добротность, не менее: 30; Резонансная частота, не менее: 3.10 ГГц; Сопротивление обмотки постоянноми току, не более: 0.170 Ом; Допустимый ток обмотки: 700 мА; Диапазон рабочих температур: от -60 до +125 ℃; Упаковка: Катушка и лента; Типоразмер: 1608 (0603); Технология монтажа: SMT; Изготовитель: АО "НПО "ЭРКОН"
footprint КИК-1608_О (Катушка индуктивности с керамическим сердечником  типоразмер 1005(0402))
pins: 1, 2

## КИК-1608-18 нГн ±5% Зл
designator L?, comment 18 нГн ±5%  (value not drawn)
Катушка индуктивности с керамическим сердечником и золотым покрытием контактных площадок; Номиналиная индуктивность: 18 нГн; Добротность, не менее: 30; Резонансная частота, не менее: 3.10 ГГц; Сопротивление обмотки постоянноми току, не более: 0.170 Ом; Допустимый ток обмотки: 700 мА; Диапазон рабочих температур: от -60 до +125 ℃; Упаковка: Катушка и лента; Типоразмер: 1608 (0603); Технология монтажа: SMT; Изготовитель: АО "НПО "ЭРКОН"
footprint КИК-1608_Зл (Катушка индуктивности с керамическим сердечником  типоразмер 1005(0402))
pins: 1, 2

## КИК-1608-18 нГн ±10% O
designator L?, comment 18 нГн ±10%  (value not drawn)
Катушка индуктивности с керамическим сердечником и  финишным покрытием контактных площадок оловом; Номиналиная индуктивность: 18 нГн; Добротность, не менее: 30; Резонансная частота, не менее: 3.10 ГГц; Сопротивление обмотки постоянноми току, не более: 0.170 Ом; Допустимый ток обмотки: 700 мА; Диапазон рабочих температур: от -60 до +125 ℃; Упаковка: Катушка и лента; Типоразмер: 1608 (0603); Технология монтажа: SMT; Изготовитель: АО "НПО "ЭРКОН"
footprint КИК-1608_О (Катушка индуктивности с керамическим сердечником  типоразмер 1005(0402))
pins: 1, 2

## КИК-1608-18 нГн ±10% Зл
designator L?, comment 18 нГн ±10%  (value not drawn)
Катушка индуктивности с керамическим сердечником и золотым покрытием контактных площадок; Номиналиная индуктивность: 18 нГн; Добротность, не менее: 30; Резонансная частота, не менее: 3.10 ГГц; Сопротивление обмотки постоянноми току, не более: 0.170 Ом; Допустимый ток обмотки: 700 мА; Диапазон рабочих температур: от -60 до +125 ℃; Упаковка: Катушка и лента; Типоразмер: 1608 (0603); Технология монтажа: SMT; Изготовитель: АО "НПО "ЭРКОН"
footprint КИК-1608_Зл (Катушка индуктивности с керамическим сердечником  типоразмер 1005(0402))
pins: 1, 2

## КИК-1608-18 нГн ±20% O
designator L?, comment 18 нГн ±20%  (value not drawn)
Катушка индуктивности с керамическим сердечником и  финишным покрытием контактных площадок оловом; Номиналиная индуктивность: 18 нГн; Добротность, не менее: 30; Резонансная частота, не менее: 3.10 ГГц; Сопротивление обмотки постоянноми току, не более: 0.170 Ом; Допустимый ток обмотки: 700 мА; Диапазон рабочих температур: от -60 до +125 ℃; Упаковка: Катушка и лента; Типоразмер: 1608 (0603); Технология монтажа: SMT; Изготовитель: АО "НПО "ЭРКОН"
footprint КИК-1608_О (Катушка индуктивности с керамическим сердечником  типоразмер 1005(0402))
pins: 1, 2


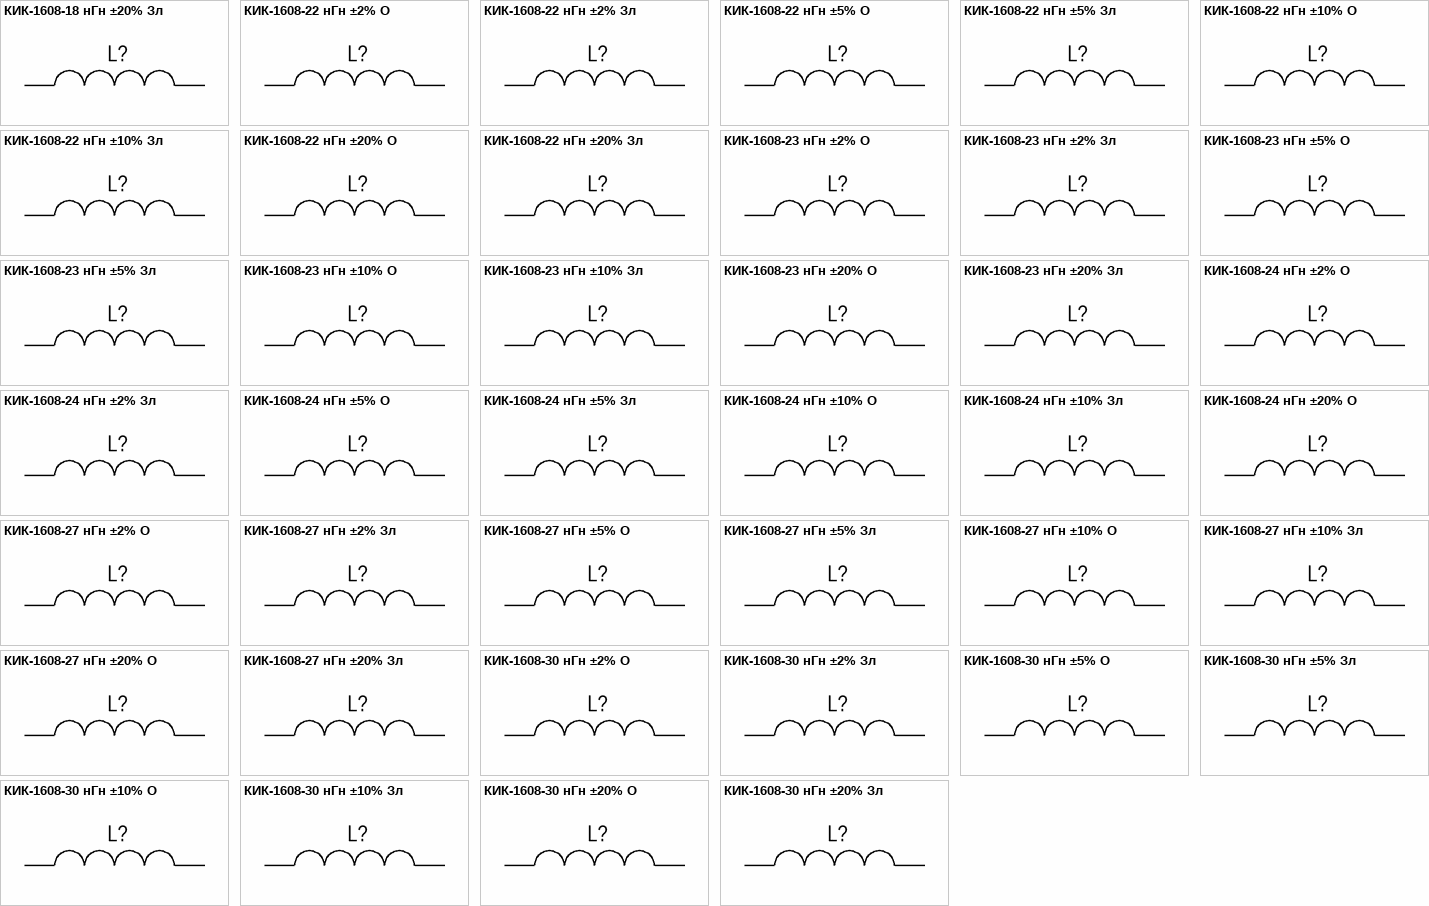
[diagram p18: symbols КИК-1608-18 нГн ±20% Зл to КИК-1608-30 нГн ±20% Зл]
## КИК-1608-18 нГн ±20% Зл
designator L?, comment 18 нГн ±20%  (value not drawn)
Катушка индуктивности с керамическим сердечником и золотым покрытием контактных площадок; Номиналиная индуктивность: 18 нГн; Добротность, не менее: 30; Резонансная частота, не менее: 3.10 ГГц; Сопротивление обмотки постоянноми току, не более: 0.170 Ом; Допустимый ток обмотки: 700 мА; Диапазон рабочих температур: от -60 до +125 ℃; Упаковка: Катушка и лента; Типоразмер: 1608 (0603); Технология монтажа: SMT; Изготовитель: АО "НПО "ЭРКОН"
footprint КИК-1608_Зл (Катушка индуктивности с керамическим сердечником  типоразмер 1005(0402))
pins: 1, 2

## КИК-1608-22 нГн ±2% O
designator L?, comment 22 нГн ±2%  (value not drawn)
Катушка индуктивности с керамическим сердечником и  финишным покрытием контактных площадок оловом; Номиналиная индуктивность: 22 нГн; Добротность, не менее: 35; Резонансная частота, не менее: 3.00 ГГц; Сопротивление обмотки постоянноми току, не более: 0.190 Ом; Допустимый ток обмотки: 700 мА; Диапазон рабочих температур: от -60 до +125 ℃; Упаковка: Катушка и лента; Типоразмер: 1608 (0603); Технология монтажа: SMT; Изготовитель: АО "НПО "ЭРКОН"
footprint КИК-1608_О (Катушка индуктивности с керамическим сердечником  типоразмер 1005(0402))
pins: 1, 2

## КИК-1608-22 нГн ±2% Зл
designator L?, comment 22 нГн ±2%  (value not drawn)
Катушка индуктивности с керамическим сердечником и золотым покрытием контактных площадок; Номиналиная индуктивность: 22 нГн; Добротность, не менее: 35; Резонансная частота, не менее: 3.00 ГГц; Сопротивление обмотки постоянноми току, не более: 0.190 Ом; Допустимый ток обмотки: 700 мА; Диапазон рабочих температур: от -60 до +125 ℃; Упаковка: Катушка и лента; Типоразмер: 1608 (0603); Технология монтажа: SMT; Изготовитель: АО "НПО "ЭРКОН"
footprint КИК-1608_Зл (Катушка индуктивности с керамическим сердечником  типоразмер 1005(0402))
pins: 1, 2

## КИК-1608-22 нГн ±5% O
designator L?, comment 22 нГн ±5%  (value not drawn)
Катушка индуктивности с керамическим сердечником и  финишным покрытием контактных площадок оловом; Номиналиная индуктивность: 22 нГн; Добротность, не менее: 35; Резонансная частота, не менее: 3.00 ГГц; Сопротивление обмотки постоянноми току, не более: 0.190 Ом; Допустимый ток обмотки: 700 мА; Диапазон рабочих температур: от -60 до +125 ℃; Упаковка: Катушка и лента; Типоразмер: 1608 (0603); Технология монтажа: SMT; Изготовитель: АО "НПО "ЭРКОН"
footprint КИК-1608_О (Катушка индуктивности с керамическим сердечником  типоразмер 1005(0402))
pins: 1, 2

## КИК-1608-22 нГн ±5% Зл
designator L?, comment 22 нГн ±5%  (value not drawn)
Катушка индуктивности с керамическим сердечником и золотым покрытием контактных площадок; Номиналиная индуктивность: 22 нГн; Добротность, не менее: 35; Резонансная частота, не менее: 3.00 ГГц; Сопротивление обмотки постоянноми току, не более: 0.190 Ом; Допустимый ток обмотки: 700 мА; Диапазон рабочих температур: от -60 до +125 ℃; Упаковка: Катушка и лента; Типоразмер: 1608 (0603); Технология монтажа: SMT; Изготовитель: АО "НПО "ЭРКОН"
footprint КИК-1608_Зл (Катушка индуктивности с керамическим сердечником  типоразмер 1005(0402))
pins: 1, 2

## КИК-1608-22 нГн ±10% O
designator L?, comment 22 нГн ±10%  (value not drawn)
Катушка индуктивности с керамическим сердечником и  финишным покрытием контактных площадок оловом; Номиналиная индуктивность: 22 нГн; Добротность, не менее: 35; Резонансная частота, не менее: 3.00 ГГц; Сопротивление обмотки постоянноми току, не более: 0.190 Ом; Допустимый ток обмотки: 700 мА; Диапазон рабочих температур: от -60 до +125 ℃; Упаковка: Катушка и лента; Типоразмер: 1608 (0603); Технология монтажа: SMT; Изготовитель: АО "НПО "ЭРКОН"
footprint КИК-1608_О (Катушка индуктивности с керамическим сердечником  типоразмер 1005(0402))
pins: 1, 2

## КИК-1608-22 нГн ±10% Зл
designator L?, comment 22 нГн ±10%  (value not drawn)
Катушка индуктивности с керамическим сердечником и золотым покрытием контактных площадок; Номиналиная индуктивность: 22 нГн; Добротность, не менее: 35; Резонансная частота, не менее: 3.00 ГГц; Сопротивление обмотки постоянноми току, не более: 0.190 Ом; Допустимый ток обмотки: 700 мА; Диапазон рабочих температур: от -60 до +125 ℃; Упаковка: Катушка и лента; Типоразмер: 1608 (0603); Технология монтажа: SMT; Изготовитель: АО "НПО "ЭРКОН"
footprint КИК-1608_Зл (Катушка индуктивности с керамическим сердечником  типоразмер 1005(0402))
pins: 1, 2

## КИК-1608-22 нГн ±20% O
designator L?, comment 22 нГн ±20%  (value not drawn)
Катушка индуктивности с керамическим сердечником и  финишным покрытием контактных площадок оловом; Номиналиная индуктивность: 22 нГн; Добротность, не менее: 35; Резонансная частота, не менее: 3.00 ГГц; Сопротивление обмотки постоянноми току, не более: 0.190 Ом; Допустимый ток обмотки: 700 мА; Диапазон рабочих температур: от -60 до +125 ℃; Упаковка: Катушка и лента; Типоразмер: 1608 (0603); Технология монтажа: SMT; Изготовитель: АО "НПО "ЭРКОН"
footprint КИК-1608_О (Катушка индуктивности с керамическим сердечником  типоразмер 1005(0402))
pins: 1, 2

## КИК-1608-22 нГн ±20% Зл
designator L?, comment 22 нГн ±20%  (value not drawn)
Катушка индуктивности с керамическим сердечником и золотым покрытием контактных площадок; Номиналиная индуктивность: 22 нГн; Добротность, не менее: 35; Резонансная частота, не менее: 3.00 ГГц; Сопротивление обмотки постоянноми току, не более: 0.190 Ом; Допустимый ток обмотки: 700 мА; Диапазон рабочих температур: от -60 до +125 ℃; Упаковка: Катушка и лента; Типоразмер: 1608 (0603); Технология монтажа: SMT; Изготовитель: АО "НПО "ЭРКОН"
footprint КИК-1608_Зл (Катушка индуктивности с керамическим сердечником  типоразмер 1005(0402))
pins: 1, 2

## КИК-1608-23 нГн ±2% O
designator L?, comment 23 нГн ±2%  (value not drawn)
Катушка индуктивности с керамическим сердечником и  финишным покрытием контактных площадок оловом; Номиналиная индуктивность: 23 нГн; Добротность, не менее: 35; Резонансная частота, не менее: 2.85 ГГц; Сопротивление обмотки постоянноми току, не более: 0.190 Ом; Допустимый ток обмотки: 700 мА; Диапазон рабочих температур: от -60 до +125 ℃; Упаковка: Катушка и лента; Типоразмер: 1608 (0603); Технология монтажа: SMT; Изготовитель: АО "НПО "ЭРКОН"
footprint КИК-1608_О (Катушка индуктивности с керамическим сердечником  типоразмер 1005(0402))
pins: 1, 2

## КИК-1608-23 нГн ±2% Зл
designator L?, comment 23 нГн ±2%  (value not drawn)
Катушка индуктивности с керамическим сердечником и золотым покрытием контактных площадок; Номиналиная индуктивность: 23 нГн; Добротность, не менее: 35; Резонансная частота, не менее: 2.85 ГГц; Сопротивление обмотки постоянноми току, не более: 0.190 Ом; Допустимый ток обмотки: 700 мА; Диапазон рабочих температур: от -60 до +125 ℃; Упаковка: Катушка и лента; Типоразмер: 1608 (0603); Технология монтажа: SMT; Изготовитель: АО "НПО "ЭРКОН"
footprint КИК-1608_Зл (Катушка индуктивности с керамическим сердечником  типоразмер 1005(0402))
pins: 1, 2

## КИК-1608-23 нГн ±5% O
designator L?, comment 23 нГн ±5%  (value not drawn)
Катушка индуктивности с керамическим сердечником и  финишным покрытием контактных площадок оловом; Номиналиная индуктивность: 23 нГн; Добротность, не менее: 35; Резонансная частота, не менее: 2.85 ГГц; Сопротивление обмотки постоянноми току, не более: 0.190 Ом; Допустимый ток обмотки: 700 мА; Диапазон рабочих температур: от -60 до +125 ℃; Упаковка: Катушка и лента; Типоразмер: 1608 (0603); Технология монтажа: SMT; Изготовитель: АО "НПО "ЭРКОН"
footprint КИК-1608_О (Катушка индуктивности с керамическим сердечником  типоразмер 1005(0402))
pins: 1, 2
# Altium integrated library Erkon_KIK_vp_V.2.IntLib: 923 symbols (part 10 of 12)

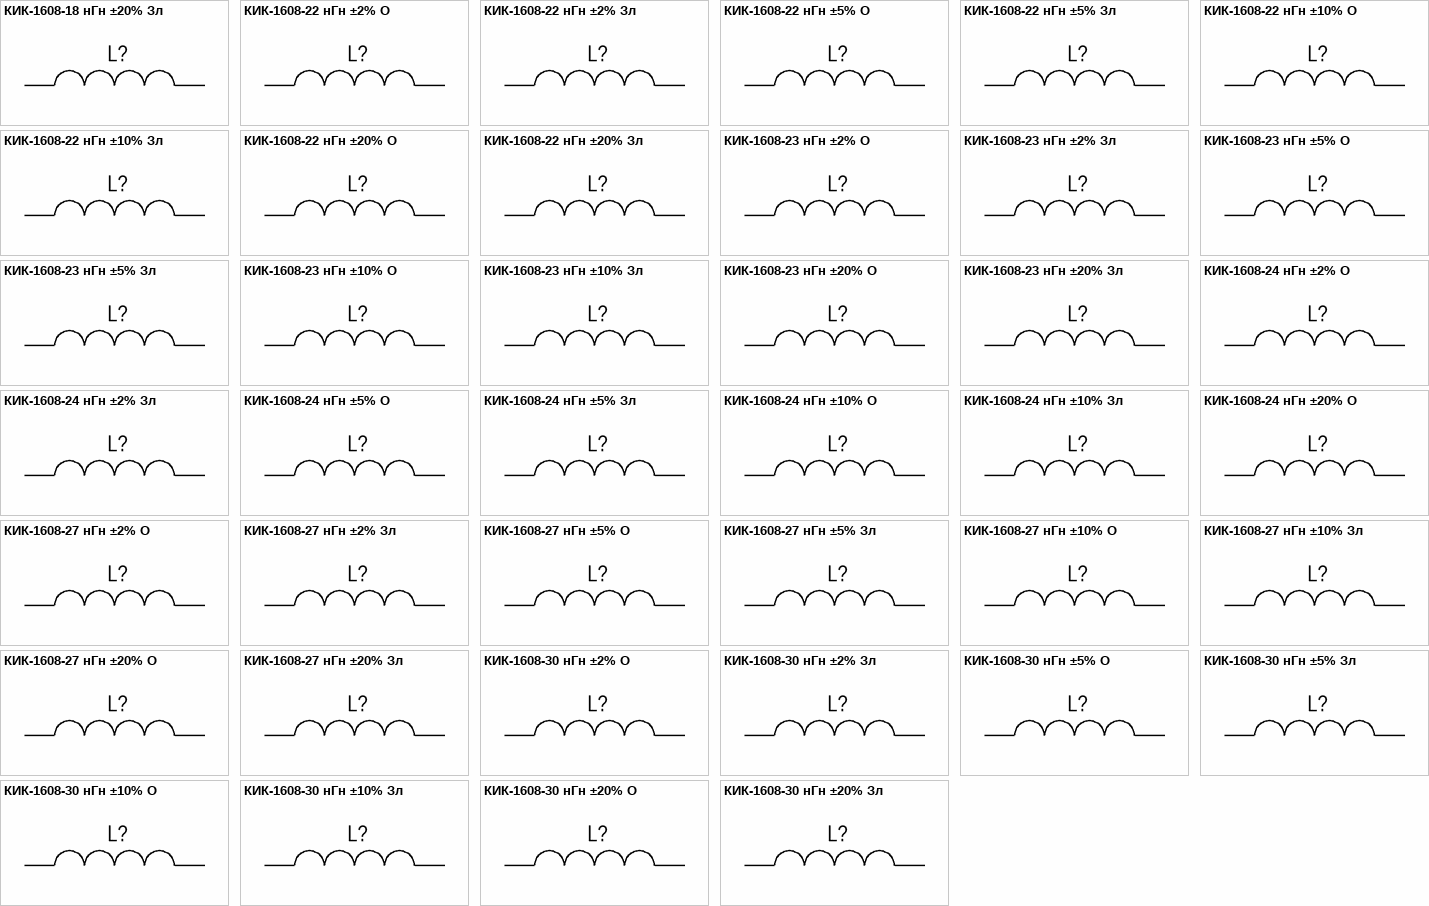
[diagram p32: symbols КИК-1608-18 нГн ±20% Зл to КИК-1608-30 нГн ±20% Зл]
## КИК-1608-23 нГн ±5% Зл
designator L?, comment 23 нГн ±5%  (value not drawn)
Катушка индуктивности с керамическим сердечником и золотым покрытием контактных площадок; Номиналиная индуктивность: 23 нГн; Добротность, не менее: 35; Резонансная частота, не менее: 2.85 ГГц; Сопротивление обмотки постоянноми току, не более: 0.190 Ом; Допустимый ток обмотки: 700 мА; Диапазон рабочих температур: от -60 до +125 ℃; Упаковка: Катушка и лента; Типоразмер: 1608 (0603); Технология монтажа: SMT; Изготовитель: АО "НПО "ЭРКОН"
footprint КИК-1608_Зл (Катушка индуктивности с керамическим сердечником  типоразмер 1005(0402))
pins: 1, 2

## КИК-1608-23 нГн ±10% O
designator L?, comment 23 нГн ±10%  (value not drawn)
Катушка индуктивности с керамическим сердечником и  финишным покрытием контактных площадок оловом; Номиналиная индуктивность: 23 нГн; Добротность, не менее: 35; Резонансная частота, не менее: 2.85 ГГц; Сопротивление обмотки постоянноми току, не более: 0.190 Ом; Допустимый ток обмотки: 700 мА; Диапазон рабочих температур: от -60 до +125 ℃; Упаковка: Катушка и лента; Типоразмер: 1608 (0603); Технология монтажа: SMT; Изготовитель: АО "НПО "ЭРКОН"
footprint КИК-1608_О (Катушка индуктивности с керамическим сердечником  типоразмер 1005(0402))
pins: 1, 2

## КИК-1608-23 нГн ±10% Зл
designator L?, comment 23 нГн ±10%  (value not drawn)
Катушка индуктивности с керамическим сердечником и золотым покрытием контактных площадок; Номиналиная индуктивность: 23 нГн; Добротность, не менее: 35; Резонансная частота, не менее: 2.85 ГГц; Сопротивление обмотки постоянноми току, не более: 0.190 Ом; Допустимый ток обмотки: 700 мА; Диапазон рабочих температур: от -60 до +125 ℃; Упаковка: Катушка и лента; Типоразмер: 1608 (0603); Технология монтажа: SMT; Изготовитель: АО "НПО "ЭРКОН"
footprint КИК-1608_Зл (Катушка индуктивности с керамическим сердечником  типоразмер 1005(0402))
pins: 1, 2

## КИК-1608-23 нГн ±20% O
designator L?, comment 23 нГн ±20%  (value not drawn)
Катушка индуктивности с керамическим сердечником и  финишным покрытием контактных площадок оловом; Номиналиная индуктивность: 23 нГн; Добротность, не менее: 35; Резонансная частота, не менее: 2.85 ГГц; Сопротивление обмотки постоянноми току, не более: 0.190 Ом; Допустимый ток обмотки: 700 мА; Диапазон рабочих температур: от -60 до +125 ℃; Упаковка: Катушка и лента; Типоразмер: 1608 (0603); Технология монтажа: SMT; Изготовитель: АО "НПО "ЭРКОН"
footprint КИК-1608_О (Катушка индуктивности с керамическим сердечником  типоразмер 1005(0402))
pins: 1, 2

## КИК-1608-23 нГн ±20% Зл
designator L?, comment 23 нГн ±20%  (value not drawn)
Катушка индуктивности с керамическим сердечником и золотым покрытием контактных площадок; Номиналиная индуктивность: 23 нГн; Добротность, не менее: 35; Резонансная частота, не менее: 2.85 ГГц; Сопротивление обмотки постоянноми току, не более: 0.190 Ом; Допустимый ток обмотки: 700 мА; Диапазон рабочих температур: от -60 до +125 ℃; Упаковка: Катушка и лента; Типоразмер: 1608 (0603); Технология монтажа: SMT; Изготовитель: АО "НПО "ЭРКОН"
footprint КИК-1608_Зл (Катушка индуктивности с керамическим сердечником  типоразмер 1005(0402))
pins: 1, 2

## КИК-1608-24 нГн ±2% O
designator L?, comment 24 нГн ±2%  (value not drawn)
Катушка индуктивности с керамическим сердечником и  финишным покрытием контактных площадок оловом; Номиналиная индуктивность: 24 нГн; Добротность, не менее: 35; Резонансная частота, не менее: 2.65 ГГц; Сопротивление обмотки постоянноми току, не более: 0.190 Ом; Допустимый ток обмотки: 700 мА; Диапазон рабочих температур: от -60 до +125 ℃; Упаковка: Катушка и лента; Типоразмер: 1608 (0603); Технология монтажа: SMT; Изготовитель: АО "НПО "ЭРКОН"
footprint КИК-1608_О (Катушка индуктивности с керамическим сердечником  типоразмер 1005(0402))
pins: 1, 2

## КИК-1608-24 нГн ±2% Зл
designator L?, comment 24 нГн ±2%  (value not drawn)
Катушка индуктивности с керамическим сердечником и золотым покрытием контактных площадок; Номиналиная индуктивность: 24 нГн; Добротность, не менее: 35; Резонансная частота, не менее: 2.65 ГГц; Сопротивление обмотки постоянноми току, не более: 0.190 Ом; Допустимый ток обмотки: 700 мА; Диапазон рабочих температур: от -60 до +125 ℃; Упаковка: Катушка и лента; Типоразмер: 1608 (0603); Технология монтажа: SMT; Изготовитель: АО "НПО "ЭРКОН"
footprint КИК-1608_Зл (Катушка индуктивности с керамическим сердечником  типоразмер 1005(0402))
pins: 1, 2

## КИК-1608-24 нГн ±5% O
designator L?, comment 24 нГн ±5%  (value not drawn)
Катушка индуктивности с керамическим сердечником и  финишным покрытием контактных площадок оловом; Номиналиная индуктивность: 24 нГн; Добротность, не менее: 35; Резонансная частота, не менее: 2.65 ГГц; Сопротивление обмотки постоянноми току, не более: 0.190 Ом; Допустимый ток обмотки: 700 мА; Диапазон рабочих температур: от -60 до +125 ℃; Упаковка: Катушка и лента; Типоразмер: 1608 (0603); Технология монтажа: SMT; Изготовитель: АО "НПО "ЭРКОН"
footprint КИК-1608_О (Катушка индуктивности с керамическим сердечником  типоразмер 1005(0402))
pins: 1, 2

## КИК-1608-24 нГн ±5% Зл
designator L?, comment 24 нГн ±5%  (value not drawn)
Катушка индуктивности с керамическим сердечником и золотым покрытием контактных площадок; Номиналиная индуктивность: 24 нГн; Добротность, не менее: 35; Резонансная частота, не менее: 2.65 ГГц; Сопротивление обмотки постоянноми току, не более: 0.190 Ом; Допустимый ток обмотки: 700 мА; Диапазон рабочих температур: от -60 до +125 ℃; Упаковка: Катушка и лента; Типоразмер: 1608 (0603); Технология монтажа: SMT; Изготовитель: АО "НПО "ЭРКОН"
footprint КИК-1608_Зл (Катушка индуктивности с керамическим сердечником  типоразмер 1005(0402))
pins: 1, 2

## КИК-1608-24 нГн ±10% O
designator L?, comment 24 нГн ±10%  (value not drawn)
Катушка индуктивности с керамическим сердечником и  финишным покрытием контактных площадок оловом; Номиналиная индуктивность: 24 нГн; Добротность, не менее: 35; Резонансная частота, не менее: 2.65 ГГц; Сопротивление обмотки постоянноми току, не более: 0.190 Ом; Допустимый ток обмотки: 700 мА; Диапазон рабочих температур: от -60 до +125 ℃; Упаковка: Катушка и лента; Типоразмер: 1608 (0603); Технология монтажа: SMT; Изготовитель: АО "НПО "ЭРКОН"
footprint КИК-1608_О (Катушка индуктивности с керамическим сердечником  типоразмер 1005(0402))
pins: 1, 2

## КИК-1608-24 нГн ±10% Зл
designator L?, comment 24 нГн ±10%  (value not drawn)
Катушка индуктивности с керамическим сердечником и золотым покрытием контактных площадок; Номиналиная индуктивность: 24 нГн; Добротность, не менее: 35; Резонансная частота, не менее: 2.65 ГГц; Сопротивление обмотки постоянноми току, не более: 0.190 Ом; Допустимый ток обмотки: 700 мА; Диапазон рабочих температур: от -60 до +125 ℃; Упаковка: Катушка и лента; Типоразмер: 1608 (0603); Технология монтажа: SMT; Изготовитель: АО "НПО "ЭРКОН"
footprint КИК-1608_Зл (Катушка индуктивности с керамическим сердечником  типоразмер 1005(0402))
pins: 1, 2

## КИК-1608-24 нГн ±20% O
designator L?, comment 24 нГн ±20%  (value not drawn)
Катушка индуктивности с керамическим сердечником и  финишным покрытием контактных площадок оловом; Номиналиная индуктивность: 24 нГн; Добротность, не менее: 35; Резонансная частота, не менее: 2.65 ГГц; Сопротивление обмотки постоянноми току, не более: 0.190 Ом; Допустимый ток обмотки: 700 мА; Диапазон рабочих температур: от -60 до +125 ℃; Упаковка: Катушка и лента; Типоразмер: 1608 (0603); Технология монтажа: SMT; Изготовитель: АО "НПО "ЭРКОН"
footprint КИК-1608_О (Катушка индуктивности с керамическим сердечником  типоразмер 1005(0402))
pins: 1, 2

## КИК-1608-27 нГн ±2% O
designator L?, comment 27 нГн ±2%  (value not drawn)
Катушка индуктивности с керамическим сердечником и  финишным покрытием контактных площадок оловом; Номиналиная индуктивность: 27 нГн; Добротность, не менее: 35; Резонансная частота, не менее: 2.80 ГГц; Сопротивление обмотки постоянноми току, не более: 0.220 Ом; Допустимый ток обмотки: 600 мА; Диапазон рабочих температур: от -60 до +125 ℃; Упаковка: Катушка и лента; Типоразмер: 1608 (0603); Технология монтажа: SMT; Изготовитель: АО "НПО "ЭРКОН"
footprint КИК-1608_О (Катушка индуктивности с керамическим сердечником  типоразмер 1005(0402))
pins: 1, 2

## КИК-1608-27 нГн ±2% Зл
designator L?, comment 27 нГн ±2%  (value not drawn)
Катушка индуктивности с керамическим сердечником и золотым покрытием контактных площадок; Номиналиная индуктивность: 27нГн; Добротность, не менее: 35; Резонансная частота, не менее: 2.80 ГГц; Сопротивление обмотки постоянноми току, не более: 0.220 Ом; Допустимый ток обмотки: 600 мА; Диапазон рабочих температур: от -60 до +125 ℃; Упаковка: Катушка и лента; Типоразмер: 1608 (0603); Технология монтажа: SMT; Изготовитель: АО "НПО "ЭРКОН"
footprint КИК-1608_Зл (Катушка индуктивности с керамическим сердечником  типоразмер 1005(0402))
pins: 1, 2

## КИК-1608-27 нГн ±5% O
designator L?, comment 27 нГн ±5%  (value not drawn)
Катушка индуктивности с керамическим сердечником и  финишным покрытием контактных площадок оловом; Номиналиная индуктивность: 27 нГн; Добротность, не менее: 35; Резонансная частота, не менее: 2.80 ГГц; Сопротивление обмотки постоянноми току, не более: 0.220 Ом; Допустимый ток обмотки: 600 мА; Диапазон рабочих температур: от -60 до +125 ℃; Упаковка: Катушка и лента; Типоразмер: 1608 (0603); Технология монтажа: SMT; Изготовитель: АО "НПО "ЭРКОН"
footprint КИК-1608_О (Катушка индуктивности с керамическим сердечником  типоразмер 1005(0402))
pins: 1, 2

## КИК-1608-27 нГн ±5% Зл
designator L?, comment 27 нГн ±5%  (value not drawn)
Катушка индуктивности с керамическим сердечником и золотым покрытием контактных площадок; Номиналиная индуктивность: 27 нГн; Добротность, не менее: 35; Резонансная частота, не менее: 2.80 ГГц; Сопротивление обмотки постоянноми току, не более: 0.220 Ом; Допустимый ток обмотки: 600 мА; Диапазон рабочих температур: от -60 до +125 ℃; Упаковка: Катушка и лента; Типоразмер: 1608 (0603); Технология монтажа: SMT; Изготовитель: АО "НПО "ЭРКОН"
footprint КИК-1608_Зл (Катушка индуктивности с керамическим сердечником  типоразмер 1005(0402))
pins: 1, 2

## КИК-1608-27 нГн ±10% O
designator L?, comment 27 нГн ±10%  (value not drawn)
Катушка индуктивности с керамическим сердечником и  финишным покрытием контактных площадок оловом; Номиналиная индуктивность: 27 нГн; Добротность, не менее: 35; Резонансная частота, не менее: 2.80 ГГц; Сопротивление обмотки постоянноми току, не более: 0.220 Ом; Допустимый ток обмотки: 600 мА; Диапазон рабочих температур: от -60 до +125 ℃; Упаковка: Катушка и лента; Типоразмер: 1608 (0603); Технология монтажа: SMT; Изготовитель: АО "НПО "ЭРКОН"
footprint КИК-1608_О (Катушка индуктивности с керамическим сердечником  типоразмер 1005(0402))
pins: 1, 2

## КИК-1608-27 нГн ±10% Зл
designator L?, comment 27 нГн ±10%  (value not drawn)
Катушка индуктивности с керамическим сердечником и золотым покрытием контактных площадок; Номиналиная индуктивность: 27нГн; Добротность, не менее: 35; Резонансная частота, не менее: 2.80 ГГц; Сопротивление обмотки постоянноми току, не более: 0.220 Ом; Допустимый ток обмотки: 600 мА; Диапазон рабочих температур: от -60 до +125 ℃; Упаковка: Катушка и лента; Типоразмер: 1608 (0603); Технология монтажа: SMT; Изготовитель: АО "НПО "ЭРКОН"
footprint КИК-1608_Зл (Катушка индуктивности с керамическим сердечником  типоразмер 1005(0402))
pins: 1, 2

## КИК-1608-27 нГн ±20% O
designator L?, comment 27 нГн ±20%  (value not drawn)
Катушка индуктивности с керамическим сердечником и  финишным покрытием контактных площадок оловом; Номиналиная индуктивность: 27 нГн; Добротность, не менее: 35; Резонансная частота, не менее: 2.80 ГГц; Сопротивление обмотки постоянноми току, не более: 0.220 Ом; Допустимый ток обмотки: 600 мА; Диапазон рабочих температур: от -60 до +125 ℃; Упаковка: Катушка и лента; Типоразмер: 1608 (0603); Технология монтажа: SMT; Изготовитель: АО "НПО "ЭРКОН"
footprint КИК-1608_О (Катушка индуктивности с керамическим сердечником  типоразмер 1005(0402))
pins: 1, 2

## КИК-1608-27 нГн ±20% Зл
designator L?, comment 27 нГн ±20%  (value not drawn)
Катушка индуктивности с керамическим сердечником и золотым покрытием контактных площадок; Номиналиная индуктивность: 27нГн; Добротность, не менее: 35; Резонансная частота, не менее: 2.80 ГГц; Сопротивление обмотки постоянноми току, не более: 0.220 Ом; Допустимый ток обмотки: 600 мА; Диапазон рабочих температур: от -60 до +125 ℃; Упаковка: Катушка и лента; Типоразмер: 1608 (0603); Технология монтажа: SMT; Изготовитель: АО "НПО "ЭРКОН"
footprint КИК-1608_Зл (Катушка индуктивности с керамическим сердечником  типоразмер 1005(0402))
pins: 1, 2

## КИК-1608-30 нГн ±2% O
designator L?, comment 30 нГн ±2%  (value not drawn)
Катушка индуктивности с керамическим сердечником и  финишным покрытием контактных площадок оловом; Номиналиная индуктивность: 30 нГн; Добротность, не менее: 35; Резонансная частота, не менее: 2.25 ГГц; Сопротивление обмотки постоянноми току, не более: 0.220 Ом; Допустимый ток обмотки: 600 мА; Диапазон рабочих температур: от -60 до +125 ℃; Упаковка: Катушка и лента; Типоразмер: 1608 (0603); Технология монтажа: SMT; Изготовитель: АО "НПО "ЭРКОН"
footprint КИК-1608_О (Катушка индуктивности с керамическим сердечником  типоразмер 1005(0402))
pins: 1, 2

## КИК-1608-30 нГн ±2% Зл
designator L?, comment 30 нГн ±2%  (value not drawn)
Катушка индуктивности с керамическим сердечником и золотым покрытием контактных площадок; Номиналиная индуктивность: 30 нГн; Добротность, не менее: 35; Резонансная частота, не менее: 2.25 ГГц; Сопротивление обмотки постоянноми току, не более: 0.220 Ом; Допустимый ток обмотки: 600 мА; Диапазон рабочих температур: от -60 до +125 ℃; Упаковка: Катушка и лента; Типоразмер: 1608 (0603); Технология монтажа: SMT; Изготовитель: АО "НПО "ЭРКОН"
footprint КИК-1608_Зл (Катушка индуктивности с керамическим сердечником  типоразмер 1005(0402))
pins: 1, 2

## КИК-1608-30 нГн ±5% O
designator L?, comment 30 нГн ±5%  (value not drawn)
Катушка индуктивности с керамическим сердечником и  финишным покрытием контактных площадок оловом; Номиналиная индуктивность: 30 нГн; Добротность, не менее: 35; Резонансная частота, не менее: 2.25 ГГц; Сопротивление обмотки постоянноми току, не более: 0.220 Ом; Допустимый ток обмотки: 600 мА; Диапазон рабочих температур: от -60 до +125 ℃; Упаковка: Катушка и лента; Типоразмер: 1608 (0603); Технология монтажа: SMT; Изготовитель: АО "НПО "ЭРКОН"
footprint КИК-1608_О (Катушка индуктивности с керамическим сердечником  типоразмер 1005(0402))
pins: 1, 2

## КИК-1608-30 нГн ±5% Зл
designator L?, comment 30 нГн ±5%  (value not drawn)
Катушка индуктивности с керамическим сердечником и золотым покрытием контактных площадок; Номиналиная индуктивность: 30 нГн; Добротность, не менее: 35; Резонансная частота, не менее: 2.25 ГГц; Сопротивление обмотки постоянноми току, не более: 0.220 Ом; Допустимый ток обмотки: 600 мА; Диапазон рабочих температур: от -60 до +125 ℃; Упаковка: Катушка и лента; Типоразмер: 1608 (0603); Технология монтажа: SMT; Изготовитель: АО "НПО "ЭРКОН"
footprint КИК-1608_Зл (Катушка индуктивности с керамическим сердечником  типоразмер 1005(0402))
pins: 1, 2

## КИК-1608-30 нГн ±10% O
designator L?, comment 30 нГн ±10%  (value not drawn)
Катушка индуктивности с керамическим сердечником и  финишным покрытием контактных площадок оловом; Номиналиная индуктивность: 30 нГн; Добротность, не менее: 35; Резонансная частота, не менее: 2.25 ГГц; Сопротивление обмотки постоянноми току, не более: 0.220 Ом; Допустимый ток обмотки: 600 мА; Диапазон рабочих температур: от -60 до +125 ℃; Упаковка: Катушка и лента; Типоразмер: 1608 (0603); Технология монтажа: SMT; Изготовитель: АО "НПО "ЭРКОН"
footprint КИК-1608_О (Катушка индуктивности с керамическим сердечником  типоразмер 1005(0402))
pins: 1, 2

## КИК-1608-30 нГн ±10% Зл
designator L?, comment 30 нГн ±10%  (value not drawn)
Катушка индуктивности с керамическим сердечником и золотым покрытием контактных площадок; Номиналиная индуктивность: 30 нГн; Добротность, не менее: 35; Резонансная частота, не менее: 2.25 ГГц; Сопротивление обмотки постоянноми току, не более: 0.220 Ом; Допустимый ток обмотки: 600 мА; Диапазон рабочих температур: от -60 до +125 ℃; Упаковка: Катушка и лента; Типоразмер: 1608 (0603); Технология монтажа: SMT; Изготовитель: АО "НПО "ЭРКОН"
footprint КИК-1608_Зл (Катушка индуктивности с керамическим сердечником  типоразмер 1005(0402))
pins: 1, 2

## КИК-1608-30 нГн ±20% O
designator L?, comment 30 нГн ±20%  (value not drawn)
Катушка индуктивности с керамическим сердечником и  финишным покрытием контактных площадок оловом; Номиналиная индуктивность: 30 нГн; Добротность, не менее: 35; Резонансная частота, не менее: 2.25 ГГц; Сопротивление обмотки постоянноми току, не более: 0.220 Ом; Допустимый ток обмотки: 600 мА; Диапазон рабочих температур: от -60 до +125 ℃; Упаковка: Катушка и лента; Типоразмер: 1608 (0603); Технология монтажа: SMT; Изготовитель: АО "НПО "ЭРКОН"
footprint КИК-1608_О (Катушка индуктивности с керамическим сердечником  типоразмер 1005(0402))
pins: 1, 2

## КИК-1608-30 нГн ±20% Зл
designator L?, comment 30 нГн ±20%  (value not drawn)
Катушка индуктивности с керамическим сердечником и золотым покрытием контактных площадок; Номиналиная индуктивность: 30 нГн; Добротность, не менее: 35; Резонансная частота, не менее: 2.25 ГГц; Сопротивление обмотки постоянноми току, не более: 0.220 Ом; Допустимый ток обмотки: 600 мА; Диапазон рабочих температур: от -60 до +125 ℃; Упаковка: Катушка и лента; Типоразмер: 1608 (0603); Технология монтажа: SMT; Изготовитель: АО "НПО "ЭРКОН"
footprint КИК-1608_Зл (Катушка индуктивности с керамическим сердечником  типоразмер 1005(0402))
pins: 1, 2


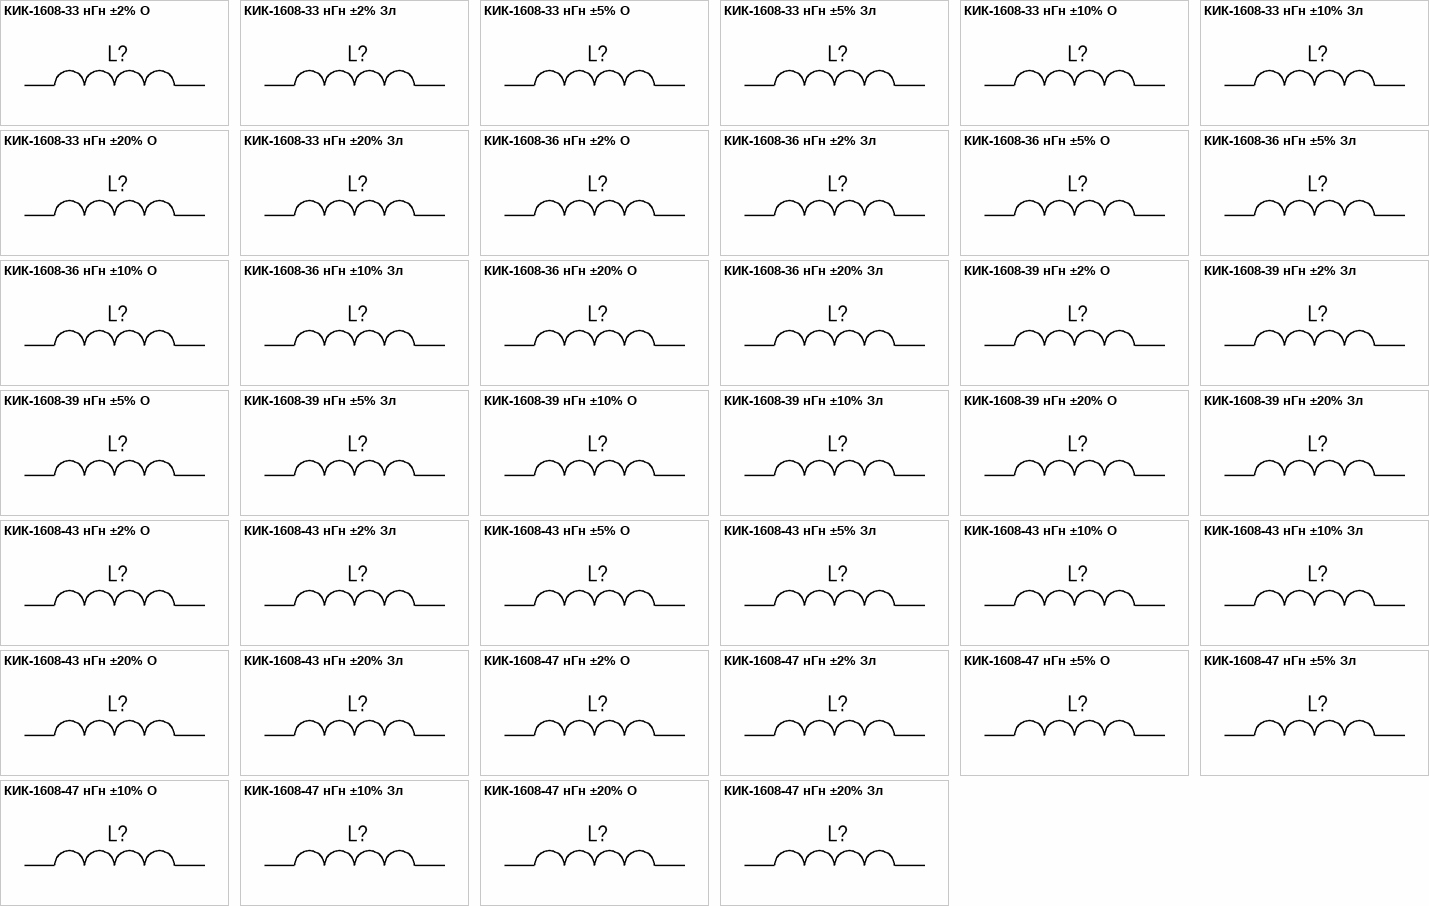
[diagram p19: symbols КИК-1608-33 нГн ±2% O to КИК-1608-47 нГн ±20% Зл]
## КИК-1608-33 нГн ±2% O
designator L?, comment 33 нГн ±2%  (value not drawn)
Катушка индуктивности с керамическим сердечником и  финишным покрытием контактных площадок оловом; Номиналиная индуктивность: 33 нГн; Добротность, не менее: 35; Резонансная частота, не менее: 2.30 ГГц; Сопротивление обмотки постоянноми току, не более: 0.220 Ом; Допустимый ток обмотки: 600 мА; Диапазон рабочих температур: от -60 до +125 ℃; Упаковка: Катушка и лента; Типоразмер: 1608 (0603); Технология монтажа: SMT; Изготовитель: АО "НПО "ЭРКОН"
footprint КИК-1608_О (Катушка индуктивности с керамическим сердечником  типоразмер 1005(0402))
pins: 1, 2

## КИК-1608-33 нГн ±2% Зл
designator L?, comment 33 нГн ±2%  (value not drawn)
Катушка индуктивности с керамическим сердечником и золотым покрытием контактных площадок; Номиналиная индуктивность: 33 нГн; Добротность, не менее: 35; Резонансная частота, не менее: 2.30 ГГц; Сопротивление обмотки постоянноми току, не более: 0.220 Ом; Допустимый ток обмотки: 600 мА; Диапазон рабочих температур: от -60 до +125 ℃; Упаковка: Катушка и лента; Типоразмер: 1608 (0603); Технология монтажа: SMT; Изготовитель: АО "НПО "ЭРКОН"
footprint КИК-1608_Зл (Катушка индуктивности с керамическим сердечником  типоразмер 1005(0402))
pins: 1, 2

## КИК-1608-33 нГн ±5% O
designator L?, comment 33 нГн ±5%  (value not drawn)
Катушка индуктивности с керамическим сердечником и  финишным покрытием контактных площадок оловом; Номиналиная индуктивность: 33 нГн; Добротность, не менее: 35; Резонансная частота, не менее: 2.30 ГГц; Сопротивление обмотки постоянноми току, не более: 0.220 Ом; Допустимый ток обмотки: 600 мА; Диапазон рабочих температур: от -60 до +125 ℃; Упаковка: Катушка и лента; Типоразмер: 1608 (0603); Технология монтажа: SMT; Изготовитель: АО "НПО "ЭРКОН"
footprint КИК-1608_О (Катушка индуктивности с керамическим сердечником  типоразмер 1005(0402))
pins: 1, 2

## КИК-1608-33 нГн ±5% Зл
designator L?, comment 33 нГн ±5%  (value not drawn)
Катушка индуктивности с керамическим сердечником и золотым покрытием контактных площадок; Номиналиная индуктивность: 33 нГн; Добротность, не менее: 35; Резонансная частота, не менее: 2.30 ГГц; Сопротивление обмотки постоянноми току, не более: 0.220 Ом; Допустимый ток обмотки: 600 мА; Диапазон рабочих температур: от -60 до +125 ℃; Упаковка: Катушка и лента; Типоразмер: 1608 (0603); Технология монтажа: SMT; Изготовитель: АО "НПО "ЭРКОН"
footprint КИК-1608_Зл (Катушка индуктивности с керамическим сердечником  типоразмер 1005(0402))
pins: 1, 2

## КИК-1608-33 нГн ±10% O
designator L?, comment 33 нГн ±10%  (value not drawn)
Катушка индуктивности с керамическим сердечником и  финишным покрытием контактных площадок оловом; Номиналиная индуктивность: 33 нГн; Добротность, не менее: 35; Резонансная частота, не менее: 2.30 ГГц; Сопротивление обмотки постоянноми току, не более: 0.220 Ом; Допустимый ток обмотки: 600 мА; Диапазон рабочих температур: от -60 до +125 ℃; Упаковка: Катушка и лента; Типоразмер: 1608 (0603); Технология монтажа: SMT; Изготовитель: АО "НПО "ЭРКОН"
footprint КИК-1608_О (Катушка индуктивности с керамическим сердечником  типоразмер 1005(0402))
pins: 1, 2

## КИК-1608-33 нГн ±10% Зл
designator L?, comment 33 нГн ±10%  (value not drawn)
Катушка индуктивности с керамическим сердечником и золотым покрытием контактных площадок; Номиналиная индуктивность: 33 нГн; Добротность, не менее: 35; Резонансная частота, не менее: 2.30 ГГц; Сопротивление обмотки постоянноми току, не более: 0.220 Ом; Допустимый ток обмотки: 600 мА; Диапазон рабочих температур: от -60 до +125 ℃; Упаковка: Катушка и лента; Типоразмер: 1608 (0603); Технология монтажа: SMT; Изготовитель: АО "НПО "ЭРКОН"
footprint КИК-1608_Зл (Катушка индуктивности с керамическим сердечником  типоразмер 1005(0402))
pins: 1, 2

## КИК-1608-33 нГн ±20% O
designator L?, comment 33 нГн ±20%  (value not drawn)
Катушка индуктивности с керамическим сердечником и  финишным покрытием контактных площадок оловом; Номиналиная индуктивность: 33 нГн; Добротность, не менее: 35; Резонансная частота, не менее: 2.30 ГГц; Сопротивление обмотки постоянноми току, не более: 0.220 Ом; Допустимый ток обмотки: 600 мА; Диапазон рабочих температур: от -60 до +125 ℃; Упаковка: Катушка и лента; Типоразмер: 1608 (0603); Технология монтажа: SMT; Изготовитель: АО "НПО "ЭРКОН"
footprint КИК-1608_О (Катушка индуктивности с керамическим сердечником  типоразмер 1005(0402))
pins: 1, 2

## КИК-1608-33 нГн ±20% Зл
designator L?, comment 33 нГн ±20%  (value not drawn)
Катушка индуктивности с керамическим сердечником и золотым покрытием контактных площадок; Номиналиная индуктивность: 33 нГн; Добротность, не менее: 35; Резонансная частота, не менее: 2.30 ГГц; Сопротивление обмотки постоянноми току, не более: 0.220 Ом; Допустимый ток обмотки: 600 мА; Диапазон рабочих температур: от -60 до +125 ℃; Упаковка: Катушка и лента; Типоразмер: 1608 (0603); Технология монтажа: SMT; Изготовитель: АО "НПО "ЭРКОН"
footprint КИК-1608_Зл (Катушка индуктивности с керамическим сердечником  типоразмер 1005(0402))
pins: 1, 2

## КИК-1608-36 нГн ±2% O
designator L?, comment 36 нГн ±2%  (value not drawn)
Катушка индуктивности с керамическим сердечником и  финишным покрытием контактных площадок оловом; Номиналиная индуктивность: 36 нГн; Добротность, не менее: 35; Резонансная частота, не менее: 2.08ГГц; Сопротивление обмотки постоянноми току, не более: 0.250 Ом; Допустимый ток обмотки: 600 мА; Диапазон рабочих температур: от -60 до +125 ℃; Упаковка: Катушка и лента; Типоразмер: 1608 (0603); Технология монтажа: SMT; Изготовитель: АО "НПО "ЭРКОН"
footprint КИК-1608_О (Катушка индуктивности с керамическим сердечником  типоразмер 1005(0402))
pins: 1, 2

## КИК-1608-36 нГн ±2% Зл
designator L?, comment 36 нГн ±2%  (value not drawn)
Катушка индуктивности с керамическим сердечником и золотым покрытием контактных площадок; Номиналиная индуктивность: 36 нГн; Добротность, не менее: 35; Резонансная частота, не менее: 2.08ГГц; Сопротивление обмотки постоянноми току, не более: 0.250 Ом; Допустимый ток обмотки: 600 мА; Диапазон рабочих температур: от -60 до +125 ℃; Упаковка: Катушка и лента; Типоразмер: 1608 (0603); Технология монтажа: SMT; Изготовитель: АО "НПО "ЭРКОН"
footprint КИК-1608_Зл (Катушка индуктивности с керамическим сердечником  типоразмер 1005(0402))
pins: 1, 2

## КИК-1608-36 нГн ±5% O
designator L?, comment 36 нГн ±5%  (value not drawn)
Катушка индуктивности с керамическим сердечником и  финишным покрытием контактных площадок оловом; Номиналиная индуктивность: 36 нГн; Добротность, не менее: 35; Резонансная частота, не менее: 2.08ГГц; Сопротивление обмотки постоянноми току, не более: 0.250 Ом; Допустимый ток обмотки: 600 мА; Диапазон рабочих температур: от -60 до +125 ℃; Упаковка: Катушка и лента; Типоразмер: 1608 (0603); Технология монтажа: SMT; Изготовитель: АО "НПО "ЭРКОН"
footprint КИК-1608_О (Катушка индуктивности с керамическим сердечником  типоразмер 1005(0402))
pins: 1, 2

## КИК-1608-36 нГн ±5% Зл
designator L?, comment 36 нГн ±5%  (value not drawn)
Катушка индуктивности с керамическим сердечником и золотым покрытием контактных площадок; Номиналиная индуктивность: 36 нГн; Добротность, не менее: 35; Резонансная частота, не менее: 2.08ГГц; Сопротивление обмотки постоянноми току, не более: 0.250 Ом; Допустимый ток обмотки: 600 мА; Диапазон рабочих температур: от -60 до +125 ℃; Упаковка: Катушка и лента; Типоразмер: 1608 (0603); Технология монтажа: SMT; Изготовитель: АО "НПО "ЭРКОН"
footprint КИК-1608_Зл (Катушка индуктивности с керамическим сердечником  типоразмер 1005(0402))
pins: 1, 2

## КИК-1608-36 нГн ±10% O
designator L?, comment 36 нГн ±10%  (value not drawn)
Катушка индуктивности с керамическим сердечником и  финишным покрытием контактных площадок оловом; Номиналиная индуктивность: 36 нГн; Добротность, не менее: 35; Резонансная частота, не менее: 2.08ГГц; Сопротивление обмотки постоянноми току, не более: 0.250 Ом; Допустимый ток обмотки: 600 мА; Диапазон рабочих температур: от -60 до +125 ℃; Упаковка: Катушка и лента; Типоразмер: 1608 (0603); Технология монтажа: SMT; Изготовитель: АО "НПО "ЭРКОН"
footprint КИК-1608_О (Катушка индуктивности с керамическим сердечником  типоразмер 1005(0402))
pins: 1, 2

## КИК-1608-36 нГн ±10% Зл
designator L?, comment 36 нГн ±10%  (value not drawn)
Катушка индуктивности с керамическим сердечником и золотым покрытием контактных площадок; Номиналиная индуктивность: 36 нГн; Добротность, не менее: 35; Резонансная частота, не менее: 2.08ГГц; Сопротивление обмотки постоянноми току, не более: 0.250 Ом; Допустимый ток обмотки: 600 мА; Диапазон рабочих температур: от -60 до +125 ℃; Упаковка: Катушка и лента; Типоразмер: 1608 (0603); Технология монтажа: SMT; Изготовитель: АО "НПО "ЭРКОН"
footprint КИК-1608_Зл (Катушка индуктивности с керамическим сердечником  типоразмер 1005(0402))
pins: 1, 2

## КИК-1608-36 нГн ±20% O
designator L?, comment 36 нГн ±20%  (value not drawn)
Катушка индуктивности с керамическим сердечником и  финишным покрытием контактных площадок оловом; Номиналиная индуктивность: 36 нГн; Добротность, не менее: 35; Резонансная частота, не менее: 2.08ГГц; Сопротивление обмотки постоянноми току, не более: 0.250 Ом; Допустимый ток обмотки: 600 мА; Диапазон рабочих температур: от -60 до +125 ℃; Упаковка: Катушка и лента; Типоразмер: 1608 (0603); Технология монтажа: SMT; Изготовитель: АО "НПО "ЭРКОН"
footprint КИК-1608_О (Катушка индуктивности с керамическим сердечником  типоразмер 1005(0402))
pins: 1, 2

## КИК-1608-36 нГн ±20% Зл
designator L?, comment 36 нГн ±20%  (value not drawn)
Катушка индуктивности с керамическим сердечником и золотым покрытием контактных площадок; Номиналиная индуктивность: 36 нГн; Добротность, не менее: 35; Резонансная частота, не менее: 2.08ГГц; Сопротивление обмотки постоянноми току, не более: 0.250 Ом; Допустимый ток обмотки: 600 мА; Диапазон рабочих температур: от -60 до +125 ℃; Упаковка: Катушка и лента; Типоразмер: 1608 (0603); Технология монтажа: SMT; Изготовитель: АО "НПО "ЭРКОН"
footprint КИК-1608_Зл (Катушка индуктивности с керамическим сердечником  типоразмер 1005(0402))
pins: 1, 2

## КИК-1608-39 нГн ±2% O
designator L?, comment 39 нГн ±2%  (value not drawn)
Катушка индуктивности с керамическим сердечником и  финишным покрытием контактных площадок оловом; Номиналиная индуктивность: 39 нГн; Добротность, не менее: 35; Резонансная частота, не менее: 2.20 ГГц; Сопротивление обмотки постоянноми току, не более: 0.250 Ом; Допустимый ток обмотки: 600 мА; Диапазон рабочих температур: от -60 до +125 ℃; Упаковка: Катушка и лента; Типоразмер: 1608 (0603); Технология монтажа: SMT; Изготовитель: АО "НПО "ЭРКОН"
footprint КИК-1608_О (Катушка индуктивности с керамическим сердечником  типоразмер 1005(0402))
pins: 1, 2

## КИК-1608-39 нГн ±2% Зл
designator L?, comment 39 нГн ±2%  (value not drawn)
Катушка индуктивности с керамическим сердечником и золотым покрытием контактных площадок; Номиналиная индуктивность: 39 нГн; Добротность, не менее: 35; Резонансная частота, не менее: 2.20 ГГц; Сопротивление обмотки постоянноми току, не более: 0.250 Ом; Допустимый ток обмотки: 600 мА; Диапазон рабочих температур: от -60 до +125 ℃; Упаковка: Катушка и лента; Типоразмер: 1608 (0603); Технология монтажа: SMT; Изготовитель: АО "НПО "ЭРКОН"
footprint КИК-1608_Зл (Катушка индуктивности с керамическим сердечником  типоразмер 1005(0402))
pins: 1, 2

## КИК-1608-39 нГн ±5% O
designator L?, comment 39 нГн ±5%  (value not drawn)
Катушка индуктивности с керамическим сердечником и  финишным покрытием контактных площадок оловом; Номиналиная индуктивность: 39 нГн; Добротность, не менее: 35; Резонансная частота, не менее: 2.20 ГГц; Сопротивление обмотки постоянноми току, не более: 0.250 Ом; Допустимый ток обмотки: 600 мА; Диапазон рабочих температур: от -60 до +125 ℃; Упаковка: Катушка и лента; Типоразмер: 1608 (0603); Технология монтажа: SMT; Изготовитель: АО "НПО "ЭРКОН"
footprint КИК-1608_О (Катушка индуктивности с керамическим сердечником  типоразмер 1005(0402))
pins: 1, 2

## КИК-1608-39 нГн ±5% Зл
designator L?, comment 39 нГн ±5%  (value not drawn)
Катушка индуктивности с керамическим сердечником и золотым покрытием контактных площадок; Номиналиная индуктивность: 39 нГн; Добротность, не менее: 35; Резонансная частота, не менее: 2.20 ГГц; Сопротивление обмотки постоянноми току, не более: 0.250 Ом; Допустимый ток обмотки: 600 мА; Диапазон рабочих температур: от -60 до +125 ℃; Упаковка: Катушка и лента; Типоразмер: 1608 (0603); Технология монтажа: SMT; Изготовитель: АО "НПО "ЭРКОН"
footprint КИК-1608_Зл (Катушка индуктивности с керамическим сердечником  типоразмер 1005(0402))
pins: 1, 2

## КИК-1608-39 нГн ±10% O
designator L?, comment 39 нГн ±10%  (value not drawn)
Катушка индуктивности с керамическим сердечником и  финишным покрытием контактных площадок оловом; Номиналиная индуктивность: 39 нГн; Добротность, не менее: 35; Резонансная частота, не менее: 2.20 ГГц; Сопротивление обмотки постоянноми току, не более: 0.250 Ом; Допустимый ток обмотки: 600 мА; Диапазон рабочих температур: от -60 до +125 ℃; Упаковка: Катушка и лента; Типоразмер: 1608 (0603); Технология монтажа: SMT; Изготовитель: АО "НПО "ЭРКОН"
footprint КИК-1608_О (Катушка индуктивности с керамическим сердечником  типоразмер 1005(0402))
pins: 1, 2

## КИК-1608-39 нГн ±10% Зл
designator L?, comment 39 нГн ±10%  (value not drawn)
Катушка индуктивности с керамическим сердечником и золотым покрытием контактных площадок; Номиналиная индуктивность: 39 нГн; Добротность, не менее: 35; Резонансная частота, не менее: 2.20 ГГц; Сопротивление обмотки постоянноми току, не более: 0.250 Ом; Допустимый ток обмотки: 600 мА; Диапазон рабочих температур: от -60 до +125 ℃; Упаковка: Катушка и лента; Типоразмер: 1608 (0603); Технология монтажа: SMT; Изготовитель: АО "НПО "ЭРКОН"
footprint КИК-1608_Зл (Катушка индуктивности с керамическим сердечником  типоразмер 1005(0402))
pins: 1, 2

## КИК-1608-39 нГн ±20% O
designator L?, comment 39 нГн ±20%  (value not drawn)
Катушка индуктивности с керамическим сердечником и  финишным покрытием контактных площадок оловом; Номиналиная индуктивность: 39 нГн; Добротность, не менее: 35; Резонансная частота, не менее: 2.20 ГГц; Сопротивление обмотки постоянноми току, не более: 0.250 Ом; Допустимый ток обмотки: 600 мА; Диапазон рабочих температур: от -60 до +125 ℃; Упаковка: Катушка и лента; Типоразмер: 1608 (0603); Технология монтажа: SMT; Изготовитель: АО "НПО "ЭРКОН"
footprint КИК-1608_О (Катушка индуктивности с керамическим сердечником  типоразмер 1005(0402))
pins: 1, 2

## КИК-1608-39 нГн ±20% Зл
designator L?, comment 39 нГн ±20%  (value not drawn)
Катушка индуктивности с керамическим сердечником и золотым покрытием контактных площадок; Номиналиная индуктивность: 39 нГн; Добротность, не менее: 35; Резонансная частота, не менее: 2.20 ГГц; Сопротивление обмотки постоянноми току, не более: 0.250 Ом; Допустимый ток обмотки: 600 мА; Диапазон рабочих температур: от -60 до +125 ℃; Упаковка: Катушка и лента; Типоразмер: 1608 (0603); Технология монтажа: SMT; Изготовитель: АО "НПО "ЭРКОН"
footprint КИК-1608_Зл (Катушка индуктивности с керамическим сердечником  типоразмер 1005(0402))
pins: 1, 2

## КИК-1608-43 нГн ±2% O
designator L?, comment 43 нГн ±5%  (value not drawn)
Катушка индуктивности с керамическим сердечником и  финишным покрытием контактных площадок оловом; Номиналиная индуктивность: 43 нГн; Допускаемое отклонение индуктивности: ±2%; Добротность, не менее: 35; Резонансная частота, не менее: 2.00 ГГц; Сопротивление обмотки постоянноми току, не более: 0.280 Ом; Допустимый ток обмотки: 600 мА; Диапазон рабочих температур: от -60 до +125 ℃; Упаковка: Катушка и лента; Типоразмер: 1608 (0603); Технология монтажа: SMT; Изготовитель: АО "НПО "ЭРКОН"
footprint КИК-1608_О (Катушка индуктивности с керамическим сердечником  типоразмер 1005(0402))
pins: 1, 2

## КИК-1608-43 нГн ±2% Зл
designator L?, comment 43 нГн ±2%  (value not drawn)
Катушка индуктивности с керамическим сердечником и золотым покрытием контактных площадок; Номиналиная индуктивность: 43 нГн; Добротность, не менее: 35; Резонансная частота, не менее: 2.00 ГГц; Сопротивление обмотки постоянноми току, не более: 0.280 Ом; Допустимый ток обмотки: 600 мА; Диапазон рабочих температур: от -60 до +125 ℃; Упаковка: Катушка и лента; Типоразмер: 1608 (0603); Технология монтажа: SMT; Изготовитель: АО "НПО "ЭРКОН"
footprint КИК-1608_Зл (Катушка индуктивности с керамическим сердечником  типоразмер 1005(0402))
pins: 1, 2

## КИК-1608-43 нГн ±5% O
designator L?, comment 43 нГн ±5%  (value not drawn)
Катушка индуктивности с керамическим сердечником и  финишным покрытием контактных площадок оловом; Номиналиная индуктивность: 43 нГн; Добротность, не менее: 35; Резонансная частота, не менее: 2.00 ГГц; Сопротивление обмотки постоянноми току, не более: 0.280 Ом; Допустимый ток обмотки: 600 мА; Диапазон рабочих температур: от -60 до +125 ℃; Упаковка: Катушка и лента; Типоразмер: 1608 (0603); Технология монтажа: SMT; Изготовитель: АО "НПО "ЭРКОН"
footprint КИК-1608_О (Катушка индуктивности с керамическим сердечником  типоразмер 1005(0402))
pins: 1, 2

## КИК-1608-43 нГн ±5% Зл
designator L?, comment 43 нГн ±5%  (value not drawn)
Катушка индуктивности с керамическим сердечником и золотым покрытием контактных площадок; Номиналиная индуктивность: 43 нГн; Добротность, не менее: 35; Резонансная частота, не менее: 2.00 ГГц; Сопротивление обмотки постоянноми току, не более: 0.280 Ом; Допустимый ток обмотки: 600 мА; Диапазон рабочих температур: от -60 до +125 ℃; Упаковка: Катушка и лента; Типоразмер: 1608 (0603); Технология монтажа: SMT; Изготовитель: АО "НПО "ЭРКОН"
footprint КИК-1608_Зл (Катушка индуктивности с керамическим сердечником  типоразмер 1005(0402))
pins: 1, 2

## КИК-1608-43 нГн ±10% O
designator L?, comment 43 нГн ±10%  (value not drawn)
Катушка индуктивности с керамическим сердечником и  финишным покрытием контактных площадок оловом; Номиналиная индуктивность: 43 нГн; Добротность, не менее: 35; Резонансная частота, не менее: 2.00 ГГц; Сопротивление обмотки постоянноми току, не более: 0.280 Ом; Допустимый ток обмотки: 600 мА; Диапазон рабочих температур: от -60 до +125 ℃; Упаковка: Катушка и лента; Типоразмер: 1608 (0603); Технология монтажа: SMT; Изготовитель: АО "НПО "ЭРКОН"
footprint КИК-1608_О (Катушка индуктивности с керамическим сердечником  типоразмер 1005(0402))
pins: 1, 2

## КИК-1608-43 нГн ±10% Зл
designator L?, comment 43 нГн ±10%  (value not drawn)
Катушка индуктивности с керамическим сердечником и золотым покрытием контактных площадок; Номиналиная индуктивность: 43 нГн; Добротность, не менее: 35; Резонансная частота, не менее: 2.00 ГГц; Сопротивление обмотки постоянноми току, не более: 0.280 Ом; Допустимый ток обмотки: 600 мА; Диапазон рабочих температур: от -60 до +125 ℃; Упаковка: Катушка и лента; Типоразмер: 1608 (0603); Технология монтажа: SMT; Изготовитель: АО "НПО "ЭРКОН"
footprint КИК-1608_Зл (Катушка индуктивности с керамическим сердечником  типоразмер 1005(0402))
pins: 1, 2

## КИК-1608-43 нГн ±20% O
designator L?, comment 43 нГн ±20%  (value not drawn)
Катушка индуктивности с керамическим сердечником и  финишным покрытием контактных площадок оловом; Номиналиная индуктивность: 43 нГн; Добротность, не менее: 35; Резонансная частота, не менее: 2.00 ГГц; Сопротивление обмотки постоянноми току, не более: 0.280 Ом; Допустимый ток обмотки: 600 мА; Диапазон рабочих температур: от -60 до +125 ℃; Упаковка: Катушка и лента; Типоразмер: 1608 (0603); Технология монтажа: SMT; Изготовитель: АО "НПО "ЭРКОН"
footprint КИК-1608_О (Катушка индуктивности с керамическим сердечником  типоразмер 1005(0402))
pins: 1, 2

## КИК-1608-43 нГн ±20% Зл
designator L?, comment 43 нГн ±20%  (value not drawn)
Катушка индуктивности с керамическим сердечником и золотым покрытием контактных площадок; Номиналиная индуктивность: 43 нГн; Добротность, не менее: 35; Резонансная частота, не менее: 2.00 ГГц; Сопротивление обмотки постоянноми току, не более: 0.280 Ом; Допустимый ток обмотки: 600 мА; Диапазон рабочих температур: от -60 до +125 ℃; Упаковка: Катушка и лента; Типоразмер: 1608 (0603); Технология монтажа: SMT; Изготовитель: АО "НПО "ЭРКОН"
footprint КИК-1608_Зл (Катушка индуктивности с керамическим сердечником  типоразмер 1005(0402))
pins: 1, 2

## КИК-1608-47 нГн ±2% O
designator L?, comment 47 нГн ±2%  (value not drawn)
Катушка индуктивности с керамическим сердечником и  финишным покрытием контактных площадок оловом; Номиналиная индуктивность: 47 нГн; Добротность, не менее: 35; Резонансная частота, не менее: 2.00 ГГц; Сопротивление обмотки постоянноми току, не более: 0.280 Ом; Допустимый ток обмотки: 600 мА; Диапазон рабочих температур: от -60 до +125 ℃; Упаковка: Катушка и лента; Типоразмер: 1608 (0603); Технология монтажа: SMT; Изготовитель: АО "НПО "ЭРКОН"
footprint КИК-1608_О (Катушка индуктивности с керамическим сердечником  типоразмер 1005(0402))
pins: 1, 2

## КИК-1608-47 нГн ±2% Зл
designator L?, comment 47 нГн ±2%  (value not drawn)
Катушка индуктивности с керамическим сердечником и золотым покрытием контактных площадок; Номиналиная индуктивность: 47 нГн; Добротность, не менее: 35; Резонансная частота, не менее: 2.00 ГГц; Сопротивление обмотки постоянноми току, не более: 0.280 Ом; Допустимый ток обмотки: 600 мА; Диапазон рабочих температур: от -60 до +125 ℃; Упаковка: Катушка и лента; Типоразмер: 1608 (0603); Технология монтажа: SMT; Изготовитель: АО "НПО "ЭРКОН"
footprint КИК-1608_Зл (Катушка индуктивности с керамическим сердечником  типоразмер 1005(0402))
pins: 1, 2

## КИК-1608-47 нГн ±5% O
designator L?, comment 47 нГн ±5%  (value not drawn)
Катушка индуктивности с керамическим сердечником и  финишным покрытием контактных площадок оловом; Номиналиная индуктивность: 47 нГн; Добротность, не менее: 35; Резонансная частота, не менее: 2.00 ГГц; Сопротивление обмотки постоянноми току, не более: 0.280 Ом; Допустимый ток обмотки: 600 мА; Диапазон рабочих температур: от -60 до +125 ℃; Упаковка: Катушка и лента; Типоразмер: 1608 (0603); Технология монтажа: SMT; Изготовитель: АО "НПО "ЭРКОН"
footprint КИК-1608_О (Катушка индуктивности с керамическим сердечником  типоразмер 1005(0402))
pins: 1, 2

## КИК-1608-47 нГн ±5% Зл
designator L?, comment 47 нГн ±5%  (value not drawn)
Катушка индуктивности с керамическим сердечником и золотым покрытием контактных площадок; Номиналиная индуктивность: 47 нГн; Добротность, не менее: 35; Резонансная частота, не менее: 2.00 ГГц; Сопротивление обмотки постоянноми току, не более: 0.280 Ом; Допустимый ток обмотки: 600 мА; Диапазон рабочих температур: от -60 до +125 ℃; Упаковка: Катушка и лента; Типоразмер: 1608 (0603); Технология монтажа: SMT; Изготовитель: АО "НПО "ЭРКОН"
footprint КИК-1608_Зл (Катушка индуктивности с керамическим сердечником  типоразмер 1005(0402))
pins: 1, 2

## КИК-1608-47 нГн ±10% O
designator L?, comment 47 нГн ±10%  (value not drawn)
Катушка индуктивности с керамическим сердечником и  финишным покрытием контактных площадок оловом; Номиналиная индуктивность: 47 нГн; Добротность, не менее: 35; Резонансная частота, не менее: 2.00 ГГц; Сопротивление обмотки постоянноми току, не более: 0.280 Ом; Допустимый ток обмотки: 600 мА; Диапазон рабочих температур: от -60 до +125 ℃; Упаковка: Катушка и лента; Типоразмер: 1608 (0603); Технология монтажа: SMT; Изготовитель: АО "НПО "ЭРКОН"
footprint КИК-1608_О (Катушка индуктивности с керамическим сердечником  типоразмер 1005(0402))
pins: 1, 2

## КИК-1608-47 нГн ±10% Зл
designator L?, comment 47 нГн ±10%  (value not drawn)
Катушка индуктивности с керамическим сердечником и золотым покрытием контактных площадок; Номиналиная индуктивность: 47 нГн; Добротность, не менее: 35; Резонансная частота, не менее: 2.00 ГГц; Сопротивление обмотки постоянноми току, не более: 0.280 Ом; Допустимый ток обмотки: 600 мА; Диапазон рабочих температур: от -60 до +125 ℃; Упаковка: Катушка и лента; Типоразмер: 1608 (0603); Технология монтажа: SMT; Изготовитель: АО "НПО "ЭРКОН"
footprint КИК-1608_Зл (Катушка индуктивности с керамическим сердечником  типоразмер 1005(0402))
pins: 1, 2

## КИК-1608-47 нГн ±20% O
designator L?, comment 47 нГн ±20%  (value not drawn)
Катушка индуктивности с керамическим сердечником и  финишным покрытием контактных площадок оловом; Номиналиная индуктивность: 47 нГн; Добротность, не менее: 35; Резонансная частота, не менее: 2.00 ГГц; Сопротивление обмотки постоянноми току, не более: 0.280 Ом; Допустимый ток обмотки: 600 мА; Диапазон рабочих температур: от -60 до +125 ℃; Упаковка: Катушка и лента; Типоразмер: 1608 (0603); Технология монтажа: SMT; Изготовитель: АО "НПО "ЭРКОН"
footprint КИК-1608_О (Катушка индуктивности с керамическим сердечником  типоразмер 1005(0402))
pins: 1, 2

## КИК-1608-47 нГн ±20% Зл
designator L?, comment 47 нГн ±20%  (value not drawn)
Катушка индуктивности с керамическим сердечником и золотым покрытием контактных площадок; Номиналиная индуктивность: 47 нГн; Добротность, не менее: 35; Резонансная частота, не менее: 2.00 ГГц; Сопротивление обмотки постоянноми току, не более: 0.280 Ом; Допустимый ток обмотки: 600 мА; Диапазон рабочих температур: от -60 до +125 ℃; Упаковка: Катушка и лента; Типоразмер: 1608 (0603); Технология монтажа: SMT; Изготовитель: АО "НПО "ЭРКОН"
footprint КИК-1608_Зл (Катушка индуктивности с керамическим сердечником  типоразмер 1005(0402))
pins: 1, 2


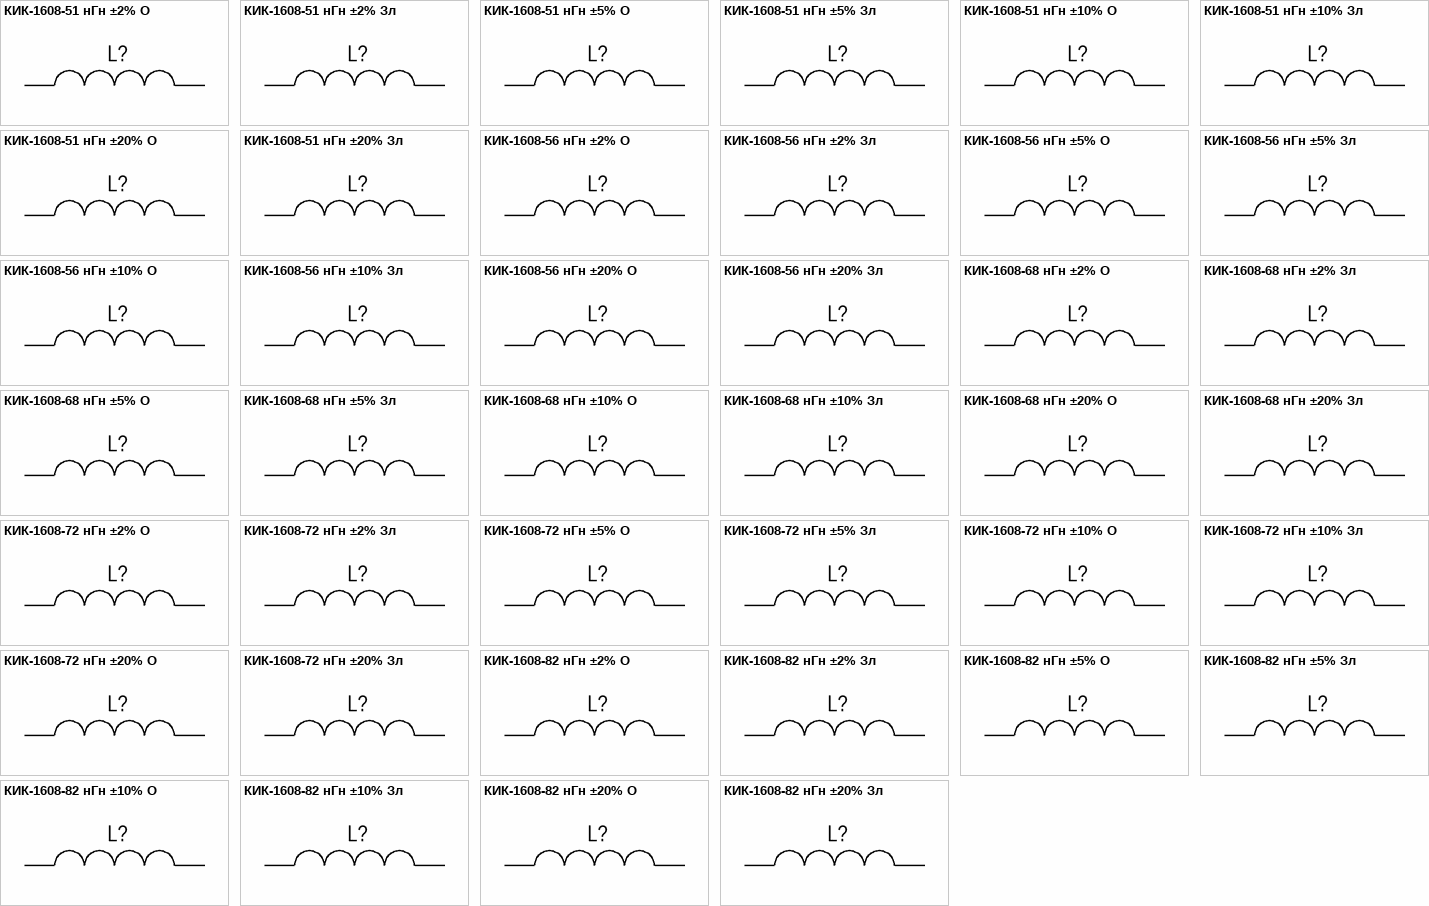
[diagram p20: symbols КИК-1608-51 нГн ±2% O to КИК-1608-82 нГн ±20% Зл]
## КИК-1608-51 нГн ±2% O
designator L?, comment 51 нГн ±2%  (value not drawn)
Катушка индуктивности с керамическим сердечником и  финишным покрытием контактных площадок оловом; Номиналиная индуктивность: 51 нГн; Добротность, не менее: 35; Резонансная частота, не менее: 1.90 ГГц; Сопротивление обмотки постоянноми току, не более: 0.280 Ом; Допустимый ток обмотки: 600 мА; Диапазон рабочих температур: от -60 до +125 ℃; Упаковка: Катушка и лента; Типоразмер: 1608 (0603); Технология монтажа: SMT; Изготовитель: АО "НПО "ЭРКОН"
footprint КИК-1608_О (Катушка индуктивности с керамическим сердечником  типоразмер 1005(0402))
pins: 1, 2

## КИК-1608-51 нГн ±2% Зл
designator L?, comment 51 нГн ±2%  (value not drawn)
Катушка индуктивности с керамическим сердечником и золотым покрытием контактных площадок; Номиналиная индуктивность: 51 нГн; Добротность, не менее: 35; Резонансная частота, не менее: 1.90 ГГц; Сопротивление обмотки постоянноми току, не более: 0.280 Ом; Допустимый ток обмотки: 600 мА; Диапазон рабочих температур: от -60 до +125 ℃; Упаковка: Катушка и лента; Типоразмер: 1608 (0603); Технология монтажа: SMT; Изготовитель: АО "НПО "ЭРКОН"
footprint КИК-1608_Зл (Катушка индуктивности с керамическим сердечником  типоразмер 1005(0402))
pins: 1, 2

## КИК-1608-51 нГн ±5% O
designator L?, comment 51 нГн ±5%  (value not drawn)
Катушка индуктивности с керамическим сердечником и  финишным покрытием контактных площадок оловом; Номиналиная индуктивность: 51 нГн; Добротность, не менее: 35; Резонансная частота, не менее: 1.90 ГГц; Сопротивление обмотки постоянноми току, не более: 0.280 Ом; Допустимый ток обмотки: 600 мА; Диапазон рабочих температур: от -60 до +125 ℃; Упаковка: Катушка и лента; Типоразмер: 1608 (0603); Технология монтажа: SMT; Изготовитель: АО "НПО "ЭРКОН"
footprint КИК-1608_О (Катушка индуктивности с керамическим сердечником  типоразмер 1005(0402))
pins: 1, 2

## КИК-1608-51 нГн ±5% Зл
designator L?, comment 51 нГн ±5%  (value not drawn)
Катушка индуктивности с керамическим сердечником и золотым покрытием контактных площадок; Номиналиная индуктивность: 51 нГн; Добротность, не менее: 35; Резонансная частота, не менее: 1.90 ГГц; Сопротивление обмотки постоянноми току, не более: 0.280 Ом; Допустимый ток обмотки: 600 мА; Диапазон рабочих температур: от -60 до +125 ℃; Упаковка: Катушка и лента; Типоразмер: 1608 (0603); Технология монтажа: SMT; Изготовитель: АО "НПО "ЭРКОН"
footprint КИК-1608_Зл (Катушка индуктивности с керамическим сердечником  типоразмер 1005(0402))
pins: 1, 2

## КИК-1608-51 нГн ±10% O
designator L?, comment 51 нГн ±10%  (value not drawn)
Катушка индуктивности с керамическим сердечником и  финишным покрытием контактных площадок оловом; Номиналиная индуктивность: 51 нГн; Добротность, не менее: 35; Резонансная частота, не менее: 1.90 ГГц; Сопротивление обмотки постоянноми току, не более: 0.280 Ом; Допустимый ток обмотки: 600 мА; Диапазон рабочих температур: от -60 до +125 ℃; Упаковка: Катушка и лента; Типоразмер: 1608 (0603); Технология монтажа: SMT; Изготовитель: АО "НПО "ЭРКОН"
footprint КИК-1608_О (Катушка индуктивности с керамическим сердечником  типоразмер 1005(0402))
pins: 1, 2

## КИК-1608-51 нГн ±10% Зл
designator L?, comment 51 нГн ±10%  (value not drawn)
Катушка индуктивности с керамическим сердечником и золотым покрытием контактных площадок; Номиналиная индуктивность: 51 нГн; Добротность, не менее: 35; Резонансная частота, не менее: 1.90 ГГц; Сопротивление обмотки постоянноми току, не более: 0.280 Ом; Допустимый ток обмотки: 600 мА; Диапазон рабочих температур: от -60 до +125 ℃; Упаковка: Катушка и лента; Типоразмер: 1608 (0603); Технология монтажа: SMT; Изготовитель: АО "НПО "ЭРКОН"
footprint КИК-1608_Зл (Катушка индуктивности с керамическим сердечником  типоразмер 1005(0402))
pins: 1, 2

## КИК-1608-51 нГн ±20% O
designator L?, comment 51 нГн ±20%  (value not drawn)
Катушка индуктивности с керамическим сердечником и  финишным покрытием контактных площадок оловом; Номиналиная индуктивность: 51 нГн; Допускаемое отклонение индуктивности: ±10%; Добротность, не менее: 35; Резонансная частота, не менее: 1.90 ГГц; Сопротивление обмотки постоянноми току, не более: 0.280 Ом; Допустимый ток обмотки: 600 мА; Диапазон рабочих температур: от -60 до +125 ℃; Упаковка: Катушка и лента; Типоразмер: 1608 (0603); Технология монтажа: SMT; Изготовитель: АО "НПО "ЭРКОН"
footprint КИК-1608_О (Катушка индуктивности с керамическим сердечником  типоразмер 1005(0402))
pins: 1, 2

## КИК-1608-51 нГн ±20% Зл
designator L?, comment 51 нГн ±20%  (value not drawn)
Катушка индуктивности с керамическим сердечником и золотым покрытием контактных площадок; Номиналиная индуктивность: 51 нГн; Добротность, не менее: 35; Резонансная частота, не менее: 1.90 ГГц; Сопротивление обмотки постоянноми току, не более: 0.280 Ом; Допустимый ток обмотки: 600 мА; Диапазон рабочих температур: от -60 до +125 ℃; Упаковка: Катушка и лента; Типоразмер: 1608 (0603); Технология монтажа: SMT; Изготовитель: АО "НПО "ЭРКОН"
footprint КИК-1608_Зл (Катушка индуктивности с керамическим сердечником  типоразмер 1005(0402))
pins: 1, 2

## КИК-1608-56 нГн ±2% O
designator L?, comment 56 нГн ±2%  (value not drawn)
Катушка индуктивности с керамическим сердечником и  финишным покрытием контактных площадок оловом; Номиналиная индуктивность: 56 нГн; Добротность, не менее: 35; Резонансная частота, не менее: 1.90 ГГц; Сопротивление обмотки постоянноми току, не более: 0.310 Ом; Допустимый ток обмотки: 600 мА; Диапазон рабочих температур: от -60 до +125 ℃; Упаковка: Катушка и лента; Типоразмер: 1608 (0603); Технология монтажа: SMT; Изготовитель: АО "НПО "ЭРКОН"
footprint КИК-1608_О (Катушка индуктивности с керамическим сердечником  типоразмер 1005(0402))
pins: 1, 2

## КИК-1608-56 нГн ±2% Зл
designator L?, comment 56 нГн ±2%  (value not drawn)
Катушка индуктивности с керамическим сердечником и золотым покрытием контактных площадок; Номиналиная индуктивность: 56 нГн; Добротность, не менее: 35; Резонансная частота, не менее: 1.90 ГГц; Сопротивление обмотки постоянноми току, не более: 0.310 Ом; Допустимый ток обмотки: 600 мА; Диапазон рабочих температур: от -60 до +125 ℃; Упаковка: Катушка и лента; Типоразмер: 1608 (0603); Технология монтажа: SMT; Изготовитель: АО "НПО "ЭРКОН"
footprint КИК-1608_Зл (Катушка индуктивности с керамическим сердечником  типоразмер 1005(0402))
pins: 1, 2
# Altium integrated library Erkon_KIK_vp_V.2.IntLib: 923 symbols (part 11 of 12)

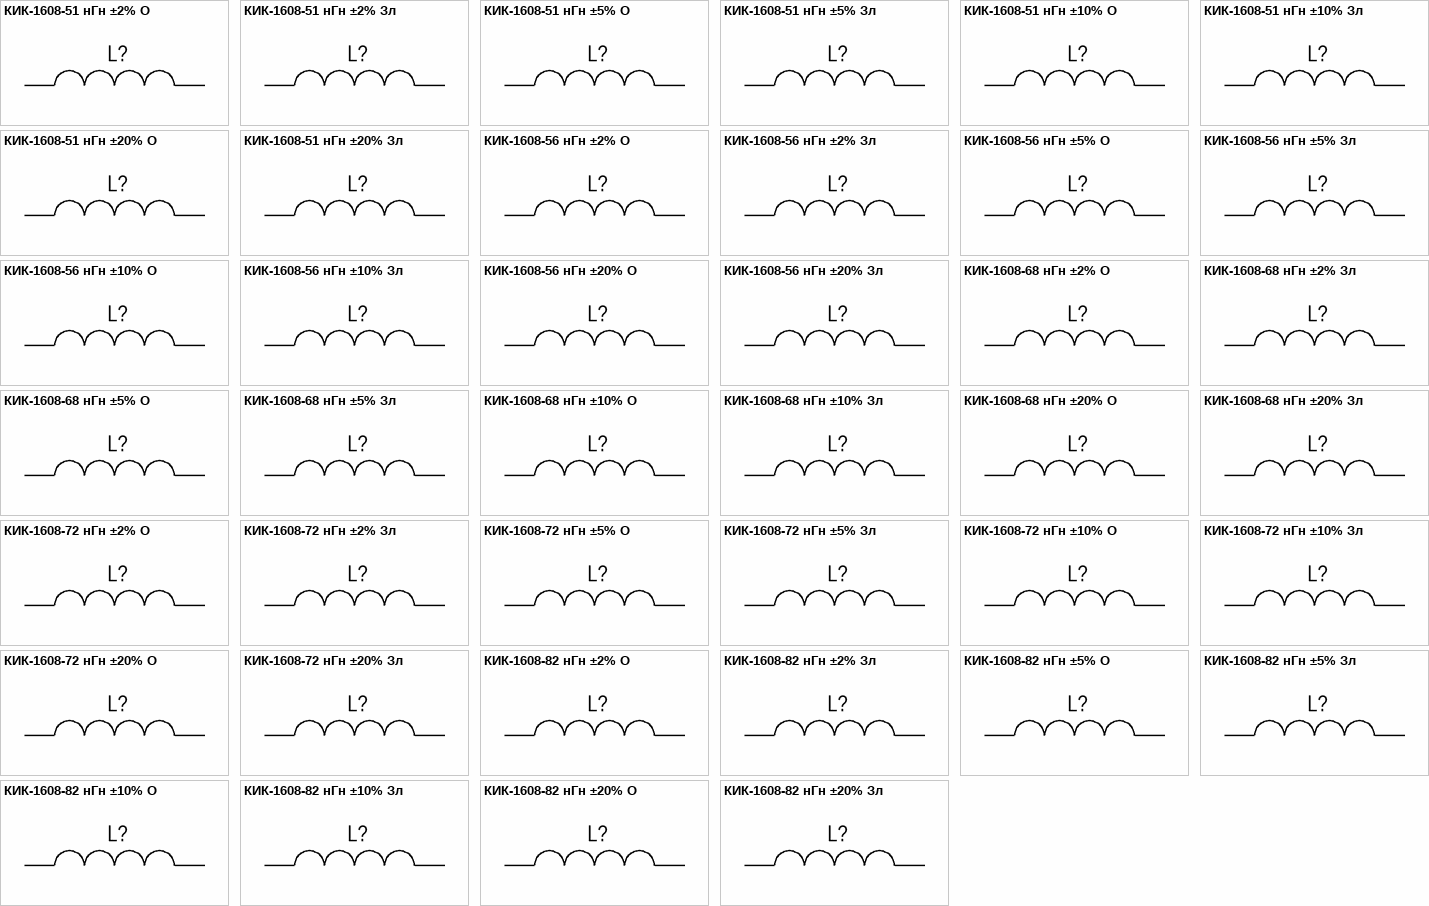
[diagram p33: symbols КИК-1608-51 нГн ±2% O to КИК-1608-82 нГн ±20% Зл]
## КИК-1608-56 нГн ±5% O
designator L?, comment 56 нГн ±5%  (value not drawn)
Катушка индуктивности с керамическим сердечником и  финишным покрытием контактных площадок оловом; Номиналиная индуктивность: 56 нГн; Добротность, не менее: 35; Резонансная частота, не менее: 1.90 ГГц; Сопротивление обмотки постоянноми току, не более: 0.310 Ом; Допустимый ток обмотки: 600 мА; Диапазон рабочих температур: от -60 до +125 ℃; Упаковка: Катушка и лента; Типоразмер: 1608 (0603); Технология монтажа: SMT; Изготовитель: АО "НПО "ЭРКОН"
footprint КИК-1608_О (Катушка индуктивности с керамическим сердечником  типоразмер 1005(0402))
pins: 1, 2

## КИК-1608-56 нГн ±5% Зл
designator L?, comment 56 нГн ±5%  (value not drawn)
Катушка индуктивности с керамическим сердечником и золотым покрытием контактных площадок; Номиналиная индуктивность: 56 нГн; Добротность, не менее: 35; Резонансная частота, не менее: 1.90 ГГц; Сопротивление обмотки постоянноми току, не более: 0.310 Ом; Допустимый ток обмотки: 600 мА; Диапазон рабочих температур: от -60 до +125 ℃; Упаковка: Катушка и лента; Типоразмер: 1608 (0603); Технология монтажа: SMT; Изготовитель: АО "НПО "ЭРКОН"
footprint КИК-1608_Зл (Катушка индуктивности с керамическим сердечником  типоразмер 1005(0402))
pins: 1, 2

## КИК-1608-56 нГн ±10% O
designator L?, comment 56 нГн ±10%  (value not drawn)
Катушка индуктивности с керамическим сердечником и  финишным покрытием контактных площадок оловом; Номиналиная индуктивность: 56 нГн; Добротность, не менее: 35; Резонансная частота, не менее: 1.90 ГГц; Сопротивление обмотки постоянноми току, не более: 0.310 Ом; Допустимый ток обмотки: 600 мА; Диапазон рабочих температур: от -60 до +125 ℃; Упаковка: Катушка и лента; Типоразмер: 1608 (0603); Технология монтажа: SMT; Изготовитель: АО "НПО "ЭРКОН"
footprint КИК-1608_О (Катушка индуктивности с керамическим сердечником  типоразмер 1005(0402))
pins: 1, 2

## КИК-1608-56 нГн ±10% Зл
designator L?, comment 56 нГн ±10%  (value not drawn)
Катушка индуктивности с керамическим сердечником и золотым покрытием контактных площадок; Номиналиная индуктивность: 56 нГн; Добротность, не менее: 35; Резонансная частота, не менее: 1.90 ГГц; Сопротивление обмотки постоянноми току, не более: 0.310 Ом; Допустимый ток обмотки: 600 мА; Диапазон рабочих температур: от -60 до +125 ℃; Упаковка: Катушка и лента; Типоразмер: 1608 (0603); Технология монтажа: SMT; Изготовитель: АО "НПО "ЭРКОН"
footprint КИК-1608_Зл (Катушка индуктивности с керамическим сердечником  типоразмер 1005(0402))
pins: 1, 2

## КИК-1608-56 нГн ±20% O
designator L?, comment 56 нГн ±20%  (value not drawn)
Катушка индуктивности с керамическим сердечником и  финишным покрытием контактных площадок оловом; Номиналиная индуктивность: 56 нГн; Добротность, не менее: 35; Резонансная частота, не менее: 1.90 ГГц; Сопротивление обмотки постоянноми току, не более: 0.310 Ом; Допустимый ток обмотки: 600 мА; Диапазон рабочих температур: от -60 до +125 ℃; Упаковка: Катушка и лента; Типоразмер: 1608 (0603); Технология монтажа: SMT; Изготовитель: АО "НПО "ЭРКОН"
footprint КИК-1608_О (Катушка индуктивности с керамическим сердечником  типоразмер 1005(0402))
pins: 1, 2

## КИК-1608-56 нГн ±20% Зл
designator L?, comment 56 нГн ±20%  (value not drawn)
Катушка индуктивности с керамическим сердечником и золотым покрытием контактных площадок; Номиналиная индуктивность: 56 нГн; Добротность, не менее: 35; Резонансная частота, не менее: 1.90 ГГц; Сопротивление обмотки постоянноми току, не более: 0.310 Ом; Допустимый ток обмотки: 600 мА; Диапазон рабочих температур: от -60 до +125 ℃; Упаковка: Катушка и лента; Типоразмер: 1608 (0603); Технология монтажа: SMT; Изготовитель: АО "НПО "ЭРКОН"
footprint КИК-1608_Зл (Катушка индуктивности с керамическим сердечником  типоразмер 1005(0402))
pins: 1, 2

## КИК-1608-68 нГн ±2% O
designator L?, comment 68 нГн ±2%  (value not drawn)
Катушка индуктивности с керамическим сердечником и  финишным покрытием контактных площадок оловом; Номиналиная индуктивность: 68 нГн; Добротность, не менее: 35; Резонансная частота, не менее: 1.70 ГГц; Сопротивление обмотки постоянноми току, не более: 0.340 Ом; Допустимый ток обмотки: 600 мА; Диапазон рабочих температур: от -60 до +125 ℃; Упаковка: Катушка и лента; Типоразмер: 1608 (0603); Технология монтажа: SMT; Изготовитель: АО "НПО "ЭРКОН"
footprint КИК-1608_О (Катушка индуктивности с керамическим сердечником  типоразмер 1005(0402))
pins: 1, 2

## КИК-1608-68 нГн ±2% Зл
designator L?, comment 68 нГн ±2%  (value not drawn)
Катушка индуктивности с керамическим сердечником и золотым покрытием контактных площадок; Номиналиная индуктивность: 68 нГн; Добротность, не менее: 35; Резонансная частота, не менее: 1.70 ГГц; Сопротивление обмотки постоянноми току, не более: 0.340 Ом; Допустимый ток обмотки: 600 мА; Диапазон рабочих температур: от -60 до +125 ℃; Упаковка: Катушка и лента; Типоразмер: 1608 (0603); Технология монтажа: SMT; Изготовитель: АО "НПО "ЭРКОН"
footprint КИК-1608_Зл (Катушка индуктивности с керамическим сердечником  типоразмер 1005(0402))
pins: 1, 2

## КИК-1608-68 нГн ±5% O
designator L?, comment 68 нГн ±5%  (value not drawn)
Катушка индуктивности с керамическим сердечником и  финишным покрытием контактных площадок оловом; Номиналиная индуктивность: 68 нГн; Добротность, не менее: 35; Резонансная частота, не менее: 1.70 ГГц; Сопротивление обмотки постоянноми току, не более: 0.340 Ом; Допустимый ток обмотки: 600 мА; Диапазон рабочих температур: от -60 до +125 ℃; Упаковка: Катушка и лента; Типоразмер: 1608 (0603); Технология монтажа: SMT; Изготовитель: АО "НПО "ЭРКОН"
footprint КИК-1608_О (Катушка индуктивности с керамическим сердечником  типоразмер 1005(0402))
pins: 1, 2

## КИК-1608-68 нГн ±5% Зл
designator L?, comment 68 нГн ±5%  (value not drawn)
Катушка индуктивности с керамическим сердечником и золотым покрытием контактных площадок; Номиналиная индуктивность: 68 нГн; Добротность, не менее: 35; Резонансная частота, не менее: 1.70 ГГц; Сопротивление обмотки постоянноми току, не более: 0.340 Ом; Допустимый ток обмотки: 600 мА; Диапазон рабочих температур: от -60 до +125 ℃; Упаковка: Катушка и лента; Типоразмер: 1608 (0603); Технология монтажа: SMT; Изготовитель: АО "НПО "ЭРКОН"
footprint КИК-1608_Зл (Катушка индуктивности с керамическим сердечником  типоразмер 1005(0402))
pins: 1, 2

## КИК-1608-68 нГн ±10% O
designator L?, comment 68 нГн ±10%  (value not drawn)
Катушка индуктивности с керамическим сердечником и  финишным покрытием контактных площадок оловом; Номиналиная индуктивность: 68 нГн; Добротность, не менее: 35; Резонансная частота, не менее: 1.70 ГГц; Сопротивление обмотки постоянноми току, не более: 0.340 Ом; Допустимый ток обмотки: 600 мА; Диапазон рабочих температур: от -60 до +125 ℃; Упаковка: Катушка и лента; Типоразмер: 1608 (0603); Технология монтажа: SMT; Изготовитель: АО "НПО "ЭРКОН"
footprint КИК-1608_О (Катушка индуктивности с керамическим сердечником  типоразмер 1005(0402))
pins: 1, 2

## КИК-1608-68 нГн ±10% Зл
designator L?, comment 68 нГн ±10%  (value not drawn)
Катушка индуктивности с керамическим сердечником и золотым покрытием контактных площадок; Номиналиная индуктивность: 68 нГн; Добротность, не менее: 35; Резонансная частота, не менее: 1.70 ГГц; Сопротивление обмотки постоянноми току, не более: 0.340 Ом; Допустимый ток обмотки: 600 мА; Диапазон рабочих температур: от -60 до +125 ℃; Упаковка: Катушка и лента; Типоразмер: 1608 (0603); Технология монтажа: SMT; Изготовитель: АО "НПО "ЭРКОН"
footprint КИК-1608_Зл (Катушка индуктивности с керамическим сердечником  типоразмер 1005(0402))
pins: 1, 2

## КИК-1608-68 нГн ±20% O
designator L?, comment 68 нГн ±20%  (value not drawn)
Катушка индуктивности с керамическим сердечником и  финишным покрытием контактных площадок оловом; Номиналиная индуктивность: 68 нГн; Добротность, не менее: 35; Резонансная частота, не менее: 1.70 ГГц; Сопротивление обмотки постоянноми току, не более: 0.340 Ом; Допустимый ток обмотки: 600 мА; Диапазон рабочих температур: от -60 до +125 ℃; Упаковка: Катушка и лента; Типоразмер: 1608 (0603); Технология монтажа: SMT; Изготовитель: АО "НПО "ЭРКОН"
footprint КИК-1608_О (Катушка индуктивности с керамическим сердечником  типоразмер 1005(0402))
pins: 1, 2

## КИК-1608-68 нГн ±20% Зл
designator L?, comment 68 нГн ±20%  (value not drawn)
Катушка индуктивности с керамическим сердечником и золотым покрытием контактных площадок; Номиналиная индуктивность: 68 нГн; Добротность, не менее: 35; Резонансная частота, не менее: 1.70 ГГц; Сопротивление обмотки постоянноми току, не более: 0.340 Ом; Допустимый ток обмотки: 600 мА; Диапазон рабочих температур: от -60 до +125 ℃; Упаковка: Катушка и лента; Типоразмер: 1608 (0603); Технология монтажа: SMT; Изготовитель: АО "НПО "ЭРКОН"
footprint КИК-1608_Зл (Катушка индуктивности с керамическим сердечником  типоразмер 1005(0402))
pins: 1, 2

## КИК-1608-72 нГн ±2% O
designator L?, comment 72 нГн ±2%  (value not drawn)
Катушка индуктивности с керамическим сердечником и  финишным покрытием контактных площадок оловом; Номиналиная индуктивность: 72 нГн; Добротность, не менее: 34; Резонансная частота, не менее: 1.70 ГГц; Сопротивление обмотки постоянноми току, не более: 0.490 Ом; Допустимый ток обмотки: 400 мА; Диапазон рабочих температур: от -60 до +125 ℃; Упаковка: Катушка и лента; Типоразмер: 1608 (0603); Технология монтажа: SMT; Изготовитель: АО "НПО "ЭРКОН"
footprint КИК-1608_О (Катушка индуктивности с керамическим сердечником  типоразмер 1005(0402))
pins: 1, 2

## КИК-1608-72 нГн ±2% Зл
designator L?, comment 72 нГн ±2%  (value not drawn)
Катушка индуктивности с керамическим сердечником и золотым покрытием контактных площадок; Номиналиная индуктивность: 72 нГн; Добротность, не менее: 34; Резонансная частота, не менее: 1.70 ГГц; Сопротивление обмотки постоянноми току, не более: 0.490 Ом; Допустимый ток обмотки: 400 мА; Диапазон рабочих температур: от -60 до +125 ℃; Упаковка: Катушка и лента; Типоразмер: 1608 (0603); Технология монтажа: SMT; Изготовитель: АО "НПО "ЭРКОН"
footprint КИК-1608_Зл (Катушка индуктивности с керамическим сердечником  типоразмер 1005(0402))
pins: 1, 2

## КИК-1608-72 нГн ±5% O
designator L?, comment 72 нГн ±5%  (value not drawn)
Катушка индуктивности с керамическим сердечником и  финишным покрытием контактных площадок оловом; Номиналиная индуктивность: 72 нГн; Добротность, не менее: 34; Резонансная частота, не менее: 1.70 ГГц; Сопротивление обмотки постоянноми току, не более: 0.490 Ом; Допустимый ток обмотки: 400 мА; Диапазон рабочих температур: от -60 до +125 ℃; Упаковка: Катушка и лента; Типоразмер: 1608 (0603); Технология монтажа: SMT; Изготовитель: АО "НПО "ЭРКОН"
footprint КИК-1608_О (Катушка индуктивности с керамическим сердечником  типоразмер 1005(0402))
pins: 1, 2

## КИК-1608-72 нГн ±5% Зл
designator L?, comment 72 нГн ±5%  (value not drawn)
Катушка индуктивности с керамическим сердечником и золотым покрытием контактных площадок; Номиналиная индуктивность: 72 нГн; Добротность, не менее: 34; Резонансная частота, не менее: 1.70 ГГц; Сопротивление обмотки постоянноми току, не более: 0.490 Ом; Допустимый ток обмотки: 400 мА; Диапазон рабочих температур: от -60 до +125 ℃; Упаковка: Катушка и лента; Типоразмер: 1608 (0603); Технология монтажа: SMT; Изготовитель: АО "НПО "ЭРКОН"
footprint КИК-1608_Зл (Катушка индуктивности с керамическим сердечником  типоразмер 1005(0402))
pins: 1, 2

## КИК-1608-72 нГн ±10% O
designator L?, comment 72 нГн ±10%  (value not drawn)
Катушка индуктивности с керамическим сердечником и  финишным покрытием контактных площадок оловом; Номиналиная индуктивность: 72 нГн; Добротность, не менее: 34; Резонансная частота, не менее: 1.70 ГГц; Сопротивление обмотки постоянноми току, не более: 0.490 Ом; Допустимый ток обмотки: 400 мА; Диапазон рабочих температур: от -60 до +125 ℃; Упаковка: Катушка и лента; Типоразмер: 1608 (0603); Технология монтажа: SMT; Изготовитель: АО "НПО "ЭРКОН"
footprint КИК-1608_О (Катушка индуктивности с керамическим сердечником  типоразмер 1005(0402))
pins: 1, 2

## КИК-1608-72 нГн ±10% Зл
designator L?, comment 72 нГн ±10%  (value not drawn)
Катушка индуктивности с керамическим сердечником и золотым покрытием контактных площадок; Номиналиная индуктивность: 72 нГн; Добротность, не менее: 34; Резонансная частота, не менее: 1.70 ГГц; Сопротивление обмотки постоянноми току, не более: 0.490 Ом; Допустимый ток обмотки: 400 мА; Диапазон рабочих температур: от -60 до +125 ℃; Упаковка: Катушка и лента; Типоразмер: 1608 (0603); Технология монтажа: SMT; Изготовитель: АО "НПО "ЭРКОН"
footprint КИК-1608_Зл (Катушка индуктивности с керамическим сердечником  типоразмер 1005(0402))
pins: 1, 2

## КИК-1608-72 нГн ±20% O
designator L?, comment 72 нГн ±20%  (value not drawn)
Катушка индуктивности с керамическим сердечником и  финишным покрытием контактных площадок оловом; Номиналиная индуктивность: 72 нГн; Добротность, не менее: 34; Резонансная частота, не менее: 1.70 ГГц; Сопротивление обмотки постоянноми току, не более: 0.490 Ом; Допустимый ток обмотки: 400 мА; Диапазон рабочих температур: от -60 до +125 ℃; Упаковка: Катушка и лента; Типоразмер: 1608 (0603); Технология монтажа: SMT; Изготовитель: АО "НПО "ЭРКОН"
footprint КИК-1608_О (Катушка индуктивности с керамическим сердечником  типоразмер 1005(0402))
pins: 1, 2

## КИК-1608-72 нГн ±20% Зл
designator L?, comment 72 нГн ±20%  (value not drawn)
Катушка индуктивности с керамическим сердечником и золотым покрытием контактных площадок; Номиналиная индуктивность: 72 нГн; Добротность, не менее: 34; Резонансная частота, не менее: 1.70 ГГц; Сопротивление обмотки постоянноми току, не более: 0.490 Ом; Допустимый ток обмотки: 400 мА; Диапазон рабочих температур: от -60 до +125 ℃; Упаковка: Катушка и лента; Типоразмер: 1608 (0603); Технология монтажа: SMT; Изготовитель: АО "НПО "ЭРКОН"
footprint КИК-1608_Зл (Катушка индуктивности с керамическим сердечником  типоразмер 1005(0402))
pins: 1, 2

## КИК-1608-82 нГн ±2% O
designator L?, comment 82 нГн ±2%  (value not drawn)
Катушка индуктивности с керамическим сердечником и  финишным покрытием контактных площадок оловом; Номиналиная индуктивность: 82 нГн; Добротность, не менее: 34; Резонансная частота, не менее: 1.70 ГГц; Сопротивление обмотки постоянноми току, не более: 0.540 Ом; Допустимый ток обмотки: 400 мА; Диапазон рабочих температур: от -60 до +125 ℃; Упаковка: Катушка и лента; Типоразмер: 1608 (0603); Технология монтажа: SMT; Изготовитель: АО "НПО "ЭРКОН"
footprint КИК-1608_О (Катушка индуктивности с керамическим сердечником  типоразмер 1005(0402))
pins: 1, 2

## КИК-1608-82 нГн ±2% Зл
designator L?, comment 82 нГн ±2%  (value not drawn)
Катушка индуктивности с керамическим сердечником и золотым покрытием контактных площадок; Номиналиная индуктивность: 82 нГн; Добротность, не менее: 34; Резонансная частота, не менее: 1.70 ГГц; Сопротивление обмотки постоянноми току, не более: 0.540 Ом; Допустимый ток обмотки: 400 мА; Диапазон рабочих температур: от -60 до +125 ℃; Упаковка: Катушка и лента; Типоразмер: 1608 (0603); Технология монтажа: SMT; Изготовитель: АО "НПО "ЭРКОН"
footprint КИК-1608_Зл (Катушка индуктивности с керамическим сердечником  типоразмер 1005(0402))
pins: 1, 2

## КИК-1608-82 нГн ±5% O
designator L?, comment 82 нГн ±5%  (value not drawn)
Катушка индуктивности с керамическим сердечником и  финишным покрытием контактных площадок оловом; Номиналиная индуктивность: 82 нГн; Добротность, не менее: 34; Резонансная частота, не менее: 1.70 ГГц; Сопротивление обмотки постоянноми току, не более: 0.540 Ом; Допустимый ток обмотки: 400 мА; Диапазон рабочих температур: от -60 до +125 ℃; Упаковка: Катушка и лента; Типоразмер: 1608 (0603); Технология монтажа: SMT; Изготовитель: АО "НПО "ЭРКОН"
footprint КИК-1608_О (Катушка индуктивности с керамическим сердечником  типоразмер 1005(0402))
pins: 1, 2

## КИК-1608-82 нГн ±5% Зл
designator L?, comment 82 нГн ±5%  (value not drawn)
Катушка индуктивности с керамическим сердечником и золотым покрытием контактных площадок; Номиналиная индуктивность: 82 нГн; Добротность, не менее: 34; Резонансная частота, не менее: 1.70 ГГц; Сопротивление обмотки постоянноми току, не более: 0.540 Ом; Допустимый ток обмотки: 400 мА; Диапазон рабочих температур: от -60 до +125 ℃; Упаковка: Катушка и лента; Типоразмер: 1608 (0603); Технология монтажа: SMT; Изготовитель: АО "НПО "ЭРКОН"
footprint КИК-1608_Зл (Катушка индуктивности с керамическим сердечником  типоразмер 1005(0402))
pins: 1, 2

## КИК-1608-82 нГн ±10% O
designator L?, comment 82 нГн ±10%  (value not drawn)
Катушка индуктивности с керамическим сердечником и  финишным покрытием контактных площадок оловом; Номиналиная индуктивность: 82 нГн; Добротность, не менее: 34; Резонансная частота, не менее: 1.70 ГГц; Сопротивление обмотки постоянноми току, не более: 0.540 Ом; Допустимый ток обмотки: 400 мА; Диапазон рабочих температур: от -60 до +125 ℃; Упаковка: Катушка и лента; Типоразмер: 1608 (0603); Технология монтажа: SMT; Изготовитель: АО "НПО "ЭРКОН"
footprint КИК-1608_О (Катушка индуктивности с керамическим сердечником  типоразмер 1005(0402))
pins: 1, 2

## КИК-1608-82 нГн ±10% Зл
designator L?, comment 82 нГн ±10%  (value not drawn)
Катушка индуктивности с керамическим сердечником и золотым покрытием контактных площадок; Номиналиная индуктивность: 82 нГн; Добротность, не менее: 34; Резонансная частота, не менее: 1.70 ГГц; Сопротивление обмотки постоянноми току, не более: 0.540 Ом; Допустимый ток обмотки: 400 мА; Диапазон рабочих температур: от -60 до +125 ℃; Упаковка: Катушка и лента; Типоразмер: 1608 (0603); Технология монтажа: SMT; Изготовитель: АО "НПО "ЭРКОН"
footprint КИК-1608_Зл (Катушка индуктивности с керамическим сердечником  типоразмер 1005(0402))
pins: 1, 2

## КИК-1608-82 нГн ±20% O
designator L?, comment 82 нГн ±20%  (value not drawn)
Катушка индуктивности с керамическим сердечником и  финишным покрытием контактных площадок оловом; Номиналиная индуктивность: 82 нГн; Добротность, не менее: 34; Резонансная частота, не менее: 1.70 ГГц; Сопротивление обмотки постоянноми току, не более: 0.540 Ом; Допустимый ток обмотки: 400 мА; Диапазон рабочих температур: от -60 до +125 ℃; Упаковка: Катушка и лента; Типоразмер: 1608 (0603); Технология монтажа: SMT; Изготовитель: АО "НПО "ЭРКОН"
footprint КИК-1608_О (Катушка индуктивности с керамическим сердечником  типоразмер 1005(0402))
pins: 1, 2

## КИК-1608-82 нГн ±20% Зл
designator L?, comment 82 нГн ±20%  (value not drawn)
Катушка индуктивности с керамическим сердечником и золотым покрытием контактных площадок; Номиналиная индуктивность: 82 нГн; Добротность, не менее: 34; Резонансная частота, не менее: 1.70 ГГц; Сопротивление обмотки постоянноми току, не более: 0.540 Ом; Допустимый ток обмотки: 400 мА; Диапазон рабочих температур: от -60 до +125 ℃; Упаковка: Катушка и лента; Типоразмер: 1608 (0603); Технология монтажа: SMT; Изготовитель: АО "НПО "ЭРКОН"
footprint КИК-1608_Зл (Катушка индуктивности с керамическим сердечником  типоразмер 1005(0402))
pins: 1, 2


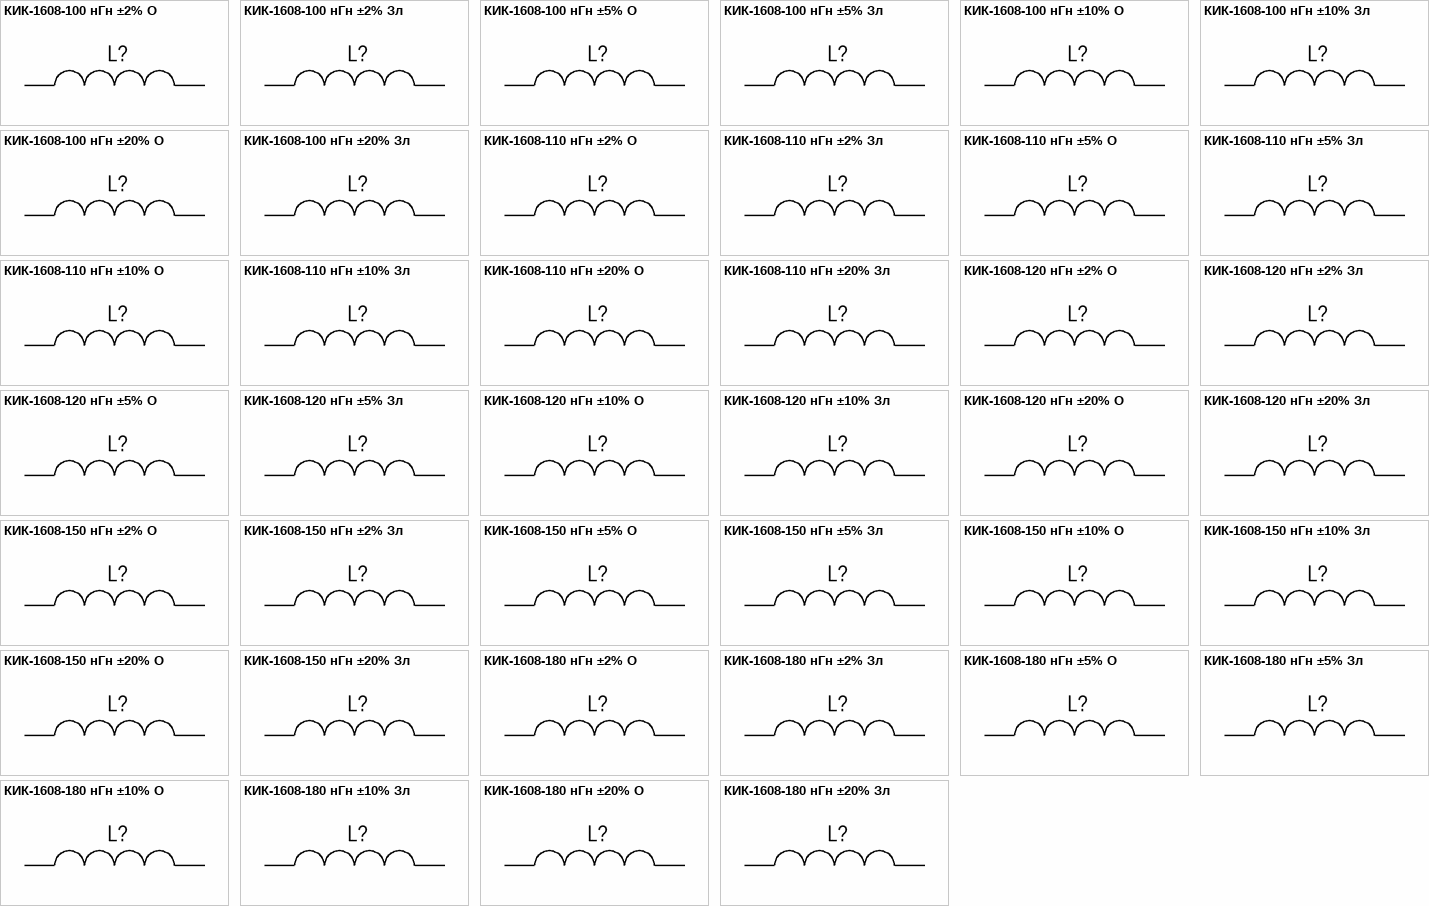
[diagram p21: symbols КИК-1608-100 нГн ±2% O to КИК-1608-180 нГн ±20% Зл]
## КИК-1608-100 нГн ±2% O
designator L?, comment 100 нГн ±2%  (value not drawn)
Катушка индуктивности с керамическим сердечником и  финишным покрытием контактных площадок оловом; Номиналиная индуктивность: 100 нГн; Добротность, не менее: 34; Резонансная частота, не менее: 1.40 ГГц; Сопротивление обмотки постоянноми току, не более: 0.580 Ом; Допустимый ток обмотки: 400 мА; Диапазон рабочих температур: от -60 до +125 ℃; Упаковка: Катушка и лента; Типоразмер: 1608 (0603); Технология монтажа: SMT; Изготовитель: АО "НПО "ЭРКОН"
footprint КИК-1608_О (Катушка индуктивности с керамическим сердечником  типоразмер 1005(0402))
pins: 1, 2

## КИК-1608-100 нГн ±2% Зл
designator L?, comment 100 нГн ±2%  (value not drawn)
Катушка индуктивности с керамическим сердечником и золотым покрытием контактных площадок; Номиналиная индуктивность: 100 нГн; Допускаемое отклонение индуктивности: ±5%; Добротность, не менее: 34; Резонансная частота, не менее: 1.40 ГГц; Сопротивление обмотки постоянноми току, не более: 0.580 Ом; Допустимый ток обмотки: 400 мА; Диапазон рабочих температур: от -60 до +125 ℃; Упаковка: Катушка и лента; Типоразмер: 1608 (0603); Технология монтажа: SMT; Изготовитель: АО "НПО "ЭРКОН"
footprint КИК-1608_Зл (Катушка индуктивности с керамическим сердечником  типоразмер 1005(0402))
pins: 1, 2

## КИК-1608-100 нГн ±5% O
designator L?, comment 100 нГн ±5%  (value not drawn)
Катушка индуктивности с керамическим сердечником и  финишным покрытием контактных площадок оловом; Номиналиная индуктивность: 100 нГн; Добротность, не менее: 34; Резонансная частота, не менее: 1.40 ГГц; Сопротивление обмотки постоянноми току, не более: 0.580 Ом; Допустимый ток обмотки: 400 мА; Диапазон рабочих температур: от -60 до +125 ℃; Упаковка: Катушка и лента; Типоразмер: 1608 (0603); Технология монтажа: SMT; Изготовитель: АО "НПО "ЭРКОН"
footprint КИК-1608_О (Катушка индуктивности с керамическим сердечником  типоразмер 1005(0402))
pins: 1, 2

## КИК-1608-100 нГн ±5% Зл
designator L?, comment 100 нГн ±5%  (value not drawn)
Катушка индуктивности с керамическим сердечником и золотым покрытием контактных площадок; Номиналиная индуктивность: 100 нГн; Добротность, не менее: 34; Резонансная частота, не менее: 1.40 ГГц; Сопротивление обмотки постоянноми току, не более: 0.580 Ом; Допустимый ток обмотки: 400 мА; Диапазон рабочих температур: от -60 до +125 ℃; Упаковка: Катушка и лента; Типоразмер: 1608 (0603); Технология монтажа: SMT; Изготовитель: АО "НПО "ЭРКОН"
footprint КИК-1608_Зл (Катушка индуктивности с керамическим сердечником  типоразмер 1005(0402))
pins: 1, 2

## КИК-1608-100 нГн ±10% O
designator L?, comment 100 нГн ±10%  (value not drawn)
Катушка индуктивности с керамическим сердечником и  финишным покрытием контактных площадок оловом; Номиналиная индуктивность: 100 нГн; Добротность, не менее: 34; Резонансная частота, не менее: 1.40 ГГц; Сопротивление обмотки постоянноми току, не более: 0.580 Ом; Допустимый ток обмотки: 400 мА; Диапазон рабочих температур: от -60 до +125 ℃; Упаковка: Катушка и лента; Типоразмер: 1608 (0603); Технология монтажа: SMT; Изготовитель: АО "НПО "ЭРКОН"
footprint КИК-1608_О (Катушка индуктивности с керамическим сердечником  типоразмер 1005(0402))
pins: 1, 2

## КИК-1608-100 нГн ±10% Зл
designator L?, comment 100 нГн ±10%  (value not drawn)
Катушка индуктивности с керамическим сердечником и золотым покрытием контактных площадок; Номиналиная индуктивность: 100 нГн; Добротность, не менее: 34; Резонансная частота, не менее: 1.40 ГГц; Сопротивление обмотки постоянноми току, не более: 0.580 Ом; Допустимый ток обмотки: 400 мА; Диапазон рабочих температур: от -60 до +125 ℃; Упаковка: Катушка и лента; Типоразмер: 1608 (0603); Технология монтажа: SMT; Изготовитель: АО "НПО "ЭРКОН"
footprint КИК-1608_Зл (Катушка индуктивности с керамическим сердечником  типоразмер 1005(0402))
pins: 1, 2

## КИК-1608-100 нГн ±20% O
designator L?, comment 100 нГн ±20%  (value not drawn)
Катушка индуктивности с керамическим сердечником и  финишным покрытием контактных площадок оловом; Номиналиная индуктивность: 100 нГн; Добротность, не менее: 34; Резонансная частота, не менее: 1.40 ГГц; Сопротивление обмотки постоянноми току, не более: 0.580 Ом; Допустимый ток обмотки: 400 мА; Диапазон рабочих температур: от -60 до +125 ℃; Упаковка: Катушка и лента; Типоразмер: 1608 (0603); Технология монтажа: SMT; Изготовитель: АО "НПО "ЭРКОН"
footprint КИК-1608_О (Катушка индуктивности с керамическим сердечником  типоразмер 1005(0402))
pins: 1, 2

## КИК-1608-100 нГн ±20% Зл
designator L?, comment 100 нГн ±20%  (value not drawn)
Катушка индуктивности с керамическим сердечником и золотым покрытием контактных площадок; Номиналиная индуктивность: 100 нГн; Добротность, не менее: 34; Резонансная частота, не менее: 1.40 ГГц; Сопротивление обмотки постоянноми току, не более: 0.580 Ом; Допустимый ток обмотки: 400 мА; Диапазон рабочих температур: от -60 до +125 ℃; Упаковка: Катушка и лента; Типоразмер: 1608 (0603); Технология монтажа: SMT; Изготовитель: АО "НПО "ЭРКОН"
footprint КИК-1608_Зл (Катушка индуктивности с керамическим сердечником  типоразмер 1005(0402))
pins: 1, 2

## КИК-1608-110 нГн ±2% O
designator L?, comment 110 нГн ±2%  (value not drawn)
Катушка индуктивности с керамическим сердечником и  финишным покрытием контактных площадок оловом; Номиналиная индуктивность: 110 нГн; Добротность, не менее: 32; Резонансная частота, не менее: 1.35 ГГц; Сопротивление обмотки постоянноми току, не более: 0.610 Ом; Допустимый ток обмотки: 300 мА; Диапазон рабочих температур: от -60 до +125 ℃; Упаковка: Катушка и лента; Типоразмер: 1608 (0603); Технология монтажа: SMT; Изготовитель: АО "НПО "ЭРКОН"
footprint КИК-1608_О (Катушка индуктивности с керамическим сердечником  типоразмер 1005(0402))
pins: 1, 2

## КИК-1608-110 нГн ±2% Зл
designator L?, comment 110 нГн ±2%  (value not drawn)
Катушка индуктивности с керамическим сердечником и золотым покрытием контактных площадок; Номиналиная индуктивность: 110 нГн; Добротность, не менее: 32; Резонансная частота, не менее: 1.35 ГГц; Сопротивление обмотки постоянноми току, не более: 0.610 Ом; Допустимый ток обмотки: 300 мА; Диапазон рабочих температур: от -60 до +125 ℃; Упаковка: Катушка и лента; Типоразмер: 1608 (0603); Технология монтажа: SMT; Изготовитель: АО "НПО "ЭРКОН"
footprint КИК-1608_Зл (Катушка индуктивности с керамическим сердечником  типоразмер 1005(0402))
pins: 1, 2

## КИК-1608-110 нГн ±5% O
designator L?, comment 110 нГн ±5%  (value not drawn)
Катушка индуктивности с керамическим сердечником и  финишным покрытием контактных площадок оловом; Номиналиная индуктивность: 110 нГн; Добротность, не менее: 32; Резонансная частота, не менее: 1.35 ГГц; Сопротивление обмотки постоянноми току, не более: 0.610 Ом; Допустимый ток обмотки: 300 мА; Диапазон рабочих температур: от -60 до +125 ℃; Упаковка: Катушка и лента; Типоразмер: 1608 (0603); Технология монтажа: SMT; Изготовитель: АО "НПО "ЭРКОН"
footprint КИК-1608_О (Катушка индуктивности с керамическим сердечником  типоразмер 1005(0402))
pins: 1, 2

## КИК-1608-110 нГн ±5% Зл
designator L?, comment 110 нГн ±5%  (value not drawn)
Катушка индуктивности с керамическим сердечником и золотым покрытием контактных площадок; Номиналиная индуктивность: 110 нГн; Добротность, не менее: 32; Резонансная частота, не менее: 1.35 ГГц; Сопротивление обмотки постоянноми току, не более: 0.610 Ом; Допустимый ток обмотки: 300 мА; Диапазон рабочих температур: от -60 до +125 ℃; Упаковка: Катушка и лента; Типоразмер: 1608 (0603); Технология монтажа: SMT; Изготовитель: АО "НПО "ЭРКОН"
footprint КИК-1608_Зл (Катушка индуктивности с керамическим сердечником  типоразмер 1005(0402))
pins: 1, 2

## КИК-1608-110 нГн ±10% O
designator L?, comment 110 нГн ±10%  (value not drawn)
Катушка индуктивности с керамическим сердечником и  финишным покрытием контактных площадок оловом; Номиналиная индуктивность: 110 нГн; Добротность, не менее: 32; Резонансная частота, не менее: 1.35 ГГц; Сопротивление обмотки постоянноми току, не более: 0.610 Ом; Допустимый ток обмотки: 300 мА; Диапазон рабочих температур: от -60 до +125 ℃; Упаковка: Катушка и лента; Типоразмер: 1608 (0603); Технология монтажа: SMT; Изготовитель: АО "НПО "ЭРКОН"
footprint КИК-1608_О (Катушка индуктивности с керамическим сердечником  типоразмер 1005(0402))
pins: 1, 2

## КИК-1608-110 нГн ±10% Зл
designator L?, comment 110 нГн ±10%  (value not drawn)
Катушка индуктивности с керамическим сердечником и золотым покрытием контактных площадок; Номиналиная индуктивность: 110 нГн; Добротность, не менее: 32; Резонансная частота, не менее: 1.35 ГГц; Сопротивление обмотки постоянноми току, не более: 0.610 Ом; Допустимый ток обмотки: 300 мА; Диапазон рабочих температур: от -60 до +125 ℃; Упаковка: Катушка и лента; Типоразмер: 1608 (0603); Технология монтажа: SMT; Изготовитель: АО "НПО "ЭРКОН"
footprint КИК-1608_Зл (Катушка индуктивности с керамическим сердечником  типоразмер 1005(0402))
pins: 1, 2

## КИК-1608-110 нГн ±20% O
designator L?, comment 110 нГн ±20%  (value not drawn)
Катушка индуктивности с керамическим сердечником и  финишным покрытием контактных площадок оловом; Номиналиная индуктивность: 110 нГн; Добротность, не менее: 32; Резонансная частота, не менее: 1.35 ГГц; Сопротивление обмотки постоянноми току, не более: 0.610 Ом; Допустимый ток обмотки: 300 мА; Диапазон рабочих температур: от -60 до +125 ℃; Упаковка: Катушка и лента; Типоразмер: 1608 (0603); Технология монтажа: SMT; Изготовитель: АО "НПО "ЭРКОН"
footprint КИК-1608_О (Катушка индуктивности с керамическим сердечником  типоразмер 1005(0402))
pins: 1, 2

## КИК-1608-110 нГн ±20% Зл
designator L?, comment 110 нГн ±20%  (value not drawn)
Катушка индуктивности с керамическим сердечником и золотым покрытием контактных площадок; Номиналиная индуктивность: 110 нГн; Добротность, не менее: 32; Резонансная частота, не менее: 1.35 ГГц; Сопротивление обмотки постоянноми току, не более: 0.610 Ом; Допустимый ток обмотки: 300 мА; Диапазон рабочих температур: от -60 до +125 ℃; Упаковка: Катушка и лента; Типоразмер: 1608 (0603); Технология монтажа: SMT; Изготовитель: АО "НПО "ЭРКОН"
footprint КИК-1608_Зл (Катушка индуктивности с керамическим сердечником  типоразмер 1005(0402))
pins: 1, 2

## КИК-1608-120 нГн ±2% O
designator L?, comment 120 нГн ±2%  (value not drawn)
Катушка индуктивности с керамическим сердечником и  финишным покрытием контактных площадок оловом; Номиналиная индуктивность: 120 нГн; Добротность, не менее: 32; Резонансная частота, не менее: 1.30 ГГц; Сопротивление обмотки постоянноми току, не более: 0.650 Ом; Допустимый ток обмотки: 300 мА; Диапазон рабочих температур: от -60 до +125 ℃; Упаковка: Катушка и лента; Типоразмер: 1608 (0603); Технология монтажа: SMT; Изготовитель: АО "НПО "ЭРКОН"
footprint КИК-1608_О (Катушка индуктивности с керамическим сердечником  типоразмер 1005(0402))
pins: 1, 2

## КИК-1608-120 нГн ±2% Зл
designator L?, comment 120 нГн ±2%  (value not drawn)
Катушка индуктивности с керамическим сердечником и золотым покрытием контактных площадок; Номиналиная индуктивность: 120 нГн; Добротность, не менее: 32; Резонансная частота, не менее: 1.30 ГГц; Сопротивление обмотки постоянноми току, не более: 0.650 Ом; Допустимый ток обмотки: 300 мА; Диапазон рабочих температур: от -60 до +125 ℃; Упаковка: Катушка и лента; Типоразмер: 1608 (0603); Технология монтажа: SMT; Изготовитель: АО "НПО "ЭРКОН"
footprint КИК-1608_Зл (Катушка индуктивности с керамическим сердечником  типоразмер 1005(0402))
pins: 1, 2

## КИК-1608-120 нГн ±5% O
designator L?, comment 120 нГн ±5%  (value not drawn)
Катушка индуктивности с керамическим сердечником и  финишным покрытием контактных площадок оловом; Номиналиная индуктивность: 120 нГн; Добротность, не менее: 32; Резонансная частота, не менее: 1.30 ГГц; Сопротивление обмотки постоянноми току, не более: 0.650 Ом; Допустимый ток обмотки: 300 мА; Диапазон рабочих температур: от -60 до +125 ℃; Упаковка: Катушка и лента; Типоразмер: 1608 (0603); Технология монтажа: SMT; Изготовитель: АО "НПО "ЭРКОН"
footprint КИК-1608_О (Катушка индуктивности с керамическим сердечником  типоразмер 1005(0402))
pins: 1, 2

## КИК-1608-120 нГн ±5% Зл
designator L?, comment 120 нГн ±5%  (value not drawn)
Катушка индуктивности с керамическим сердечником и золотым покрытием контактных площадок; Номиналиная индуктивность: 120 нГн; Добротность, не менее: 32; Резонансная частота, не менее: 1.30 ГГц; Сопротивление обмотки постоянноми току, не более: 0.650 Ом; Допустимый ток обмотки: 300 мА; Диапазон рабочих температур: от -60 до +125 ℃; Упаковка: Катушка и лента; Типоразмер: 1608 (0603); Технология монтажа: SMT; Изготовитель: АО "НПО "ЭРКОН"
footprint КИК-1608_Зл (Катушка индуктивности с керамическим сердечником  типоразмер 1005(0402))
pins: 1, 2

## КИК-1608-120 нГн ±10% O
designator L?, comment 120 нГн ±10%  (value not drawn)
Катушка индуктивности с керамическим сердечником и  финишным покрытием контактных площадок оловом; Номиналиная индуктивность: 120 нГн; Добротность, не менее: 32; Резонансная частота, не менее: 1.30 ГГц; Сопротивление обмотки постоянноми току, не более: 0.650 Ом; Допустимый ток обмотки: 300 мА; Диапазон рабочих температур: от -60 до +125 ℃; Упаковка: Катушка и лента; Типоразмер: 1608 (0603); Технология монтажа: SMT; Изготовитель: АО "НПО "ЭРКОН"
footprint КИК-1608_О (Катушка индуктивности с керамическим сердечником  типоразмер 1005(0402))
pins: 1, 2

## КИК-1608-120 нГн ±10% Зл
designator L?, comment 120 нГн ±10%  (value not drawn)
Катушка индуктивности с керамическим сердечником и золотым покрытием контактных площадок; Номиналиная индуктивность: 120 нГн; Добротность, не менее: 32; Резонансная частота, не менее: 1.30 ГГц; Сопротивление обмотки постоянноми току, не более: 0.650 Ом; Допустимый ток обмотки: 300 мА; Диапазон рабочих температур: от -60 до +125 ℃; Упаковка: Катушка и лента; Типоразмер: 1608 (0603); Технология монтажа: SMT; Изготовитель: АО "НПО "ЭРКОН"
footprint КИК-1608_Зл (Катушка индуктивности с керамическим сердечником  типоразмер 1005(0402))
pins: 1, 2

## КИК-1608-120 нГн ±20% O
designator L?, comment 120 нГн ±20%  (value not drawn)
Катушка индуктивности с керамическим сердечником и  финишным покрытием контактных площадок оловом; Номиналиная индуктивность: 120 нГн; Добротность, не менее: 32; Резонансная частота, не менее: 1.30 ГГц; Сопротивление обмотки постоянноми току, не более: 0.650 Ом; Допустимый ток обмотки: 300 мА; Диапазон рабочих температур: от -60 до +125 ℃; Упаковка: Катушка и лента; Типоразмер: 1608 (0603); Технология монтажа: SMT; Изготовитель: АО "НПО "ЭРКОН"
footprint КИК-1608_О (Катушка индуктивности с керамическим сердечником  типоразмер 1005(0402))
pins: 1, 2

## КИК-1608-120 нГн ±20% Зл
designator L?, comment 120 нГн ±20%  (value not drawn)
Катушка индуктивности с керамическим сердечником и золотым покрытием контактных площадок; Номиналиная индуктивность: 120 нГн; Добротность, не менее: 32; Резонансная частота, не менее: 1.30 ГГц; Сопротивление обмотки постоянноми току, не более: 0.650 Ом; Допустимый ток обмотки: 300 мА; Диапазон рабочих температур: от -60 до +125 ℃; Упаковка: Катушка и лента; Типоразмер: 1608 (0603); Технология монтажа: SMT; Изготовитель: АО "НПО "ЭРКОН"
footprint КИК-1608_Зл (Катушка индуктивности с керамическим сердечником  типоразмер 1005(0402))
pins: 1, 2

## КИК-1608-150 нГн ±2% O
designator L?, comment 150 нГн ±2%  (value not drawn)
Катушка индуктивности с керамическим сердечником и  финишным покрытием контактных площадок оловом; Номиналиная индуктивность: 150 нГн; Добротность, не менее: 28; Резонансная частота, не менее: 0.990 ГГц; Сопротивление обмотки постоянноми току, не более: 0.920 Ом; Допустимый ток обмотки: 280 мА; Диапазон рабочих температур: от -60 до +125 ℃; Упаковка: Катушка и лента; Типоразмер: 1608 (0603); Технология монтажа: SMT; Изготовитель: АО "НПО "ЭРКОН"
footprint КИК-1608_О (Катушка индуктивности с керамическим сердечником  типоразмер 1005(0402))
pins: 1, 2

## КИК-1608-150 нГн ±2% Зл
designator L?, comment 150 нГн ±2%  (value not drawn)
Катушка индуктивности с керамическим сердечником и золотым покрытием контактных площадок; Номиналиная индуктивность: 150 нГн; Добротность, не менее: 28; Резонансная частота, не менее: 0.990 ГГц; Сопротивление обмотки постоянноми току, не более: 0.920 Ом; Допустимый ток обмотки: 280 мА; Диапазон рабочих температур: от -60 до +125 ℃; Упаковка: Катушка и лента; Типоразмер: 1608 (0603); Технология монтажа: SMT; Изготовитель: АО "НПО "ЭРКОН"
footprint КИК-1608_Зл (Катушка индуктивности с керамическим сердечником  типоразмер 1005(0402))
pins: 1, 2

## КИК-1608-150 нГн ±5% O
designator L?, comment 150 нГн ±5%  (value not drawn)
Катушка индуктивности с керамическим сердечником и  финишным покрытием контактных площадок оловом; Номиналиная индуктивность: 150 нГн; Добротность, не менее: 28; Резонансная частота, не менее: 0.990 ГГц; Сопротивление обмотки постоянноми току, не более: 0.920 Ом; Допустимый ток обмотки: 280 мА; Диапазон рабочих температур: от -60 до +125 ℃; Упаковка: Катушка и лента; Типоразмер: 1608 (0603); Технология монтажа: SMT; Изготовитель: АО "НПО "ЭРКОН"
footprint КИК-1608_О (Катушка индуктивности с керамическим сердечником  типоразмер 1005(0402))
pins: 1, 2

## КИК-1608-150 нГн ±5% Зл
designator L?, comment 150 нГн ±5%  (value not drawn)
Катушка индуктивности с керамическим сердечником и золотым покрытием контактных площадок; Номиналиная индуктивность: 150 нГн; Добротность, не менее: 28; Резонансная частота, не менее: 0.990 ГГц; Сопротивление обмотки постоянноми току, не более: 0.920 Ом; Допустимый ток обмотки: 280 мА; Диапазон рабочих температур: от -60 до +125 ℃; Упаковка: Катушка и лента; Типоразмер: 1608 (0603); Технология монтажа: SMT; Изготовитель: АО "НПО "ЭРКОН"
footprint КИК-1608_Зл (Катушка индуктивности с керамическим сердечником  типоразмер 1005(0402))
pins: 1, 2

## КИК-1608-150 нГн ±10% O
designator L?, comment 150 нГн ±10%  (value not drawn)
Катушка индуктивности с керамическим сердечником и  финишным покрытием контактных площадок оловом; Номиналиная индуктивность: 150 нГн; Добротность, не менее: 28; Резонансная частота, не менее: 0.990 ГГц; Сопротивление обмотки постоянноми току, не более: 0.920 Ом; Допустимый ток обмотки: 280 мА; Диапазон рабочих температур: от -60 до +125 ℃; Упаковка: Катушка и лента; Типоразмер: 1608 (0603); Технология монтажа: SMT; Изготовитель: АО "НПО "ЭРКОН"
footprint КИК-1608_О (Катушка индуктивности с керамическим сердечником  типоразмер 1005(0402))
pins: 1, 2

## КИК-1608-150 нГн ±10% Зл
designator L?, comment 150 нГн ±10%  (value not drawn)
Катушка индуктивности с керамическим сердечником и золотым покрытием контактных площадок; Номиналиная индуктивность: 150 нГн; Добротность, не менее: 28; Резонансная частота, не менее: 0.990 ГГц; Сопротивление обмотки постоянноми току, не более: 0.920 Ом; Допустимый ток обмотки: 280 мА; Диапазон рабочих температур: от -60 до +125 ℃; Упаковка: Катушка и лента; Типоразмер: 1608 (0603); Технология монтажа: SMT; Изготовитель: АО "НПО "ЭРКОН"
footprint КИК-1608_Зл (Катушка индуктивности с керамическим сердечником  типоразмер 1005(0402))
pins: 1, 2

## КИК-1608-150 нГн ±20% O
designator L?, comment 150 нГн ±20%  (value not drawn)
Катушка индуктивности с керамическим сердечником и  финишным покрытием контактных площадок оловом; Номиналиная индуктивность: 150 нГн; Добротность, не менее: 28; Резонансная частота, не менее: 0.990 ГГц; Сопротивление обмотки постоянноми току, не более: 0.920 Ом; Допустимый ток обмотки: 280 мА; Диапазон рабочих температур: от -60 до +125 ℃; Упаковка: Катушка и лента; Типоразмер: 1608 (0603); Технология монтажа: SMT; Изготовитель: АО "НПО "ЭРКОН"
footprint КИК-1608_О (Катушка индуктивности с керамическим сердечником  типоразмер 1005(0402))
pins: 1, 2

## КИК-1608-150 нГн ±20% Зл
designator L?, comment 150 нГн ±20%  (value not drawn)
Катушка индуктивности с керамическим сердечником и золотым покрытием контактных площадок; Номиналиная индуктивность: 150 нГн; Добротность, не менее: 28; Резонансная частота, не менее: 0.990 ГГц; Сопротивление обмотки постоянноми току, не более: 0.920 Ом; Допустимый ток обмотки: 280 мА; Диапазон рабочих температур: от -60 до +125 ℃; Упаковка: Катушка и лента; Типоразмер: 1608 (0603); Технология монтажа: SMT; Изготовитель: АО "НПО "ЭРКОН"
footprint КИК-1608_Зл (Катушка индуктивности с керамическим сердечником  типоразмер 1005(0402))
pins: 1, 2

## КИК-1608-180 нГн ±2% O
designator L?, comment 180 нГн ±2%  (value not drawn)
Катушка индуктивности с керамическим сердечником и  финишным покрытием контактных площадок оловом; Номиналиная индуктивность: 180 нГн; Добротность, не менее: 25; Резонансная частота, не менее: 0.990 ГГц; Сопротивление обмотки постоянноми току, не более: 1.25 Ом; Допустимый ток обмотки: 240 мА; Диапазон рабочих температур: от -60 до +125 ℃; Упаковка: Катушка и лента; Типоразмер: 1608 (0603); Технология монтажа: SMT; Изготовитель: АО "НПО "ЭРКОН"
footprint КИК-1608_О (Катушка индуктивности с керамическим сердечником  типоразмер 1005(0402))
pins: 1, 2

## КИК-1608-180 нГн ±2% Зл
designator L?, comment 180 нГн ±2%  (value not drawn)
Катушка индуктивности с керамическим сердечником и золотым покрытием контактных площадок; Номиналиная индуктивность: 180 нГн; Добротность, не менее: 25; Резонансная частота, не менее: 0.990 ГГц; Сопротивление обмотки постоянноми току, не более: 1.25 Ом; Допустимый ток обмотки: 240 мА; Диапазон рабочих температур: от -60 до +125 ℃; Упаковка: Катушка и лента; Типоразмер: 1608 (0603); Технология монтажа: SMT; Изготовитель: АО "НПО "ЭРКОН"
footprint КИК-1608_Зл (Катушка индуктивности с керамическим сердечником  типоразмер 1005(0402))
pins: 1, 2

## КИК-1608-180 нГн ±5% O
designator L?, comment 180 нГн ±5%  (value not drawn)
Катушка индуктивности с керамическим сердечником и  финишным покрытием контактных площадок оловом; Номиналиная индуктивность: 180 нГн; Добротность, не менее: 25; Резонансная частота, не менее: 0.990 ГГц; Сопротивление обмотки постоянноми току, не более: 1.25 Ом; Допустимый ток обмотки: 240 мА; Диапазон рабочих температур: от -60 до +125 ℃; Упаковка: Катушка и лента; Типоразмер: 1608 (0603); Технология монтажа: SMT; Изготовитель: АО "НПО "ЭРКОН"
footprint КИК-1608_О (Катушка индуктивности с керамическим сердечником  типоразмер 1005(0402))
pins: 1, 2

## КИК-1608-180 нГн ±5% Зл
designator L?, comment 180 нГн ±5%  (value not drawn)
Катушка индуктивности с керамическим сердечником и золотым покрытием контактных площадок; Номиналиная индуктивность: 180 нГн; Добротность, не менее: 25; Резонансная частота, не менее: 0.990 ГГц; Сопротивление обмотки постоянноми току, не более: 1.25 Ом; Допустимый ток обмотки: 240 мА; Диапазон рабочих температур: от -60 до +125 ℃; Упаковка: Катушка и лента; Типоразмер: 1608 (0603); Технология монтажа: SMT; Изготовитель: АО "НПО "ЭРКОН"
footprint КИК-1608_Зл (Катушка индуктивности с керамическим сердечником  типоразмер 1005(0402))
pins: 1, 2

## КИК-1608-180 нГн ±10% O
designator L?, comment 180 нГн ±10%  (value not drawn)
Катушка индуктивности с керамическим сердечником и  финишным покрытием контактных площадок оловом; Номиналиная индуктивность: 180 нГн; Добротность, не менее: 25; Резонансная частота, не менее: 0.990 ГГц; Сопротивление обмотки постоянноми току, не более: 1.25 Ом; Допустимый ток обмотки: 240 мА; Диапазон рабочих температур: от -60 до +125 ℃; Упаковка: Катушка и лента; Типоразмер: 1608 (0603); Технология монтажа: SMT; Изготовитель: АО "НПО "ЭРКОН"
footprint КИК-1608_О (Катушка индуктивности с керамическим сердечником  типоразмер 1005(0402))
pins: 1, 2

## КИК-1608-180 нГн ±10% Зл
designator L?, comment 180 нГн ±10%  (value not drawn)
Катушка индуктивности с керамическим сердечником и золотым покрытием контактных площадок; Номиналиная индуктивность: 180 нГн; Добротность, не менее: 25; Резонансная частота, не менее: 0.990 ГГц; Сопротивление обмотки постоянноми току, не более: 1.25 Ом; Допустимый ток обмотки: 240 мА; Диапазон рабочих температур: от -60 до +125 ℃; Упаковка: Катушка и лента; Типоразмер: 1608 (0603); Технология монтажа: SMT; Изготовитель: АО "НПО "ЭРКОН"
footprint КИК-1608_Зл (Катушка индуктивности с керамическим сердечником  типоразмер 1005(0402))
pins: 1, 2

## КИК-1608-180 нГн ±20% O
designator L?, comment 180 нГн ±20%  (value not drawn)
Катушка индуктивности с керамическим сердечником и  финишным покрытием контактных площадок оловом; Номиналиная индуктивность: 180 нГн; Добротность, не менее: 25; Резонансная частота, не менее: 0.990 ГГц; Сопротивление обмотки постоянноми току, не более: 1.25 Ом; Допустимый ток обмотки: 240 мА; Диапазон рабочих температур: от -60 до +125 ℃; Упаковка: Катушка и лента; Типоразмер: 1608 (0603); Технология монтажа: SMT; Изготовитель: АО "НПО "ЭРКОН"
footprint КИК-1608_О (Катушка индуктивности с керамическим сердечником  типоразмер 1005(0402))
pins: 1, 2

## КИК-1608-180 нГн ±20% Зл
designator L?, comment 180 нГн ±20%  (value not drawn)
Катушка индуктивности с керамическим сердечником и золотым покрытием контактных площадок; Номиналиная индуктивность: 180 нГн; Добротность, не менее: 25; Резонансная частота, не менее: 0.990 ГГц; Сопротивление обмотки постоянноми току, не более: 1.25 Ом; Допустимый ток обмотки: 240 мА; Диапазон рабочих температур: от -60 до +125 ℃; Упаковка: Катушка и лента; Типоразмер: 1608 (0603); Технология монтажа: SMT; Изготовитель: АО "НПО "ЭРКОН"
footprint КИК-1608_Зл (Катушка индуктивности с керамическим сердечником  типоразмер 1005(0402))
pins: 1, 2


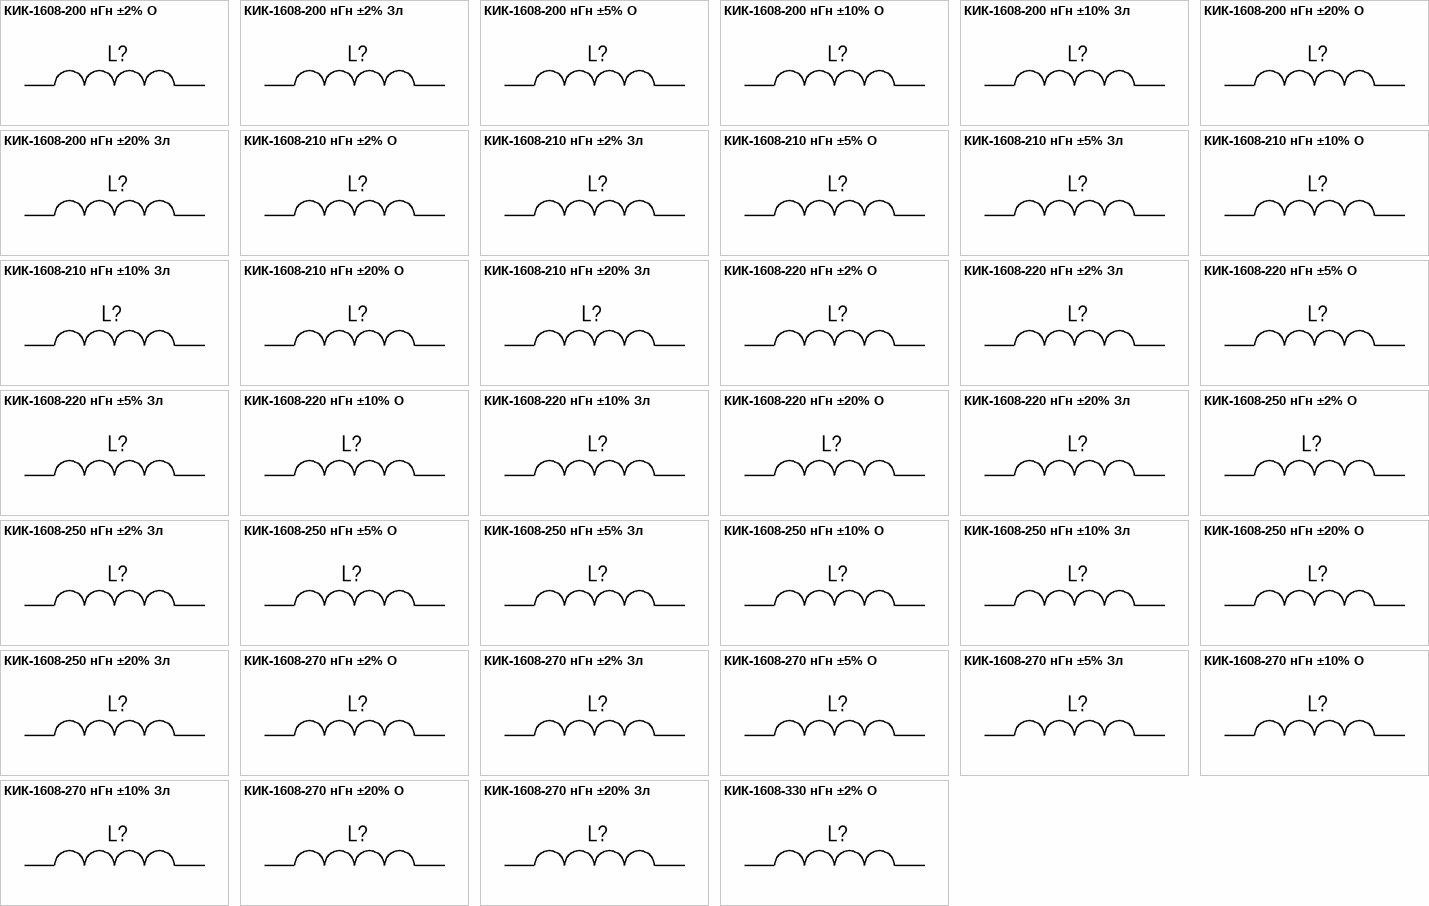
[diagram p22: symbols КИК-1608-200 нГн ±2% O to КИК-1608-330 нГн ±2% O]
## КИК-1608-200 нГн ±2% O
designator L?, comment 200 нГн ±2%  (value not drawn)
Катушка индуктивности с керамическим сердечником и  финишным покрытием контактных площадок оловом; Номиналиная индуктивность: 200 нГн; Добротность, не менее: 25; Резонансная частота, не менее: 0.900 ГГц; Сопротивление обмотки постоянноми току, не более: 1.98 Ом; Допустимый ток обмотки: 200 мА; Диапазон рабочих температур: от -60 до +125 ℃; Упаковка: Катушка и лента; Типоразмер: 1608 (0603); Технология монтажа: SMT; Изготовитель: АО "НПО "ЭРКОН"
footprint КИК-1608_О (Катушка индуктивности с керамическим сердечником  типоразмер 1005(0402))
pins: 1, 2

## КИК-1608-200 нГн ±2% Зл
designator L?, comment 200 нГн ±2%  (value not drawn)
Катушка индуктивности с керамическим сердечником и золотым покрытием контактных площадок; Номиналиная индуктивность: 200 нГн; Добротность, не менее: 25; Резонансная частота, не менее: 0.900 ГГц; Сопротивление обмотки постоянноми току, не более: 1.98 Ом; Допустимый ток обмотки: 200 мА; Диапазон рабочих температур: от -60 до +125 ℃; Упаковка: Катушка и лента; Типоразмер: 1608 (0603); Технология монтажа: SMT; Изготовитель: АО "НПО "ЭРКОН"
footprint КИК-1608_Зл (Катушка индуктивности с керамическим сердечником  типоразмер 1005(0402))
pins: 1, 2

## КИК-1608-200 нГн ±5% O
designator L?, comment 200 нГн ±5%  (value not drawn)
Катушка индуктивности с керамическим сердечником и  финишным покрытием контактных площадок оловом; Номиналиная индуктивность: 200 нГн; Добротность, не менее: 25; Резонансная частота, не менее: 0.900 ГГц; Сопротивление обмотки постоянноми току, не более: 1.98 Ом; Допустимый ток обмотки: 200 мА; Диапазон рабочих температур: от -60 до +125 ℃; Упаковка: Катушка и лента; Типоразмер: 1608 (0603); Технология монтажа: SMT; Изготовитель: АО "НПО "ЭРКОН"
footprint КИК-1608_О (Катушка индуктивности с керамическим сердечником  типоразмер 1005(0402))
pins: 1, 2

## КИК-1608-200 нГн ±10% O
designator L?, comment 200 нГн ±10%  (value not drawn)
Катушка индуктивности с керамическим сердечником и  финишным покрытием контактных площадок оловом; Номиналиная индуктивность: 200 нГн; Добротность, не менее: 25; Резонансная частота, не менее: 0.900 ГГц; Сопротивление обмотки постоянноми току, не более: 1.98 Ом; Допустимый ток обмотки: 200 мА; Диапазон рабочих температур: от -60 до +125 ℃; Упаковка: Катушка и лента; Типоразмер: 1608 (0603); Технология монтажа: SMT; Изготовитель: АО "НПО "ЭРКОН"
footprint КИК-1608_О (Катушка индуктивности с керамическим сердечником  типоразмер 1005(0402))
pins: 1, 2

## КИК-1608-200 нГн ±10% Зл
designator L?, comment 200 нГн ±10%  (value not drawn)
Катушка индуктивности с керамическим сердечником и золотым покрытием контактных площадок; Номиналиная индуктивность: 200 нГн; Добротность, не менее: 25; Резонансная частота, не менее: 0.900 ГГц; Сопротивление обмотки постоянноми току, не более: 1.98 Ом; Допустимый ток обмотки: 200 мА; Диапазон рабочих температур: от -60 до +125 ℃; Упаковка: Катушка и лента; Типоразмер: 1608 (0603); Технология монтажа: SMT; Изготовитель: АО "НПО "ЭРКОН"
footprint КИК-1608_Зл (Катушка индуктивности с керамическим сердечником  типоразмер 1005(0402))
pins: 1, 2

## КИК-1608-200 нГн ±20% O
designator L?, comment 200 нГн ±20%  (value not drawn)
Катушка индуктивности с керамическим сердечником и  финишным покрытием контактных площадок оловом; Номиналиная индуктивность: 200 нГн; Добротность, не менее: 25; Резонансная частота, не менее: 0.900 ГГц; Сопротивление обмотки постоянноми току, не более: 1.98 Ом; Допустимый ток обмотки: 200 мА; Диапазон рабочих температур: от -60 до +125 ℃; Упаковка: Катушка и лента; Типоразмер: 1608 (0603); Технология монтажа: SMT; Изготовитель: АО "НПО "ЭРКОН"
footprint КИК-1608_О (Катушка индуктивности с керамическим сердечником  типоразмер 1005(0402))
pins: 1, 2

## КИК-1608-200 нГн ±20% Зл
designator L?, comment 200 нГн ±20%  (value not drawn)
Катушка индуктивности с керамическим сердечником и золотым покрытием контактных площадок; Номиналиная индуктивность: 200 нГн; Добротность, не менее: 25; Резонансная частота, не менее: 0.900 ГГц; Сопротивление обмотки постоянноми току, не более: 1.98 Ом; Допустимый ток обмотки: 200 мА; Диапазон рабочих температур: от -60 до +125 ℃; Упаковка: Катушка и лента; Типоразмер: 1608 (0603); Технология монтажа: SMT; Изготовитель: АО "НПО "ЭРКОН"
footprint КИК-1608_Зл (Катушка индуктивности с керамическим сердечником  типоразмер 1005(0402))
pins: 1, 2

## КИК-1608-210 нГн ±2% O
designator L?, comment 210 нГн ±2%  (value not drawn)
Катушка индуктивности с керамическим сердечником и  финишным покрытием контактных площадок оловом; Номиналиная индуктивность: 210 нГн; Добротность, не менее: 25; Резонансная частота, не менее: 0.895 ГГц; Сопротивление обмотки постоянноми току, не более: 2.06 Ом; Допустимый ток обмотки: 200 мА; Диапазон рабочих температур: от -60 до +125 ℃; Упаковка: Катушка и лента; Типоразмер: 1608 (0603); Технология монтажа: SMT; Изготовитель: АО "НПО "ЭРКОН"
footprint КИК-1608_О (Катушка индуктивности с керамическим сердечником  типоразмер 1005(0402))
pins: 1, 2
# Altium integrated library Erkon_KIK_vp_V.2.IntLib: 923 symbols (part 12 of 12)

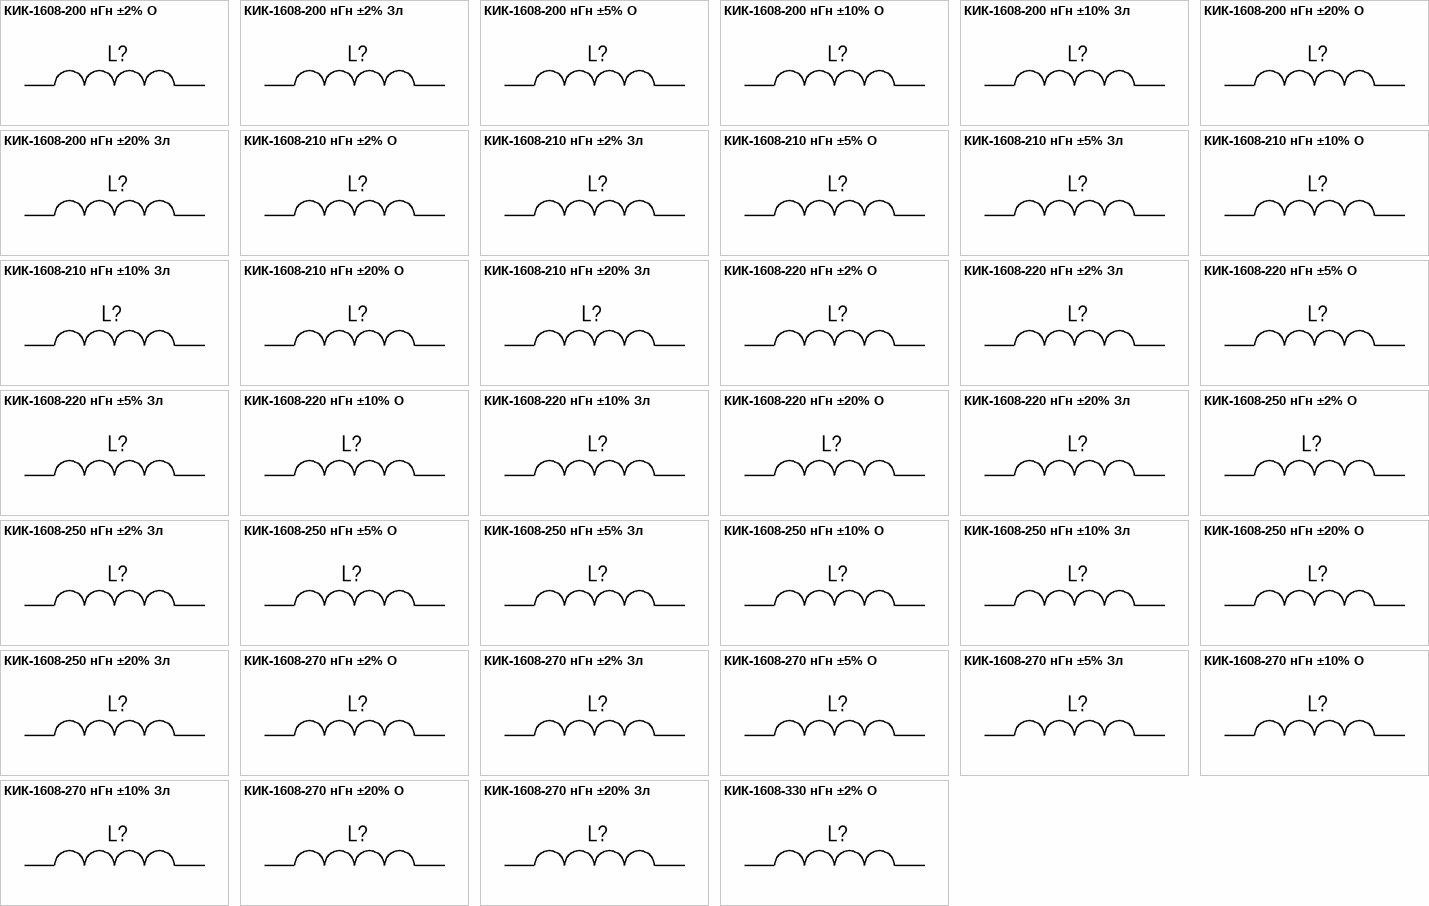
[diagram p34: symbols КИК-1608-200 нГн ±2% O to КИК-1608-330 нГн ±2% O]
## КИК-1608-210 нГн ±2% Зл
designator L?, comment 210 нГн ±2%  (value not drawn)
Катушка индуктивности с керамическим сердечником и золотым покрытием контактных площадок; Номиналиная индуктивность: 210 нГн; Добротность, не менее: 25; Резонансная частота, не менее: 0.895 ГГц; Сопротивление обмотки постоянноми току, не более: 2.06 Ом; Допустимый ток обмотки: 200 мА; Диапазон рабочих температур: от -60 до +125 ℃; Упаковка: Катушка и лента; Типоразмер: 1608 (0603); Технология монтажа: SMT; Изготовитель: АО "НПО "ЭРКОН"
footprint КИК-1608_Зл (Катушка индуктивности с керамическим сердечником  типоразмер 1005(0402))
pins: 1, 2

## КИК-1608-210 нГн ±5% O
designator L?, comment 210 нГн ±5%  (value not drawn)
Катушка индуктивности с керамическим сердечником и  финишным покрытием контактных площадок оловом; Номиналиная индуктивность: 210 нГн; Добротность, не менее: 25; Резонансная частота, не менее: 0.895 ГГц; Сопротивление обмотки постоянноми току, не более: 2.06 Ом; Допустимый ток обмотки: 200 мА; Диапазон рабочих температур: от -60 до +125 ℃; Упаковка: Катушка и лента; Типоразмер: 1608 (0603); Технология монтажа: SMT; Изготовитель: АО "НПО "ЭРКОН"
footprint КИК-1608_О (Катушка индуктивности с керамическим сердечником  типоразмер 1005(0402))
pins: 1, 2

## КИК-1608-210 нГн ±5% Зл
designator L?, comment 210 нГн ±5%  (value not drawn)
Катушка индуктивности с керамическим сердечником и золотым покрытием контактных площадок; Номиналиная индуктивность: 210 нГн; Добротность, не менее: 25; Резонансная частота, не менее: 0.895 ГГц; Сопротивление обмотки постоянноми току, не более: 2.06 Ом; Допустимый ток обмотки: 200 мА; Диапазон рабочих температур: от -60 до +125 ℃; Упаковка: Катушка и лента; Типоразмер: 1608 (0603); Технология монтажа: SMT; Изготовитель: АО "НПО "ЭРКОН"
footprint КИК-1608_Зл (Катушка индуктивности с керамическим сердечником  типоразмер 1005(0402))
pins: 1, 2

## КИК-1608-210 нГн ±10% O
designator L?, comment 210 нГн ±10%  (value not drawn)
Катушка индуктивности с керамическим сердечником и  финишным покрытием контактных площадок оловом; Номиналиная индуктивность: 210 нГн; Добротность, не менее: 25; Резонансная частота, не менее: 0.895 ГГц; Сопротивление обмотки постоянноми току, не более: 2.06 Ом; Допустимый ток обмотки: 200 мА; Диапазон рабочих температур: от -60 до +125 ℃; Упаковка: Катушка и лента; Типоразмер: 1608 (0603); Технология монтажа: SMT; Изготовитель: АО "НПО "ЭРКОН"
footprint КИК-1608_О (Катушка индуктивности с керамическим сердечником  типоразмер 1005(0402))
pins: 1, 2

## КИК-1608-210 нГн ±10% Зл
designator L?, comment 210 нГн ±10%  (value not drawn)
Катушка индуктивности с керамическим сердечником и золотым покрытием контактных площадок; Номиналиная индуктивность: 210 нГн; Добротность, не менее: 25; Резонансная частота, не менее: 0.895 ГГц; Сопротивление обмотки постоянноми току, не более: 2.06 Ом; Допустимый ток обмотки: 200 мА; Диапазон рабочих температур: от -60 до +125 ℃; Упаковка: Катушка и лента; Типоразмер: 1608 (0603); Технология монтажа: SMT; Изготовитель: АО "НПО "ЭРКОН"
footprint КИК-1608_Зл (Катушка индуктивности с керамическим сердечником  типоразмер 1005(0402))
pins: 1, 2

## КИК-1608-210 нГн ±20% O
designator L?, comment 210 нГн ±20%  (value not drawn)
Катушка индуктивности с керамическим сердечником и  финишным покрытием контактных площадок оловом; Номиналиная индуктивность: 210 нГн; Добротность, не менее: 25; Резонансная частота, не менее: 0.895 ГГц; Сопротивление обмотки постоянноми току, не более: 2.06 Ом; Допустимый ток обмотки: 200 мА; Диапазон рабочих температур: от -60 до +125 ℃; Упаковка: Катушка и лента; Типоразмер: 1608 (0603); Технология монтажа: SMT; Изготовитель: АО "НПО "ЭРКОН"
footprint КИК-1608_О (Катушка индуктивности с керамическим сердечником  типоразмер 1005(0402))
pins: 1, 2

## КИК-1608-210 нГн ±20% Зл
designator L?, comment 210 нГн ±20%  (value not drawn)
Катушка индуктивности с керамическим сердечником и золотым покрытием контактных площадок; Номиналиная индуктивность: 210 нГн; Добротность, не менее: 25; Резонансная частота, не менее: 0.895 ГГц; Сопротивление обмотки постоянноми току, не более: 2.06 Ом; Допустимый ток обмотки: 200 мА; Диапазон рабочих температур: от -60 до +125 ℃; Упаковка: Катушка и лента; Типоразмер: 1608 (0603); Технология монтажа: SMT; Изготовитель: АО "НПО "ЭРКОН"
footprint КИК-1608_Зл (Катушка индуктивности с керамическим сердечником  типоразмер 1005(0402))
pins: 1, 2

## КИК-1608-220 нГн ±2% O
designator L?, comment 220 нГн ±2%  (value not drawn)
Катушка индуктивности с керамическим сердечником и  финишным покрытием контактных площадок оловом; Номиналиная индуктивность: 220 нГн; Добротность, не менее: 25; Резонансная частота, не менее: 0.900 ГГц; Сопротивление обмотки постоянноми току, не более: 2.10 Ом; Допустимый ток обмотки: 200 мА; Диапазон рабочих температур: от -60 до +125 ℃; Упаковка: Катушка и лента; Типоразмер: 1608 (0603); Технология монтажа: SMT; Изготовитель: АО "НПО "ЭРКОН"
footprint КИК-1608_О (Катушка индуктивности с керамическим сердечником  типоразмер 1005(0402))
pins: 1, 2

## КИК-1608-220 нГн ±2% Зл
designator L?, comment 220 нГн ±2%  (value not drawn)
Катушка индуктивности с керамическим сердечником и золотым покрытием контактных площадок; Номиналиная индуктивность: 220 нГн; Добротность, не менее: 25; Резонансная частота, не менее: 0.900 ГГц; Сопротивление обмотки постоянноми току, не более: 2.10 Ом; Допустимый ток обмотки: 200 мА; Диапазон рабочих температур: от -60 до +125 ℃; Упаковка: Катушка и лента; Типоразмер: 1608 (0603); Технология монтажа: SMT; Изготовитель: АО "НПО "ЭРКОН"
footprint КИК-1608_Зл (Катушка индуктивности с керамическим сердечником  типоразмер 1005(0402))
pins: 1, 2

## КИК-1608-220 нГн ±5% O
designator L?, comment 220 нГн ±5%  (value not drawn)
Катушка индуктивности с керамическим сердечником и  финишным покрытием контактных площадок оловом; Номиналиная индуктивность: 220 нГн; Добротность, не менее: 25; Резонансная частота, не менее: 0.900 ГГц; Сопротивление обмотки постоянноми току, не более: 2.10 Ом; Допустимый ток обмотки: 200 мА; Диапазон рабочих температур: от -60 до +125 ℃; Упаковка: Катушка и лента; Типоразмер: 1608 (0603); Технология монтажа: SMT; Изготовитель: АО "НПО "ЭРКОН"
footprint КИК-1608_О (Катушка индуктивности с керамическим сердечником  типоразмер 1005(0402))
pins: 1, 2

## КИК-1608-220 нГн ±5% Зл
designator L?, comment 220 нГн ±5%  (value not drawn)
Катушка индуктивности с керамическим сердечником и золотым покрытием контактных площадок; Номиналиная индуктивность: 220 нГн; Добротность, не менее: 25; Резонансная частота, не менее: 0.900 ГГц; Сопротивление обмотки постоянноми току, не более: 2.10 Ом; Допустимый ток обмотки: 200 мА; Диапазон рабочих температур: от -60 до +125 ℃; Упаковка: Катушка и лента; Типоразмер: 1608 (0603); Технология монтажа: SMT; Изготовитель: АО "НПО "ЭРКОН"
footprint КИК-1608_Зл (Катушка индуктивности с керамическим сердечником  типоразмер 1005(0402))
pins: 1, 2

## КИК-1608-220 нГн ±10% O
designator L?, comment 220 нГн ±10%  (value not drawn)
Катушка индуктивности с керамическим сердечником и  финишным покрытием контактных площадок оловом; Номиналиная индуктивность: 220 нГн; Добротность, не менее: 25; Резонансная частота, не менее: 0.900 ГГц; Сопротивление обмотки постоянноми току, не более: 2.10 Ом; Допустимый ток обмотки: 200 мА; Диапазон рабочих температур: от -60 до +125 ℃; Упаковка: Катушка и лента; Типоразмер: 1608 (0603); Технология монтажа: SMT; Изготовитель: АО "НПО "ЭРКОН"
footprint КИК-1608_О (Катушка индуктивности с керамическим сердечником  типоразмер 1005(0402))
pins: 1, 2

## КИК-1608-220 нГн ±10% Зл
designator L?, comment 220 нГн ±10%  (value not drawn)
Катушка индуктивности с керамическим сердечником и золотым покрытием контактных площадок; Номиналиная индуктивность: 220 нГн; Добротность, не менее: 25; Резонансная частота, не менее: 0.900 ГГц; Сопротивление обмотки постоянноми току, не более: 2.10 Ом; Допустимый ток обмотки: 200 мА; Диапазон рабочих температур: от -60 до +125 ℃; Упаковка: Катушка и лента; Типоразмер: 1608 (0603); Технология монтажа: SMT; Изготовитель: АО "НПО "ЭРКОН"
footprint КИК-1608_Зл (Катушка индуктивности с керамическим сердечником  типоразмер 1005(0402))
pins: 1, 2

## КИК-1608-220 нГн ±20% O
designator L?, comment 220 нГн ±20%  (value not drawn)
Катушка индуктивности с керамическим сердечником и  финишным покрытием контактных площадок оловом; Номиналиная индуктивность: 220 нГн; Добротность, не менее: 25; Резонансная частота, не менее: 0.900 ГГц; Сопротивление обмотки постоянноми току, не более: 2.10 Ом; Допустимый ток обмотки: 200 мА; Диапазон рабочих температур: от -60 до +125 ℃; Упаковка: Катушка и лента; Типоразмер: 1608 (0603); Технология монтажа: SMT; Изготовитель: АО "НПО "ЭРКОН"
footprint КИК-1608_О (Катушка индуктивности с керамическим сердечником  типоразмер 1005(0402))
pins: 1, 2

## КИК-1608-220 нГн ±20% Зл
designator L?, comment 220 нГн ±20%  (value not drawn)
Катушка индуктивности с керамическим сердечником и золотым покрытием контактных площадок; Номиналиная индуктивность: 220 нГн; Добротность, не менее: 25; Резонансная частота, не менее: 0.900 ГГц; Сопротивление обмотки постоянноми току, не более: 2.10 Ом; Допустимый ток обмотки: 200 мА; Диапазон рабочих температур: от -60 до +125 ℃; Упаковка: Катушка и лента; Типоразмер: 1608 (0603); Технология монтажа: SMT; Изготовитель: АО "НПО "ЭРКОН"
footprint КИК-1608_Зл (Катушка индуктивности с керамическим сердечником  типоразмер 1005(0402))
pins: 1, 2

## КИК-1608-250 нГн ±2% O
designator L?, comment 250 нГн ±2%  (value not drawn)
Катушка индуктивности с керамическим сердечником и  финишным покрытием контактных площадок оловом; Номиналиная индуктивность: 250 нГн; Добротность, не менее: 25; Резонансная частота, не менее: 0.822 ГГц; Сопротивление обмотки постоянноми току, не более: 3.55 Ом; Допустимый ток обмотки: 120 мА; Диапазон рабочих температур: от -60 до +125 ℃; Упаковка: Катушка и лента; Типоразмер: 1608 (0603); Технология монтажа: SMT; Изготовитель: АО "НПО "ЭРКОН"
footprint КИК-1608_О (Катушка индуктивности с керамическим сердечником  типоразмер 1005(0402))
pins: 1, 2

## КИК-1608-250 нГн ±2% Зл
designator L?, comment 250 нГн ±2%  (value not drawn)
Катушка индуктивности с керамическим сердечником и золотым покрытием контактных площадок; Номиналиная индуктивность: 250 нГн; Добротность, не менее: 25; Резонансная частота, не менее: 0.822 ГГц; Сопротивление обмотки постоянноми току, не более: 3.55 Ом; Допустимый ток обмотки: 120 мА; Диапазон рабочих температур: от -60 до +125 ℃; Упаковка: Катушка и лента; Типоразмер: 1608 (0603); Технология монтажа: SMT; Изготовитель: АО "НПО "ЭРКОН"
footprint КИК-1608_Зл (Катушка индуктивности с керамическим сердечником  типоразмер 1005(0402))
pins: 1, 2

## КИК-1608-250 нГн ±5% O
designator L?, comment 250 нГн ±5%  (value not drawn)
Катушка индуктивности с керамическим сердечником и  финишным покрытием контактных площадок оловом; Номиналиная индуктивность: 250 нГн; Добротность, не менее: 25; Резонансная частота, не менее: 0.822 ГГц; Сопротивление обмотки постоянноми току, не более: 3.55 Ом; Допустимый ток обмотки: 120 мА; Диапазон рабочих температур: от -60 до +125 ℃; Упаковка: Катушка и лента; Типоразмер: 1608 (0603); Технология монтажа: SMT; Изготовитель: АО "НПО "ЭРКОН"
footprint КИК-1608_О (Катушка индуктивности с керамическим сердечником  типоразмер 1005(0402))
pins: 1, 2

## КИК-1608-250 нГн ±5% Зл
designator L?, comment 250 нГн ±5%  (value not drawn)
Катушка индуктивности с керамическим сердечником и золотым покрытием контактных площадок; Номиналиная индуктивность: 250 нГн; Добротность, не менее: 25; Резонансная частота, не менее: 0.822 ГГц; Сопротивление обмотки постоянноми току, не более: 3.55 Ом; Допустимый ток обмотки: 120 мА; Диапазон рабочих температур: от -60 до +125 ℃; Упаковка: Катушка и лента; Типоразмер: 1608 (0603); Технология монтажа: SMT; Изготовитель: АО "НПО "ЭРКОН"
footprint КИК-1608_Зл (Катушка индуктивности с керамическим сердечником  типоразмер 1005(0402))
pins: 1, 2

## КИК-1608-250 нГн ±10% O
designator L?, comment 250 нГн ±10%  (value not drawn)
Катушка индуктивности с керамическим сердечником и  финишным покрытием контактных площадок оловом; Номиналиная индуктивность: 250 нГн; Добротность, не менее: 25; Резонансная частота, не менее: 0.822 ГГц; Сопротивление обмотки постоянноми току, не более: 3.55 Ом; Допустимый ток обмотки: 120 мА; Диапазон рабочих температур: от -60 до +125 ℃; Упаковка: Катушка и лента; Типоразмер: 1608 (0603); Технология монтажа: SMT; Изготовитель: АО "НПО "ЭРКОН"
footprint КИК-1608_О (Катушка индуктивности с керамическим сердечником  типоразмер 1005(0402))
pins: 1, 2

## КИК-1608-250 нГн ±10% Зл
designator L?, comment 250 нГн ±10%  (value not drawn)
Катушка индуктивности с керамическим сердечником и золотым покрытием контактных площадок; Номиналиная индуктивность: 250 нГн; Добротность, не менее: 25; Резонансная частота, не менее: 0.822 ГГц; Сопротивление обмотки постоянноми току, не более: 3.55 Ом; Допустимый ток обмотки: 120 мА; Диапазон рабочих температур: от -60 до +125 ℃; Упаковка: Катушка и лента; Типоразмер: 1608 (0603); Технология монтажа: SMT; Изготовитель: АО "НПО "ЭРКОН"
footprint КИК-1608_Зл (Катушка индуктивности с керамическим сердечником  типоразмер 1005(0402))
pins: 1, 2

## КИК-1608-250 нГн ±20% O
designator L?, comment 250 нГн ±20%  (value not drawn)
Катушка индуктивности с керамическим сердечником и  финишным покрытием контактных площадок оловом; Номиналиная индуктивность: 250 нГн; Добротность, не менее: 25; Резонансная частота, не менее: 0.822 ГГц; Сопротивление обмотки постоянноми току, не более: 3.55 Ом; Допустимый ток обмотки: 120 мА; Диапазон рабочих температур: от -60 до +125 ℃; Упаковка: Катушка и лента; Типоразмер: 1608 (0603); Технология монтажа: SMT; Изготовитель: АО "НПО "ЭРКОН"
footprint КИК-1608_О (Катушка индуктивности с керамическим сердечником  типоразмер 1005(0402))
pins: 1, 2

## КИК-1608-250 нГн ±20% Зл
designator L?, comment 250 нГн ±20%  (value not drawn)
Катушка индуктивности с керамическим сердечником и золотым покрытием контактных площадок; Номиналиная индуктивность: 250 нГн; Добротность, не менее: 25; Резонансная частота, не менее: 0.822 ГГц; Сопротивление обмотки постоянноми току, не более: 3.55 Ом; Допустимый ток обмотки: 120 мА; Диапазон рабочих температур: от -60 до +125 ℃; Упаковка: Катушка и лента; Типоразмер: 1608 (0603); Технология монтажа: SMT; Изготовитель: АО "НПО "ЭРКОН"
footprint КИК-1608_Зл (Катушка индуктивности с керамическим сердечником  типоразмер 1005(0402))
pins: 1, 2

## КИК-1608-270 нГн ±2% O
designator L?, comment 270 нГн ±2%  (value not drawn)
Катушка индуктивности с керамическим сердечником и  финишным покрытием контактных площадок оловом; Номиналиная индуктивность: 270 нГн; Добротность, не менее: 25; Резонансная частота, не менее: 0.830 ГГц; Сопротивление обмотки постоянноми току, не более: 2.16 Ом; Допустимый ток обмотки: 170 мА; Диапазон рабочих температур: от -60 до +125 ℃; Упаковка: Катушка и лента; Типоразмер: 1608 (0603); Технология монтажа: SMT; Изготовитель: АО "НПО "ЭРКОН"
footprint КИК-1608_О (Катушка индуктивности с керамическим сердечником  типоразмер 1005(0402))
pins: 1, 2

## КИК-1608-270 нГн ±2% Зл
designator L?, comment 270 нГн ±2%  (value not drawn)
Катушка индуктивности с керамическим сердечником и золотым покрытием контактных площадок; Номиналиная индуктивность: 270 нГн; Добротность, не менее: 25; Резонансная частота, не менее: 0.830 ГГц; Сопротивление обмотки постоянноми току, не более: 2.16 Ом; Допустимый ток обмотки: 170 мА; Диапазон рабочих температур: от -60 до +125 ℃; Упаковка: Катушка и лента; Типоразмер: 1608 (0603); Технология монтажа: SMT; Изготовитель: АО "НПО "ЭРКОН"
footprint КИК-1608_Зл (Катушка индуктивности с керамическим сердечником  типоразмер 1005(0402))
pins: 1, 2

## КИК-1608-270 нГн ±5% O
designator L?, comment 270 нГн ±5%  (value not drawn)
Катушка индуктивности с керамическим сердечником и  финишным покрытием контактных площадок оловом; Номиналиная индуктивность: 270 нГн; Добротность, не менее: 25; Резонансная частота, не менее: 0.830 ГГц; Сопротивление обмотки постоянноми току, не более: 2.16 Ом; Допустимый ток обмотки: 170 мА; Диапазон рабочих температур: от -60 до +125 ℃; Упаковка: Катушка и лента; Типоразмер: 1608 (0603); Технология монтажа: SMT; Изготовитель: АО "НПО "ЭРКОН"
footprint КИК-1608_О (Катушка индуктивности с керамическим сердечником  типоразмер 1005(0402))
pins: 1, 2

## КИК-1608-270 нГн ±5% Зл
designator L?, comment 270 нГн ±5%  (value not drawn)
Катушка индуктивности с керамическим сердечником и золотым покрытием контактных площадок; Номиналиная индуктивность: 270 нГн; Добротность, не менее: 25; Резонансная частота, не менее: 0.830 ГГц; Сопротивление обмотки постоянноми току, не более: 2.16 Ом; Допустимый ток обмотки: 170 мА; Диапазон рабочих температур: от -60 до +125 ℃; Упаковка: Катушка и лента; Типоразмер: 1608 (0603); Технология монтажа: SMT; Изготовитель: АО "НПО "ЭРКОН"
footprint КИК-1608_Зл (Катушка индуктивности с керамическим сердечником  типоразмер 1005(0402))
pins: 1, 2

## КИК-1608-270 нГн ±10% O
designator L?, comment 270 нГн ±10%  (value not drawn)
Катушка индуктивности с керамическим сердечником и  финишным покрытием контактных площадок оловом; Номиналиная индуктивность: 270 нГн; Добротность, не менее: 25; Резонансная частота, не менее: 0.830 ГГц; Сопротивление обмотки постоянноми току, не более: 2.16 Ом; Допустимый ток обмотки: 170 мА; Диапазон рабочих температур: от -60 до +125 ℃; Упаковка: Катушка и лента; Типоразмер: 1608 (0603); Технология монтажа: SMT; Изготовитель: АО "НПО "ЭРКОН"
footprint КИК-1608_О (Катушка индуктивности с керамическим сердечником  типоразмер 1005(0402))
pins: 1, 2

## КИК-1608-270 нГн ±10% Зл
designator L?, comment 270 нГн ±10%  (value not drawn)
Катушка индуктивности с керамическим сердечником и золотым покрытием контактных площадок; Номиналиная индуктивность: 270 нГн; Добротность, не менее: 25; Резонансная частота, не менее: 0.830 ГГц; Сопротивление обмотки постоянноми току, не более: 2.16 Ом; Допустимый ток обмотки: 170 мА; Диапазон рабочих температур: от -60 до +125 ℃; Упаковка: Катушка и лента; Типоразмер: 1608 (0603); Технология монтажа: SMT; Изготовитель: АО "НПО "ЭРКОН"
footprint КИК-1608_Зл (Катушка индуктивности с керамическим сердечником  типоразмер 1005(0402))
pins: 1, 2

## КИК-1608-270 нГн ±20% O
designator L?, comment 270 нГн ±20%  (value not drawn)
Катушка индуктивности с керамическим сердечником и  финишным покрытием контактных площадок оловом; Номиналиная индуктивность: 270 нГн; Добротность, не менее: 25; Резонансная частота, не менее: 0.830 ГГц; Сопротивление обмотки постоянноми току, не более: 2.16 Ом; Допустимый ток обмотки: 170 мА; Диапазон рабочих температур: от -60 до +125 ℃; Упаковка: Катушка и лента; Типоразмер: 1608 (0603); Технология монтажа: SMT; Изготовитель: АО "НПО "ЭРКОН"
footprint КИК-1608_О (Катушка индуктивности с керамическим сердечником  типоразмер 1005(0402))
pins: 1, 2

## КИК-1608-270 нГн ±20% Зл
designator L?, comment 270 нГн ±20%  (value not drawn)
Катушка индуктивности с керамическим сердечником и золотым покрытием контактных площадок; Номиналиная индуктивность: 270 нГн; Добротность, не менее: 25; Резонансная частота, не менее: 0.830 ГГц; Сопротивление обмотки постоянноми току, не более: 2.16 Ом; Допустимый ток обмотки: 170 мА; Диапазон рабочих температур: от -60 до +125 ℃; Упаковка: Катушка и лента; Типоразмер: 1608 (0603); Технология монтажа: SMT; Изготовитель: АО "НПО "ЭРКОН"
footprint КИК-1608_Зл (Катушка индуктивности с керамическим сердечником  типоразмер 1005(0402))
pins: 1, 2

## КИК-1608-330 нГн ±2% O
designator L?, comment 330 нГн ±2%  (value not drawn)
Катушка индуктивности с керамическим сердечником и  финишным покрытием контактных площадок оловом; Номиналиная индуктивность: 330 нГн; Добротность, не менее: 25; Резонансная частота, не менее: 0.900 ГГц; Сопротивление обмотки постоянноми току, не более: 3.89 Ом; Допустимый ток обмотки: 100 мА; Диапазон рабочих температур: от -60 до +125 ℃; Упаковка: Катушка и лента; Типоразмер: 1608 (0603); Технология монтажа: SMT; Изготовитель: АО "НПО "ЭРКОН"
footprint КИК-1608_О (Катушка индуктивности с керамическим сердечником  типоразмер 1005(0402))
pins: 1, 2


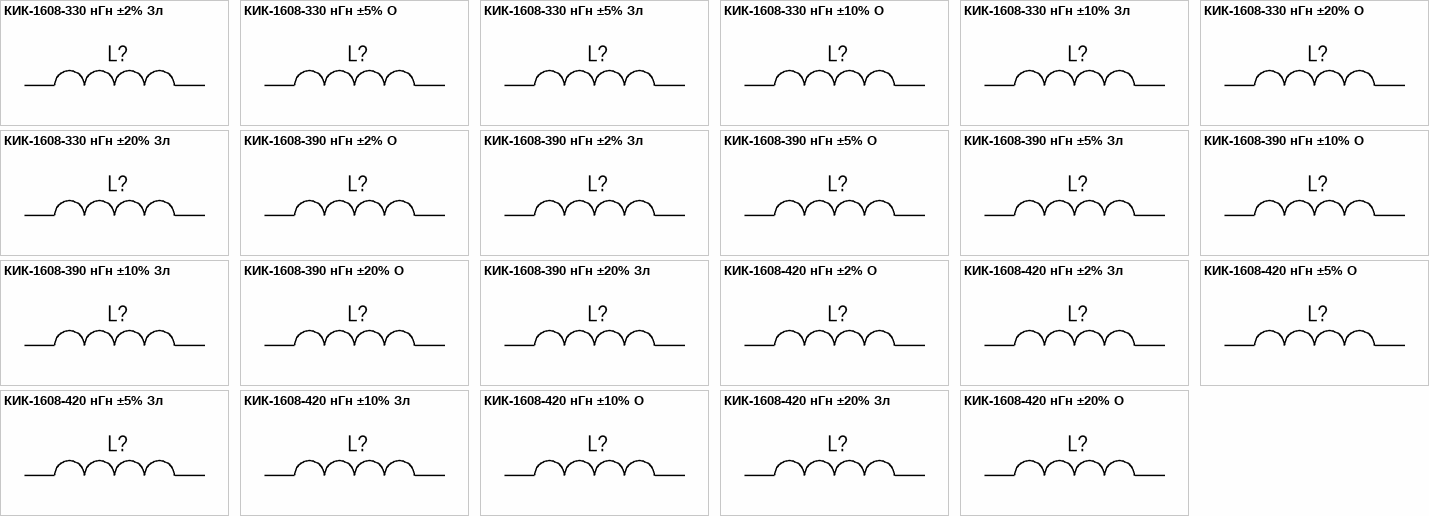
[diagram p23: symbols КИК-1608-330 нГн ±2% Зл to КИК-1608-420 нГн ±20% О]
## КИК-1608-330 нГн ±2% Зл
designator L?, comment 330 нГн ±2%  (value not drawn)
Катушка индуктивности с керамическим сердечником и золотым покрытием контактных площадок; Номиналиная индуктивность: 330 нГн; Добротность, не менее: 25; Резонансная частота, не менее: 0.900 ГГц; Сопротивление обмотки постоянноми току, не более: 3.89 Ом; Допустимый ток обмотки: 100 мА; Диапазон рабочих температур: от -60 до +125 ℃; Упаковка: Катушка и лента; Типоразмер: 1608 (0603); Технология монтажа: SMT; Изготовитель: АО "НПО "ЭРКОН"
footprint КИК-1608_Зл (Катушка индуктивности с керамическим сердечником  типоразмер 1005(0402))
pins: 1, 2

## КИК-1608-330 нГн ±5% O
designator L?, comment 330 нГн ±5%  (value not drawn)
Катушка индуктивности с керамическим сердечником и  финишным покрытием контактных площадок оловом; Номиналиная индуктивность: 330 нГн; Добротность, не менее: 25; Резонансная частота, не менее: 0.900 ГГц; Сопротивление обмотки постоянноми току, не более: 3.89 Ом; Допустимый ток обмотки: 100 мА; Диапазон рабочих температур: от -60 до +125 ℃; Упаковка: Катушка и лента; Типоразмер: 1608 (0603); Технология монтажа: SMT; Изготовитель: АО "НПО "ЭРКОН"
footprint КИК-1608_О (Катушка индуктивности с керамическим сердечником  типоразмер 1005(0402))
pins: 1, 2

## КИК-1608-330 нГн ±5% Зл
designator L?, comment 330 нГн ±5%  (value not drawn)
Катушка индуктивности с керамическим сердечником и золотым покрытием контактных площадок; Номиналиная индуктивность: 330 нГн; Добротность, не менее: 25; Резонансная частота, не менее: 0.900 ГГц; Сопротивление обмотки постоянноми току, не более: 3.89 Ом; Допустимый ток обмотки: 100 мА; Диапазон рабочих температур: от -60 до +125 ℃; Упаковка: Катушка и лента; Типоразмер: 1608 (0603); Технология монтажа: SMT; Изготовитель: АО "НПО "ЭРКОН"
footprint КИК-1608_Зл (Катушка индуктивности с керамическим сердечником  типоразмер 1005(0402))
pins: 1, 2

## КИК-1608-330 нГн ±10% O
designator L?, comment 330 нГн ±10%  (value not drawn)
Катушка индуктивности с керамическим сердечником и  финишным покрытием контактных площадок оловом; Номиналиная индуктивность: 330 нГн; Добротность, не менее: 25; Резонансная частота, не менее: 0.900 ГГц; Сопротивление обмотки постоянноми току, не более: 3.89 Ом; Допустимый ток обмотки: 100 мА; Диапазон рабочих температур: от -60 до +125 ℃; Упаковка: Катушка и лента; Типоразмер: 1608 (0603); Технология монтажа: SMT; Изготовитель: АО "НПО "ЭРКОН"
footprint КИК-1608_О (Катушка индуктивности с керамическим сердечником  типоразмер 1005(0402))
pins: 1, 2

## КИК-1608-330 нГн ±10% Зл
designator L?, comment 330 нГн ±10%  (value not drawn)
Катушка индуктивности с керамическим сердечником и золотым покрытием контактных площадок; Номиналиная индуктивность: 330 нГн; Добротность, не менее: 25; Резонансная частота, не менее: 0.900 ГГц; Сопротивление обмотки постоянноми току, не более: 3.89 Ом; Допустимый ток обмотки: 100 мА; Диапазон рабочих температур: от -60 до +125 ℃; Упаковка: Катушка и лента; Типоразмер: 1608 (0603); Технология монтажа: SMT; Изготовитель: АО "НПО "ЭРКОН"
footprint КИК-1608_Зл (Катушка индуктивности с керамическим сердечником  типоразмер 1005(0402))
pins: 1, 2

## КИК-1608-330 нГн ±20% O
designator L?, comment 330 нГн ±20%  (value not drawn)
Катушка индуктивности с керамическим сердечником и  финишным покрытием контактных площадок оловом; Номиналиная индуктивность: 330 нГн; Добротность, не менее: 25; Резонансная частота, не менее: 0.900 ГГц; Сопротивление обмотки постоянноми току, не более: 3.89 Ом; Допустимый ток обмотки: 100 мА; Диапазон рабочих температур: от -60 до +125 ℃; Упаковка: Катушка и лента; Типоразмер: 1608 (0603); Технология монтажа: SMT; Изготовитель: АО "НПО "ЭРКОН"
footprint КИК-1608_О (Катушка индуктивности с керамическим сердечником  типоразмер 1005(0402))
pins: 1, 2

## КИК-1608-330 нГн ±20% Зл
designator L?, comment 330 нГн ±20%  (value not drawn)
Катушка индуктивности с керамическим сердечником и золотым покрытием контактных площадок; Номиналиная индуктивность: 330 нГн; Добротность, не менее: 25; Резонансная частота, не менее: 0.900 ГГц; Сопротивление обмотки постоянноми току, не более: 3.89 Ом; Допустимый ток обмотки: 100 мА; Диапазон рабочих температур: от -60 до +125 ℃; Упаковка: Катушка и лента; Типоразмер: 1608 (0603); Технология монтажа: SMT; Изготовитель: АО "НПО "ЭРКОН"
footprint КИК-1608_Зл (Катушка индуктивности с керамическим сердечником  типоразмер 1005(0402))
pins: 1, 2

## КИК-1608-390 нГн ±2% O
designator L?, comment 390 нГн ±2%  (value not drawn)
Катушка индуктивности с керамическим сердечником и  финишным покрытием контактных площадок оловом; Номиналиная индуктивность: 390 нГн; Добротность, не менее: 25; Резонансная частота, не менее: 0.780 ГГц; Сопротивление обмотки постоянноми току, не более: 4.35 Ом; Допустимый ток обмотки: 100 мА; Диапазон рабочих температур: от -60 до +125 ℃; Упаковка: Катушка и лента; Типоразмер: 1608 (0603); Технология монтажа: SMT; Изготовитель: АО "НПО "ЭРКОН"
footprint КИК-1608_О (Катушка индуктивности с керамическим сердечником  типоразмер 1005(0402))
pins: 1, 2

## КИК-1608-390 нГн ±2% Зл
designator L?, comment 390 нГн ±2%  (value not drawn)
Катушка индуктивности с керамическим сердечником и золотым покрытием контактных площадок; Номиналиная индуктивность: 390 нГн; Добротность, не менее: 25; Резонансная частота, не менее: 0.780 ГГц; Сопротивление обмотки постоянноми току, не более: 4.35 Ом; Допустимый ток обмотки: 100 мА; Диапазон рабочих температур: от -60 до +125 ℃; Упаковка: Катушка и лента; Типоразмер: 1608 (0603); Технология монтажа: SMT; Изготовитель: АО "НПО "ЭРКОН"
footprint КИК-1608_Зл (Катушка индуктивности с керамическим сердечником  типоразмер 1005(0402))
pins: 1, 2

## КИК-1608-390 нГн ±5% O
designator L?, comment 390 нГн ±5%  (value not drawn)
Катушка индуктивности с керамическим сердечником и  финишным покрытием контактных площадок оловом; Номиналиная индуктивность: 390 нГн; Добротность, не менее: 25; Резонансная частота, не менее: 0.780 ГГц; Сопротивление обмотки постоянноми току, не более: 4.35 Ом; Допустимый ток обмотки: 100 мА; Диапазон рабочих температур: от -60 до +125 ℃; Упаковка: Катушка и лента; Типоразмер: 1608 (0603); Технология монтажа: SMT; Изготовитель: АО "НПО "ЭРКОН"
footprint КИК-1608_О (Катушка индуктивности с керамическим сердечником  типоразмер 1005(0402))
pins: 1, 2

## КИК-1608-390 нГн ±5% Зл
designator L?, comment 390 нГн ±5%  (value not drawn)
Катушка индуктивности с керамическим сердечником и золотым покрытием контактных площадок; Номиналиная индуктивность: 390 нГн; Добротность, не менее: 25; Резонансная частота, не менее: 0.780 ГГц; Сопротивление обмотки постоянноми току, не более: 4.35 Ом; Допустимый ток обмотки: 100 мА; Диапазон рабочих температур: от -60 до +125 ℃; Упаковка: Катушка и лента; Типоразмер: 1608 (0603); Технология монтажа: SMT; Изготовитель: АО "НПО "ЭРКОН"
footprint КИК-1608_Зл (Катушка индуктивности с керамическим сердечником  типоразмер 1005(0402))
pins: 1, 2

## КИК-1608-390 нГн ±10% O
designator L?, comment 390 нГн ±10%  (value not drawn)
Катушка индуктивности с керамическим сердечником и  финишным покрытием контактных площадок оловом; Номиналиная индуктивность: 390 нГн; Добротность, не менее: 25; Резонансная частота, не менее: 0.780 ГГц; Сопротивление обмотки постоянноми току, не более: 4.35 Ом; Допустимый ток обмотки: 100 мА; Диапазон рабочих температур: от -60 до +125 ℃; Упаковка: Катушка и лента; Типоразмер: 1608 (0603); Технология монтажа: SMT; Изготовитель: АО "НПО "ЭРКОН"
footprint КИК-1608_О (Катушка индуктивности с керамическим сердечником  типоразмер 1005(0402))
pins: 1, 2

## КИК-1608-390 нГн ±10% Зл
designator L?, comment 390 нГн ±10%  (value not drawn)
Катушка индуктивности с керамическим сердечником и золотым покрытием контактных площадок; Номиналиная индуктивность: 390 нГн; Добротность, не менее: 25; Резонансная частота, не менее: 0.780 ГГц; Сопротивление обмотки постоянноми току, не более: 4.35 Ом; Допустимый ток обмотки: 100 мА; Диапазон рабочих температур: от -60 до +125 ℃; Упаковка: Катушка и лента; Типоразмер: 1608 (0603); Технология монтажа: SMT; Изготовитель: АО "НПО "ЭРКОН"
footprint КИК-1608_Зл (Катушка индуктивности с керамическим сердечником  типоразмер 1005(0402))
pins: 1, 2

## КИК-1608-390 нГн ±20% O
designator L?, comment 390 нГн ±20%  (value not drawn)
Катушка индуктивности с керамическим сердечником и  финишным покрытием контактных площадок оловом; Номиналиная индуктивность: 390 нГн; Добротность, не менее: 25; Резонансная частота, не менее: 0.780 ГГц; Сопротивление обмотки постоянноми току, не более: 4.35 Ом; Допустимый ток обмотки: 100 мА; Диапазон рабочих температур: от -60 до +125 ℃; Упаковка: Катушка и лента; Типоразмер: 1608 (0603); Технология монтажа: SMT; Изготовитель: АО "НПО "ЭРКОН"
footprint КИК-1608_О (Катушка индуктивности с керамическим сердечником  типоразмер 1005(0402))
pins: 1, 2

## КИК-1608-390 нГн ±20% Зл
designator L?, comment 390 нГн ±20%  (value not drawn)
Катушка индуктивности с керамическим сердечником и золотым покрытием контактных площадок; Номиналиная индуктивность: 390 нГн; Добротность, не менее: 25; Резонансная частота, не менее: 0.780 ГГц; Сопротивление обмотки постоянноми току, не более: 4.35 Ом; Допустимый ток обмотки: 100 мА; Диапазон рабочих температур: от -60 до +125 ℃; Упаковка: Катушка и лента; Типоразмер: 1608 (0603); Технология монтажа: SMT; Изготовитель: АО "НПО "ЭРКОН"
footprint КИК-1608_Зл (Катушка индуктивности с керамическим сердечником  типоразмер 1005(0402))
pins: 1, 2

## КИК-1608-420 нГн ±2% O
designator L?, comment 420 нГн ±2%  (value not drawn)
Катушка индуктивности с керамическим сердечником и  финишным покрытием контактных площадок оловом; Номиналиная индуктивность: 420 нГн; Добротность, не менее: 20; Резонансная частота, не менее: 0.680 ГГц; Сопротивление обмотки постоянноми току, не более: 4.45 Ом; Допустимый ток обмотки: 100 мА; Диапазон рабочих температур: от -60 до +125 ℃; Упаковка: Катушка и лента; Типоразмер: 1608 (0603); Технология монтажа: SMT; Изготовитель: АО "НПО "ЭРКОН"
footprint КИК-1608_О (Катушка индуктивности с керамическим сердечником  типоразмер 1005(0402))
pins: 1, 2

## КИК-1608-420 нГн ±2% Зл
designator L?, comment 420 нГн ±2%  (value not drawn)
Катушка индуктивности с керамическим сердечником и золотым покрытием контактных площадок; Номиналиная индуктивность: 420 нГн; Добротность, не менее: 20; Резонансная частота, не менее: 0.680 ГГц; Сопротивление обмотки постоянноми току, не более: 4.45 Ом; Допустимый ток обмотки: 100 мА; Диапазон рабочих температур: от -60 до +125 ℃; Упаковка: Катушка и лента; Типоразмер: 1608 (0603); Технология монтажа: SMT; Изготовитель: АО "НПО "ЭРКОН"
footprint КИК-1608_Зл (Катушка индуктивности с керамическим сердечником  типоразмер 1005(0402))
pins: 1, 2

## КИК-1608-420 нГн ±5% O
designator L?, comment 420 нГн ±5%  (value not drawn)
Катушка индуктивности с керамическим сердечником и  финишным покрытием контактных площадок оловом; Номиналиная индуктивность: 420 нГн; Добротность, не менее: 20; Резонансная частота, не менее: 0.680 ГГц; Сопротивление обмотки постоянноми току, не более: 4.45 Ом; Допустимый ток обмотки: 100 мА; Диапазон рабочих температур: от -60 до +125 ℃; Упаковка: Катушка и лента; Типоразмер: 1608 (0603); Технология монтажа: SMT; Изготовитель: АО "НПО "ЭРКОН"
footprint КИК-1608_О (Катушка индуктивности с керамическим сердечником  типоразмер 1005(0402))
pins: 1, 2

## КИК-1608-420 нГн ±5% Зл
designator L?, comment 420 нГн ±5%  (value not drawn)
Катушка индуктивности с керамическим сердечником и золотым покрытием контактных площадок; Номиналиная индуктивность: 420 нГн; Добротность, не менее: 20; Резонансная частота, не менее: 0.680 ГГц; Сопротивление обмотки постоянноми току, не более: 4.45 Ом; Допустимый ток обмотки: 100 мА; Диапазон рабочих температур: от -60 до +125 ℃; Упаковка: Катушка и лента; Типоразмер: 1608 (0603); Технология монтажа: SMT; Изготовитель: АО "НПО "ЭРКОН"
footprint КИК-1608_Зл (Катушка индуктивности с керамическим сердечником  типоразмер 1005(0402))
pins: 1, 2

## КИК-1608-420 нГн ±10% Зл
designator L?, comment 420 нГн ±10%  (value not drawn)
Катушка индуктивности с керамическим сердечником и золотым покрытием контактных площадок; Номиналиная индуктивность: 420 нГн; Добротность, не менее: 20; Резонансная частота, не менее: 0.680 ГГц; Сопротивление обмотки постоянноми току, не более: 4.45 Ом; Допустимый ток обмотки: 100 мА; Диапазон рабочих температур: от -60 до +125 ℃; Упаковка: Катушка и лента; Типоразмер: 1608 (0603); Технология монтажа: SMT; Изготовитель: АО "НПО "ЭРКОН"
footprint КИК-1608_Зл (Катушка индуктивности с керамическим сердечником  типоразмер 1005(0402))
pins: 1, 2

## КИК-1608-420 нГн ±10% О
designator L?, comment 420 нГн ±10%  (value not drawn)
Катушка индуктивности с керамическим сердечником и  финишным покрытием контактных площадок оловом; Номиналиная индуктивность: 420 нГн; Добротность, не менее: 20; Резонансная частота, не менее: 0.680 ГГц; Сопротивление обмотки постоянноми току, не более: 4.45 Ом; Допустимый ток обмотки: 100 мА; Диапазон рабочих температур: от -60 до +125 ℃; Упаковка: Катушка и лента; Типоразмер: 1608 (0603); Технология монтажа: SMT; Изготовитель: АО "НПО "ЭРКОН"
footprint КИК-1608_О (Катушка индуктивности с керамическим сердечником  типоразмер 1005(0402))
pins: 1, 2

## КИК-1608-420 нГн ±20% Зл
designator L?, comment 420 нГн ±20%  (value not drawn)
Катушка индуктивности с керамическим сердечником и золотым покрытием контактных площадок; Номиналиная индуктивность: 420 нГн; Добротность, не менее: 20; Резонансная частота, не менее: 0.680 ГГц; Сопротивление обмотки постоянноми току, не более: 4.45 Ом; Допустимый ток обмотки: 100 мА; Диапазон рабочих температур: от -60 до +125 ℃; Упаковка: Катушка и лента; Типоразмер: 1608 (0603); Технология монтажа: SMT; Изготовитель: АО "НПО "ЭРКОН"
footprint КИК-1608_Зл (Катушка индуктивности с керамическим сердечником  типоразмер 1005(0402))
pins: 1, 2

## КИК-1608-420 нГн ±20% О
designator L?, comment 420 нГн ±20%  (value not drawn)
Катушка индуктивности с керамическим сердечником и  финишным покрытием контактных площадок оловом; Номиналиная индуктивность: 420 нГн; Добротность, не менее: 20; Резонансная частота, не менее: 0.680 ГГц; Сопротивление обмотки постоянноми току, не более: 4.45 Ом; Допустимый ток обмотки: 100 мА; Диапазон рабочих температур: от -60 до +125 ℃; Упаковка: Катушка и лента; Типоразмер: 1608 (0603); Технология монтажа: SMT; Изготовитель: АО "НПО "ЭРКОН"
footprint КИК-1608_О (Катушка индуктивности с керамическим сердечником  типоразмер 1005(0402))
pins: 1, 2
